VERSION 5.8 ;
BUSBITCHARS "[]" ;
DIVIDERCHAR "/" ;
UNITS
    DATABASE MICRONS 1000 ;
END UNITS

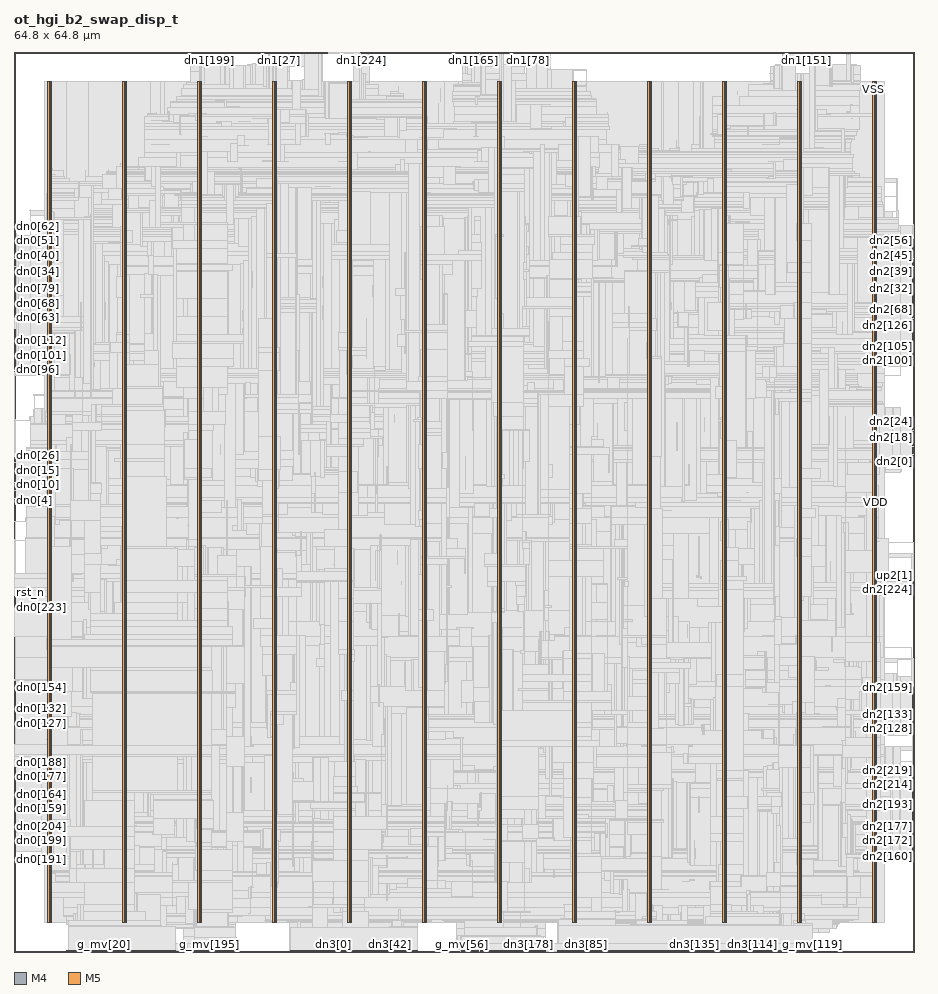
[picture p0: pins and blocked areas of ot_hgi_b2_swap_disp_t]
MACRO ot_hgi_b2_swap_disp_t
  FOREIGN ot_hgi_b2_swap_disp_t 0 0 ;
  CLASS BLOCK ;
  SIZE 64.8 BY 64.8 ;
  PIN clk
    DIRECTION INPUT ;
    USE SIGNAL ;
    PORT
      LAYER M4 ;
        RECT  0 32.592 0.084 32.616 ;
    END
  END clk
  PIN dn0[0]
    DIRECTION OUTPUT ;
    USE SIGNAL ;
    PORT
      LAYER M4 ;
        RECT  0 32.688 0.084 32.712 ;
    END
  END dn0[0]
  PIN dn0[100]
    DIRECTION OUTPUT ;
    USE SIGNAL ;
    PORT
      LAYER M4 ;
        RECT  0 42.288 0.084 42.312 ;
    END
  END dn0[100]
  PIN dn0[101]
    DIRECTION OUTPUT ;
    USE SIGNAL ;
    PORT
      LAYER M4 ;
        RECT  0 42.384 0.084 42.408 ;
    END
  END dn0[101]
  PIN dn0[102]
    DIRECTION OUTPUT ;
    USE SIGNAL ;
    PORT
      LAYER M4 ;
        RECT  0 42.48 0.084 42.504 ;
    END
  END dn0[102]
  PIN dn0[103]
    DIRECTION OUTPUT ;
    USE SIGNAL ;
    PORT
      LAYER M4 ;
        RECT  0 42.576 0.084 42.6 ;
    END
  END dn0[103]
  PIN dn0[104]
    DIRECTION OUTPUT ;
    USE SIGNAL ;
    PORT
      LAYER M4 ;
        RECT  0 42.672 0.084 42.696 ;
    END
  END dn0[104]
  PIN dn0[105]
    DIRECTION OUTPUT ;
    USE SIGNAL ;
    PORT
      LAYER M4 ;
        RECT  0 42.768 0.084 42.792 ;
    END
  END dn0[105]
  PIN dn0[106]
    DIRECTION OUTPUT ;
    USE SIGNAL ;
    PORT
      LAYER M4 ;
        RECT  0 42.864 0.084 42.888 ;
    END
  END dn0[106]
  PIN dn0[107]
    DIRECTION OUTPUT ;
    USE SIGNAL ;
    PORT
      LAYER M4 ;
        RECT  0 42.96 0.084 42.984 ;
    END
  END dn0[107]
  PIN dn0[108]
    DIRECTION OUTPUT ;
    USE SIGNAL ;
    PORT
      LAYER M4 ;
        RECT  0 43.056 0.084 43.08 ;
    END
  END dn0[108]
  PIN dn0[109]
    DIRECTION OUTPUT ;
    USE SIGNAL ;
    PORT
      LAYER M4 ;
        RECT  0 43.152 0.084 43.176 ;
    END
  END dn0[109]
  PIN dn0[10]
    DIRECTION OUTPUT ;
    USE SIGNAL ;
    PORT
      LAYER M4 ;
        RECT  0 33.648 0.084 33.672 ;
    END
  END dn0[10]
  PIN dn0[110]
    DIRECTION OUTPUT ;
    USE SIGNAL ;
    PORT
      LAYER M4 ;
        RECT  0 43.248 0.084 43.272 ;
    END
  END dn0[110]
  PIN dn0[111]
    DIRECTION OUTPUT ;
    USE SIGNAL ;
    PORT
      LAYER M4 ;
        RECT  0 43.344 0.084 43.368 ;
    END
  END dn0[111]
  PIN dn0[112]
    DIRECTION OUTPUT ;
    USE SIGNAL ;
    PORT
      LAYER M4 ;
        RECT  0 43.44 0.084 43.464 ;
    END
  END dn0[112]
  PIN dn0[113]
    DIRECTION OUTPUT ;
    USE SIGNAL ;
    PORT
      LAYER M4 ;
        RECT  0 43.536 0.084 43.56 ;
    END
  END dn0[113]
  PIN dn0[114]
    DIRECTION OUTPUT ;
    USE SIGNAL ;
    PORT
      LAYER M4 ;
        RECT  0 43.632 0.084 43.656 ;
    END
  END dn0[114]
  PIN dn0[115]
    DIRECTION OUTPUT ;
    USE SIGNAL ;
    PORT
      LAYER M4 ;
        RECT  0 43.728 0.084 43.752 ;
    END
  END dn0[115]
  PIN dn0[116]
    DIRECTION OUTPUT ;
    USE SIGNAL ;
    PORT
      LAYER M4 ;
        RECT  0 43.824 0.084 43.848 ;
    END
  END dn0[116]
  PIN dn0[117]
    DIRECTION OUTPUT ;
    USE SIGNAL ;
    PORT
      LAYER M4 ;
        RECT  0 43.92 0.084 43.944 ;
    END
  END dn0[117]
  PIN dn0[118]
    DIRECTION OUTPUT ;
    USE SIGNAL ;
    PORT
      LAYER M4 ;
        RECT  0 44.016 0.084 44.04 ;
    END
  END dn0[118]
  PIN dn0[119]
    DIRECTION OUTPUT ;
    USE SIGNAL ;
    PORT
      LAYER M4 ;
        RECT  0 44.112 0.084 44.136 ;
    END
  END dn0[119]
  PIN dn0[11]
    DIRECTION OUTPUT ;
    USE SIGNAL ;
    PORT
      LAYER M4 ;
        RECT  0 33.744 0.084 33.768 ;
    END
  END dn0[11]
  PIN dn0[120]
    DIRECTION OUTPUT ;
    USE SIGNAL ;
    PORT
      LAYER M4 ;
        RECT  0 44.208 0.084 44.232 ;
    END
  END dn0[120]
  PIN dn0[121]
    DIRECTION OUTPUT ;
    USE SIGNAL ;
    PORT
      LAYER M4 ;
        RECT  0 44.304 0.084 44.328 ;
    END
  END dn0[121]
  PIN dn0[122]
    DIRECTION OUTPUT ;
    USE SIGNAL ;
    PORT
      LAYER M4 ;
        RECT  0 44.4 0.084 44.424 ;
    END
  END dn0[122]
  PIN dn0[123]
    DIRECTION OUTPUT ;
    USE SIGNAL ;
    PORT
      LAYER M4 ;
        RECT  0 44.496 0.084 44.52 ;
    END
  END dn0[123]
  PIN dn0[124]
    DIRECTION OUTPUT ;
    USE SIGNAL ;
    PORT
      LAYER M4 ;
        RECT  0 44.592 0.084 44.616 ;
    END
  END dn0[124]
  PIN dn0[125]
    DIRECTION OUTPUT ;
    USE SIGNAL ;
    PORT
      LAYER M4 ;
        RECT  0 44.688 0.084 44.712 ;
    END
  END dn0[125]
  PIN dn0[126]
    DIRECTION OUTPUT ;
    USE SIGNAL ;
    PORT
      LAYER M4 ;
        RECT  0 44.784 0.084 44.808 ;
    END
  END dn0[126]
  PIN dn0[127]
    DIRECTION OUTPUT ;
    USE SIGNAL ;
    PORT
      LAYER M4 ;
        RECT  0 16.464 0.084 16.488 ;
    END
  END dn0[127]
  PIN dn0[128]
    DIRECTION OUTPUT ;
    USE SIGNAL ;
    PORT
      LAYER M4 ;
        RECT  0 16.56 0.084 16.584 ;
    END
  END dn0[128]
  PIN dn0[129]
    DIRECTION OUTPUT ;
    USE SIGNAL ;
    PORT
      LAYER M4 ;
        RECT  0 16.656 0.084 16.68 ;
    END
  END dn0[129]
  PIN dn0[12]
    DIRECTION OUTPUT ;
    USE SIGNAL ;
    PORT
      LAYER M4 ;
        RECT  0 33.84 0.084 33.864 ;
    END
  END dn0[12]
  PIN dn0[130]
    DIRECTION OUTPUT ;
    USE SIGNAL ;
    PORT
      LAYER M4 ;
        RECT  0 16.752 0.084 16.776 ;
    END
  END dn0[130]
  PIN dn0[131]
    DIRECTION OUTPUT ;
    USE SIGNAL ;
    PORT
      LAYER M4 ;
        RECT  0 16.848 0.084 16.872 ;
    END
  END dn0[131]
  PIN dn0[132]
    DIRECTION OUTPUT ;
    USE SIGNAL ;
    PORT
      LAYER M4 ;
        RECT  0 16.944 0.084 16.968 ;
    END
  END dn0[132]
  PIN dn0[133]
    DIRECTION OUTPUT ;
    USE SIGNAL ;
    PORT
      LAYER M4 ;
        RECT  0 17.04 0.084 17.064 ;
    END
  END dn0[133]
  PIN dn0[134]
    DIRECTION OUTPUT ;
    USE SIGNAL ;
    PORT
      LAYER M4 ;
        RECT  0 17.136 0.084 17.16 ;
    END
  END dn0[134]
  PIN dn0[135]
    DIRECTION OUTPUT ;
    USE SIGNAL ;
    PORT
      LAYER M4 ;
        RECT  0 17.232 0.084 17.256 ;
    END
  END dn0[135]
  PIN dn0[136]
    DIRECTION OUTPUT ;
    USE SIGNAL ;
    PORT
      LAYER M4 ;
        RECT  0 17.328 0.084 17.352 ;
    END
  END dn0[136]
  PIN dn0[137]
    DIRECTION OUTPUT ;
    USE SIGNAL ;
    PORT
      LAYER M4 ;
        RECT  0 17.424 0.084 17.448 ;
    END
  END dn0[137]
  PIN dn0[138]
    DIRECTION OUTPUT ;
    USE SIGNAL ;
    PORT
      LAYER M4 ;
        RECT  0 17.52 0.084 17.544 ;
    END
  END dn0[138]
  PIN dn0[139]
    DIRECTION OUTPUT ;
    USE SIGNAL ;
    PORT
      LAYER M4 ;
        RECT  0 17.616 0.084 17.64 ;
    END
  END dn0[139]
  PIN dn0[13]
    DIRECTION OUTPUT ;
    USE SIGNAL ;
    PORT
      LAYER M4 ;
        RECT  0 33.936 0.084 33.96 ;
    END
  END dn0[13]
  PIN dn0[140]
    DIRECTION OUTPUT ;
    USE SIGNAL ;
    PORT
      LAYER M4 ;
        RECT  0 17.712 0.084 17.736 ;
    END
  END dn0[140]
  PIN dn0[141]
    DIRECTION OUTPUT ;
    USE SIGNAL ;
    PORT
      LAYER M4 ;
        RECT  0 17.808 0.084 17.832 ;
    END
  END dn0[141]
  PIN dn0[142]
    DIRECTION OUTPUT ;
    USE SIGNAL ;
    PORT
      LAYER M4 ;
        RECT  0 17.904 0.084 17.928 ;
    END
  END dn0[142]
  PIN dn0[143]
    DIRECTION OUTPUT ;
    USE SIGNAL ;
    PORT
      LAYER M4 ;
        RECT  0 18 0.084 18.024 ;
    END
  END dn0[143]
  PIN dn0[144]
    DIRECTION OUTPUT ;
    USE SIGNAL ;
    PORT
      LAYER M4 ;
        RECT  0 18.096 0.084 18.12 ;
    END
  END dn0[144]
  PIN dn0[145]
    DIRECTION OUTPUT ;
    USE SIGNAL ;
    PORT
      LAYER M4 ;
        RECT  0 18.192 0.084 18.216 ;
    END
  END dn0[145]
  PIN dn0[146]
    DIRECTION OUTPUT ;
    USE SIGNAL ;
    PORT
      LAYER M4 ;
        RECT  0 18.288 0.084 18.312 ;
    END
  END dn0[146]
  PIN dn0[147]
    DIRECTION OUTPUT ;
    USE SIGNAL ;
    PORT
      LAYER M4 ;
        RECT  0 18.384 0.084 18.408 ;
    END
  END dn0[147]
  PIN dn0[148]
    DIRECTION OUTPUT ;
    USE SIGNAL ;
    PORT
      LAYER M4 ;
        RECT  0 18.48 0.084 18.504 ;
    END
  END dn0[148]
  PIN dn0[149]
    DIRECTION OUTPUT ;
    USE SIGNAL ;
    PORT
      LAYER M4 ;
        RECT  0 18.576 0.084 18.6 ;
    END
  END dn0[149]
  PIN dn0[14]
    DIRECTION OUTPUT ;
    USE SIGNAL ;
    PORT
      LAYER M4 ;
        RECT  0 34.032 0.084 34.056 ;
    END
  END dn0[14]
  PIN dn0[150]
    DIRECTION OUTPUT ;
    USE SIGNAL ;
    PORT
      LAYER M4 ;
        RECT  0 18.672 0.084 18.696 ;
    END
  END dn0[150]
  PIN dn0[151]
    DIRECTION OUTPUT ;
    USE SIGNAL ;
    PORT
      LAYER M4 ;
        RECT  0 18.768 0.084 18.792 ;
    END
  END dn0[151]
  PIN dn0[152]
    DIRECTION OUTPUT ;
    USE SIGNAL ;
    PORT
      LAYER M4 ;
        RECT  0 18.864 0.084 18.888 ;
    END
  END dn0[152]
  PIN dn0[153]
    DIRECTION OUTPUT ;
    USE SIGNAL ;
    PORT
      LAYER M4 ;
        RECT  0 18.96 0.084 18.984 ;
    END
  END dn0[153]
  PIN dn0[154]
    DIRECTION OUTPUT ;
    USE SIGNAL ;
    PORT
      LAYER M4 ;
        RECT  0 19.056 0.084 19.08 ;
    END
  END dn0[154]
  PIN dn0[155]
    DIRECTION OUTPUT ;
    USE SIGNAL ;
    PORT
      LAYER M4 ;
        RECT  0 19.152 0.084 19.176 ;
    END
  END dn0[155]
  PIN dn0[156]
    DIRECTION OUTPUT ;
    USE SIGNAL ;
    PORT
      LAYER M4 ;
        RECT  0 19.248 0.084 19.272 ;
    END
  END dn0[156]
  PIN dn0[157]
    DIRECTION OUTPUT ;
    USE SIGNAL ;
    PORT
      LAYER M4 ;
        RECT  0 19.344 0.084 19.368 ;
    END
  END dn0[157]
  PIN dn0[158]
    DIRECTION OUTPUT ;
    USE SIGNAL ;
    PORT
      LAYER M4 ;
        RECT  0 19.44 0.084 19.464 ;
    END
  END dn0[158]
  PIN dn0[159]
    DIRECTION OUTPUT ;
    USE SIGNAL ;
    PORT
      LAYER M4 ;
        RECT  0 10.32 0.084 10.344 ;
    END
  END dn0[159]
  PIN dn0[15]
    DIRECTION OUTPUT ;
    USE SIGNAL ;
    PORT
      LAYER M4 ;
        RECT  0 34.128 0.084 34.152 ;
    END
  END dn0[15]
  PIN dn0[160]
    DIRECTION OUTPUT ;
    USE SIGNAL ;
    PORT
      LAYER M4 ;
        RECT  0 10.416 0.084 10.44 ;
    END
  END dn0[160]
  PIN dn0[161]
    DIRECTION OUTPUT ;
    USE SIGNAL ;
    PORT
      LAYER M4 ;
        RECT  0 10.512 0.084 10.536 ;
    END
  END dn0[161]
  PIN dn0[162]
    DIRECTION OUTPUT ;
    USE SIGNAL ;
    PORT
      LAYER M4 ;
        RECT  0 10.608 0.084 10.632 ;
    END
  END dn0[162]
  PIN dn0[163]
    DIRECTION OUTPUT ;
    USE SIGNAL ;
    PORT
      LAYER M4 ;
        RECT  0 10.704 0.084 10.728 ;
    END
  END dn0[163]
  PIN dn0[164]
    DIRECTION OUTPUT ;
    USE SIGNAL ;
    PORT
      LAYER M4 ;
        RECT  0 10.8 0.084 10.824 ;
    END
  END dn0[164]
  PIN dn0[165]
    DIRECTION OUTPUT ;
    USE SIGNAL ;
    PORT
      LAYER M4 ;
        RECT  0 10.896 0.084 10.92 ;
    END
  END dn0[165]
  PIN dn0[166]
    DIRECTION OUTPUT ;
    USE SIGNAL ;
    PORT
      LAYER M4 ;
        RECT  0 10.992 0.084 11.016 ;
    END
  END dn0[166]
  PIN dn0[167]
    DIRECTION OUTPUT ;
    USE SIGNAL ;
    PORT
      LAYER M4 ;
        RECT  0 11.088 0.084 11.112 ;
    END
  END dn0[167]
  PIN dn0[168]
    DIRECTION OUTPUT ;
    USE SIGNAL ;
    PORT
      LAYER M4 ;
        RECT  0 11.184 0.084 11.208 ;
    END
  END dn0[168]
  PIN dn0[169]
    DIRECTION OUTPUT ;
    USE SIGNAL ;
    PORT
      LAYER M4 ;
        RECT  0 11.28 0.084 11.304 ;
    END
  END dn0[169]
  PIN dn0[16]
    DIRECTION OUTPUT ;
    USE SIGNAL ;
    PORT
      LAYER M4 ;
        RECT  0 34.224 0.084 34.248 ;
    END
  END dn0[16]
  PIN dn0[170]
    DIRECTION OUTPUT ;
    USE SIGNAL ;
    PORT
      LAYER M4 ;
        RECT  0 11.376 0.084 11.4 ;
    END
  END dn0[170]
  PIN dn0[171]
    DIRECTION OUTPUT ;
    USE SIGNAL ;
    PORT
      LAYER M4 ;
        RECT  0 11.472 0.084 11.496 ;
    END
  END dn0[171]
  PIN dn0[172]
    DIRECTION OUTPUT ;
    USE SIGNAL ;
    PORT
      LAYER M4 ;
        RECT  0 11.568 0.084 11.592 ;
    END
  END dn0[172]
  PIN dn0[173]
    DIRECTION OUTPUT ;
    USE SIGNAL ;
    PORT
      LAYER M4 ;
        RECT  0 11.664 0.084 11.688 ;
    END
  END dn0[173]
  PIN dn0[174]
    DIRECTION OUTPUT ;
    USE SIGNAL ;
    PORT
      LAYER M4 ;
        RECT  0 11.76 0.084 11.784 ;
    END
  END dn0[174]
  PIN dn0[175]
    DIRECTION OUTPUT ;
    USE SIGNAL ;
    PORT
      LAYER M4 ;
        RECT  0 11.856 0.084 11.88 ;
    END
  END dn0[175]
  PIN dn0[176]
    DIRECTION OUTPUT ;
    USE SIGNAL ;
    PORT
      LAYER M4 ;
        RECT  0 11.952 0.084 11.976 ;
    END
  END dn0[176]
  PIN dn0[177]
    DIRECTION OUTPUT ;
    USE SIGNAL ;
    PORT
      LAYER M4 ;
        RECT  0 12.048 0.084 12.072 ;
    END
  END dn0[177]
  PIN dn0[178]
    DIRECTION OUTPUT ;
    USE SIGNAL ;
    PORT
      LAYER M4 ;
        RECT  0 12.144 0.084 12.168 ;
    END
  END dn0[178]
  PIN dn0[179]
    DIRECTION OUTPUT ;
    USE SIGNAL ;
    PORT
      LAYER M4 ;
        RECT  0 12.24 0.084 12.264 ;
    END
  END dn0[179]
  PIN dn0[17]
    DIRECTION OUTPUT ;
    USE SIGNAL ;
    PORT
      LAYER M4 ;
        RECT  0 34.32 0.084 34.344 ;
    END
  END dn0[17]
  PIN dn0[180]
    DIRECTION OUTPUT ;
    USE SIGNAL ;
    PORT
      LAYER M4 ;
        RECT  0 12.336 0.084 12.36 ;
    END
  END dn0[180]
  PIN dn0[181]
    DIRECTION OUTPUT ;
    USE SIGNAL ;
    PORT
      LAYER M4 ;
        RECT  0 12.432 0.084 12.456 ;
    END
  END dn0[181]
  PIN dn0[182]
    DIRECTION OUTPUT ;
    USE SIGNAL ;
    PORT
      LAYER M4 ;
        RECT  0 12.528 0.084 12.552 ;
    END
  END dn0[182]
  PIN dn0[183]
    DIRECTION OUTPUT ;
    USE SIGNAL ;
    PORT
      LAYER M4 ;
        RECT  0 12.624 0.084 12.648 ;
    END
  END dn0[183]
  PIN dn0[184]
    DIRECTION OUTPUT ;
    USE SIGNAL ;
    PORT
      LAYER M4 ;
        RECT  0 12.72 0.084 12.744 ;
    END
  END dn0[184]
  PIN dn0[185]
    DIRECTION OUTPUT ;
    USE SIGNAL ;
    PORT
      LAYER M4 ;
        RECT  0 12.816 0.084 12.84 ;
    END
  END dn0[185]
  PIN dn0[186]
    DIRECTION OUTPUT ;
    USE SIGNAL ;
    PORT
      LAYER M4 ;
        RECT  0 12.912 0.084 12.936 ;
    END
  END dn0[186]
  PIN dn0[187]
    DIRECTION OUTPUT ;
    USE SIGNAL ;
    PORT
      LAYER M4 ;
        RECT  0 13.008 0.084 13.032 ;
    END
  END dn0[187]
  PIN dn0[188]
    DIRECTION OUTPUT ;
    USE SIGNAL ;
    PORT
      LAYER M4 ;
        RECT  0 13.104 0.084 13.128 ;
    END
  END dn0[188]
  PIN dn0[189]
    DIRECTION OUTPUT ;
    USE SIGNAL ;
    PORT
      LAYER M4 ;
        RECT  0 13.2 0.084 13.224 ;
    END
  END dn0[189]
  PIN dn0[18]
    DIRECTION OUTPUT ;
    USE SIGNAL ;
    PORT
      LAYER M4 ;
        RECT  0 34.416 0.084 34.44 ;
    END
  END dn0[18]
  PIN dn0[190]
    DIRECTION OUTPUT ;
    USE SIGNAL ;
    PORT
      LAYER M4 ;
        RECT  0 13.296 0.084 13.32 ;
    END
  END dn0[190]
  PIN dn0[191]
    DIRECTION OUTPUT ;
    USE SIGNAL ;
    PORT
      LAYER M4 ;
        RECT  0 7.248 0.084 7.272 ;
    END
  END dn0[191]
  PIN dn0[192]
    DIRECTION OUTPUT ;
    USE SIGNAL ;
    PORT
      LAYER M4 ;
        RECT  0 7.344 0.084 7.368 ;
    END
  END dn0[192]
  PIN dn0[193]
    DIRECTION OUTPUT ;
    USE SIGNAL ;
    PORT
      LAYER M4 ;
        RECT  0 7.44 0.084 7.464 ;
    END
  END dn0[193]
  PIN dn0[194]
    DIRECTION OUTPUT ;
    USE SIGNAL ;
    PORT
      LAYER M4 ;
        RECT  0 7.536 0.084 7.56 ;
    END
  END dn0[194]
  PIN dn0[195]
    DIRECTION OUTPUT ;
    USE SIGNAL ;
    PORT
      LAYER M4 ;
        RECT  0 7.632 0.084 7.656 ;
    END
  END dn0[195]
  PIN dn0[196]
    DIRECTION OUTPUT ;
    USE SIGNAL ;
    PORT
      LAYER M4 ;
        RECT  0 7.728 0.084 7.752 ;
    END
  END dn0[196]
  PIN dn0[197]
    DIRECTION OUTPUT ;
    USE SIGNAL ;
    PORT
      LAYER M4 ;
        RECT  0 7.824 0.084 7.848 ;
    END
  END dn0[197]
  PIN dn0[198]
    DIRECTION OUTPUT ;
    USE SIGNAL ;
    PORT
      LAYER M4 ;
        RECT  0 7.92 0.084 7.944 ;
    END
  END dn0[198]
  PIN dn0[199]
    DIRECTION OUTPUT ;
    USE SIGNAL ;
    PORT
      LAYER M4 ;
        RECT  0 8.016 0.084 8.04 ;
    END
  END dn0[199]
  PIN dn0[19]
    DIRECTION OUTPUT ;
    USE SIGNAL ;
    PORT
      LAYER M4 ;
        RECT  0 34.512 0.084 34.536 ;
    END
  END dn0[19]
  PIN dn0[1]
    DIRECTION OUTPUT ;
    USE SIGNAL ;
    PORT
      LAYER M4 ;
        RECT  0 32.784 0.084 32.808 ;
    END
  END dn0[1]
  PIN dn0[200]
    DIRECTION OUTPUT ;
    USE SIGNAL ;
    PORT
      LAYER M4 ;
        RECT  0 8.112 0.084 8.136 ;
    END
  END dn0[200]
  PIN dn0[201]
    DIRECTION OUTPUT ;
    USE SIGNAL ;
    PORT
      LAYER M4 ;
        RECT  0 8.208 0.084 8.232 ;
    END
  END dn0[201]
  PIN dn0[202]
    DIRECTION OUTPUT ;
    USE SIGNAL ;
    PORT
      LAYER M4 ;
        RECT  0 8.304 0.084 8.328 ;
    END
  END dn0[202]
  PIN dn0[203]
    DIRECTION OUTPUT ;
    USE SIGNAL ;
    PORT
      LAYER M4 ;
        RECT  0 8.4 0.084 8.424 ;
    END
  END dn0[203]
  PIN dn0[204]
    DIRECTION OUTPUT ;
    USE SIGNAL ;
    PORT
      LAYER M4 ;
        RECT  0 8.496 0.084 8.52 ;
    END
  END dn0[204]
  PIN dn0[205]
    DIRECTION OUTPUT ;
    USE SIGNAL ;
    PORT
      LAYER M4 ;
        RECT  0 8.592 0.084 8.616 ;
    END
  END dn0[205]
  PIN dn0[206]
    DIRECTION OUTPUT ;
    USE SIGNAL ;
    PORT
      LAYER M4 ;
        RECT  0 8.688 0.084 8.712 ;
    END
  END dn0[206]
  PIN dn0[207]
    DIRECTION OUTPUT ;
    USE SIGNAL ;
    PORT
      LAYER M4 ;
        RECT  0 8.784 0.084 8.808 ;
    END
  END dn0[207]
  PIN dn0[208]
    DIRECTION OUTPUT ;
    USE SIGNAL ;
    PORT
      LAYER M4 ;
        RECT  0 8.88 0.084 8.904 ;
    END
  END dn0[208]
  PIN dn0[209]
    DIRECTION OUTPUT ;
    USE SIGNAL ;
    PORT
      LAYER M4 ;
        RECT  0 8.976 0.084 9 ;
    END
  END dn0[209]
  PIN dn0[20]
    DIRECTION OUTPUT ;
    USE SIGNAL ;
    PORT
      LAYER M4 ;
        RECT  0 34.608 0.084 34.632 ;
    END
  END dn0[20]
  PIN dn0[210]
    DIRECTION OUTPUT ;
    USE SIGNAL ;
    PORT
      LAYER M4 ;
        RECT  0 9.072 0.084 9.096 ;
    END
  END dn0[210]
  PIN dn0[211]
    DIRECTION OUTPUT ;
    USE SIGNAL ;
    PORT
      LAYER M4 ;
        RECT  0 9.168 0.084 9.192 ;
    END
  END dn0[211]
  PIN dn0[212]
    DIRECTION OUTPUT ;
    USE SIGNAL ;
    PORT
      LAYER M4 ;
        RECT  0 9.264 0.084 9.288 ;
    END
  END dn0[212]
  PIN dn0[213]
    DIRECTION OUTPUT ;
    USE SIGNAL ;
    PORT
      LAYER M4 ;
        RECT  0 9.36 0.084 9.384 ;
    END
  END dn0[213]
  PIN dn0[214]
    DIRECTION OUTPUT ;
    USE SIGNAL ;
    PORT
      LAYER M4 ;
        RECT  0 9.456 0.084 9.48 ;
    END
  END dn0[214]
  PIN dn0[215]
    DIRECTION OUTPUT ;
    USE SIGNAL ;
    PORT
      LAYER M4 ;
        RECT  0 9.552 0.084 9.576 ;
    END
  END dn0[215]
  PIN dn0[216]
    DIRECTION OUTPUT ;
    USE SIGNAL ;
    PORT
      LAYER M4 ;
        RECT  0 9.648 0.084 9.672 ;
    END
  END dn0[216]
  PIN dn0[217]
    DIRECTION OUTPUT ;
    USE SIGNAL ;
    PORT
      LAYER M4 ;
        RECT  0 9.744 0.084 9.768 ;
    END
  END dn0[217]
  PIN dn0[218]
    DIRECTION OUTPUT ;
    USE SIGNAL ;
    PORT
      LAYER M4 ;
        RECT  0 9.84 0.084 9.864 ;
    END
  END dn0[218]
  PIN dn0[219]
    DIRECTION OUTPUT ;
    USE SIGNAL ;
    PORT
      LAYER M4 ;
        RECT  0 9.936 0.084 9.96 ;
    END
  END dn0[219]
  PIN dn0[21]
    DIRECTION OUTPUT ;
    USE SIGNAL ;
    PORT
      LAYER M4 ;
        RECT  0 34.704 0.084 34.728 ;
    END
  END dn0[21]
  PIN dn0[220]
    DIRECTION OUTPUT ;
    USE SIGNAL ;
    PORT
      LAYER M4 ;
        RECT  0 10.032 0.084 10.056 ;
    END
  END dn0[220]
  PIN dn0[221]
    DIRECTION OUTPUT ;
    USE SIGNAL ;
    PORT
      LAYER M4 ;
        RECT  0 10.128 0.084 10.152 ;
    END
  END dn0[221]
  PIN dn0[222]
    DIRECTION OUTPUT ;
    USE SIGNAL ;
    PORT
      LAYER M4 ;
        RECT  0 10.224 0.084 10.248 ;
    END
  END dn0[222]
  PIN dn0[223]
    DIRECTION OUTPUT ;
    USE SIGNAL ;
    PORT
      LAYER M4 ;
        RECT  0 24.816 0.084 24.84 ;
    END
  END dn0[223]
  PIN dn0[224]
    DIRECTION OUTPUT ;
    USE SIGNAL ;
    PORT
      LAYER M4 ;
        RECT  0 24.912 0.084 24.936 ;
    END
  END dn0[224]
  PIN dn0[225]
    DIRECTION OUTPUT ;
    USE SIGNAL ;
    PORT
      LAYER M4 ;
        RECT  0 25.008 0.084 25.032 ;
    END
  END dn0[225]
  PIN dn0[226]
    DIRECTION OUTPUT ;
    USE SIGNAL ;
    PORT
      LAYER M4 ;
        RECT  0 25.104 0.084 25.128 ;
    END
  END dn0[226]
  PIN dn0[227]
    DIRECTION OUTPUT ;
    USE SIGNAL ;
    PORT
      LAYER M4 ;
        RECT  0 25.2 0.084 25.224 ;
    END
  END dn0[227]
  PIN dn0[22]
    DIRECTION OUTPUT ;
    USE SIGNAL ;
    PORT
      LAYER M4 ;
        RECT  0 34.8 0.084 34.824 ;
    END
  END dn0[22]
  PIN dn0[23]
    DIRECTION OUTPUT ;
    USE SIGNAL ;
    PORT
      LAYER M4 ;
        RECT  0 34.896 0.084 34.92 ;
    END
  END dn0[23]
  PIN dn0[24]
    DIRECTION OUTPUT ;
    USE SIGNAL ;
    PORT
      LAYER M4 ;
        RECT  0 34.992 0.084 35.016 ;
    END
  END dn0[24]
  PIN dn0[25]
    DIRECTION OUTPUT ;
    USE SIGNAL ;
    PORT
      LAYER M4 ;
        RECT  0 35.088 0.084 35.112 ;
    END
  END dn0[25]
  PIN dn0[26]
    DIRECTION OUTPUT ;
    USE SIGNAL ;
    PORT
      LAYER M4 ;
        RECT  0 35.184 0.084 35.208 ;
    END
  END dn0[26]
  PIN dn0[27]
    DIRECTION OUTPUT ;
    USE SIGNAL ;
    PORT
      LAYER M4 ;
        RECT  0 35.28 0.084 35.304 ;
    END
  END dn0[27]
  PIN dn0[28]
    DIRECTION OUTPUT ;
    USE SIGNAL ;
    PORT
      LAYER M4 ;
        RECT  0 35.376 0.084 35.4 ;
    END
  END dn0[28]
  PIN dn0[29]
    DIRECTION OUTPUT ;
    USE SIGNAL ;
    PORT
      LAYER M4 ;
        RECT  0 35.472 0.084 35.496 ;
    END
  END dn0[29]
  PIN dn0[2]
    DIRECTION OUTPUT ;
    USE SIGNAL ;
    PORT
      LAYER M4 ;
        RECT  0 32.88 0.084 32.904 ;
    END
  END dn0[2]
  PIN dn0[30]
    DIRECTION OUTPUT ;
    USE SIGNAL ;
    PORT
      LAYER M4 ;
        RECT  0 35.568 0.084 35.592 ;
    END
  END dn0[30]
  PIN dn0[31]
    DIRECTION OUTPUT ;
    USE SIGNAL ;
    PORT
      LAYER M4 ;
        RECT  0 48.72 0.084 48.744 ;
    END
  END dn0[31]
  PIN dn0[32]
    DIRECTION OUTPUT ;
    USE SIGNAL ;
    PORT
      LAYER M4 ;
        RECT  0 48.816 0.084 48.84 ;
    END
  END dn0[32]
  PIN dn0[33]
    DIRECTION OUTPUT ;
    USE SIGNAL ;
    PORT
      LAYER M4 ;
        RECT  0 48.912 0.084 48.936 ;
    END
  END dn0[33]
  PIN dn0[34]
    DIRECTION OUTPUT ;
    USE SIGNAL ;
    PORT
      LAYER M4 ;
        RECT  0 49.008 0.084 49.032 ;
    END
  END dn0[34]
  PIN dn0[35]
    DIRECTION OUTPUT ;
    USE SIGNAL ;
    PORT
      LAYER M4 ;
        RECT  0 49.104 0.084 49.128 ;
    END
  END dn0[35]
  PIN dn0[36]
    DIRECTION OUTPUT ;
    USE SIGNAL ;
    PORT
      LAYER M4 ;
        RECT  0 49.2 0.084 49.224 ;
    END
  END dn0[36]
  PIN dn0[37]
    DIRECTION OUTPUT ;
    USE SIGNAL ;
    PORT
      LAYER M4 ;
        RECT  0 49.296 0.084 49.32 ;
    END
  END dn0[37]
  PIN dn0[38]
    DIRECTION OUTPUT ;
    USE SIGNAL ;
    PORT
      LAYER M4 ;
        RECT  0 49.392 0.084 49.416 ;
    END
  END dn0[38]
  PIN dn0[39]
    DIRECTION OUTPUT ;
    USE SIGNAL ;
    PORT
      LAYER M4 ;
        RECT  0 49.488 0.084 49.512 ;
    END
  END dn0[39]
  PIN dn0[3]
    DIRECTION OUTPUT ;
    USE SIGNAL ;
    PORT
      LAYER M4 ;
        RECT  0 32.976 0.084 33 ;
    END
  END dn0[3]
  PIN dn0[40]
    DIRECTION OUTPUT ;
    USE SIGNAL ;
    PORT
      LAYER M4 ;
        RECT  0 49.584 0.084 49.608 ;
    END
  END dn0[40]
  PIN dn0[41]
    DIRECTION OUTPUT ;
    USE SIGNAL ;
    PORT
      LAYER M4 ;
        RECT  0 49.68 0.084 49.704 ;
    END
  END dn0[41]
  PIN dn0[42]
    DIRECTION OUTPUT ;
    USE SIGNAL ;
    PORT
      LAYER M4 ;
        RECT  0 49.776 0.084 49.8 ;
    END
  END dn0[42]
  PIN dn0[43]
    DIRECTION OUTPUT ;
    USE SIGNAL ;
    PORT
      LAYER M4 ;
        RECT  0 49.872 0.084 49.896 ;
    END
  END dn0[43]
  PIN dn0[44]
    DIRECTION OUTPUT ;
    USE SIGNAL ;
    PORT
      LAYER M4 ;
        RECT  0 49.968 0.084 49.992 ;
    END
  END dn0[44]
  PIN dn0[45]
    DIRECTION OUTPUT ;
    USE SIGNAL ;
    PORT
      LAYER M4 ;
        RECT  0 50.064 0.084 50.088 ;
    END
  END dn0[45]
  PIN dn0[46]
    DIRECTION OUTPUT ;
    USE SIGNAL ;
    PORT
      LAYER M4 ;
        RECT  0 50.16 0.084 50.184 ;
    END
  END dn0[46]
  PIN dn0[47]
    DIRECTION OUTPUT ;
    USE SIGNAL ;
    PORT
      LAYER M4 ;
        RECT  0 50.256 0.084 50.28 ;
    END
  END dn0[47]
  PIN dn0[48]
    DIRECTION OUTPUT ;
    USE SIGNAL ;
    PORT
      LAYER M4 ;
        RECT  0 50.352 0.084 50.376 ;
    END
  END dn0[48]
  PIN dn0[49]
    DIRECTION OUTPUT ;
    USE SIGNAL ;
    PORT
      LAYER M4 ;
        RECT  0 50.448 0.084 50.472 ;
    END
  END dn0[49]
  PIN dn0[4]
    DIRECTION OUTPUT ;
    USE SIGNAL ;
    PORT
      LAYER M4 ;
        RECT  0 33.072 0.084 33.096 ;
    END
  END dn0[4]
  PIN dn0[50]
    DIRECTION OUTPUT ;
    USE SIGNAL ;
    PORT
      LAYER M4 ;
        RECT  0 50.544 0.084 50.568 ;
    END
  END dn0[50]
  PIN dn0[51]
    DIRECTION OUTPUT ;
    USE SIGNAL ;
    PORT
      LAYER M4 ;
        RECT  0 50.64 0.084 50.664 ;
    END
  END dn0[51]
  PIN dn0[52]
    DIRECTION OUTPUT ;
    USE SIGNAL ;
    PORT
      LAYER M4 ;
        RECT  0 50.736 0.084 50.76 ;
    END
  END dn0[52]
  PIN dn0[53]
    DIRECTION OUTPUT ;
    USE SIGNAL ;
    PORT
      LAYER M4 ;
        RECT  0 50.832 0.084 50.856 ;
    END
  END dn0[53]
  PIN dn0[54]
    DIRECTION OUTPUT ;
    USE SIGNAL ;
    PORT
      LAYER M4 ;
        RECT  0 50.928 0.084 50.952 ;
    END
  END dn0[54]
  PIN dn0[55]
    DIRECTION OUTPUT ;
    USE SIGNAL ;
    PORT
      LAYER M4 ;
        RECT  0 51.024 0.084 51.048 ;
    END
  END dn0[55]
  PIN dn0[56]
    DIRECTION OUTPUT ;
    USE SIGNAL ;
    PORT
      LAYER M4 ;
        RECT  0 51.12 0.084 51.144 ;
    END
  END dn0[56]
  PIN dn0[57]
    DIRECTION OUTPUT ;
    USE SIGNAL ;
    PORT
      LAYER M4 ;
        RECT  0 51.216 0.084 51.24 ;
    END
  END dn0[57]
  PIN dn0[58]
    DIRECTION OUTPUT ;
    USE SIGNAL ;
    PORT
      LAYER M4 ;
        RECT  0 51.312 0.084 51.336 ;
    END
  END dn0[58]
  PIN dn0[59]
    DIRECTION OUTPUT ;
    USE SIGNAL ;
    PORT
      LAYER M4 ;
        RECT  0 51.408 0.084 51.432 ;
    END
  END dn0[59]
  PIN dn0[5]
    DIRECTION OUTPUT ;
    USE SIGNAL ;
    PORT
      LAYER M4 ;
        RECT  0 33.168 0.084 33.192 ;
    END
  END dn0[5]
  PIN dn0[60]
    DIRECTION OUTPUT ;
    USE SIGNAL ;
    PORT
      LAYER M4 ;
        RECT  0 51.504 0.084 51.528 ;
    END
  END dn0[60]
  PIN dn0[61]
    DIRECTION OUTPUT ;
    USE SIGNAL ;
    PORT
      LAYER M4 ;
        RECT  0 51.6 0.084 51.624 ;
    END
  END dn0[61]
  PIN dn0[62]
    DIRECTION OUTPUT ;
    USE SIGNAL ;
    PORT
      LAYER M4 ;
        RECT  0 51.696 0.084 51.72 ;
    END
  END dn0[62]
  PIN dn0[63]
    DIRECTION OUTPUT ;
    USE SIGNAL ;
    PORT
      LAYER M4 ;
        RECT  0 45.648 0.084 45.672 ;
    END
  END dn0[63]
  PIN dn0[64]
    DIRECTION OUTPUT ;
    USE SIGNAL ;
    PORT
      LAYER M4 ;
        RECT  0 45.744 0.084 45.768 ;
    END
  END dn0[64]
  PIN dn0[65]
    DIRECTION OUTPUT ;
    USE SIGNAL ;
    PORT
      LAYER M4 ;
        RECT  0 45.84 0.084 45.864 ;
    END
  END dn0[65]
  PIN dn0[66]
    DIRECTION OUTPUT ;
    USE SIGNAL ;
    PORT
      LAYER M4 ;
        RECT  0 45.936 0.084 45.96 ;
    END
  END dn0[66]
  PIN dn0[67]
    DIRECTION OUTPUT ;
    USE SIGNAL ;
    PORT
      LAYER M4 ;
        RECT  0 46.032 0.084 46.056 ;
    END
  END dn0[67]
  PIN dn0[68]
    DIRECTION OUTPUT ;
    USE SIGNAL ;
    PORT
      LAYER M4 ;
        RECT  0 46.128 0.084 46.152 ;
    END
  END dn0[68]
  PIN dn0[69]
    DIRECTION OUTPUT ;
    USE SIGNAL ;
    PORT
      LAYER M4 ;
        RECT  0 46.224 0.084 46.248 ;
    END
  END dn0[69]
  PIN dn0[6]
    DIRECTION OUTPUT ;
    USE SIGNAL ;
    PORT
      LAYER M4 ;
        RECT  0 33.264 0.084 33.288 ;
    END
  END dn0[6]
  PIN dn0[70]
    DIRECTION OUTPUT ;
    USE SIGNAL ;
    PORT
      LAYER M4 ;
        RECT  0 46.32 0.084 46.344 ;
    END
  END dn0[70]
  PIN dn0[71]
    DIRECTION OUTPUT ;
    USE SIGNAL ;
    PORT
      LAYER M4 ;
        RECT  0 46.416 0.084 46.44 ;
    END
  END dn0[71]
  PIN dn0[72]
    DIRECTION OUTPUT ;
    USE SIGNAL ;
    PORT
      LAYER M4 ;
        RECT  0 46.512 0.084 46.536 ;
    END
  END dn0[72]
  PIN dn0[73]
    DIRECTION OUTPUT ;
    USE SIGNAL ;
    PORT
      LAYER M4 ;
        RECT  0 46.608 0.084 46.632 ;
    END
  END dn0[73]
  PIN dn0[74]
    DIRECTION OUTPUT ;
    USE SIGNAL ;
    PORT
      LAYER M4 ;
        RECT  0 46.704 0.084 46.728 ;
    END
  END dn0[74]
  PIN dn0[75]
    DIRECTION OUTPUT ;
    USE SIGNAL ;
    PORT
      LAYER M4 ;
        RECT  0 46.8 0.084 46.824 ;
    END
  END dn0[75]
  PIN dn0[76]
    DIRECTION OUTPUT ;
    USE SIGNAL ;
    PORT
      LAYER M4 ;
        RECT  0 46.896 0.084 46.92 ;
    END
  END dn0[76]
  PIN dn0[77]
    DIRECTION OUTPUT ;
    USE SIGNAL ;
    PORT
      LAYER M4 ;
        RECT  0 46.992 0.084 47.016 ;
    END
  END dn0[77]
  PIN dn0[78]
    DIRECTION OUTPUT ;
    USE SIGNAL ;
    PORT
      LAYER M4 ;
        RECT  0 47.088 0.084 47.112 ;
    END
  END dn0[78]
  PIN dn0[79]
    DIRECTION OUTPUT ;
    USE SIGNAL ;
    PORT
      LAYER M4 ;
        RECT  0 47.184 0.084 47.208 ;
    END
  END dn0[79]
  PIN dn0[7]
    DIRECTION OUTPUT ;
    USE SIGNAL ;
    PORT
      LAYER M4 ;
        RECT  0 33.36 0.084 33.384 ;
    END
  END dn0[7]
  PIN dn0[80]
    DIRECTION OUTPUT ;
    USE SIGNAL ;
    PORT
      LAYER M4 ;
        RECT  0 47.28 0.084 47.304 ;
    END
  END dn0[80]
  PIN dn0[81]
    DIRECTION OUTPUT ;
    USE SIGNAL ;
    PORT
      LAYER M4 ;
        RECT  0 47.376 0.084 47.4 ;
    END
  END dn0[81]
  PIN dn0[82]
    DIRECTION OUTPUT ;
    USE SIGNAL ;
    PORT
      LAYER M4 ;
        RECT  0 47.472 0.084 47.496 ;
    END
  END dn0[82]
  PIN dn0[83]
    DIRECTION OUTPUT ;
    USE SIGNAL ;
    PORT
      LAYER M4 ;
        RECT  0 47.568 0.084 47.592 ;
    END
  END dn0[83]
  PIN dn0[84]
    DIRECTION OUTPUT ;
    USE SIGNAL ;
    PORT
      LAYER M4 ;
        RECT  0 47.664 0.084 47.688 ;
    END
  END dn0[84]
  PIN dn0[85]
    DIRECTION OUTPUT ;
    USE SIGNAL ;
    PORT
      LAYER M4 ;
        RECT  0 47.76 0.084 47.784 ;
    END
  END dn0[85]
  PIN dn0[86]
    DIRECTION OUTPUT ;
    USE SIGNAL ;
    PORT
      LAYER M4 ;
        RECT  0 47.856 0.084 47.88 ;
    END
  END dn0[86]
  PIN dn0[87]
    DIRECTION OUTPUT ;
    USE SIGNAL ;
    PORT
      LAYER M4 ;
        RECT  0 47.952 0.084 47.976 ;
    END
  END dn0[87]
  PIN dn0[88]
    DIRECTION OUTPUT ;
    USE SIGNAL ;
    PORT
      LAYER M4 ;
        RECT  0 48.048 0.084 48.072 ;
    END
  END dn0[88]
  PIN dn0[89]
    DIRECTION OUTPUT ;
    USE SIGNAL ;
    PORT
      LAYER M4 ;
        RECT  0 48.144 0.084 48.168 ;
    END
  END dn0[89]
  PIN dn0[8]
    DIRECTION OUTPUT ;
    USE SIGNAL ;
    PORT
      LAYER M4 ;
        RECT  0 33.456 0.084 33.48 ;
    END
  END dn0[8]
  PIN dn0[90]
    DIRECTION OUTPUT ;
    USE SIGNAL ;
    PORT
      LAYER M4 ;
        RECT  0 48.24 0.084 48.264 ;
    END
  END dn0[90]
  PIN dn0[91]
    DIRECTION OUTPUT ;
    USE SIGNAL ;
    PORT
      LAYER M4 ;
        RECT  0 48.336 0.084 48.36 ;
    END
  END dn0[91]
  PIN dn0[92]
    DIRECTION OUTPUT ;
    USE SIGNAL ;
    PORT
      LAYER M4 ;
        RECT  0 48.432 0.084 48.456 ;
    END
  END dn0[92]
  PIN dn0[93]
    DIRECTION OUTPUT ;
    USE SIGNAL ;
    PORT
      LAYER M4 ;
        RECT  0 48.528 0.084 48.552 ;
    END
  END dn0[93]
  PIN dn0[94]
    DIRECTION OUTPUT ;
    USE SIGNAL ;
    PORT
      LAYER M4 ;
        RECT  0 48.624 0.084 48.648 ;
    END
  END dn0[94]
  PIN dn0[95]
    DIRECTION OUTPUT ;
    USE SIGNAL ;
    PORT
      LAYER M4 ;
        RECT  0 41.808 0.084 41.832 ;
    END
  END dn0[95]
  PIN dn0[96]
    DIRECTION OUTPUT ;
    USE SIGNAL ;
    PORT
      LAYER M4 ;
        RECT  0 41.904 0.084 41.928 ;
    END
  END dn0[96]
  PIN dn0[97]
    DIRECTION OUTPUT ;
    USE SIGNAL ;
    PORT
      LAYER M4 ;
        RECT  0 42 0.084 42.024 ;
    END
  END dn0[97]
  PIN dn0[98]
    DIRECTION OUTPUT ;
    USE SIGNAL ;
    PORT
      LAYER M4 ;
        RECT  0 42.096 0.084 42.12 ;
    END
  END dn0[98]
  PIN dn0[99]
    DIRECTION OUTPUT ;
    USE SIGNAL ;
    PORT
      LAYER M4 ;
        RECT  0 42.192 0.084 42.216 ;
    END
  END dn0[99]
  PIN dn0[9]
    DIRECTION OUTPUT ;
    USE SIGNAL ;
    PORT
      LAYER M4 ;
        RECT  0 33.552 0.084 33.576 ;
    END
  END dn0[9]
  PIN dn1[0]
    DIRECTION OUTPUT ;
    USE SIGNAL ;
    PORT
      LAYER M5 ;
        RECT  16.464 64.716 16.488 64.8 ;
    END
  END dn1[0]
  PIN dn1[100]
    DIRECTION OUTPUT ;
    USE SIGNAL ;
    PORT
      LAYER M5 ;
        RECT  58.32 64.716 58.344 64.8 ;
    END
  END dn1[100]
  PIN dn1[101]
    DIRECTION OUTPUT ;
    USE SIGNAL ;
    PORT
      LAYER M5 ;
        RECT  58.416 64.716 58.44 64.8 ;
    END
  END dn1[101]
  PIN dn1[102]
    DIRECTION OUTPUT ;
    USE SIGNAL ;
    PORT
      LAYER M5 ;
        RECT  58.512 64.716 58.536 64.8 ;
    END
  END dn1[102]
  PIN dn1[103]
    DIRECTION OUTPUT ;
    USE SIGNAL ;
    PORT
      LAYER M5 ;
        RECT  58.608 64.716 58.632 64.8 ;
    END
  END dn1[103]
  PIN dn1[104]
    DIRECTION OUTPUT ;
    USE SIGNAL ;
    PORT
      LAYER M5 ;
        RECT  58.704 64.716 58.728 64.8 ;
    END
  END dn1[104]
  PIN dn1[105]
    DIRECTION OUTPUT ;
    USE SIGNAL ;
    PORT
      LAYER M5 ;
        RECT  58.8 64.716 58.824 64.8 ;
    END
  END dn1[105]
  PIN dn1[106]
    DIRECTION OUTPUT ;
    USE SIGNAL ;
    PORT
      LAYER M5 ;
        RECT  58.896 64.716 58.92 64.8 ;
    END
  END dn1[106]
  PIN dn1[107]
    DIRECTION OUTPUT ;
    USE SIGNAL ;
    PORT
      LAYER M5 ;
        RECT  58.992 64.716 59.016 64.8 ;
    END
  END dn1[107]
  PIN dn1[108]
    DIRECTION OUTPUT ;
    USE SIGNAL ;
    PORT
      LAYER M5 ;
        RECT  59.088 64.716 59.112 64.8 ;
    END
  END dn1[108]
  PIN dn1[109]
    DIRECTION OUTPUT ;
    USE SIGNAL ;
    PORT
      LAYER M5 ;
        RECT  59.184 64.716 59.208 64.8 ;
    END
  END dn1[109]
  PIN dn1[10]
    DIRECTION OUTPUT ;
    USE SIGNAL ;
    PORT
      LAYER M5 ;
        RECT  17.424 64.716 17.448 64.8 ;
    END
  END dn1[10]
  PIN dn1[110]
    DIRECTION OUTPUT ;
    USE SIGNAL ;
    PORT
      LAYER M5 ;
        RECT  59.28 64.716 59.304 64.8 ;
    END
  END dn1[110]
  PIN dn1[111]
    DIRECTION OUTPUT ;
    USE SIGNAL ;
    PORT
      LAYER M5 ;
        RECT  59.376 64.716 59.4 64.8 ;
    END
  END dn1[111]
  PIN dn1[112]
    DIRECTION OUTPUT ;
    USE SIGNAL ;
    PORT
      LAYER M5 ;
        RECT  59.472 64.716 59.496 64.8 ;
    END
  END dn1[112]
  PIN dn1[113]
    DIRECTION OUTPUT ;
    USE SIGNAL ;
    PORT
      LAYER M5 ;
        RECT  59.568 64.716 59.592 64.8 ;
    END
  END dn1[113]
  PIN dn1[114]
    DIRECTION OUTPUT ;
    USE SIGNAL ;
    PORT
      LAYER M5 ;
        RECT  59.664 64.716 59.688 64.8 ;
    END
  END dn1[114]
  PIN dn1[115]
    DIRECTION OUTPUT ;
    USE SIGNAL ;
    PORT
      LAYER M5 ;
        RECT  59.76 64.716 59.784 64.8 ;
    END
  END dn1[115]
  PIN dn1[116]
    DIRECTION OUTPUT ;
    USE SIGNAL ;
    PORT
      LAYER M5 ;
        RECT  59.856 64.716 59.88 64.8 ;
    END
  END dn1[116]
  PIN dn1[117]
    DIRECTION OUTPUT ;
    USE SIGNAL ;
    PORT
      LAYER M5 ;
        RECT  59.952 64.716 59.976 64.8 ;
    END
  END dn1[117]
  PIN dn1[118]
    DIRECTION OUTPUT ;
    USE SIGNAL ;
    PORT
      LAYER M5 ;
        RECT  60.048 64.716 60.072 64.8 ;
    END
  END dn1[118]
  PIN dn1[119]
    DIRECTION OUTPUT ;
    USE SIGNAL ;
    PORT
      LAYER M5 ;
        RECT  60.144 64.716 60.168 64.8 ;
    END
  END dn1[119]
  PIN dn1[11]
    DIRECTION OUTPUT ;
    USE SIGNAL ;
    PORT
      LAYER M5 ;
        RECT  17.52 64.716 17.544 64.8 ;
    END
  END dn1[11]
  PIN dn1[120]
    DIRECTION OUTPUT ;
    USE SIGNAL ;
    PORT
      LAYER M5 ;
        RECT  60.24 64.716 60.264 64.8 ;
    END
  END dn1[120]
  PIN dn1[121]
    DIRECTION OUTPUT ;
    USE SIGNAL ;
    PORT
      LAYER M5 ;
        RECT  60.336 64.716 60.36 64.8 ;
    END
  END dn1[121]
  PIN dn1[122]
    DIRECTION OUTPUT ;
    USE SIGNAL ;
    PORT
      LAYER M5 ;
        RECT  60.432 64.716 60.456 64.8 ;
    END
  END dn1[122]
  PIN dn1[123]
    DIRECTION OUTPUT ;
    USE SIGNAL ;
    PORT
      LAYER M5 ;
        RECT  60.528 64.716 60.552 64.8 ;
    END
  END dn1[123]
  PIN dn1[124]
    DIRECTION OUTPUT ;
    USE SIGNAL ;
    PORT
      LAYER M5 ;
        RECT  60.624 64.716 60.648 64.8 ;
    END
  END dn1[124]
  PIN dn1[125]
    DIRECTION OUTPUT ;
    USE SIGNAL ;
    PORT
      LAYER M5 ;
        RECT  60.72 64.716 60.744 64.8 ;
    END
  END dn1[125]
  PIN dn1[126]
    DIRECTION OUTPUT ;
    USE SIGNAL ;
    PORT
      LAYER M5 ;
        RECT  60.816 64.716 60.84 64.8 ;
    END
  END dn1[126]
  PIN dn1[127]
    DIRECTION OUTPUT ;
    USE SIGNAL ;
    PORT
      LAYER M5 ;
        RECT  60.912 64.716 60.936 64.8 ;
    END
  END dn1[127]
  PIN dn1[128]
    DIRECTION OUTPUT ;
    USE SIGNAL ;
    PORT
      LAYER M5 ;
        RECT  54.864 64.716 54.888 64.8 ;
    END
  END dn1[128]
  PIN dn1[129]
    DIRECTION OUTPUT ;
    USE SIGNAL ;
    PORT
      LAYER M5 ;
        RECT  54.96 64.716 54.984 64.8 ;
    END
  END dn1[129]
  PIN dn1[12]
    DIRECTION OUTPUT ;
    USE SIGNAL ;
    PORT
      LAYER M5 ;
        RECT  17.616 64.716 17.64 64.8 ;
    END
  END dn1[12]
  PIN dn1[130]
    DIRECTION OUTPUT ;
    USE SIGNAL ;
    PORT
      LAYER M5 ;
        RECT  55.056 64.716 55.08 64.8 ;
    END
  END dn1[130]
  PIN dn1[131]
    DIRECTION OUTPUT ;
    USE SIGNAL ;
    PORT
      LAYER M5 ;
        RECT  55.152 64.716 55.176 64.8 ;
    END
  END dn1[131]
  PIN dn1[132]
    DIRECTION OUTPUT ;
    USE SIGNAL ;
    PORT
      LAYER M5 ;
        RECT  55.248 64.716 55.272 64.8 ;
    END
  END dn1[132]
  PIN dn1[133]
    DIRECTION OUTPUT ;
    USE SIGNAL ;
    PORT
      LAYER M5 ;
        RECT  55.344 64.716 55.368 64.8 ;
    END
  END dn1[133]
  PIN dn1[134]
    DIRECTION OUTPUT ;
    USE SIGNAL ;
    PORT
      LAYER M5 ;
        RECT  55.44 64.716 55.464 64.8 ;
    END
  END dn1[134]
  PIN dn1[135]
    DIRECTION OUTPUT ;
    USE SIGNAL ;
    PORT
      LAYER M5 ;
        RECT  55.536 64.716 55.56 64.8 ;
    END
  END dn1[135]
  PIN dn1[136]
    DIRECTION OUTPUT ;
    USE SIGNAL ;
    PORT
      LAYER M5 ;
        RECT  55.632 64.716 55.656 64.8 ;
    END
  END dn1[136]
  PIN dn1[137]
    DIRECTION OUTPUT ;
    USE SIGNAL ;
    PORT
      LAYER M5 ;
        RECT  55.728 64.716 55.752 64.8 ;
    END
  END dn1[137]
  PIN dn1[138]
    DIRECTION OUTPUT ;
    USE SIGNAL ;
    PORT
      LAYER M5 ;
        RECT  55.824 64.716 55.848 64.8 ;
    END
  END dn1[138]
  PIN dn1[139]
    DIRECTION OUTPUT ;
    USE SIGNAL ;
    PORT
      LAYER M5 ;
        RECT  55.92 64.716 55.944 64.8 ;
    END
  END dn1[139]
  PIN dn1[13]
    DIRECTION OUTPUT ;
    USE SIGNAL ;
    PORT
      LAYER M5 ;
        RECT  17.712 64.716 17.736 64.8 ;
    END
  END dn1[13]
  PIN dn1[140]
    DIRECTION OUTPUT ;
    USE SIGNAL ;
    PORT
      LAYER M5 ;
        RECT  56.016 64.716 56.04 64.8 ;
    END
  END dn1[140]
  PIN dn1[141]
    DIRECTION OUTPUT ;
    USE SIGNAL ;
    PORT
      LAYER M5 ;
        RECT  56.112 64.716 56.136 64.8 ;
    END
  END dn1[141]
  PIN dn1[142]
    DIRECTION OUTPUT ;
    USE SIGNAL ;
    PORT
      LAYER M5 ;
        RECT  56.208 64.716 56.232 64.8 ;
    END
  END dn1[142]
  PIN dn1[143]
    DIRECTION OUTPUT ;
    USE SIGNAL ;
    PORT
      LAYER M5 ;
        RECT  56.304 64.716 56.328 64.8 ;
    END
  END dn1[143]
  PIN dn1[144]
    DIRECTION OUTPUT ;
    USE SIGNAL ;
    PORT
      LAYER M5 ;
        RECT  56.4 64.716 56.424 64.8 ;
    END
  END dn1[144]
  PIN dn1[145]
    DIRECTION OUTPUT ;
    USE SIGNAL ;
    PORT
      LAYER M5 ;
        RECT  56.496 64.716 56.52 64.8 ;
    END
  END dn1[145]
  PIN dn1[146]
    DIRECTION OUTPUT ;
    USE SIGNAL ;
    PORT
      LAYER M5 ;
        RECT  56.592 64.716 56.616 64.8 ;
    END
  END dn1[146]
  PIN dn1[147]
    DIRECTION OUTPUT ;
    USE SIGNAL ;
    PORT
      LAYER M5 ;
        RECT  56.688 64.716 56.712 64.8 ;
    END
  END dn1[147]
  PIN dn1[148]
    DIRECTION OUTPUT ;
    USE SIGNAL ;
    PORT
      LAYER M5 ;
        RECT  56.784 64.716 56.808 64.8 ;
    END
  END dn1[148]
  PIN dn1[149]
    DIRECTION OUTPUT ;
    USE SIGNAL ;
    PORT
      LAYER M5 ;
        RECT  56.88 64.716 56.904 64.8 ;
    END
  END dn1[149]
  PIN dn1[14]
    DIRECTION OUTPUT ;
    USE SIGNAL ;
    PORT
      LAYER M5 ;
        RECT  17.808 64.716 17.832 64.8 ;
    END
  END dn1[14]
  PIN dn1[150]
    DIRECTION OUTPUT ;
    USE SIGNAL ;
    PORT
      LAYER M5 ;
        RECT  56.976 64.716 57 64.8 ;
    END
  END dn1[150]
  PIN dn1[151]
    DIRECTION OUTPUT ;
    USE SIGNAL ;
    PORT
      LAYER M5 ;
        RECT  57.072 64.716 57.096 64.8 ;
    END
  END dn1[151]
  PIN dn1[152]
    DIRECTION OUTPUT ;
    USE SIGNAL ;
    PORT
      LAYER M5 ;
        RECT  57.168 64.716 57.192 64.8 ;
    END
  END dn1[152]
  PIN dn1[153]
    DIRECTION OUTPUT ;
    USE SIGNAL ;
    PORT
      LAYER M5 ;
        RECT  57.264 64.716 57.288 64.8 ;
    END
  END dn1[153]
  PIN dn1[154]
    DIRECTION OUTPUT ;
    USE SIGNAL ;
    PORT
      LAYER M5 ;
        RECT  57.36 64.716 57.384 64.8 ;
    END
  END dn1[154]
  PIN dn1[155]
    DIRECTION OUTPUT ;
    USE SIGNAL ;
    PORT
      LAYER M5 ;
        RECT  57.456 64.716 57.48 64.8 ;
    END
  END dn1[155]
  PIN dn1[156]
    DIRECTION OUTPUT ;
    USE SIGNAL ;
    PORT
      LAYER M5 ;
        RECT  57.552 64.716 57.576 64.8 ;
    END
  END dn1[156]
  PIN dn1[157]
    DIRECTION OUTPUT ;
    USE SIGNAL ;
    PORT
      LAYER M5 ;
        RECT  57.648 64.716 57.672 64.8 ;
    END
  END dn1[157]
  PIN dn1[158]
    DIRECTION OUTPUT ;
    USE SIGNAL ;
    PORT
      LAYER M5 ;
        RECT  57.744 64.716 57.768 64.8 ;
    END
  END dn1[158]
  PIN dn1[159]
    DIRECTION OUTPUT ;
    USE SIGNAL ;
    PORT
      LAYER M5 ;
        RECT  57.84 64.716 57.864 64.8 ;
    END
  END dn1[159]
  PIN dn1[15]
    DIRECTION OUTPUT ;
    USE SIGNAL ;
    PORT
      LAYER M5 ;
        RECT  17.904 64.716 17.928 64.8 ;
    END
  END dn1[15]
  PIN dn1[160]
    DIRECTION OUTPUT ;
    USE SIGNAL ;
    PORT
      LAYER M5 ;
        RECT  32.592 64.716 32.616 64.8 ;
    END
  END dn1[160]
  PIN dn1[161]
    DIRECTION OUTPUT ;
    USE SIGNAL ;
    PORT
      LAYER M5 ;
        RECT  32.688 64.716 32.712 64.8 ;
    END
  END dn1[161]
  PIN dn1[162]
    DIRECTION OUTPUT ;
    USE SIGNAL ;
    PORT
      LAYER M5 ;
        RECT  32.784 64.716 32.808 64.8 ;
    END
  END dn1[162]
  PIN dn1[163]
    DIRECTION OUTPUT ;
    USE SIGNAL ;
    PORT
      LAYER M5 ;
        RECT  32.88 64.716 32.904 64.8 ;
    END
  END dn1[163]
  PIN dn1[164]
    DIRECTION OUTPUT ;
    USE SIGNAL ;
    PORT
      LAYER M5 ;
        RECT  32.976 64.716 33 64.8 ;
    END
  END dn1[164]
  PIN dn1[165]
    DIRECTION OUTPUT ;
    USE SIGNAL ;
    PORT
      LAYER M5 ;
        RECT  33.072 64.716 33.096 64.8 ;
    END
  END dn1[165]
  PIN dn1[166]
    DIRECTION OUTPUT ;
    USE SIGNAL ;
    PORT
      LAYER M5 ;
        RECT  33.168 64.716 33.192 64.8 ;
    END
  END dn1[166]
  PIN dn1[167]
    DIRECTION OUTPUT ;
    USE SIGNAL ;
    PORT
      LAYER M5 ;
        RECT  33.264 64.716 33.288 64.8 ;
    END
  END dn1[167]
  PIN dn1[168]
    DIRECTION OUTPUT ;
    USE SIGNAL ;
    PORT
      LAYER M5 ;
        RECT  33.36 64.716 33.384 64.8 ;
    END
  END dn1[168]
  PIN dn1[169]
    DIRECTION OUTPUT ;
    USE SIGNAL ;
    PORT
      LAYER M5 ;
        RECT  33.456 64.716 33.48 64.8 ;
    END
  END dn1[169]
  PIN dn1[16]
    DIRECTION OUTPUT ;
    USE SIGNAL ;
    PORT
      LAYER M5 ;
        RECT  18 64.716 18.024 64.8 ;
    END
  END dn1[16]
  PIN dn1[170]
    DIRECTION OUTPUT ;
    USE SIGNAL ;
    PORT
      LAYER M5 ;
        RECT  33.552 64.716 33.576 64.8 ;
    END
  END dn1[170]
  PIN dn1[171]
    DIRECTION OUTPUT ;
    USE SIGNAL ;
    PORT
      LAYER M5 ;
        RECT  33.648 64.716 33.672 64.8 ;
    END
  END dn1[171]
  PIN dn1[172]
    DIRECTION OUTPUT ;
    USE SIGNAL ;
    PORT
      LAYER M5 ;
        RECT  33.744 64.716 33.768 64.8 ;
    END
  END dn1[172]
  PIN dn1[173]
    DIRECTION OUTPUT ;
    USE SIGNAL ;
    PORT
      LAYER M5 ;
        RECT  33.84 64.716 33.864 64.8 ;
    END
  END dn1[173]
  PIN dn1[174]
    DIRECTION OUTPUT ;
    USE SIGNAL ;
    PORT
      LAYER M5 ;
        RECT  33.936 64.716 33.96 64.8 ;
    END
  END dn1[174]
  PIN dn1[175]
    DIRECTION OUTPUT ;
    USE SIGNAL ;
    PORT
      LAYER M5 ;
        RECT  34.032 64.716 34.056 64.8 ;
    END
  END dn1[175]
  PIN dn1[176]
    DIRECTION OUTPUT ;
    USE SIGNAL ;
    PORT
      LAYER M5 ;
        RECT  34.128 64.716 34.152 64.8 ;
    END
  END dn1[176]
  PIN dn1[177]
    DIRECTION OUTPUT ;
    USE SIGNAL ;
    PORT
      LAYER M5 ;
        RECT  34.224 64.716 34.248 64.8 ;
    END
  END dn1[177]
  PIN dn1[178]
    DIRECTION OUTPUT ;
    USE SIGNAL ;
    PORT
      LAYER M5 ;
        RECT  34.32 64.716 34.344 64.8 ;
    END
  END dn1[178]
  PIN dn1[179]
    DIRECTION OUTPUT ;
    USE SIGNAL ;
    PORT
      LAYER M5 ;
        RECT  34.416 64.716 34.44 64.8 ;
    END
  END dn1[179]
  PIN dn1[17]
    DIRECTION OUTPUT ;
    USE SIGNAL ;
    PORT
      LAYER M5 ;
        RECT  18.096 64.716 18.12 64.8 ;
    END
  END dn1[17]
  PIN dn1[180]
    DIRECTION OUTPUT ;
    USE SIGNAL ;
    PORT
      LAYER M5 ;
        RECT  34.512 64.716 34.536 64.8 ;
    END
  END dn1[180]
  PIN dn1[181]
    DIRECTION OUTPUT ;
    USE SIGNAL ;
    PORT
      LAYER M5 ;
        RECT  34.608 64.716 34.632 64.8 ;
    END
  END dn1[181]
  PIN dn1[182]
    DIRECTION OUTPUT ;
    USE SIGNAL ;
    PORT
      LAYER M5 ;
        RECT  34.704 64.716 34.728 64.8 ;
    END
  END dn1[182]
  PIN dn1[183]
    DIRECTION OUTPUT ;
    USE SIGNAL ;
    PORT
      LAYER M5 ;
        RECT  34.8 64.716 34.824 64.8 ;
    END
  END dn1[183]
  PIN dn1[184]
    DIRECTION OUTPUT ;
    USE SIGNAL ;
    PORT
      LAYER M5 ;
        RECT  34.896 64.716 34.92 64.8 ;
    END
  END dn1[184]
  PIN dn1[185]
    DIRECTION OUTPUT ;
    USE SIGNAL ;
    PORT
      LAYER M5 ;
        RECT  34.992 64.716 35.016 64.8 ;
    END
  END dn1[185]
  PIN dn1[186]
    DIRECTION OUTPUT ;
    USE SIGNAL ;
    PORT
      LAYER M5 ;
        RECT  35.088 64.716 35.112 64.8 ;
    END
  END dn1[186]
  PIN dn1[187]
    DIRECTION OUTPUT ;
    USE SIGNAL ;
    PORT
      LAYER M5 ;
        RECT  35.184 64.716 35.208 64.8 ;
    END
  END dn1[187]
  PIN dn1[188]
    DIRECTION OUTPUT ;
    USE SIGNAL ;
    PORT
      LAYER M5 ;
        RECT  35.28 64.716 35.304 64.8 ;
    END
  END dn1[188]
  PIN dn1[189]
    DIRECTION OUTPUT ;
    USE SIGNAL ;
    PORT
      LAYER M5 ;
        RECT  35.376 64.716 35.4 64.8 ;
    END
  END dn1[189]
  PIN dn1[18]
    DIRECTION OUTPUT ;
    USE SIGNAL ;
    PORT
      LAYER M5 ;
        RECT  18.192 64.716 18.216 64.8 ;
    END
  END dn1[18]
  PIN dn1[190]
    DIRECTION OUTPUT ;
    USE SIGNAL ;
    PORT
      LAYER M5 ;
        RECT  35.472 64.716 35.496 64.8 ;
    END
  END dn1[190]
  PIN dn1[191]
    DIRECTION OUTPUT ;
    USE SIGNAL ;
    PORT
      LAYER M5 ;
        RECT  35.568 64.716 35.592 64.8 ;
    END
  END dn1[191]
  PIN dn1[192]
    DIRECTION OUTPUT ;
    USE SIGNAL ;
    PORT
      LAYER M5 ;
        RECT  13.392 64.716 13.416 64.8 ;
    END
  END dn1[192]
  PIN dn1[193]
    DIRECTION OUTPUT ;
    USE SIGNAL ;
    PORT
      LAYER M5 ;
        RECT  13.488 64.716 13.512 64.8 ;
    END
  END dn1[193]
  PIN dn1[194]
    DIRECTION OUTPUT ;
    USE SIGNAL ;
    PORT
      LAYER M5 ;
        RECT  13.584 64.716 13.608 64.8 ;
    END
  END dn1[194]
  PIN dn1[195]
    DIRECTION OUTPUT ;
    USE SIGNAL ;
    PORT
      LAYER M5 ;
        RECT  13.68 64.716 13.704 64.8 ;
    END
  END dn1[195]
  PIN dn1[196]
    DIRECTION OUTPUT ;
    USE SIGNAL ;
    PORT
      LAYER M5 ;
        RECT  13.776 64.716 13.8 64.8 ;
    END
  END dn1[196]
  PIN dn1[197]
    DIRECTION OUTPUT ;
    USE SIGNAL ;
    PORT
      LAYER M5 ;
        RECT  13.872 64.716 13.896 64.8 ;
    END
  END dn1[197]
  PIN dn1[198]
    DIRECTION OUTPUT ;
    USE SIGNAL ;
    PORT
      LAYER M5 ;
        RECT  13.968 64.716 13.992 64.8 ;
    END
  END dn1[198]
  PIN dn1[199]
    DIRECTION OUTPUT ;
    USE SIGNAL ;
    PORT
      LAYER M5 ;
        RECT  14.064 64.716 14.088 64.8 ;
    END
  END dn1[199]
  PIN dn1[19]
    DIRECTION OUTPUT ;
    USE SIGNAL ;
    PORT
      LAYER M5 ;
        RECT  18.288 64.716 18.312 64.8 ;
    END
  END dn1[19]
  PIN dn1[1]
    DIRECTION OUTPUT ;
    USE SIGNAL ;
    PORT
      LAYER M5 ;
        RECT  16.56 64.716 16.584 64.8 ;
    END
  END dn1[1]
  PIN dn1[200]
    DIRECTION OUTPUT ;
    USE SIGNAL ;
    PORT
      LAYER M5 ;
        RECT  14.16 64.716 14.184 64.8 ;
    END
  END dn1[200]
  PIN dn1[201]
    DIRECTION OUTPUT ;
    USE SIGNAL ;
    PORT
      LAYER M5 ;
        RECT  14.256 64.716 14.28 64.8 ;
    END
  END dn1[201]
  PIN dn1[202]
    DIRECTION OUTPUT ;
    USE SIGNAL ;
    PORT
      LAYER M5 ;
        RECT  14.352 64.716 14.376 64.8 ;
    END
  END dn1[202]
  PIN dn1[203]
    DIRECTION OUTPUT ;
    USE SIGNAL ;
    PORT
      LAYER M5 ;
        RECT  14.448 64.716 14.472 64.8 ;
    END
  END dn1[203]
  PIN dn1[204]
    DIRECTION OUTPUT ;
    USE SIGNAL ;
    PORT
      LAYER M5 ;
        RECT  14.544 64.716 14.568 64.8 ;
    END
  END dn1[204]
  PIN dn1[205]
    DIRECTION OUTPUT ;
    USE SIGNAL ;
    PORT
      LAYER M5 ;
        RECT  14.64 64.716 14.664 64.8 ;
    END
  END dn1[205]
  PIN dn1[206]
    DIRECTION OUTPUT ;
    USE SIGNAL ;
    PORT
      LAYER M5 ;
        RECT  14.736 64.716 14.76 64.8 ;
    END
  END dn1[206]
  PIN dn1[207]
    DIRECTION OUTPUT ;
    USE SIGNAL ;
    PORT
      LAYER M5 ;
        RECT  14.832 64.716 14.856 64.8 ;
    END
  END dn1[207]
  PIN dn1[208]
    DIRECTION OUTPUT ;
    USE SIGNAL ;
    PORT
      LAYER M5 ;
        RECT  14.928 64.716 14.952 64.8 ;
    END
  END dn1[208]
  PIN dn1[209]
    DIRECTION OUTPUT ;
    USE SIGNAL ;
    PORT
      LAYER M5 ;
        RECT  15.024 64.716 15.048 64.8 ;
    END
  END dn1[209]
  PIN dn1[20]
    DIRECTION OUTPUT ;
    USE SIGNAL ;
    PORT
      LAYER M5 ;
        RECT  18.384 64.716 18.408 64.8 ;
    END
  END dn1[20]
  PIN dn1[210]
    DIRECTION OUTPUT ;
    USE SIGNAL ;
    PORT
      LAYER M5 ;
        RECT  15.12 64.716 15.144 64.8 ;
    END
  END dn1[210]
  PIN dn1[211]
    DIRECTION OUTPUT ;
    USE SIGNAL ;
    PORT
      LAYER M5 ;
        RECT  15.216 64.716 15.24 64.8 ;
    END
  END dn1[211]
  PIN dn1[212]
    DIRECTION OUTPUT ;
    USE SIGNAL ;
    PORT
      LAYER M5 ;
        RECT  15.312 64.716 15.336 64.8 ;
    END
  END dn1[212]
  PIN dn1[213]
    DIRECTION OUTPUT ;
    USE SIGNAL ;
    PORT
      LAYER M5 ;
        RECT  15.408 64.716 15.432 64.8 ;
    END
  END dn1[213]
  PIN dn1[214]
    DIRECTION OUTPUT ;
    USE SIGNAL ;
    PORT
      LAYER M5 ;
        RECT  15.504 64.716 15.528 64.8 ;
    END
  END dn1[214]
  PIN dn1[215]
    DIRECTION OUTPUT ;
    USE SIGNAL ;
    PORT
      LAYER M5 ;
        RECT  15.6 64.716 15.624 64.8 ;
    END
  END dn1[215]
  PIN dn1[216]
    DIRECTION OUTPUT ;
    USE SIGNAL ;
    PORT
      LAYER M5 ;
        RECT  15.696 64.716 15.72 64.8 ;
    END
  END dn1[216]
  PIN dn1[217]
    DIRECTION OUTPUT ;
    USE SIGNAL ;
    PORT
      LAYER M5 ;
        RECT  15.792 64.716 15.816 64.8 ;
    END
  END dn1[217]
  PIN dn1[218]
    DIRECTION OUTPUT ;
    USE SIGNAL ;
    PORT
      LAYER M5 ;
        RECT  15.888 64.716 15.912 64.8 ;
    END
  END dn1[218]
  PIN dn1[219]
    DIRECTION OUTPUT ;
    USE SIGNAL ;
    PORT
      LAYER M5 ;
        RECT  15.984 64.716 16.008 64.8 ;
    END
  END dn1[219]
  PIN dn1[21]
    DIRECTION OUTPUT ;
    USE SIGNAL ;
    PORT
      LAYER M5 ;
        RECT  18.48 64.716 18.504 64.8 ;
    END
  END dn1[21]
  PIN dn1[220]
    DIRECTION OUTPUT ;
    USE SIGNAL ;
    PORT
      LAYER M5 ;
        RECT  16.08 64.716 16.104 64.8 ;
    END
  END dn1[220]
  PIN dn1[221]
    DIRECTION OUTPUT ;
    USE SIGNAL ;
    PORT
      LAYER M5 ;
        RECT  16.176 64.716 16.2 64.8 ;
    END
  END dn1[221]
  PIN dn1[222]
    DIRECTION OUTPUT ;
    USE SIGNAL ;
    PORT
      LAYER M5 ;
        RECT  16.272 64.716 16.296 64.8 ;
    END
  END dn1[222]
  PIN dn1[223]
    DIRECTION OUTPUT ;
    USE SIGNAL ;
    PORT
      LAYER M5 ;
        RECT  16.368 64.716 16.392 64.8 ;
    END
  END dn1[223]
  PIN dn1[224]
    DIRECTION OUTPUT ;
    USE SIGNAL ;
    PORT
      LAYER M5 ;
        RECT  25.008 64.716 25.032 64.8 ;
    END
  END dn1[224]
  PIN dn1[225]
    DIRECTION OUTPUT ;
    USE SIGNAL ;
    PORT
      LAYER M5 ;
        RECT  25.104 64.716 25.128 64.8 ;
    END
  END dn1[225]
  PIN dn1[226]
    DIRECTION OUTPUT ;
    USE SIGNAL ;
    PORT
      LAYER M5 ;
        RECT  25.2 64.716 25.224 64.8 ;
    END
  END dn1[226]
  PIN dn1[227]
    DIRECTION OUTPUT ;
    USE SIGNAL ;
    PORT
      LAYER M5 ;
        RECT  25.296 64.716 25.32 64.8 ;
    END
  END dn1[227]
  PIN dn1[22]
    DIRECTION OUTPUT ;
    USE SIGNAL ;
    PORT
      LAYER M5 ;
        RECT  18.576 64.716 18.6 64.8 ;
    END
  END dn1[22]
  PIN dn1[23]
    DIRECTION OUTPUT ;
    USE SIGNAL ;
    PORT
      LAYER M5 ;
        RECT  18.672 64.716 18.696 64.8 ;
    END
  END dn1[23]
  PIN dn1[24]
    DIRECTION OUTPUT ;
    USE SIGNAL ;
    PORT
      LAYER M5 ;
        RECT  18.768 64.716 18.792 64.8 ;
    END
  END dn1[24]
  PIN dn1[25]
    DIRECTION OUTPUT ;
    USE SIGNAL ;
    PORT
      LAYER M5 ;
        RECT  18.864 64.716 18.888 64.8 ;
    END
  END dn1[25]
  PIN dn1[26]
    DIRECTION OUTPUT ;
    USE SIGNAL ;
    PORT
      LAYER M5 ;
        RECT  18.96 64.716 18.984 64.8 ;
    END
  END dn1[26]
  PIN dn1[27]
    DIRECTION OUTPUT ;
    USE SIGNAL ;
    PORT
      LAYER M5 ;
        RECT  19.056 64.716 19.08 64.8 ;
    END
  END dn1[27]
  PIN dn1[28]
    DIRECTION OUTPUT ;
    USE SIGNAL ;
    PORT
      LAYER M5 ;
        RECT  19.152 64.716 19.176 64.8 ;
    END
  END dn1[28]
  PIN dn1[29]
    DIRECTION OUTPUT ;
    USE SIGNAL ;
    PORT
      LAYER M5 ;
        RECT  19.248 64.716 19.272 64.8 ;
    END
  END dn1[29]
  PIN dn1[2]
    DIRECTION OUTPUT ;
    USE SIGNAL ;
    PORT
      LAYER M5 ;
        RECT  16.656 64.716 16.68 64.8 ;
    END
  END dn1[2]
  PIN dn1[30]
    DIRECTION OUTPUT ;
    USE SIGNAL ;
    PORT
      LAYER M5 ;
        RECT  19.344 64.716 19.368 64.8 ;
    END
  END dn1[30]
  PIN dn1[31]
    DIRECTION OUTPUT ;
    USE SIGNAL ;
    PORT
      LAYER M5 ;
        RECT  19.44 64.716 19.464 64.8 ;
    END
  END dn1[31]
  PIN dn1[32]
    DIRECTION OUTPUT ;
    USE SIGNAL ;
    PORT
      LAYER M5 ;
        RECT  19.536 64.716 19.56 64.8 ;
    END
  END dn1[32]
  PIN dn1[33]
    DIRECTION OUTPUT ;
    USE SIGNAL ;
    PORT
      LAYER M5 ;
        RECT  19.632 64.716 19.656 64.8 ;
    END
  END dn1[33]
  PIN dn1[34]
    DIRECTION OUTPUT ;
    USE SIGNAL ;
    PORT
      LAYER M5 ;
        RECT  19.728 64.716 19.752 64.8 ;
    END
  END dn1[34]
  PIN dn1[35]
    DIRECTION OUTPUT ;
    USE SIGNAL ;
    PORT
      LAYER M5 ;
        RECT  19.824 64.716 19.848 64.8 ;
    END
  END dn1[35]
  PIN dn1[36]
    DIRECTION OUTPUT ;
    USE SIGNAL ;
    PORT
      LAYER M5 ;
        RECT  19.92 64.716 19.944 64.8 ;
    END
  END dn1[36]
  PIN dn1[37]
    DIRECTION OUTPUT ;
    USE SIGNAL ;
    PORT
      LAYER M5 ;
        RECT  20.016 64.716 20.04 64.8 ;
    END
  END dn1[37]
  PIN dn1[38]
    DIRECTION OUTPUT ;
    USE SIGNAL ;
    PORT
      LAYER M5 ;
        RECT  20.112 64.716 20.136 64.8 ;
    END
  END dn1[38]
  PIN dn1[39]
    DIRECTION OUTPUT ;
    USE SIGNAL ;
    PORT
      LAYER M5 ;
        RECT  20.208 64.716 20.232 64.8 ;
    END
  END dn1[39]
  PIN dn1[3]
    DIRECTION OUTPUT ;
    USE SIGNAL ;
    PORT
      LAYER M5 ;
        RECT  16.752 64.716 16.776 64.8 ;
    END
  END dn1[3]
  PIN dn1[40]
    DIRECTION OUTPUT ;
    USE SIGNAL ;
    PORT
      LAYER M5 ;
        RECT  20.304 64.716 20.328 64.8 ;
    END
  END dn1[40]
  PIN dn1[41]
    DIRECTION OUTPUT ;
    USE SIGNAL ;
    PORT
      LAYER M5 ;
        RECT  20.4 64.716 20.424 64.8 ;
    END
  END dn1[41]
  PIN dn1[42]
    DIRECTION OUTPUT ;
    USE SIGNAL ;
    PORT
      LAYER M5 ;
        RECT  20.496 64.716 20.52 64.8 ;
    END
  END dn1[42]
  PIN dn1[43]
    DIRECTION OUTPUT ;
    USE SIGNAL ;
    PORT
      LAYER M5 ;
        RECT  20.592 64.716 20.616 64.8 ;
    END
  END dn1[43]
  PIN dn1[44]
    DIRECTION OUTPUT ;
    USE SIGNAL ;
    PORT
      LAYER M5 ;
        RECT  20.688 64.716 20.712 64.8 ;
    END
  END dn1[44]
  PIN dn1[45]
    DIRECTION OUTPUT ;
    USE SIGNAL ;
    PORT
      LAYER M5 ;
        RECT  20.784 64.716 20.808 64.8 ;
    END
  END dn1[45]
  PIN dn1[46]
    DIRECTION OUTPUT ;
    USE SIGNAL ;
    PORT
      LAYER M5 ;
        RECT  20.88 64.716 20.904 64.8 ;
    END
  END dn1[46]
  PIN dn1[47]
    DIRECTION OUTPUT ;
    USE SIGNAL ;
    PORT
      LAYER M5 ;
        RECT  20.976 64.716 21 64.8 ;
    END
  END dn1[47]
  PIN dn1[48]
    DIRECTION OUTPUT ;
    USE SIGNAL ;
    PORT
      LAYER M5 ;
        RECT  21.072 64.716 21.096 64.8 ;
    END
  END dn1[48]
  PIN dn1[49]
    DIRECTION OUTPUT ;
    USE SIGNAL ;
    PORT
      LAYER M5 ;
        RECT  21.168 64.716 21.192 64.8 ;
    END
  END dn1[49]
  PIN dn1[4]
    DIRECTION OUTPUT ;
    USE SIGNAL ;
    PORT
      LAYER M5 ;
        RECT  16.848 64.716 16.872 64.8 ;
    END
  END dn1[4]
  PIN dn1[50]
    DIRECTION OUTPUT ;
    USE SIGNAL ;
    PORT
      LAYER M5 ;
        RECT  21.264 64.716 21.288 64.8 ;
    END
  END dn1[50]
  PIN dn1[51]
    DIRECTION OUTPUT ;
    USE SIGNAL ;
    PORT
      LAYER M5 ;
        RECT  21.36 64.716 21.384 64.8 ;
    END
  END dn1[51]
  PIN dn1[52]
    DIRECTION OUTPUT ;
    USE SIGNAL ;
    PORT
      LAYER M5 ;
        RECT  21.456 64.716 21.48 64.8 ;
    END
  END dn1[52]
  PIN dn1[53]
    DIRECTION OUTPUT ;
    USE SIGNAL ;
    PORT
      LAYER M5 ;
        RECT  21.552 64.716 21.576 64.8 ;
    END
  END dn1[53]
  PIN dn1[54]
    DIRECTION OUTPUT ;
    USE SIGNAL ;
    PORT
      LAYER M5 ;
        RECT  21.648 64.716 21.672 64.8 ;
    END
  END dn1[54]
  PIN dn1[55]
    DIRECTION OUTPUT ;
    USE SIGNAL ;
    PORT
      LAYER M5 ;
        RECT  21.744 64.716 21.768 64.8 ;
    END
  END dn1[55]
  PIN dn1[56]
    DIRECTION OUTPUT ;
    USE SIGNAL ;
    PORT
      LAYER M5 ;
        RECT  21.84 64.716 21.864 64.8 ;
    END
  END dn1[56]
  PIN dn1[57]
    DIRECTION OUTPUT ;
    USE SIGNAL ;
    PORT
      LAYER M5 ;
        RECT  21.936 64.716 21.96 64.8 ;
    END
  END dn1[57]
  PIN dn1[58]
    DIRECTION OUTPUT ;
    USE SIGNAL ;
    PORT
      LAYER M5 ;
        RECT  22.032 64.716 22.056 64.8 ;
    END
  END dn1[58]
  PIN dn1[59]
    DIRECTION OUTPUT ;
    USE SIGNAL ;
    PORT
      LAYER M5 ;
        RECT  22.128 64.716 22.152 64.8 ;
    END
  END dn1[59]
  PIN dn1[5]
    DIRECTION OUTPUT ;
    USE SIGNAL ;
    PORT
      LAYER M5 ;
        RECT  16.944 64.716 16.968 64.8 ;
    END
  END dn1[5]
  PIN dn1[60]
    DIRECTION OUTPUT ;
    USE SIGNAL ;
    PORT
      LAYER M5 ;
        RECT  22.224 64.716 22.248 64.8 ;
    END
  END dn1[60]
  PIN dn1[61]
    DIRECTION OUTPUT ;
    USE SIGNAL ;
    PORT
      LAYER M5 ;
        RECT  22.32 64.716 22.344 64.8 ;
    END
  END dn1[61]
  PIN dn1[62]
    DIRECTION OUTPUT ;
    USE SIGNAL ;
    PORT
      LAYER M5 ;
        RECT  22.416 64.716 22.44 64.8 ;
    END
  END dn1[62]
  PIN dn1[63]
    DIRECTION OUTPUT ;
    USE SIGNAL ;
    PORT
      LAYER M5 ;
        RECT  22.512 64.716 22.536 64.8 ;
    END
  END dn1[63]
  PIN dn1[64]
    DIRECTION OUTPUT ;
    USE SIGNAL ;
    PORT
      LAYER M5 ;
        RECT  35.664 64.716 35.688 64.8 ;
    END
  END dn1[64]
  PIN dn1[65]
    DIRECTION OUTPUT ;
    USE SIGNAL ;
    PORT
      LAYER M5 ;
        RECT  35.76 64.716 35.784 64.8 ;
    END
  END dn1[65]
  PIN dn1[66]
    DIRECTION OUTPUT ;
    USE SIGNAL ;
    PORT
      LAYER M5 ;
        RECT  35.856 64.716 35.88 64.8 ;
    END
  END dn1[66]
  PIN dn1[67]
    DIRECTION OUTPUT ;
    USE SIGNAL ;
    PORT
      LAYER M5 ;
        RECT  35.952 64.716 35.976 64.8 ;
    END
  END dn1[67]
  PIN dn1[68]
    DIRECTION OUTPUT ;
    USE SIGNAL ;
    PORT
      LAYER M5 ;
        RECT  36.048 64.716 36.072 64.8 ;
    END
  END dn1[68]
  PIN dn1[69]
    DIRECTION OUTPUT ;
    USE SIGNAL ;
    PORT
      LAYER M5 ;
        RECT  36.144 64.716 36.168 64.8 ;
    END
  END dn1[69]
  PIN dn1[6]
    DIRECTION OUTPUT ;
    USE SIGNAL ;
    PORT
      LAYER M5 ;
        RECT  17.04 64.716 17.064 64.8 ;
    END
  END dn1[6]
  PIN dn1[70]
    DIRECTION OUTPUT ;
    USE SIGNAL ;
    PORT
      LAYER M5 ;
        RECT  36.24 64.716 36.264 64.8 ;
    END
  END dn1[70]
  PIN dn1[71]
    DIRECTION OUTPUT ;
    USE SIGNAL ;
    PORT
      LAYER M5 ;
        RECT  36.336 64.716 36.36 64.8 ;
    END
  END dn1[71]
  PIN dn1[72]
    DIRECTION OUTPUT ;
    USE SIGNAL ;
    PORT
      LAYER M5 ;
        RECT  36.432 64.716 36.456 64.8 ;
    END
  END dn1[72]
  PIN dn1[73]
    DIRECTION OUTPUT ;
    USE SIGNAL ;
    PORT
      LAYER M5 ;
        RECT  36.528 64.716 36.552 64.8 ;
    END
  END dn1[73]
  PIN dn1[74]
    DIRECTION OUTPUT ;
    USE SIGNAL ;
    PORT
      LAYER M5 ;
        RECT  36.624 64.716 36.648 64.8 ;
    END
  END dn1[74]
  PIN dn1[75]
    DIRECTION OUTPUT ;
    USE SIGNAL ;
    PORT
      LAYER M5 ;
        RECT  36.72 64.716 36.744 64.8 ;
    END
  END dn1[75]
  PIN dn1[76]
    DIRECTION OUTPUT ;
    USE SIGNAL ;
    PORT
      LAYER M5 ;
        RECT  36.816 64.716 36.84 64.8 ;
    END
  END dn1[76]
  PIN dn1[77]
    DIRECTION OUTPUT ;
    USE SIGNAL ;
    PORT
      LAYER M5 ;
        RECT  36.912 64.716 36.936 64.8 ;
    END
  END dn1[77]
  PIN dn1[78]
    DIRECTION OUTPUT ;
    USE SIGNAL ;
    PORT
      LAYER M5 ;
        RECT  37.008 64.716 37.032 64.8 ;
    END
  END dn1[78]
  PIN dn1[79]
    DIRECTION OUTPUT ;
    USE SIGNAL ;
    PORT
      LAYER M5 ;
        RECT  37.104 64.716 37.128 64.8 ;
    END
  END dn1[79]
  PIN dn1[7]
    DIRECTION OUTPUT ;
    USE SIGNAL ;
    PORT
      LAYER M5 ;
        RECT  17.136 64.716 17.16 64.8 ;
    END
  END dn1[7]
  PIN dn1[80]
    DIRECTION OUTPUT ;
    USE SIGNAL ;
    PORT
      LAYER M5 ;
        RECT  37.2 64.716 37.224 64.8 ;
    END
  END dn1[80]
  PIN dn1[81]
    DIRECTION OUTPUT ;
    USE SIGNAL ;
    PORT
      LAYER M5 ;
        RECT  37.296 64.716 37.32 64.8 ;
    END
  END dn1[81]
  PIN dn1[82]
    DIRECTION OUTPUT ;
    USE SIGNAL ;
    PORT
      LAYER M5 ;
        RECT  37.392 64.716 37.416 64.8 ;
    END
  END dn1[82]
  PIN dn1[83]
    DIRECTION OUTPUT ;
    USE SIGNAL ;
    PORT
      LAYER M5 ;
        RECT  37.488 64.716 37.512 64.8 ;
    END
  END dn1[83]
  PIN dn1[84]
    DIRECTION OUTPUT ;
    USE SIGNAL ;
    PORT
      LAYER M5 ;
        RECT  37.584 64.716 37.608 64.8 ;
    END
  END dn1[84]
  PIN dn1[85]
    DIRECTION OUTPUT ;
    USE SIGNAL ;
    PORT
      LAYER M5 ;
        RECT  37.68 64.716 37.704 64.8 ;
    END
  END dn1[85]
  PIN dn1[86]
    DIRECTION OUTPUT ;
    USE SIGNAL ;
    PORT
      LAYER M5 ;
        RECT  37.776 64.716 37.8 64.8 ;
    END
  END dn1[86]
  PIN dn1[87]
    DIRECTION OUTPUT ;
    USE SIGNAL ;
    PORT
      LAYER M5 ;
        RECT  37.872 64.716 37.896 64.8 ;
    END
  END dn1[87]
  PIN dn1[88]
    DIRECTION OUTPUT ;
    USE SIGNAL ;
    PORT
      LAYER M5 ;
        RECT  37.968 64.716 37.992 64.8 ;
    END
  END dn1[88]
  PIN dn1[89]
    DIRECTION OUTPUT ;
    USE SIGNAL ;
    PORT
      LAYER M5 ;
        RECT  38.064 64.716 38.088 64.8 ;
    END
  END dn1[89]
  PIN dn1[8]
    DIRECTION OUTPUT ;
    USE SIGNAL ;
    PORT
      LAYER M5 ;
        RECT  17.232 64.716 17.256 64.8 ;
    END
  END dn1[8]
  PIN dn1[90]
    DIRECTION OUTPUT ;
    USE SIGNAL ;
    PORT
      LAYER M5 ;
        RECT  38.16 64.716 38.184 64.8 ;
    END
  END dn1[90]
  PIN dn1[91]
    DIRECTION OUTPUT ;
    USE SIGNAL ;
    PORT
      LAYER M5 ;
        RECT  38.256 64.716 38.28 64.8 ;
    END
  END dn1[91]
  PIN dn1[92]
    DIRECTION OUTPUT ;
    USE SIGNAL ;
    PORT
      LAYER M5 ;
        RECT  38.352 64.716 38.376 64.8 ;
    END
  END dn1[92]
  PIN dn1[93]
    DIRECTION OUTPUT ;
    USE SIGNAL ;
    PORT
      LAYER M5 ;
        RECT  38.448 64.716 38.472 64.8 ;
    END
  END dn1[93]
  PIN dn1[94]
    DIRECTION OUTPUT ;
    USE SIGNAL ;
    PORT
      LAYER M5 ;
        RECT  38.544 64.716 38.568 64.8 ;
    END
  END dn1[94]
  PIN dn1[95]
    DIRECTION OUTPUT ;
    USE SIGNAL ;
    PORT
      LAYER M5 ;
        RECT  38.64 64.716 38.664 64.8 ;
    END
  END dn1[95]
  PIN dn1[96]
    DIRECTION OUTPUT ;
    USE SIGNAL ;
    PORT
      LAYER M5 ;
        RECT  57.936 64.716 57.96 64.8 ;
    END
  END dn1[96]
  PIN dn1[97]
    DIRECTION OUTPUT ;
    USE SIGNAL ;
    PORT
      LAYER M5 ;
        RECT  58.032 64.716 58.056 64.8 ;
    END
  END dn1[97]
  PIN dn1[98]
    DIRECTION OUTPUT ;
    USE SIGNAL ;
    PORT
      LAYER M5 ;
        RECT  58.128 64.716 58.152 64.8 ;
    END
  END dn1[98]
  PIN dn1[99]
    DIRECTION OUTPUT ;
    USE SIGNAL ;
    PORT
      LAYER M5 ;
        RECT  58.224 64.716 58.248 64.8 ;
    END
  END dn1[99]
  PIN dn1[9]
    DIRECTION OUTPUT ;
    USE SIGNAL ;
    PORT
      LAYER M5 ;
        RECT  17.328 64.716 17.352 64.8 ;
    END
  END dn1[9]
  PIN dn2[0]
    DIRECTION OUTPUT ;
    USE SIGNAL ;
    PORT
      LAYER M4 ;
        RECT  64.716 35.28 64.8 35.304 ;
    END
  END dn2[0]
  PIN dn2[100]
    DIRECTION OUTPUT ;
    USE SIGNAL ;
    PORT
      LAYER M4 ;
        RECT  64.716 42.576 64.8 42.6 ;
    END
  END dn2[100]
  PIN dn2[101]
    DIRECTION OUTPUT ;
    USE SIGNAL ;
    PORT
      LAYER M4 ;
        RECT  64.716 42.672 64.8 42.696 ;
    END
  END dn2[101]
  PIN dn2[102]
    DIRECTION OUTPUT ;
    USE SIGNAL ;
    PORT
      LAYER M4 ;
        RECT  64.716 42.768 64.8 42.792 ;
    END
  END dn2[102]
  PIN dn2[103]
    DIRECTION OUTPUT ;
    USE SIGNAL ;
    PORT
      LAYER M4 ;
        RECT  64.716 42.864 64.8 42.888 ;
    END
  END dn2[103]
  PIN dn2[104]
    DIRECTION OUTPUT ;
    USE SIGNAL ;
    PORT
      LAYER M4 ;
        RECT  64.716 42.96 64.8 42.984 ;
    END
  END dn2[104]
  PIN dn2[105]
    DIRECTION OUTPUT ;
    USE SIGNAL ;
    PORT
      LAYER M4 ;
        RECT  64.716 43.056 64.8 43.08 ;
    END
  END dn2[105]
  PIN dn2[106]
    DIRECTION OUTPUT ;
    USE SIGNAL ;
    PORT
      LAYER M4 ;
        RECT  64.716 43.152 64.8 43.176 ;
    END
  END dn2[106]
  PIN dn2[107]
    DIRECTION OUTPUT ;
    USE SIGNAL ;
    PORT
      LAYER M4 ;
        RECT  64.716 43.248 64.8 43.272 ;
    END
  END dn2[107]
  PIN dn2[108]
    DIRECTION OUTPUT ;
    USE SIGNAL ;
    PORT
      LAYER M4 ;
        RECT  64.716 43.344 64.8 43.368 ;
    END
  END dn2[108]
  PIN dn2[109]
    DIRECTION OUTPUT ;
    USE SIGNAL ;
    PORT
      LAYER M4 ;
        RECT  64.716 43.44 64.8 43.464 ;
    END
  END dn2[109]
  PIN dn2[10]
    DIRECTION OUTPUT ;
    USE SIGNAL ;
    PORT
      LAYER M4 ;
        RECT  64.716 36.24 64.8 36.264 ;
    END
  END dn2[10]
  PIN dn2[110]
    DIRECTION OUTPUT ;
    USE SIGNAL ;
    PORT
      LAYER M4 ;
        RECT  64.716 43.536 64.8 43.56 ;
    END
  END dn2[110]
  PIN dn2[111]
    DIRECTION OUTPUT ;
    USE SIGNAL ;
    PORT
      LAYER M4 ;
        RECT  64.716 43.632 64.8 43.656 ;
    END
  END dn2[111]
  PIN dn2[112]
    DIRECTION OUTPUT ;
    USE SIGNAL ;
    PORT
      LAYER M4 ;
        RECT  64.716 43.728 64.8 43.752 ;
    END
  END dn2[112]
  PIN dn2[113]
    DIRECTION OUTPUT ;
    USE SIGNAL ;
    PORT
      LAYER M4 ;
        RECT  64.716 43.824 64.8 43.848 ;
    END
  END dn2[113]
  PIN dn2[114]
    DIRECTION OUTPUT ;
    USE SIGNAL ;
    PORT
      LAYER M4 ;
        RECT  64.716 43.92 64.8 43.944 ;
    END
  END dn2[114]
  PIN dn2[115]
    DIRECTION OUTPUT ;
    USE SIGNAL ;
    PORT
      LAYER M4 ;
        RECT  64.716 44.016 64.8 44.04 ;
    END
  END dn2[115]
  PIN dn2[116]
    DIRECTION OUTPUT ;
    USE SIGNAL ;
    PORT
      LAYER M4 ;
        RECT  64.716 44.112 64.8 44.136 ;
    END
  END dn2[116]
  PIN dn2[117]
    DIRECTION OUTPUT ;
    USE SIGNAL ;
    PORT
      LAYER M4 ;
        RECT  64.716 44.208 64.8 44.232 ;
    END
  END dn2[117]
  PIN dn2[118]
    DIRECTION OUTPUT ;
    USE SIGNAL ;
    PORT
      LAYER M4 ;
        RECT  64.716 44.304 64.8 44.328 ;
    END
  END dn2[118]
  PIN dn2[119]
    DIRECTION OUTPUT ;
    USE SIGNAL ;
    PORT
      LAYER M4 ;
        RECT  64.716 44.4 64.8 44.424 ;
    END
  END dn2[119]
  PIN dn2[11]
    DIRECTION OUTPUT ;
    USE SIGNAL ;
    PORT
      LAYER M4 ;
        RECT  64.716 36.336 64.8 36.36 ;
    END
  END dn2[11]
  PIN dn2[120]
    DIRECTION OUTPUT ;
    USE SIGNAL ;
    PORT
      LAYER M4 ;
        RECT  64.716 44.496 64.8 44.52 ;
    END
  END dn2[120]
  PIN dn2[121]
    DIRECTION OUTPUT ;
    USE SIGNAL ;
    PORT
      LAYER M4 ;
        RECT  64.716 44.592 64.8 44.616 ;
    END
  END dn2[121]
  PIN dn2[122]
    DIRECTION OUTPUT ;
    USE SIGNAL ;
    PORT
      LAYER M4 ;
        RECT  64.716 44.688 64.8 44.712 ;
    END
  END dn2[122]
  PIN dn2[123]
    DIRECTION OUTPUT ;
    USE SIGNAL ;
    PORT
      LAYER M4 ;
        RECT  64.716 44.784 64.8 44.808 ;
    END
  END dn2[123]
  PIN dn2[124]
    DIRECTION OUTPUT ;
    USE SIGNAL ;
    PORT
      LAYER M4 ;
        RECT  64.716 44.88 64.8 44.904 ;
    END
  END dn2[124]
  PIN dn2[125]
    DIRECTION OUTPUT ;
    USE SIGNAL ;
    PORT
      LAYER M4 ;
        RECT  64.716 44.976 64.8 45 ;
    END
  END dn2[125]
  PIN dn2[126]
    DIRECTION OUTPUT ;
    USE SIGNAL ;
    PORT
      LAYER M4 ;
        RECT  64.716 45.072 64.8 45.096 ;
    END
  END dn2[126]
  PIN dn2[127]
    DIRECTION OUTPUT ;
    USE SIGNAL ;
    PORT
      LAYER M4 ;
        RECT  64.716 45.168 64.8 45.192 ;
    END
  END dn2[127]
  PIN dn2[128]
    DIRECTION OUTPUT ;
    USE SIGNAL ;
    PORT
      LAYER M4 ;
        RECT  64.716 16.08 64.8 16.104 ;
    END
  END dn2[128]
  PIN dn2[129]
    DIRECTION OUTPUT ;
    USE SIGNAL ;
    PORT
      LAYER M4 ;
        RECT  64.716 16.176 64.8 16.2 ;
    END
  END dn2[129]
  PIN dn2[12]
    DIRECTION OUTPUT ;
    USE SIGNAL ;
    PORT
      LAYER M4 ;
        RECT  64.716 36.432 64.8 36.456 ;
    END
  END dn2[12]
  PIN dn2[130]
    DIRECTION OUTPUT ;
    USE SIGNAL ;
    PORT
      LAYER M4 ;
        RECT  64.716 16.272 64.8 16.296 ;
    END
  END dn2[130]
  PIN dn2[131]
    DIRECTION OUTPUT ;
    USE SIGNAL ;
    PORT
      LAYER M4 ;
        RECT  64.716 16.368 64.8 16.392 ;
    END
  END dn2[131]
  PIN dn2[132]
    DIRECTION OUTPUT ;
    USE SIGNAL ;
    PORT
      LAYER M4 ;
        RECT  64.716 16.464 64.8 16.488 ;
    END
  END dn2[132]
  PIN dn2[133]
    DIRECTION OUTPUT ;
    USE SIGNAL ;
    PORT
      LAYER M4 ;
        RECT  64.716 16.56 64.8 16.584 ;
    END
  END dn2[133]
  PIN dn2[134]
    DIRECTION OUTPUT ;
    USE SIGNAL ;
    PORT
      LAYER M4 ;
        RECT  64.716 16.656 64.8 16.68 ;
    END
  END dn2[134]
  PIN dn2[135]
    DIRECTION OUTPUT ;
    USE SIGNAL ;
    PORT
      LAYER M4 ;
        RECT  64.716 16.752 64.8 16.776 ;
    END
  END dn2[135]
  PIN dn2[136]
    DIRECTION OUTPUT ;
    USE SIGNAL ;
    PORT
      LAYER M4 ;
        RECT  64.716 16.848 64.8 16.872 ;
    END
  END dn2[136]
  PIN dn2[137]
    DIRECTION OUTPUT ;
    USE SIGNAL ;
    PORT
      LAYER M4 ;
        RECT  64.716 16.944 64.8 16.968 ;
    END
  END dn2[137]
  PIN dn2[138]
    DIRECTION OUTPUT ;
    USE SIGNAL ;
    PORT
      LAYER M4 ;
        RECT  64.716 17.04 64.8 17.064 ;
    END
  END dn2[138]
  PIN dn2[139]
    DIRECTION OUTPUT ;
    USE SIGNAL ;
    PORT
      LAYER M4 ;
        RECT  64.716 17.136 64.8 17.16 ;
    END
  END dn2[139]
  PIN dn2[13]
    DIRECTION OUTPUT ;
    USE SIGNAL ;
    PORT
      LAYER M4 ;
        RECT  64.716 36.528 64.8 36.552 ;
    END
  END dn2[13]
  PIN dn2[140]
    DIRECTION OUTPUT ;
    USE SIGNAL ;
    PORT
      LAYER M4 ;
        RECT  64.716 17.232 64.8 17.256 ;
    END
  END dn2[140]
  PIN dn2[141]
    DIRECTION OUTPUT ;
    USE SIGNAL ;
    PORT
      LAYER M4 ;
        RECT  64.716 17.328 64.8 17.352 ;
    END
  END dn2[141]
  PIN dn2[142]
    DIRECTION OUTPUT ;
    USE SIGNAL ;
    PORT
      LAYER M4 ;
        RECT  64.716 17.424 64.8 17.448 ;
    END
  END dn2[142]
  PIN dn2[143]
    DIRECTION OUTPUT ;
    USE SIGNAL ;
    PORT
      LAYER M4 ;
        RECT  64.716 17.52 64.8 17.544 ;
    END
  END dn2[143]
  PIN dn2[144]
    DIRECTION OUTPUT ;
    USE SIGNAL ;
    PORT
      LAYER M4 ;
        RECT  64.716 17.616 64.8 17.64 ;
    END
  END dn2[144]
  PIN dn2[145]
    DIRECTION OUTPUT ;
    USE SIGNAL ;
    PORT
      LAYER M4 ;
        RECT  64.716 17.712 64.8 17.736 ;
    END
  END dn2[145]
  PIN dn2[146]
    DIRECTION OUTPUT ;
    USE SIGNAL ;
    PORT
      LAYER M4 ;
        RECT  64.716 17.808 64.8 17.832 ;
    END
  END dn2[146]
  PIN dn2[147]
    DIRECTION OUTPUT ;
    USE SIGNAL ;
    PORT
      LAYER M4 ;
        RECT  64.716 17.904 64.8 17.928 ;
    END
  END dn2[147]
  PIN dn2[148]
    DIRECTION OUTPUT ;
    USE SIGNAL ;
    PORT
      LAYER M4 ;
        RECT  64.716 18 64.8 18.024 ;
    END
  END dn2[148]
  PIN dn2[149]
    DIRECTION OUTPUT ;
    USE SIGNAL ;
    PORT
      LAYER M4 ;
        RECT  64.716 18.096 64.8 18.12 ;
    END
  END dn2[149]
  PIN dn2[14]
    DIRECTION OUTPUT ;
    USE SIGNAL ;
    PORT
      LAYER M4 ;
        RECT  64.716 36.624 64.8 36.648 ;
    END
  END dn2[14]
  PIN dn2[150]
    DIRECTION OUTPUT ;
    USE SIGNAL ;
    PORT
      LAYER M4 ;
        RECT  64.716 18.192 64.8 18.216 ;
    END
  END dn2[150]
  PIN dn2[151]
    DIRECTION OUTPUT ;
    USE SIGNAL ;
    PORT
      LAYER M4 ;
        RECT  64.716 18.288 64.8 18.312 ;
    END
  END dn2[151]
  PIN dn2[152]
    DIRECTION OUTPUT ;
    USE SIGNAL ;
    PORT
      LAYER M4 ;
        RECT  64.716 18.384 64.8 18.408 ;
    END
  END dn2[152]
  PIN dn2[153]
    DIRECTION OUTPUT ;
    USE SIGNAL ;
    PORT
      LAYER M4 ;
        RECT  64.716 18.48 64.8 18.504 ;
    END
  END dn2[153]
  PIN dn2[154]
    DIRECTION OUTPUT ;
    USE SIGNAL ;
    PORT
      LAYER M4 ;
        RECT  64.716 18.576 64.8 18.6 ;
    END
  END dn2[154]
  PIN dn2[155]
    DIRECTION OUTPUT ;
    USE SIGNAL ;
    PORT
      LAYER M4 ;
        RECT  64.716 18.672 64.8 18.696 ;
    END
  END dn2[155]
  PIN dn2[156]
    DIRECTION OUTPUT ;
    USE SIGNAL ;
    PORT
      LAYER M4 ;
        RECT  64.716 18.768 64.8 18.792 ;
    END
  END dn2[156]
  PIN dn2[157]
    DIRECTION OUTPUT ;
    USE SIGNAL ;
    PORT
      LAYER M4 ;
        RECT  64.716 18.864 64.8 18.888 ;
    END
  END dn2[157]
  PIN dn2[158]
    DIRECTION OUTPUT ;
    USE SIGNAL ;
    PORT
      LAYER M4 ;
        RECT  64.716 18.96 64.8 18.984 ;
    END
  END dn2[158]
  PIN dn2[159]
    DIRECTION OUTPUT ;
    USE SIGNAL ;
    PORT
      LAYER M4 ;
        RECT  64.716 19.056 64.8 19.08 ;
    END
  END dn2[159]
  PIN dn2[15]
    DIRECTION OUTPUT ;
    USE SIGNAL ;
    PORT
      LAYER M4 ;
        RECT  64.716 36.72 64.8 36.744 ;
    END
  END dn2[15]
  PIN dn2[160]
    DIRECTION OUTPUT ;
    USE SIGNAL ;
    PORT
      LAYER M4 ;
        RECT  64.716 6.864 64.8 6.888 ;
    END
  END dn2[160]
  PIN dn2[161]
    DIRECTION OUTPUT ;
    USE SIGNAL ;
    PORT
      LAYER M4 ;
        RECT  64.716 6.96 64.8 6.984 ;
    END
  END dn2[161]
  PIN dn2[162]
    DIRECTION OUTPUT ;
    USE SIGNAL ;
    PORT
      LAYER M4 ;
        RECT  64.716 7.056 64.8 7.08 ;
    END
  END dn2[162]
  PIN dn2[163]
    DIRECTION OUTPUT ;
    USE SIGNAL ;
    PORT
      LAYER M4 ;
        RECT  64.716 7.152 64.8 7.176 ;
    END
  END dn2[163]
  PIN dn2[164]
    DIRECTION OUTPUT ;
    USE SIGNAL ;
    PORT
      LAYER M4 ;
        RECT  64.716 7.248 64.8 7.272 ;
    END
  END dn2[164]
  PIN dn2[165]
    DIRECTION OUTPUT ;
    USE SIGNAL ;
    PORT
      LAYER M4 ;
        RECT  64.716 7.344 64.8 7.368 ;
    END
  END dn2[165]
  PIN dn2[166]
    DIRECTION OUTPUT ;
    USE SIGNAL ;
    PORT
      LAYER M4 ;
        RECT  64.716 7.44 64.8 7.464 ;
    END
  END dn2[166]
  PIN dn2[167]
    DIRECTION OUTPUT ;
    USE SIGNAL ;
    PORT
      LAYER M4 ;
        RECT  64.716 7.536 64.8 7.56 ;
    END
  END dn2[167]
  PIN dn2[168]
    DIRECTION OUTPUT ;
    USE SIGNAL ;
    PORT
      LAYER M4 ;
        RECT  64.716 7.632 64.8 7.656 ;
    END
  END dn2[168]
  PIN dn2[169]
    DIRECTION OUTPUT ;
    USE SIGNAL ;
    PORT
      LAYER M4 ;
        RECT  64.716 7.728 64.8 7.752 ;
    END
  END dn2[169]
  PIN dn2[16]
    DIRECTION OUTPUT ;
    USE SIGNAL ;
    PORT
      LAYER M4 ;
        RECT  64.716 36.816 64.8 36.84 ;
    END
  END dn2[16]
  PIN dn2[170]
    DIRECTION OUTPUT ;
    USE SIGNAL ;
    PORT
      LAYER M4 ;
        RECT  64.716 7.824 64.8 7.848 ;
    END
  END dn2[170]
  PIN dn2[171]
    DIRECTION OUTPUT ;
    USE SIGNAL ;
    PORT
      LAYER M4 ;
        RECT  64.716 7.92 64.8 7.944 ;
    END
  END dn2[171]
  PIN dn2[172]
    DIRECTION OUTPUT ;
    USE SIGNAL ;
    PORT
      LAYER M4 ;
        RECT  64.716 8.016 64.8 8.04 ;
    END
  END dn2[172]
  PIN dn2[173]
    DIRECTION OUTPUT ;
    USE SIGNAL ;
    PORT
      LAYER M4 ;
        RECT  64.716 8.112 64.8 8.136 ;
    END
  END dn2[173]
  PIN dn2[174]
    DIRECTION OUTPUT ;
    USE SIGNAL ;
    PORT
      LAYER M4 ;
        RECT  64.716 8.208 64.8 8.232 ;
    END
  END dn2[174]
  PIN dn2[175]
    DIRECTION OUTPUT ;
    USE SIGNAL ;
    PORT
      LAYER M4 ;
        RECT  64.716 8.304 64.8 8.328 ;
    END
  END dn2[175]
  PIN dn2[176]
    DIRECTION OUTPUT ;
    USE SIGNAL ;
    PORT
      LAYER M4 ;
        RECT  64.716 8.4 64.8 8.424 ;
    END
  END dn2[176]
  PIN dn2[177]
    DIRECTION OUTPUT ;
    USE SIGNAL ;
    PORT
      LAYER M4 ;
        RECT  64.716 8.496 64.8 8.52 ;
    END
  END dn2[177]
  PIN dn2[178]
    DIRECTION OUTPUT ;
    USE SIGNAL ;
    PORT
      LAYER M4 ;
        RECT  64.716 8.592 64.8 8.616 ;
    END
  END dn2[178]
  PIN dn2[179]
    DIRECTION OUTPUT ;
    USE SIGNAL ;
    PORT
      LAYER M4 ;
        RECT  64.716 8.688 64.8 8.712 ;
    END
  END dn2[179]
  PIN dn2[17]
    DIRECTION OUTPUT ;
    USE SIGNAL ;
    PORT
      LAYER M4 ;
        RECT  64.716 36.912 64.8 36.936 ;
    END
  END dn2[17]
  PIN dn2[180]
    DIRECTION OUTPUT ;
    USE SIGNAL ;
    PORT
      LAYER M4 ;
        RECT  64.716 8.784 64.8 8.808 ;
    END
  END dn2[180]
  PIN dn2[181]
    DIRECTION OUTPUT ;
    USE SIGNAL ;
    PORT
      LAYER M4 ;
        RECT  64.716 8.88 64.8 8.904 ;
    END
  END dn2[181]
  PIN dn2[182]
    DIRECTION OUTPUT ;
    USE SIGNAL ;
    PORT
      LAYER M4 ;
        RECT  64.716 8.976 64.8 9 ;
    END
  END dn2[182]
  PIN dn2[183]
    DIRECTION OUTPUT ;
    USE SIGNAL ;
    PORT
      LAYER M4 ;
        RECT  64.716 9.072 64.8 9.096 ;
    END
  END dn2[183]
  PIN dn2[184]
    DIRECTION OUTPUT ;
    USE SIGNAL ;
    PORT
      LAYER M4 ;
        RECT  64.716 9.168 64.8 9.192 ;
    END
  END dn2[184]
  PIN dn2[185]
    DIRECTION OUTPUT ;
    USE SIGNAL ;
    PORT
      LAYER M4 ;
        RECT  64.716 9.264 64.8 9.288 ;
    END
  END dn2[185]
  PIN dn2[186]
    DIRECTION OUTPUT ;
    USE SIGNAL ;
    PORT
      LAYER M4 ;
        RECT  64.716 9.36 64.8 9.384 ;
    END
  END dn2[186]
  PIN dn2[187]
    DIRECTION OUTPUT ;
    USE SIGNAL ;
    PORT
      LAYER M4 ;
        RECT  64.716 9.456 64.8 9.48 ;
    END
  END dn2[187]
  PIN dn2[188]
    DIRECTION OUTPUT ;
    USE SIGNAL ;
    PORT
      LAYER M4 ;
        RECT  64.716 9.552 64.8 9.576 ;
    END
  END dn2[188]
  PIN dn2[189]
    DIRECTION OUTPUT ;
    USE SIGNAL ;
    PORT
      LAYER M4 ;
        RECT  64.716 9.648 64.8 9.672 ;
    END
  END dn2[189]
  PIN dn2[18]
    DIRECTION OUTPUT ;
    USE SIGNAL ;
    PORT
      LAYER M4 ;
        RECT  64.716 37.008 64.8 37.032 ;
    END
  END dn2[18]
  PIN dn2[190]
    DIRECTION OUTPUT ;
    USE SIGNAL ;
    PORT
      LAYER M4 ;
        RECT  64.716 9.744 64.8 9.768 ;
    END
  END dn2[190]
  PIN dn2[191]
    DIRECTION OUTPUT ;
    USE SIGNAL ;
    PORT
      LAYER M4 ;
        RECT  64.716 9.84 64.8 9.864 ;
    END
  END dn2[191]
  PIN dn2[192]
    DIRECTION OUTPUT ;
    USE SIGNAL ;
    PORT
      LAYER M4 ;
        RECT  64.716 9.936 64.8 9.96 ;
    END
  END dn2[192]
  PIN dn2[193]
    DIRECTION OUTPUT ;
    USE SIGNAL ;
    PORT
      LAYER M4 ;
        RECT  64.716 10.032 64.8 10.056 ;
    END
  END dn2[193]
  PIN dn2[194]
    DIRECTION OUTPUT ;
    USE SIGNAL ;
    PORT
      LAYER M4 ;
        RECT  64.716 10.128 64.8 10.152 ;
    END
  END dn2[194]
  PIN dn2[195]
    DIRECTION OUTPUT ;
    USE SIGNAL ;
    PORT
      LAYER M4 ;
        RECT  64.716 10.224 64.8 10.248 ;
    END
  END dn2[195]
  PIN dn2[196]
    DIRECTION OUTPUT ;
    USE SIGNAL ;
    PORT
      LAYER M4 ;
        RECT  64.716 10.32 64.8 10.344 ;
    END
  END dn2[196]
  PIN dn2[197]
    DIRECTION OUTPUT ;
    USE SIGNAL ;
    PORT
      LAYER M4 ;
        RECT  64.716 10.416 64.8 10.44 ;
    END
  END dn2[197]
  PIN dn2[198]
    DIRECTION OUTPUT ;
    USE SIGNAL ;
    PORT
      LAYER M4 ;
        RECT  64.716 10.512 64.8 10.536 ;
    END
  END dn2[198]
  PIN dn2[199]
    DIRECTION OUTPUT ;
    USE SIGNAL ;
    PORT
      LAYER M4 ;
        RECT  64.716 10.608 64.8 10.632 ;
    END
  END dn2[199]
  PIN dn2[19]
    DIRECTION OUTPUT ;
    USE SIGNAL ;
    PORT
      LAYER M4 ;
        RECT  64.716 37.104 64.8 37.128 ;
    END
  END dn2[19]
  PIN dn2[1]
    DIRECTION OUTPUT ;
    USE SIGNAL ;
    PORT
      LAYER M4 ;
        RECT  64.716 35.376 64.8 35.4 ;
    END
  END dn2[1]
  PIN dn2[200]
    DIRECTION OUTPUT ;
    USE SIGNAL ;
    PORT
      LAYER M4 ;
        RECT  64.716 10.704 64.8 10.728 ;
    END
  END dn2[200]
  PIN dn2[201]
    DIRECTION OUTPUT ;
    USE SIGNAL ;
    PORT
      LAYER M4 ;
        RECT  64.716 10.8 64.8 10.824 ;
    END
  END dn2[201]
  PIN dn2[202]
    DIRECTION OUTPUT ;
    USE SIGNAL ;
    PORT
      LAYER M4 ;
        RECT  64.716 10.896 64.8 10.92 ;
    END
  END dn2[202]
  PIN dn2[203]
    DIRECTION OUTPUT ;
    USE SIGNAL ;
    PORT
      LAYER M4 ;
        RECT  64.716 10.992 64.8 11.016 ;
    END
  END dn2[203]
  PIN dn2[204]
    DIRECTION OUTPUT ;
    USE SIGNAL ;
    PORT
      LAYER M4 ;
        RECT  64.716 11.088 64.8 11.112 ;
    END
  END dn2[204]
  PIN dn2[205]
    DIRECTION OUTPUT ;
    USE SIGNAL ;
    PORT
      LAYER M4 ;
        RECT  64.716 11.184 64.8 11.208 ;
    END
  END dn2[205]
  PIN dn2[206]
    DIRECTION OUTPUT ;
    USE SIGNAL ;
    PORT
      LAYER M4 ;
        RECT  64.716 11.28 64.8 11.304 ;
    END
  END dn2[206]
  PIN dn2[207]
    DIRECTION OUTPUT ;
    USE SIGNAL ;
    PORT
      LAYER M4 ;
        RECT  64.716 11.376 64.8 11.4 ;
    END
  END dn2[207]
  PIN dn2[208]
    DIRECTION OUTPUT ;
    USE SIGNAL ;
    PORT
      LAYER M4 ;
        RECT  64.716 11.472 64.8 11.496 ;
    END
  END dn2[208]
  PIN dn2[209]
    DIRECTION OUTPUT ;
    USE SIGNAL ;
    PORT
      LAYER M4 ;
        RECT  64.716 11.568 64.8 11.592 ;
    END
  END dn2[209]
  PIN dn2[20]
    DIRECTION OUTPUT ;
    USE SIGNAL ;
    PORT
      LAYER M4 ;
        RECT  64.716 37.2 64.8 37.224 ;
    END
  END dn2[20]
  PIN dn2[210]
    DIRECTION OUTPUT ;
    USE SIGNAL ;
    PORT
      LAYER M4 ;
        RECT  64.716 11.664 64.8 11.688 ;
    END
  END dn2[210]
  PIN dn2[211]
    DIRECTION OUTPUT ;
    USE SIGNAL ;
    PORT
      LAYER M4 ;
        RECT  64.716 11.76 64.8 11.784 ;
    END
  END dn2[211]
  PIN dn2[212]
    DIRECTION OUTPUT ;
    USE SIGNAL ;
    PORT
      LAYER M4 ;
        RECT  64.716 11.856 64.8 11.88 ;
    END
  END dn2[212]
  PIN dn2[213]
    DIRECTION OUTPUT ;
    USE SIGNAL ;
    PORT
      LAYER M4 ;
        RECT  64.716 11.952 64.8 11.976 ;
    END
  END dn2[213]
  PIN dn2[214]
    DIRECTION OUTPUT ;
    USE SIGNAL ;
    PORT
      LAYER M4 ;
        RECT  64.716 12.048 64.8 12.072 ;
    END
  END dn2[214]
  PIN dn2[215]
    DIRECTION OUTPUT ;
    USE SIGNAL ;
    PORT
      LAYER M4 ;
        RECT  64.716 12.144 64.8 12.168 ;
    END
  END dn2[215]
  PIN dn2[216]
    DIRECTION OUTPUT ;
    USE SIGNAL ;
    PORT
      LAYER M4 ;
        RECT  64.716 12.24 64.8 12.264 ;
    END
  END dn2[216]
  PIN dn2[217]
    DIRECTION OUTPUT ;
    USE SIGNAL ;
    PORT
      LAYER M4 ;
        RECT  64.716 12.336 64.8 12.36 ;
    END
  END dn2[217]
  PIN dn2[218]
    DIRECTION OUTPUT ;
    USE SIGNAL ;
    PORT
      LAYER M4 ;
        RECT  64.716 12.432 64.8 12.456 ;
    END
  END dn2[218]
  PIN dn2[219]
    DIRECTION OUTPUT ;
    USE SIGNAL ;
    PORT
      LAYER M4 ;
        RECT  64.716 12.528 64.8 12.552 ;
    END
  END dn2[219]
  PIN dn2[21]
    DIRECTION OUTPUT ;
    USE SIGNAL ;
    PORT
      LAYER M4 ;
        RECT  64.716 37.296 64.8 37.32 ;
    END
  END dn2[21]
  PIN dn2[220]
    DIRECTION OUTPUT ;
    USE SIGNAL ;
    PORT
      LAYER M4 ;
        RECT  64.716 12.624 64.8 12.648 ;
    END
  END dn2[220]
  PIN dn2[221]
    DIRECTION OUTPUT ;
    USE SIGNAL ;
    PORT
      LAYER M4 ;
        RECT  64.716 12.72 64.8 12.744 ;
    END
  END dn2[221]
  PIN dn2[222]
    DIRECTION OUTPUT ;
    USE SIGNAL ;
    PORT
      LAYER M4 ;
        RECT  64.716 12.816 64.8 12.84 ;
    END
  END dn2[222]
  PIN dn2[223]
    DIRECTION OUTPUT ;
    USE SIGNAL ;
    PORT
      LAYER M4 ;
        RECT  64.716 12.912 64.8 12.936 ;
    END
  END dn2[223]
  PIN dn2[224]
    DIRECTION OUTPUT ;
    USE SIGNAL ;
    PORT
      LAYER M4 ;
        RECT  64.716 26.064 64.8 26.088 ;
    END
  END dn2[224]
  PIN dn2[225]
    DIRECTION OUTPUT ;
    USE SIGNAL ;
    PORT
      LAYER M4 ;
        RECT  64.716 26.16 64.8 26.184 ;
    END
  END dn2[225]
  PIN dn2[226]
    DIRECTION OUTPUT ;
    USE SIGNAL ;
    PORT
      LAYER M4 ;
        RECT  64.716 26.256 64.8 26.28 ;
    END
  END dn2[226]
  PIN dn2[227]
    DIRECTION OUTPUT ;
    USE SIGNAL ;
    PORT
      LAYER M4 ;
        RECT  64.716 26.352 64.8 26.376 ;
    END
  END dn2[227]
  PIN dn2[22]
    DIRECTION OUTPUT ;
    USE SIGNAL ;
    PORT
      LAYER M4 ;
        RECT  64.716 37.392 64.8 37.416 ;
    END
  END dn2[22]
  PIN dn2[23]
    DIRECTION OUTPUT ;
    USE SIGNAL ;
    PORT
      LAYER M4 ;
        RECT  64.716 37.488 64.8 37.512 ;
    END
  END dn2[23]
  PIN dn2[24]
    DIRECTION OUTPUT ;
    USE SIGNAL ;
    PORT
      LAYER M4 ;
        RECT  64.716 37.584 64.8 37.608 ;
    END
  END dn2[24]
  PIN dn2[25]
    DIRECTION OUTPUT ;
    USE SIGNAL ;
    PORT
      LAYER M4 ;
        RECT  64.716 37.68 64.8 37.704 ;
    END
  END dn2[25]
  PIN dn2[26]
    DIRECTION OUTPUT ;
    USE SIGNAL ;
    PORT
      LAYER M4 ;
        RECT  64.716 37.776 64.8 37.8 ;
    END
  END dn2[26]
  PIN dn2[27]
    DIRECTION OUTPUT ;
    USE SIGNAL ;
    PORT
      LAYER M4 ;
        RECT  64.716 37.872 64.8 37.896 ;
    END
  END dn2[27]
  PIN dn2[28]
    DIRECTION OUTPUT ;
    USE SIGNAL ;
    PORT
      LAYER M4 ;
        RECT  64.716 37.968 64.8 37.992 ;
    END
  END dn2[28]
  PIN dn2[29]
    DIRECTION OUTPUT ;
    USE SIGNAL ;
    PORT
      LAYER M4 ;
        RECT  64.716 38.064 64.8 38.088 ;
    END
  END dn2[29]
  PIN dn2[2]
    DIRECTION OUTPUT ;
    USE SIGNAL ;
    PORT
      LAYER M4 ;
        RECT  64.716 35.472 64.8 35.496 ;
    END
  END dn2[2]
  PIN dn2[30]
    DIRECTION OUTPUT ;
    USE SIGNAL ;
    PORT
      LAYER M4 ;
        RECT  64.716 38.16 64.8 38.184 ;
    END
  END dn2[30]
  PIN dn2[31]
    DIRECTION OUTPUT ;
    USE SIGNAL ;
    PORT
      LAYER M4 ;
        RECT  64.716 38.256 64.8 38.28 ;
    END
  END dn2[31]
  PIN dn2[32]
    DIRECTION OUTPUT ;
    USE SIGNAL ;
    PORT
      LAYER M4 ;
        RECT  64.716 48.336 64.8 48.36 ;
    END
  END dn2[32]
  PIN dn2[33]
    DIRECTION OUTPUT ;
    USE SIGNAL ;
    PORT
      LAYER M4 ;
        RECT  64.716 48.432 64.8 48.456 ;
    END
  END dn2[33]
  PIN dn2[34]
    DIRECTION OUTPUT ;
    USE SIGNAL ;
    PORT
      LAYER M4 ;
        RECT  64.716 48.528 64.8 48.552 ;
    END
  END dn2[34]
  PIN dn2[35]
    DIRECTION OUTPUT ;
    USE SIGNAL ;
    PORT
      LAYER M4 ;
        RECT  64.716 48.624 64.8 48.648 ;
    END
  END dn2[35]
  PIN dn2[36]
    DIRECTION OUTPUT ;
    USE SIGNAL ;
    PORT
      LAYER M4 ;
        RECT  64.716 48.72 64.8 48.744 ;
    END
  END dn2[36]
  PIN dn2[37]
    DIRECTION OUTPUT ;
    USE SIGNAL ;
    PORT
      LAYER M4 ;
        RECT  64.716 48.816 64.8 48.84 ;
    END
  END dn2[37]
  PIN dn2[38]
    DIRECTION OUTPUT ;
    USE SIGNAL ;
    PORT
      LAYER M4 ;
        RECT  64.716 48.912 64.8 48.936 ;
    END
  END dn2[38]
  PIN dn2[39]
    DIRECTION OUTPUT ;
    USE SIGNAL ;
    PORT
      LAYER M4 ;
        RECT  64.716 49.008 64.8 49.032 ;
    END
  END dn2[39]
  PIN dn2[3]
    DIRECTION OUTPUT ;
    USE SIGNAL ;
    PORT
      LAYER M4 ;
        RECT  64.716 35.568 64.8 35.592 ;
    END
  END dn2[3]
  PIN dn2[40]
    DIRECTION OUTPUT ;
    USE SIGNAL ;
    PORT
      LAYER M4 ;
        RECT  64.716 49.104 64.8 49.128 ;
    END
  END dn2[40]
  PIN dn2[41]
    DIRECTION OUTPUT ;
    USE SIGNAL ;
    PORT
      LAYER M4 ;
        RECT  64.716 49.2 64.8 49.224 ;
    END
  END dn2[41]
  PIN dn2[42]
    DIRECTION OUTPUT ;
    USE SIGNAL ;
    PORT
      LAYER M4 ;
        RECT  64.716 49.296 64.8 49.32 ;
    END
  END dn2[42]
  PIN dn2[43]
    DIRECTION OUTPUT ;
    USE SIGNAL ;
    PORT
      LAYER M4 ;
        RECT  64.716 49.392 64.8 49.416 ;
    END
  END dn2[43]
  PIN dn2[44]
    DIRECTION OUTPUT ;
    USE SIGNAL ;
    PORT
      LAYER M4 ;
        RECT  64.716 49.488 64.8 49.512 ;
    END
  END dn2[44]
  PIN dn2[45]
    DIRECTION OUTPUT ;
    USE SIGNAL ;
    PORT
      LAYER M4 ;
        RECT  64.716 49.584 64.8 49.608 ;
    END
  END dn2[45]
  PIN dn2[46]
    DIRECTION OUTPUT ;
    USE SIGNAL ;
    PORT
      LAYER M4 ;
        RECT  64.716 49.68 64.8 49.704 ;
    END
  END dn2[46]
  PIN dn2[47]
    DIRECTION OUTPUT ;
    USE SIGNAL ;
    PORT
      LAYER M4 ;
        RECT  64.716 49.776 64.8 49.8 ;
    END
  END dn2[47]
  PIN dn2[48]
    DIRECTION OUTPUT ;
    USE SIGNAL ;
    PORT
      LAYER M4 ;
        RECT  64.716 49.872 64.8 49.896 ;
    END
  END dn2[48]
  PIN dn2[49]
    DIRECTION OUTPUT ;
    USE SIGNAL ;
    PORT
      LAYER M4 ;
        RECT  64.716 49.968 64.8 49.992 ;
    END
  END dn2[49]
  PIN dn2[4]
    DIRECTION OUTPUT ;
    USE SIGNAL ;
    PORT
      LAYER M4 ;
        RECT  64.716 35.664 64.8 35.688 ;
    END
  END dn2[4]
  PIN dn2[50]
    DIRECTION OUTPUT ;
    USE SIGNAL ;
    PORT
      LAYER M4 ;
        RECT  64.716 50.064 64.8 50.088 ;
    END
  END dn2[50]
  PIN dn2[51]
    DIRECTION OUTPUT ;
    USE SIGNAL ;
    PORT
      LAYER M4 ;
        RECT  64.716 50.16 64.8 50.184 ;
    END
  END dn2[51]
  PIN dn2[52]
    DIRECTION OUTPUT ;
    USE SIGNAL ;
    PORT
      LAYER M4 ;
        RECT  64.716 50.256 64.8 50.28 ;
    END
  END dn2[52]
  PIN dn2[53]
    DIRECTION OUTPUT ;
    USE SIGNAL ;
    PORT
      LAYER M4 ;
        RECT  64.716 50.352 64.8 50.376 ;
    END
  END dn2[53]
  PIN dn2[54]
    DIRECTION OUTPUT ;
    USE SIGNAL ;
    PORT
      LAYER M4 ;
        RECT  64.716 50.448 64.8 50.472 ;
    END
  END dn2[54]
  PIN dn2[55]
    DIRECTION OUTPUT ;
    USE SIGNAL ;
    PORT
      LAYER M4 ;
        RECT  64.716 50.544 64.8 50.568 ;
    END
  END dn2[55]
  PIN dn2[56]
    DIRECTION OUTPUT ;
    USE SIGNAL ;
    PORT
      LAYER M4 ;
        RECT  64.716 50.64 64.8 50.664 ;
    END
  END dn2[56]
  PIN dn2[57]
    DIRECTION OUTPUT ;
    USE SIGNAL ;
    PORT
      LAYER M4 ;
        RECT  64.716 50.736 64.8 50.76 ;
    END
  END dn2[57]
  PIN dn2[58]
    DIRECTION OUTPUT ;
    USE SIGNAL ;
    PORT
      LAYER M4 ;
        RECT  64.716 50.832 64.8 50.856 ;
    END
  END dn2[58]
  PIN dn2[59]
    DIRECTION OUTPUT ;
    USE SIGNAL ;
    PORT
      LAYER M4 ;
        RECT  64.716 50.928 64.8 50.952 ;
    END
  END dn2[59]
  PIN dn2[5]
    DIRECTION OUTPUT ;
    USE SIGNAL ;
    PORT
      LAYER M4 ;
        RECT  64.716 35.76 64.8 35.784 ;
    END
  END dn2[5]
  PIN dn2[60]
    DIRECTION OUTPUT ;
    USE SIGNAL ;
    PORT
      LAYER M4 ;
        RECT  64.716 51.024 64.8 51.048 ;
    END
  END dn2[60]
  PIN dn2[61]
    DIRECTION OUTPUT ;
    USE SIGNAL ;
    PORT
      LAYER M4 ;
        RECT  64.716 51.12 64.8 51.144 ;
    END
  END dn2[61]
  PIN dn2[62]
    DIRECTION OUTPUT ;
    USE SIGNAL ;
    PORT
      LAYER M4 ;
        RECT  64.716 51.216 64.8 51.24 ;
    END
  END dn2[62]
  PIN dn2[63]
    DIRECTION OUTPUT ;
    USE SIGNAL ;
    PORT
      LAYER M4 ;
        RECT  64.716 51.312 64.8 51.336 ;
    END
  END dn2[63]
  PIN dn2[64]
    DIRECTION OUTPUT ;
    USE SIGNAL ;
    PORT
      LAYER M4 ;
        RECT  64.716 45.264 64.8 45.288 ;
    END
  END dn2[64]
  PIN dn2[65]
    DIRECTION OUTPUT ;
    USE SIGNAL ;
    PORT
      LAYER M4 ;
        RECT  64.716 45.36 64.8 45.384 ;
    END
  END dn2[65]
  PIN dn2[66]
    DIRECTION OUTPUT ;
    USE SIGNAL ;
    PORT
      LAYER M4 ;
        RECT  64.716 45.456 64.8 45.48 ;
    END
  END dn2[66]
  PIN dn2[67]
    DIRECTION OUTPUT ;
    USE SIGNAL ;
    PORT
      LAYER M4 ;
        RECT  64.716 45.552 64.8 45.576 ;
    END
  END dn2[67]
  PIN dn2[68]
    DIRECTION OUTPUT ;
    USE SIGNAL ;
    PORT
      LAYER M4 ;
        RECT  64.716 45.648 64.8 45.672 ;
    END
  END dn2[68]
  PIN dn2[69]
    DIRECTION OUTPUT ;
    USE SIGNAL ;
    PORT
      LAYER M4 ;
        RECT  64.716 45.744 64.8 45.768 ;
    END
  END dn2[69]
  PIN dn2[6]
    DIRECTION OUTPUT ;
    USE SIGNAL ;
    PORT
      LAYER M4 ;
        RECT  64.716 35.856 64.8 35.88 ;
    END
  END dn2[6]
  PIN dn2[70]
    DIRECTION OUTPUT ;
    USE SIGNAL ;
    PORT
      LAYER M4 ;
        RECT  64.716 45.84 64.8 45.864 ;
    END
  END dn2[70]
  PIN dn2[71]
    DIRECTION OUTPUT ;
    USE SIGNAL ;
    PORT
      LAYER M4 ;
        RECT  64.716 45.936 64.8 45.96 ;
    END
  END dn2[71]
  PIN dn2[72]
    DIRECTION OUTPUT ;
    USE SIGNAL ;
    PORT
      LAYER M4 ;
        RECT  64.716 46.032 64.8 46.056 ;
    END
  END dn2[72]
  PIN dn2[73]
    DIRECTION OUTPUT ;
    USE SIGNAL ;
    PORT
      LAYER M4 ;
        RECT  64.716 46.128 64.8 46.152 ;
    END
  END dn2[73]
  PIN dn2[74]
    DIRECTION OUTPUT ;
    USE SIGNAL ;
    PORT
      LAYER M4 ;
        RECT  64.716 46.224 64.8 46.248 ;
    END
  END dn2[74]
  PIN dn2[75]
    DIRECTION OUTPUT ;
    USE SIGNAL ;
    PORT
      LAYER M4 ;
        RECT  64.716 46.32 64.8 46.344 ;
    END
  END dn2[75]
  PIN dn2[76]
    DIRECTION OUTPUT ;
    USE SIGNAL ;
    PORT
      LAYER M4 ;
        RECT  64.716 46.416 64.8 46.44 ;
    END
  END dn2[76]
  PIN dn2[77]
    DIRECTION OUTPUT ;
    USE SIGNAL ;
    PORT
      LAYER M4 ;
        RECT  64.716 46.512 64.8 46.536 ;
    END
  END dn2[77]
  PIN dn2[78]
    DIRECTION OUTPUT ;
    USE SIGNAL ;
    PORT
      LAYER M4 ;
        RECT  64.716 46.608 64.8 46.632 ;
    END
  END dn2[78]
  PIN dn2[79]
    DIRECTION OUTPUT ;
    USE SIGNAL ;
    PORT
      LAYER M4 ;
        RECT  64.716 46.704 64.8 46.728 ;
    END
  END dn2[79]
  PIN dn2[7]
    DIRECTION OUTPUT ;
    USE SIGNAL ;
    PORT
      LAYER M4 ;
        RECT  64.716 35.952 64.8 35.976 ;
    END
  END dn2[7]
  PIN dn2[80]
    DIRECTION OUTPUT ;
    USE SIGNAL ;
    PORT
      LAYER M4 ;
        RECT  64.716 46.8 64.8 46.824 ;
    END
  END dn2[80]
  PIN dn2[81]
    DIRECTION OUTPUT ;
    USE SIGNAL ;
    PORT
      LAYER M4 ;
        RECT  64.716 46.896 64.8 46.92 ;
    END
  END dn2[81]
  PIN dn2[82]
    DIRECTION OUTPUT ;
    USE SIGNAL ;
    PORT
      LAYER M4 ;
        RECT  64.716 46.992 64.8 47.016 ;
    END
  END dn2[82]
  PIN dn2[83]
    DIRECTION OUTPUT ;
    USE SIGNAL ;
    PORT
      LAYER M4 ;
        RECT  64.716 47.088 64.8 47.112 ;
    END
  END dn2[83]
  PIN dn2[84]
    DIRECTION OUTPUT ;
    USE SIGNAL ;
    PORT
      LAYER M4 ;
        RECT  64.716 47.184 64.8 47.208 ;
    END
  END dn2[84]
  PIN dn2[85]
    DIRECTION OUTPUT ;
    USE SIGNAL ;
    PORT
      LAYER M4 ;
        RECT  64.716 47.28 64.8 47.304 ;
    END
  END dn2[85]
  PIN dn2[86]
    DIRECTION OUTPUT ;
    USE SIGNAL ;
    PORT
      LAYER M4 ;
        RECT  64.716 47.376 64.8 47.4 ;
    END
  END dn2[86]
  PIN dn2[87]
    DIRECTION OUTPUT ;
    USE SIGNAL ;
    PORT
      LAYER M4 ;
        RECT  64.716 47.472 64.8 47.496 ;
    END
  END dn2[87]
  PIN dn2[88]
    DIRECTION OUTPUT ;
    USE SIGNAL ;
    PORT
      LAYER M4 ;
        RECT  64.716 47.568 64.8 47.592 ;
    END
  END dn2[88]
  PIN dn2[89]
    DIRECTION OUTPUT ;
    USE SIGNAL ;
    PORT
      LAYER M4 ;
        RECT  64.716 47.664 64.8 47.688 ;
    END
  END dn2[89]
  PIN dn2[8]
    DIRECTION OUTPUT ;
    USE SIGNAL ;
    PORT
      LAYER M4 ;
        RECT  64.716 36.048 64.8 36.072 ;
    END
  END dn2[8]
  PIN dn2[90]
    DIRECTION OUTPUT ;
    USE SIGNAL ;
    PORT
      LAYER M4 ;
        RECT  64.716 47.76 64.8 47.784 ;
    END
  END dn2[90]
  PIN dn2[91]
    DIRECTION OUTPUT ;
    USE SIGNAL ;
    PORT
      LAYER M4 ;
        RECT  64.716 47.856 64.8 47.88 ;
    END
  END dn2[91]
  PIN dn2[92]
    DIRECTION OUTPUT ;
    USE SIGNAL ;
    PORT
      LAYER M4 ;
        RECT  64.716 47.952 64.8 47.976 ;
    END
  END dn2[92]
  PIN dn2[93]
    DIRECTION OUTPUT ;
    USE SIGNAL ;
    PORT
      LAYER M4 ;
        RECT  64.716 48.048 64.8 48.072 ;
    END
  END dn2[93]
  PIN dn2[94]
    DIRECTION OUTPUT ;
    USE SIGNAL ;
    PORT
      LAYER M4 ;
        RECT  64.716 48.144 64.8 48.168 ;
    END
  END dn2[94]
  PIN dn2[95]
    DIRECTION OUTPUT ;
    USE SIGNAL ;
    PORT
      LAYER M4 ;
        RECT  64.716 48.24 64.8 48.264 ;
    END
  END dn2[95]
  PIN dn2[96]
    DIRECTION OUTPUT ;
    USE SIGNAL ;
    PORT
      LAYER M4 ;
        RECT  64.716 42.192 64.8 42.216 ;
    END
  END dn2[96]
  PIN dn2[97]
    DIRECTION OUTPUT ;
    USE SIGNAL ;
    PORT
      LAYER M4 ;
        RECT  64.716 42.288 64.8 42.312 ;
    END
  END dn2[97]
  PIN dn2[98]
    DIRECTION OUTPUT ;
    USE SIGNAL ;
    PORT
      LAYER M4 ;
        RECT  64.716 42.384 64.8 42.408 ;
    END
  END dn2[98]
  PIN dn2[99]
    DIRECTION OUTPUT ;
    USE SIGNAL ;
    PORT
      LAYER M4 ;
        RECT  64.716 42.48 64.8 42.504 ;
    END
  END dn2[99]
  PIN dn2[9]
    DIRECTION OUTPUT ;
    USE SIGNAL ;
    PORT
      LAYER M4 ;
        RECT  64.716 36.144 64.8 36.168 ;
    END
  END dn2[9]
  PIN dn3[0]
    DIRECTION OUTPUT ;
    USE SIGNAL ;
    PORT
      LAYER M5 ;
        RECT  22.992 0 23.016 0.084 ;
    END
  END dn3[0]
  PIN dn3[100]
    DIRECTION OUTPUT ;
    USE SIGNAL ;
    PORT
      LAYER M5 ;
        RECT  51.792 0 51.816 0.084 ;
    END
  END dn3[100]
  PIN dn3[101]
    DIRECTION OUTPUT ;
    USE SIGNAL ;
    PORT
      LAYER M5 ;
        RECT  51.888 0 51.912 0.084 ;
    END
  END dn3[101]
  PIN dn3[102]
    DIRECTION OUTPUT ;
    USE SIGNAL ;
    PORT
      LAYER M5 ;
        RECT  51.984 0 52.008 0.084 ;
    END
  END dn3[102]
  PIN dn3[103]
    DIRECTION OUTPUT ;
    USE SIGNAL ;
    PORT
      LAYER M5 ;
        RECT  52.08 0 52.104 0.084 ;
    END
  END dn3[103]
  PIN dn3[104]
    DIRECTION OUTPUT ;
    USE SIGNAL ;
    PORT
      LAYER M5 ;
        RECT  52.176 0 52.2 0.084 ;
    END
  END dn3[104]
  PIN dn3[105]
    DIRECTION OUTPUT ;
    USE SIGNAL ;
    PORT
      LAYER M5 ;
        RECT  52.272 0 52.296 0.084 ;
    END
  END dn3[105]
  PIN dn3[106]
    DIRECTION OUTPUT ;
    USE SIGNAL ;
    PORT
      LAYER M5 ;
        RECT  52.368 0 52.392 0.084 ;
    END
  END dn3[106]
  PIN dn3[107]
    DIRECTION OUTPUT ;
    USE SIGNAL ;
    PORT
      LAYER M5 ;
        RECT  52.464 0 52.488 0.084 ;
    END
  END dn3[107]
  PIN dn3[108]
    DIRECTION OUTPUT ;
    USE SIGNAL ;
    PORT
      LAYER M5 ;
        RECT  52.56 0 52.584 0.084 ;
    END
  END dn3[108]
  PIN dn3[109]
    DIRECTION OUTPUT ;
    USE SIGNAL ;
    PORT
      LAYER M5 ;
        RECT  52.656 0 52.68 0.084 ;
    END
  END dn3[109]
  PIN dn3[10]
    DIRECTION OUTPUT ;
    USE SIGNAL ;
    PORT
      LAYER M5 ;
        RECT  23.952 0 23.976 0.084 ;
    END
  END dn3[10]
  PIN dn3[110]
    DIRECTION OUTPUT ;
    USE SIGNAL ;
    PORT
      LAYER M5 ;
        RECT  52.752 0 52.776 0.084 ;
    END
  END dn3[110]
  PIN dn3[111]
    DIRECTION OUTPUT ;
    USE SIGNAL ;
    PORT
      LAYER M5 ;
        RECT  52.848 0 52.872 0.084 ;
    END
  END dn3[111]
  PIN dn3[112]
    DIRECTION OUTPUT ;
    USE SIGNAL ;
    PORT
      LAYER M5 ;
        RECT  52.944 0 52.968 0.084 ;
    END
  END dn3[112]
  PIN dn3[113]
    DIRECTION OUTPUT ;
    USE SIGNAL ;
    PORT
      LAYER M5 ;
        RECT  53.04 0 53.064 0.084 ;
    END
  END dn3[113]
  PIN dn3[114]
    DIRECTION OUTPUT ;
    USE SIGNAL ;
    PORT
      LAYER M5 ;
        RECT  53.136 0 53.16 0.084 ;
    END
  END dn3[114]
  PIN dn3[115]
    DIRECTION OUTPUT ;
    USE SIGNAL ;
    PORT
      LAYER M5 ;
        RECT  53.232 0 53.256 0.084 ;
    END
  END dn3[115]
  PIN dn3[116]
    DIRECTION OUTPUT ;
    USE SIGNAL ;
    PORT
      LAYER M5 ;
        RECT  53.328 0 53.352 0.084 ;
    END
  END dn3[116]
  PIN dn3[117]
    DIRECTION OUTPUT ;
    USE SIGNAL ;
    PORT
      LAYER M5 ;
        RECT  53.424 0 53.448 0.084 ;
    END
  END dn3[117]
  PIN dn3[118]
    DIRECTION OUTPUT ;
    USE SIGNAL ;
    PORT
      LAYER M5 ;
        RECT  53.52 0 53.544 0.084 ;
    END
  END dn3[118]
  PIN dn3[119]
    DIRECTION OUTPUT ;
    USE SIGNAL ;
    PORT
      LAYER M5 ;
        RECT  53.616 0 53.64 0.084 ;
    END
  END dn3[119]
  PIN dn3[11]
    DIRECTION OUTPUT ;
    USE SIGNAL ;
    PORT
      LAYER M5 ;
        RECT  24.048 0 24.072 0.084 ;
    END
  END dn3[11]
  PIN dn3[120]
    DIRECTION OUTPUT ;
    USE SIGNAL ;
    PORT
      LAYER M5 ;
        RECT  53.712 0 53.736 0.084 ;
    END
  END dn3[120]
  PIN dn3[121]
    DIRECTION OUTPUT ;
    USE SIGNAL ;
    PORT
      LAYER M5 ;
        RECT  53.808 0 53.832 0.084 ;
    END
  END dn3[121]
  PIN dn3[122]
    DIRECTION OUTPUT ;
    USE SIGNAL ;
    PORT
      LAYER M5 ;
        RECT  53.904 0 53.928 0.084 ;
    END
  END dn3[122]
  PIN dn3[123]
    DIRECTION OUTPUT ;
    USE SIGNAL ;
    PORT
      LAYER M5 ;
        RECT  54 0 54.024 0.084 ;
    END
  END dn3[123]
  PIN dn3[124]
    DIRECTION OUTPUT ;
    USE SIGNAL ;
    PORT
      LAYER M5 ;
        RECT  54.096 0 54.12 0.084 ;
    END
  END dn3[124]
  PIN dn3[125]
    DIRECTION OUTPUT ;
    USE SIGNAL ;
    PORT
      LAYER M5 ;
        RECT  54.192 0 54.216 0.084 ;
    END
  END dn3[125]
  PIN dn3[126]
    DIRECTION OUTPUT ;
    USE SIGNAL ;
    PORT
      LAYER M5 ;
        RECT  54.288 0 54.312 0.084 ;
    END
  END dn3[126]
  PIN dn3[127]
    DIRECTION OUTPUT ;
    USE SIGNAL ;
    PORT
      LAYER M5 ;
        RECT  54.384 0 54.408 0.084 ;
    END
  END dn3[127]
  PIN dn3[128]
    DIRECTION OUTPUT ;
    USE SIGNAL ;
    PORT
      LAYER M5 ;
        RECT  48.336 0 48.36 0.084 ;
    END
  END dn3[128]
  PIN dn3[129]
    DIRECTION OUTPUT ;
    USE SIGNAL ;
    PORT
      LAYER M5 ;
        RECT  48.432 0 48.456 0.084 ;
    END
  END dn3[129]
  PIN dn3[12]
    DIRECTION OUTPUT ;
    USE SIGNAL ;
    PORT
      LAYER M5 ;
        RECT  24.144 0 24.168 0.084 ;
    END
  END dn3[12]
  PIN dn3[130]
    DIRECTION OUTPUT ;
    USE SIGNAL ;
    PORT
      LAYER M5 ;
        RECT  48.528 0 48.552 0.084 ;
    END
  END dn3[130]
  PIN dn3[131]
    DIRECTION OUTPUT ;
    USE SIGNAL ;
    PORT
      LAYER M5 ;
        RECT  48.624 0 48.648 0.084 ;
    END
  END dn3[131]
  PIN dn3[132]
    DIRECTION OUTPUT ;
    USE SIGNAL ;
    PORT
      LAYER M5 ;
        RECT  48.72 0 48.744 0.084 ;
    END
  END dn3[132]
  PIN dn3[133]
    DIRECTION OUTPUT ;
    USE SIGNAL ;
    PORT
      LAYER M5 ;
        RECT  48.816 0 48.84 0.084 ;
    END
  END dn3[133]
  PIN dn3[134]
    DIRECTION OUTPUT ;
    USE SIGNAL ;
    PORT
      LAYER M5 ;
        RECT  48.912 0 48.936 0.084 ;
    END
  END dn3[134]
  PIN dn3[135]
    DIRECTION OUTPUT ;
    USE SIGNAL ;
    PORT
      LAYER M5 ;
        RECT  49.008 0 49.032 0.084 ;
    END
  END dn3[135]
  PIN dn3[136]
    DIRECTION OUTPUT ;
    USE SIGNAL ;
    PORT
      LAYER M5 ;
        RECT  49.104 0 49.128 0.084 ;
    END
  END dn3[136]
  PIN dn3[137]
    DIRECTION OUTPUT ;
    USE SIGNAL ;
    PORT
      LAYER M5 ;
        RECT  49.2 0 49.224 0.084 ;
    END
  END dn3[137]
  PIN dn3[138]
    DIRECTION OUTPUT ;
    USE SIGNAL ;
    PORT
      LAYER M5 ;
        RECT  49.296 0 49.32 0.084 ;
    END
  END dn3[138]
  PIN dn3[139]
    DIRECTION OUTPUT ;
    USE SIGNAL ;
    PORT
      LAYER M5 ;
        RECT  49.392 0 49.416 0.084 ;
    END
  END dn3[139]
  PIN dn3[13]
    DIRECTION OUTPUT ;
    USE SIGNAL ;
    PORT
      LAYER M5 ;
        RECT  24.24 0 24.264 0.084 ;
    END
  END dn3[13]
  PIN dn3[140]
    DIRECTION OUTPUT ;
    USE SIGNAL ;
    PORT
      LAYER M5 ;
        RECT  49.488 0 49.512 0.084 ;
    END
  END dn3[140]
  PIN dn3[141]
    DIRECTION OUTPUT ;
    USE SIGNAL ;
    PORT
      LAYER M5 ;
        RECT  49.584 0 49.608 0.084 ;
    END
  END dn3[141]
  PIN dn3[142]
    DIRECTION OUTPUT ;
    USE SIGNAL ;
    PORT
      LAYER M5 ;
        RECT  49.68 0 49.704 0.084 ;
    END
  END dn3[142]
  PIN dn3[143]
    DIRECTION OUTPUT ;
    USE SIGNAL ;
    PORT
      LAYER M5 ;
        RECT  49.776 0 49.8 0.084 ;
    END
  END dn3[143]
  PIN dn3[144]
    DIRECTION OUTPUT ;
    USE SIGNAL ;
    PORT
      LAYER M5 ;
        RECT  49.872 0 49.896 0.084 ;
    END
  END dn3[144]
  PIN dn3[145]
    DIRECTION OUTPUT ;
    USE SIGNAL ;
    PORT
      LAYER M5 ;
        RECT  49.968 0 49.992 0.084 ;
    END
  END dn3[145]
  PIN dn3[146]
    DIRECTION OUTPUT ;
    USE SIGNAL ;
    PORT
      LAYER M5 ;
        RECT  50.064 0 50.088 0.084 ;
    END
  END dn3[146]
  PIN dn3[147]
    DIRECTION OUTPUT ;
    USE SIGNAL ;
    PORT
      LAYER M5 ;
        RECT  50.16 0 50.184 0.084 ;
    END
  END dn3[147]
  PIN dn3[148]
    DIRECTION OUTPUT ;
    USE SIGNAL ;
    PORT
      LAYER M5 ;
        RECT  50.256 0 50.28 0.084 ;
    END
  END dn3[148]
  PIN dn3[149]
    DIRECTION OUTPUT ;
    USE SIGNAL ;
    PORT
      LAYER M5 ;
        RECT  50.352 0 50.376 0.084 ;
    END
  END dn3[149]
  PIN dn3[14]
    DIRECTION OUTPUT ;
    USE SIGNAL ;
    PORT
      LAYER M5 ;
        RECT  24.336 0 24.36 0.084 ;
    END
  END dn3[14]
  PIN dn3[150]
    DIRECTION OUTPUT ;
    USE SIGNAL ;
    PORT
      LAYER M5 ;
        RECT  50.448 0 50.472 0.084 ;
    END
  END dn3[150]
  PIN dn3[151]
    DIRECTION OUTPUT ;
    USE SIGNAL ;
    PORT
      LAYER M5 ;
        RECT  50.544 0 50.568 0.084 ;
    END
  END dn3[151]
  PIN dn3[152]
    DIRECTION OUTPUT ;
    USE SIGNAL ;
    PORT
      LAYER M5 ;
        RECT  50.64 0 50.664 0.084 ;
    END
  END dn3[152]
  PIN dn3[153]
    DIRECTION OUTPUT ;
    USE SIGNAL ;
    PORT
      LAYER M5 ;
        RECT  50.736 0 50.76 0.084 ;
    END
  END dn3[153]
  PIN dn3[154]
    DIRECTION OUTPUT ;
    USE SIGNAL ;
    PORT
      LAYER M5 ;
        RECT  50.832 0 50.856 0.084 ;
    END
  END dn3[154]
  PIN dn3[155]
    DIRECTION OUTPUT ;
    USE SIGNAL ;
    PORT
      LAYER M5 ;
        RECT  50.928 0 50.952 0.084 ;
    END
  END dn3[155]
  PIN dn3[156]
    DIRECTION OUTPUT ;
    USE SIGNAL ;
    PORT
      LAYER M5 ;
        RECT  51.024 0 51.048 0.084 ;
    END
  END dn3[156]
  PIN dn3[157]
    DIRECTION OUTPUT ;
    USE SIGNAL ;
    PORT
      LAYER M5 ;
        RECT  51.12 0 51.144 0.084 ;
    END
  END dn3[157]
  PIN dn3[158]
    DIRECTION OUTPUT ;
    USE SIGNAL ;
    PORT
      LAYER M5 ;
        RECT  51.216 0 51.24 0.084 ;
    END
  END dn3[158]
  PIN dn3[159]
    DIRECTION OUTPUT ;
    USE SIGNAL ;
    PORT
      LAYER M5 ;
        RECT  51.312 0 51.336 0.084 ;
    END
  END dn3[159]
  PIN dn3[15]
    DIRECTION OUTPUT ;
    USE SIGNAL ;
    PORT
      LAYER M5 ;
        RECT  24.432 0 24.456 0.084 ;
    END
  END dn3[15]
  PIN dn3[160]
    DIRECTION OUTPUT ;
    USE SIGNAL ;
    PORT
      LAYER M5 ;
        RECT  35.28 0 35.304 0.084 ;
    END
  END dn3[160]
  PIN dn3[161]
    DIRECTION OUTPUT ;
    USE SIGNAL ;
    PORT
      LAYER M5 ;
        RECT  35.376 0 35.4 0.084 ;
    END
  END dn3[161]
  PIN dn3[162]
    DIRECTION OUTPUT ;
    USE SIGNAL ;
    PORT
      LAYER M5 ;
        RECT  35.472 0 35.496 0.084 ;
    END
  END dn3[162]
  PIN dn3[163]
    DIRECTION OUTPUT ;
    USE SIGNAL ;
    PORT
      LAYER M5 ;
        RECT  35.568 0 35.592 0.084 ;
    END
  END dn3[163]
  PIN dn3[164]
    DIRECTION OUTPUT ;
    USE SIGNAL ;
    PORT
      LAYER M5 ;
        RECT  35.664 0 35.688 0.084 ;
    END
  END dn3[164]
  PIN dn3[165]
    DIRECTION OUTPUT ;
    USE SIGNAL ;
    PORT
      LAYER M5 ;
        RECT  35.76 0 35.784 0.084 ;
    END
  END dn3[165]
  PIN dn3[166]
    DIRECTION OUTPUT ;
    USE SIGNAL ;
    PORT
      LAYER M5 ;
        RECT  35.856 0 35.88 0.084 ;
    END
  END dn3[166]
  PIN dn3[167]
    DIRECTION OUTPUT ;
    USE SIGNAL ;
    PORT
      LAYER M5 ;
        RECT  35.952 0 35.976 0.084 ;
    END
  END dn3[167]
  PIN dn3[168]
    DIRECTION OUTPUT ;
    USE SIGNAL ;
    PORT
      LAYER M5 ;
        RECT  36.048 0 36.072 0.084 ;
    END
  END dn3[168]
  PIN dn3[169]
    DIRECTION OUTPUT ;
    USE SIGNAL ;
    PORT
      LAYER M5 ;
        RECT  36.144 0 36.168 0.084 ;
    END
  END dn3[169]
  PIN dn3[16]
    DIRECTION OUTPUT ;
    USE SIGNAL ;
    PORT
      LAYER M5 ;
        RECT  24.528 0 24.552 0.084 ;
    END
  END dn3[16]
  PIN dn3[170]
    DIRECTION OUTPUT ;
    USE SIGNAL ;
    PORT
      LAYER M5 ;
        RECT  36.24 0 36.264 0.084 ;
    END
  END dn3[170]
  PIN dn3[171]
    DIRECTION OUTPUT ;
    USE SIGNAL ;
    PORT
      LAYER M5 ;
        RECT  36.336 0 36.36 0.084 ;
    END
  END dn3[171]
  PIN dn3[172]
    DIRECTION OUTPUT ;
    USE SIGNAL ;
    PORT
      LAYER M5 ;
        RECT  36.432 0 36.456 0.084 ;
    END
  END dn3[172]
  PIN dn3[173]
    DIRECTION OUTPUT ;
    USE SIGNAL ;
    PORT
      LAYER M5 ;
        RECT  36.528 0 36.552 0.084 ;
    END
  END dn3[173]
  PIN dn3[174]
    DIRECTION OUTPUT ;
    USE SIGNAL ;
    PORT
      LAYER M5 ;
        RECT  36.624 0 36.648 0.084 ;
    END
  END dn3[174]
  PIN dn3[175]
    DIRECTION OUTPUT ;
    USE SIGNAL ;
    PORT
      LAYER M5 ;
        RECT  36.72 0 36.744 0.084 ;
    END
  END dn3[175]
  PIN dn3[176]
    DIRECTION OUTPUT ;
    USE SIGNAL ;
    PORT
      LAYER M5 ;
        RECT  36.816 0 36.84 0.084 ;
    END
  END dn3[176]
  PIN dn3[177]
    DIRECTION OUTPUT ;
    USE SIGNAL ;
    PORT
      LAYER M5 ;
        RECT  36.912 0 36.936 0.084 ;
    END
  END dn3[177]
  PIN dn3[178]
    DIRECTION OUTPUT ;
    USE SIGNAL ;
    PORT
      LAYER M5 ;
        RECT  37.008 0 37.032 0.084 ;
    END
  END dn3[178]
  PIN dn3[179]
    DIRECTION OUTPUT ;
    USE SIGNAL ;
    PORT
      LAYER M5 ;
        RECT  37.104 0 37.128 0.084 ;
    END
  END dn3[179]
  PIN dn3[17]
    DIRECTION OUTPUT ;
    USE SIGNAL ;
    PORT
      LAYER M5 ;
        RECT  24.624 0 24.648 0.084 ;
    END
  END dn3[17]
  PIN dn3[180]
    DIRECTION OUTPUT ;
    USE SIGNAL ;
    PORT
      LAYER M5 ;
        RECT  37.2 0 37.224 0.084 ;
    END
  END dn3[180]
  PIN dn3[181]
    DIRECTION OUTPUT ;
    USE SIGNAL ;
    PORT
      LAYER M5 ;
        RECT  37.296 0 37.32 0.084 ;
    END
  END dn3[181]
  PIN dn3[182]
    DIRECTION OUTPUT ;
    USE SIGNAL ;
    PORT
      LAYER M5 ;
        RECT  37.392 0 37.416 0.084 ;
    END
  END dn3[182]
  PIN dn3[183]
    DIRECTION OUTPUT ;
    USE SIGNAL ;
    PORT
      LAYER M5 ;
        RECT  37.488 0 37.512 0.084 ;
    END
  END dn3[183]
  PIN dn3[184]
    DIRECTION OUTPUT ;
    USE SIGNAL ;
    PORT
      LAYER M5 ;
        RECT  37.584 0 37.608 0.084 ;
    END
  END dn3[184]
  PIN dn3[185]
    DIRECTION OUTPUT ;
    USE SIGNAL ;
    PORT
      LAYER M5 ;
        RECT  37.68 0 37.704 0.084 ;
    END
  END dn3[185]
  PIN dn3[186]
    DIRECTION OUTPUT ;
    USE SIGNAL ;
    PORT
      LAYER M5 ;
        RECT  37.776 0 37.8 0.084 ;
    END
  END dn3[186]
  PIN dn3[187]
    DIRECTION OUTPUT ;
    USE SIGNAL ;
    PORT
      LAYER M5 ;
        RECT  37.872 0 37.896 0.084 ;
    END
  END dn3[187]
  PIN dn3[188]
    DIRECTION OUTPUT ;
    USE SIGNAL ;
    PORT
      LAYER M5 ;
        RECT  37.968 0 37.992 0.084 ;
    END
  END dn3[188]
  PIN dn3[189]
    DIRECTION OUTPUT ;
    USE SIGNAL ;
    PORT
      LAYER M5 ;
        RECT  38.064 0 38.088 0.084 ;
    END
  END dn3[189]
  PIN dn3[18]
    DIRECTION OUTPUT ;
    USE SIGNAL ;
    PORT
      LAYER M5 ;
        RECT  24.72 0 24.744 0.084 ;
    END
  END dn3[18]
  PIN dn3[190]
    DIRECTION OUTPUT ;
    USE SIGNAL ;
    PORT
      LAYER M5 ;
        RECT  38.16 0 38.184 0.084 ;
    END
  END dn3[190]
  PIN dn3[191]
    DIRECTION OUTPUT ;
    USE SIGNAL ;
    PORT
      LAYER M5 ;
        RECT  38.256 0 38.28 0.084 ;
    END
  END dn3[191]
  PIN dn3[192]
    DIRECTION OUTPUT ;
    USE SIGNAL ;
    PORT
      LAYER M5 ;
        RECT  19.92 0 19.944 0.084 ;
    END
  END dn3[192]
  PIN dn3[193]
    DIRECTION OUTPUT ;
    USE SIGNAL ;
    PORT
      LAYER M5 ;
        RECT  20.016 0 20.04 0.084 ;
    END
  END dn3[193]
  PIN dn3[194]
    DIRECTION OUTPUT ;
    USE SIGNAL ;
    PORT
      LAYER M5 ;
        RECT  20.112 0 20.136 0.084 ;
    END
  END dn3[194]
  PIN dn3[195]
    DIRECTION OUTPUT ;
    USE SIGNAL ;
    PORT
      LAYER M5 ;
        RECT  20.208 0 20.232 0.084 ;
    END
  END dn3[195]
  PIN dn3[196]
    DIRECTION OUTPUT ;
    USE SIGNAL ;
    PORT
      LAYER M5 ;
        RECT  20.304 0 20.328 0.084 ;
    END
  END dn3[196]
  PIN dn3[197]
    DIRECTION OUTPUT ;
    USE SIGNAL ;
    PORT
      LAYER M5 ;
        RECT  20.4 0 20.424 0.084 ;
    END
  END dn3[197]
  PIN dn3[198]
    DIRECTION OUTPUT ;
    USE SIGNAL ;
    PORT
      LAYER M5 ;
        RECT  20.496 0 20.52 0.084 ;
    END
  END dn3[198]
  PIN dn3[199]
    DIRECTION OUTPUT ;
    USE SIGNAL ;
    PORT
      LAYER M5 ;
        RECT  20.592 0 20.616 0.084 ;
    END
  END dn3[199]
  PIN dn3[19]
    DIRECTION OUTPUT ;
    USE SIGNAL ;
    PORT
      LAYER M5 ;
        RECT  24.816 0 24.84 0.084 ;
    END
  END dn3[19]
  PIN dn3[1]
    DIRECTION OUTPUT ;
    USE SIGNAL ;
    PORT
      LAYER M5 ;
        RECT  23.088 0 23.112 0.084 ;
    END
  END dn3[1]
  PIN dn3[200]
    DIRECTION OUTPUT ;
    USE SIGNAL ;
    PORT
      LAYER M5 ;
        RECT  20.688 0 20.712 0.084 ;
    END
  END dn3[200]
  PIN dn3[201]
    DIRECTION OUTPUT ;
    USE SIGNAL ;
    PORT
      LAYER M5 ;
        RECT  20.784 0 20.808 0.084 ;
    END
  END dn3[201]
  PIN dn3[202]
    DIRECTION OUTPUT ;
    USE SIGNAL ;
    PORT
      LAYER M5 ;
        RECT  20.88 0 20.904 0.084 ;
    END
  END dn3[202]
  PIN dn3[203]
    DIRECTION OUTPUT ;
    USE SIGNAL ;
    PORT
      LAYER M5 ;
        RECT  20.976 0 21 0.084 ;
    END
  END dn3[203]
  PIN dn3[204]
    DIRECTION OUTPUT ;
    USE SIGNAL ;
    PORT
      LAYER M5 ;
        RECT  21.072 0 21.096 0.084 ;
    END
  END dn3[204]
  PIN dn3[205]
    DIRECTION OUTPUT ;
    USE SIGNAL ;
    PORT
      LAYER M5 ;
        RECT  21.168 0 21.192 0.084 ;
    END
  END dn3[205]
  PIN dn3[206]
    DIRECTION OUTPUT ;
    USE SIGNAL ;
    PORT
      LAYER M5 ;
        RECT  21.264 0 21.288 0.084 ;
    END
  END dn3[206]
  PIN dn3[207]
    DIRECTION OUTPUT ;
    USE SIGNAL ;
    PORT
      LAYER M5 ;
        RECT  21.36 0 21.384 0.084 ;
    END
  END dn3[207]
  PIN dn3[208]
    DIRECTION OUTPUT ;
    USE SIGNAL ;
    PORT
      LAYER M5 ;
        RECT  21.456 0 21.48 0.084 ;
    END
  END dn3[208]
  PIN dn3[209]
    DIRECTION OUTPUT ;
    USE SIGNAL ;
    PORT
      LAYER M5 ;
        RECT  21.552 0 21.576 0.084 ;
    END
  END dn3[209]
  PIN dn3[20]
    DIRECTION OUTPUT ;
    USE SIGNAL ;
    PORT
      LAYER M5 ;
        RECT  24.912 0 24.936 0.084 ;
    END
  END dn3[20]
  PIN dn3[210]
    DIRECTION OUTPUT ;
    USE SIGNAL ;
    PORT
      LAYER M5 ;
        RECT  21.648 0 21.672 0.084 ;
    END
  END dn3[210]
  PIN dn3[211]
    DIRECTION OUTPUT ;
    USE SIGNAL ;
    PORT
      LAYER M5 ;
        RECT  21.744 0 21.768 0.084 ;
    END
  END dn3[211]
  PIN dn3[212]
    DIRECTION OUTPUT ;
    USE SIGNAL ;
    PORT
      LAYER M5 ;
        RECT  21.84 0 21.864 0.084 ;
    END
  END dn3[212]
  PIN dn3[213]
    DIRECTION OUTPUT ;
    USE SIGNAL ;
    PORT
      LAYER M5 ;
        RECT  21.936 0 21.96 0.084 ;
    END
  END dn3[213]
  PIN dn3[214]
    DIRECTION OUTPUT ;
    USE SIGNAL ;
    PORT
      LAYER M5 ;
        RECT  22.032 0 22.056 0.084 ;
    END
  END dn3[214]
  PIN dn3[215]
    DIRECTION OUTPUT ;
    USE SIGNAL ;
    PORT
      LAYER M5 ;
        RECT  22.128 0 22.152 0.084 ;
    END
  END dn3[215]
  PIN dn3[216]
    DIRECTION OUTPUT ;
    USE SIGNAL ;
    PORT
      LAYER M5 ;
        RECT  22.224 0 22.248 0.084 ;
    END
  END dn3[216]
  PIN dn3[217]
    DIRECTION OUTPUT ;
    USE SIGNAL ;
    PORT
      LAYER M5 ;
        RECT  22.32 0 22.344 0.084 ;
    END
  END dn3[217]
  PIN dn3[218]
    DIRECTION OUTPUT ;
    USE SIGNAL ;
    PORT
      LAYER M5 ;
        RECT  22.416 0 22.44 0.084 ;
    END
  END dn3[218]
  PIN dn3[219]
    DIRECTION OUTPUT ;
    USE SIGNAL ;
    PORT
      LAYER M5 ;
        RECT  22.512 0 22.536 0.084 ;
    END
  END dn3[219]
  PIN dn3[21]
    DIRECTION OUTPUT ;
    USE SIGNAL ;
    PORT
      LAYER M5 ;
        RECT  25.008 0 25.032 0.084 ;
    END
  END dn3[21]
  PIN dn3[220]
    DIRECTION OUTPUT ;
    USE SIGNAL ;
    PORT
      LAYER M5 ;
        RECT  22.608 0 22.632 0.084 ;
    END
  END dn3[220]
  PIN dn3[221]
    DIRECTION OUTPUT ;
    USE SIGNAL ;
    PORT
      LAYER M5 ;
        RECT  22.704 0 22.728 0.084 ;
    END
  END dn3[221]
  PIN dn3[222]
    DIRECTION OUTPUT ;
    USE SIGNAL ;
    PORT
      LAYER M5 ;
        RECT  22.8 0 22.824 0.084 ;
    END
  END dn3[222]
  PIN dn3[223]
    DIRECTION OUTPUT ;
    USE SIGNAL ;
    PORT
      LAYER M5 ;
        RECT  22.896 0 22.92 0.084 ;
    END
  END dn3[223]
  PIN dn3[224]
    DIRECTION OUTPUT ;
    USE SIGNAL ;
    PORT
      LAYER M5 ;
        RECT  3.792 0 3.816 0.084 ;
    END
  END dn3[224]
  PIN dn3[225]
    DIRECTION OUTPUT ;
    USE SIGNAL ;
    PORT
      LAYER M5 ;
        RECT  3.888 0 3.912 0.084 ;
    END
  END dn3[225]
  PIN dn3[226]
    DIRECTION OUTPUT ;
    USE SIGNAL ;
    PORT
      LAYER M5 ;
        RECT  3.984 0 4.008 0.084 ;
    END
  END dn3[226]
  PIN dn3[227]
    DIRECTION OUTPUT ;
    USE SIGNAL ;
    PORT
      LAYER M5 ;
        RECT  4.08 0 4.104 0.084 ;
    END
  END dn3[227]
  PIN dn3[22]
    DIRECTION OUTPUT ;
    USE SIGNAL ;
    PORT
      LAYER M5 ;
        RECT  25.104 0 25.128 0.084 ;
    END
  END dn3[22]
  PIN dn3[23]
    DIRECTION OUTPUT ;
    USE SIGNAL ;
    PORT
      LAYER M5 ;
        RECT  25.2 0 25.224 0.084 ;
    END
  END dn3[23]
  PIN dn3[24]
    DIRECTION OUTPUT ;
    USE SIGNAL ;
    PORT
      LAYER M5 ;
        RECT  25.296 0 25.32 0.084 ;
    END
  END dn3[24]
  PIN dn3[25]
    DIRECTION OUTPUT ;
    USE SIGNAL ;
    PORT
      LAYER M5 ;
        RECT  25.392 0 25.416 0.084 ;
    END
  END dn3[25]
  PIN dn3[26]
    DIRECTION OUTPUT ;
    USE SIGNAL ;
    PORT
      LAYER M5 ;
        RECT  25.488 0 25.512 0.084 ;
    END
  END dn3[26]
  PIN dn3[27]
    DIRECTION OUTPUT ;
    USE SIGNAL ;
    PORT
      LAYER M5 ;
        RECT  25.584 0 25.608 0.084 ;
    END
  END dn3[27]
  PIN dn3[28]
    DIRECTION OUTPUT ;
    USE SIGNAL ;
    PORT
      LAYER M5 ;
        RECT  25.68 0 25.704 0.084 ;
    END
  END dn3[28]
  PIN dn3[29]
    DIRECTION OUTPUT ;
    USE SIGNAL ;
    PORT
      LAYER M5 ;
        RECT  25.776 0 25.8 0.084 ;
    END
  END dn3[29]
  PIN dn3[2]
    DIRECTION OUTPUT ;
    USE SIGNAL ;
    PORT
      LAYER M5 ;
        RECT  23.184 0 23.208 0.084 ;
    END
  END dn3[2]
  PIN dn3[30]
    DIRECTION OUTPUT ;
    USE SIGNAL ;
    PORT
      LAYER M5 ;
        RECT  25.872 0 25.896 0.084 ;
    END
  END dn3[30]
  PIN dn3[31]
    DIRECTION OUTPUT ;
    USE SIGNAL ;
    PORT
      LAYER M5 ;
        RECT  25.968 0 25.992 0.084 ;
    END
  END dn3[31]
  PIN dn3[32]
    DIRECTION OUTPUT ;
    USE SIGNAL ;
    PORT
      LAYER M5 ;
        RECT  26.064 0 26.088 0.084 ;
    END
  END dn3[32]
  PIN dn3[33]
    DIRECTION OUTPUT ;
    USE SIGNAL ;
    PORT
      LAYER M5 ;
        RECT  26.16 0 26.184 0.084 ;
    END
  END dn3[33]
  PIN dn3[34]
    DIRECTION OUTPUT ;
    USE SIGNAL ;
    PORT
      LAYER M5 ;
        RECT  26.256 0 26.28 0.084 ;
    END
  END dn3[34]
  PIN dn3[35]
    DIRECTION OUTPUT ;
    USE SIGNAL ;
    PORT
      LAYER M5 ;
        RECT  26.352 0 26.376 0.084 ;
    END
  END dn3[35]
  PIN dn3[36]
    DIRECTION OUTPUT ;
    USE SIGNAL ;
    PORT
      LAYER M5 ;
        RECT  26.448 0 26.472 0.084 ;
    END
  END dn3[36]
  PIN dn3[37]
    DIRECTION OUTPUT ;
    USE SIGNAL ;
    PORT
      LAYER M5 ;
        RECT  26.544 0 26.568 0.084 ;
    END
  END dn3[37]
  PIN dn3[38]
    DIRECTION OUTPUT ;
    USE SIGNAL ;
    PORT
      LAYER M5 ;
        RECT  26.64 0 26.664 0.084 ;
    END
  END dn3[38]
  PIN dn3[39]
    DIRECTION OUTPUT ;
    USE SIGNAL ;
    PORT
      LAYER M5 ;
        RECT  26.736 0 26.76 0.084 ;
    END
  END dn3[39]
  PIN dn3[3]
    DIRECTION OUTPUT ;
    USE SIGNAL ;
    PORT
      LAYER M5 ;
        RECT  23.28 0 23.304 0.084 ;
    END
  END dn3[3]
  PIN dn3[40]
    DIRECTION OUTPUT ;
    USE SIGNAL ;
    PORT
      LAYER M5 ;
        RECT  26.832 0 26.856 0.084 ;
    END
  END dn3[40]
  PIN dn3[41]
    DIRECTION OUTPUT ;
    USE SIGNAL ;
    PORT
      LAYER M5 ;
        RECT  26.928 0 26.952 0.084 ;
    END
  END dn3[41]
  PIN dn3[42]
    DIRECTION OUTPUT ;
    USE SIGNAL ;
    PORT
      LAYER M5 ;
        RECT  27.024 0 27.048 0.084 ;
    END
  END dn3[42]
  PIN dn3[43]
    DIRECTION OUTPUT ;
    USE SIGNAL ;
    PORT
      LAYER M5 ;
        RECT  27.12 0 27.144 0.084 ;
    END
  END dn3[43]
  PIN dn3[44]
    DIRECTION OUTPUT ;
    USE SIGNAL ;
    PORT
      LAYER M5 ;
        RECT  27.216 0 27.24 0.084 ;
    END
  END dn3[44]
  PIN dn3[45]
    DIRECTION OUTPUT ;
    USE SIGNAL ;
    PORT
      LAYER M5 ;
        RECT  27.312 0 27.336 0.084 ;
    END
  END dn3[45]
  PIN dn3[46]
    DIRECTION OUTPUT ;
    USE SIGNAL ;
    PORT
      LAYER M5 ;
        RECT  27.408 0 27.432 0.084 ;
    END
  END dn3[46]
  PIN dn3[47]
    DIRECTION OUTPUT ;
    USE SIGNAL ;
    PORT
      LAYER M5 ;
        RECT  27.504 0 27.528 0.084 ;
    END
  END dn3[47]
  PIN dn3[48]
    DIRECTION OUTPUT ;
    USE SIGNAL ;
    PORT
      LAYER M5 ;
        RECT  27.6 0 27.624 0.084 ;
    END
  END dn3[48]
  PIN dn3[49]
    DIRECTION OUTPUT ;
    USE SIGNAL ;
    PORT
      LAYER M5 ;
        RECT  27.696 0 27.72 0.084 ;
    END
  END dn3[49]
  PIN dn3[4]
    DIRECTION OUTPUT ;
    USE SIGNAL ;
    PORT
      LAYER M5 ;
        RECT  23.376 0 23.4 0.084 ;
    END
  END dn3[4]
  PIN dn3[50]
    DIRECTION OUTPUT ;
    USE SIGNAL ;
    PORT
      LAYER M5 ;
        RECT  27.792 0 27.816 0.084 ;
    END
  END dn3[50]
  PIN dn3[51]
    DIRECTION OUTPUT ;
    USE SIGNAL ;
    PORT
      LAYER M5 ;
        RECT  27.888 0 27.912 0.084 ;
    END
  END dn3[51]
  PIN dn3[52]
    DIRECTION OUTPUT ;
    USE SIGNAL ;
    PORT
      LAYER M5 ;
        RECT  27.984 0 28.008 0.084 ;
    END
  END dn3[52]
  PIN dn3[53]
    DIRECTION OUTPUT ;
    USE SIGNAL ;
    PORT
      LAYER M5 ;
        RECT  28.08 0 28.104 0.084 ;
    END
  END dn3[53]
  PIN dn3[54]
    DIRECTION OUTPUT ;
    USE SIGNAL ;
    PORT
      LAYER M5 ;
        RECT  28.176 0 28.2 0.084 ;
    END
  END dn3[54]
  PIN dn3[55]
    DIRECTION OUTPUT ;
    USE SIGNAL ;
    PORT
      LAYER M5 ;
        RECT  28.272 0 28.296 0.084 ;
    END
  END dn3[55]
  PIN dn3[56]
    DIRECTION OUTPUT ;
    USE SIGNAL ;
    PORT
      LAYER M5 ;
        RECT  28.368 0 28.392 0.084 ;
    END
  END dn3[56]
  PIN dn3[57]
    DIRECTION OUTPUT ;
    USE SIGNAL ;
    PORT
      LAYER M5 ;
        RECT  28.464 0 28.488 0.084 ;
    END
  END dn3[57]
  PIN dn3[58]
    DIRECTION OUTPUT ;
    USE SIGNAL ;
    PORT
      LAYER M5 ;
        RECT  28.56 0 28.584 0.084 ;
    END
  END dn3[58]
  PIN dn3[59]
    DIRECTION OUTPUT ;
    USE SIGNAL ;
    PORT
      LAYER M5 ;
        RECT  28.656 0 28.68 0.084 ;
    END
  END dn3[59]
  PIN dn3[5]
    DIRECTION OUTPUT ;
    USE SIGNAL ;
    PORT
      LAYER M5 ;
        RECT  23.472 0 23.496 0.084 ;
    END
  END dn3[5]
  PIN dn3[60]
    DIRECTION OUTPUT ;
    USE SIGNAL ;
    PORT
      LAYER M5 ;
        RECT  28.752 0 28.776 0.084 ;
    END
  END dn3[60]
  PIN dn3[61]
    DIRECTION OUTPUT ;
    USE SIGNAL ;
    PORT
      LAYER M5 ;
        RECT  28.848 0 28.872 0.084 ;
    END
  END dn3[61]
  PIN dn3[62]
    DIRECTION OUTPUT ;
    USE SIGNAL ;
    PORT
      LAYER M5 ;
        RECT  28.944 0 28.968 0.084 ;
    END
  END dn3[62]
  PIN dn3[63]
    DIRECTION OUTPUT ;
    USE SIGNAL ;
    PORT
      LAYER M5 ;
        RECT  29.04 0 29.064 0.084 ;
    END
  END dn3[63]
  PIN dn3[64]
    DIRECTION OUTPUT ;
    USE SIGNAL ;
    PORT
      LAYER M5 ;
        RECT  39.12 0 39.144 0.084 ;
    END
  END dn3[64]
  PIN dn3[65]
    DIRECTION OUTPUT ;
    USE SIGNAL ;
    PORT
      LAYER M5 ;
        RECT  39.216 0 39.24 0.084 ;
    END
  END dn3[65]
  PIN dn3[66]
    DIRECTION OUTPUT ;
    USE SIGNAL ;
    PORT
      LAYER M5 ;
        RECT  39.312 0 39.336 0.084 ;
    END
  END dn3[66]
  PIN dn3[67]
    DIRECTION OUTPUT ;
    USE SIGNAL ;
    PORT
      LAYER M5 ;
        RECT  39.408 0 39.432 0.084 ;
    END
  END dn3[67]
  PIN dn3[68]
    DIRECTION OUTPUT ;
    USE SIGNAL ;
    PORT
      LAYER M5 ;
        RECT  39.504 0 39.528 0.084 ;
    END
  END dn3[68]
  PIN dn3[69]
    DIRECTION OUTPUT ;
    USE SIGNAL ;
    PORT
      LAYER M5 ;
        RECT  39.6 0 39.624 0.084 ;
    END
  END dn3[69]
  PIN dn3[6]
    DIRECTION OUTPUT ;
    USE SIGNAL ;
    PORT
      LAYER M5 ;
        RECT  23.568 0 23.592 0.084 ;
    END
  END dn3[6]
  PIN dn3[70]
    DIRECTION OUTPUT ;
    USE SIGNAL ;
    PORT
      LAYER M5 ;
        RECT  39.696 0 39.72 0.084 ;
    END
  END dn3[70]
  PIN dn3[71]
    DIRECTION OUTPUT ;
    USE SIGNAL ;
    PORT
      LAYER M5 ;
        RECT  39.792 0 39.816 0.084 ;
    END
  END dn3[71]
  PIN dn3[72]
    DIRECTION OUTPUT ;
    USE SIGNAL ;
    PORT
      LAYER M5 ;
        RECT  39.888 0 39.912 0.084 ;
    END
  END dn3[72]
  PIN dn3[73]
    DIRECTION OUTPUT ;
    USE SIGNAL ;
    PORT
      LAYER M5 ;
        RECT  39.984 0 40.008 0.084 ;
    END
  END dn3[73]
  PIN dn3[74]
    DIRECTION OUTPUT ;
    USE SIGNAL ;
    PORT
      LAYER M5 ;
        RECT  40.08 0 40.104 0.084 ;
    END
  END dn3[74]
  PIN dn3[75]
    DIRECTION OUTPUT ;
    USE SIGNAL ;
    PORT
      LAYER M5 ;
        RECT  40.176 0 40.2 0.084 ;
    END
  END dn3[75]
  PIN dn3[76]
    DIRECTION OUTPUT ;
    USE SIGNAL ;
    PORT
      LAYER M5 ;
        RECT  40.272 0 40.296 0.084 ;
    END
  END dn3[76]
  PIN dn3[77]
    DIRECTION OUTPUT ;
    USE SIGNAL ;
    PORT
      LAYER M5 ;
        RECT  40.368 0 40.392 0.084 ;
    END
  END dn3[77]
  PIN dn3[78]
    DIRECTION OUTPUT ;
    USE SIGNAL ;
    PORT
      LAYER M5 ;
        RECT  40.464 0 40.488 0.084 ;
    END
  END dn3[78]
  PIN dn3[79]
    DIRECTION OUTPUT ;
    USE SIGNAL ;
    PORT
      LAYER M5 ;
        RECT  40.56 0 40.584 0.084 ;
    END
  END dn3[79]
  PIN dn3[7]
    DIRECTION OUTPUT ;
    USE SIGNAL ;
    PORT
      LAYER M5 ;
        RECT  23.664 0 23.688 0.084 ;
    END
  END dn3[7]
  PIN dn3[80]
    DIRECTION OUTPUT ;
    USE SIGNAL ;
    PORT
      LAYER M5 ;
        RECT  40.656 0 40.68 0.084 ;
    END
  END dn3[80]
  PIN dn3[81]
    DIRECTION OUTPUT ;
    USE SIGNAL ;
    PORT
      LAYER M5 ;
        RECT  40.752 0 40.776 0.084 ;
    END
  END dn3[81]
  PIN dn3[82]
    DIRECTION OUTPUT ;
    USE SIGNAL ;
    PORT
      LAYER M5 ;
        RECT  40.848 0 40.872 0.084 ;
    END
  END dn3[82]
  PIN dn3[83]
    DIRECTION OUTPUT ;
    USE SIGNAL ;
    PORT
      LAYER M5 ;
        RECT  40.944 0 40.968 0.084 ;
    END
  END dn3[83]
  PIN dn3[84]
    DIRECTION OUTPUT ;
    USE SIGNAL ;
    PORT
      LAYER M5 ;
        RECT  41.04 0 41.064 0.084 ;
    END
  END dn3[84]
  PIN dn3[85]
    DIRECTION OUTPUT ;
    USE SIGNAL ;
    PORT
      LAYER M5 ;
        RECT  41.136 0 41.16 0.084 ;
    END
  END dn3[85]
  PIN dn3[86]
    DIRECTION OUTPUT ;
    USE SIGNAL ;
    PORT
      LAYER M5 ;
        RECT  41.232 0 41.256 0.084 ;
    END
  END dn3[86]
  PIN dn3[87]
    DIRECTION OUTPUT ;
    USE SIGNAL ;
    PORT
      LAYER M5 ;
        RECT  41.328 0 41.352 0.084 ;
    END
  END dn3[87]
  PIN dn3[88]
    DIRECTION OUTPUT ;
    USE SIGNAL ;
    PORT
      LAYER M5 ;
        RECT  41.424 0 41.448 0.084 ;
    END
  END dn3[88]
  PIN dn3[89]
    DIRECTION OUTPUT ;
    USE SIGNAL ;
    PORT
      LAYER M5 ;
        RECT  41.52 0 41.544 0.084 ;
    END
  END dn3[89]
  PIN dn3[8]
    DIRECTION OUTPUT ;
    USE SIGNAL ;
    PORT
      LAYER M5 ;
        RECT  23.76 0 23.784 0.084 ;
    END
  END dn3[8]
  PIN dn3[90]
    DIRECTION OUTPUT ;
    USE SIGNAL ;
    PORT
      LAYER M5 ;
        RECT  41.616 0 41.64 0.084 ;
    END
  END dn3[90]
  PIN dn3[91]
    DIRECTION OUTPUT ;
    USE SIGNAL ;
    PORT
      LAYER M5 ;
        RECT  41.712 0 41.736 0.084 ;
    END
  END dn3[91]
  PIN dn3[92]
    DIRECTION OUTPUT ;
    USE SIGNAL ;
    PORT
      LAYER M5 ;
        RECT  41.808 0 41.832 0.084 ;
    END
  END dn3[92]
  PIN dn3[93]
    DIRECTION OUTPUT ;
    USE SIGNAL ;
    PORT
      LAYER M5 ;
        RECT  41.904 0 41.928 0.084 ;
    END
  END dn3[93]
  PIN dn3[94]
    DIRECTION OUTPUT ;
    USE SIGNAL ;
    PORT
      LAYER M5 ;
        RECT  42 0 42.024 0.084 ;
    END
  END dn3[94]
  PIN dn3[95]
    DIRECTION OUTPUT ;
    USE SIGNAL ;
    PORT
      LAYER M5 ;
        RECT  42.096 0 42.12 0.084 ;
    END
  END dn3[95]
  PIN dn3[96]
    DIRECTION OUTPUT ;
    USE SIGNAL ;
    PORT
      LAYER M5 ;
        RECT  51.408 0 51.432 0.084 ;
    END
  END dn3[96]
  PIN dn3[97]
    DIRECTION OUTPUT ;
    USE SIGNAL ;
    PORT
      LAYER M5 ;
        RECT  51.504 0 51.528 0.084 ;
    END
  END dn3[97]
  PIN dn3[98]
    DIRECTION OUTPUT ;
    USE SIGNAL ;
    PORT
      LAYER M5 ;
        RECT  51.6 0 51.624 0.084 ;
    END
  END dn3[98]
  PIN dn3[99]
    DIRECTION OUTPUT ;
    USE SIGNAL ;
    PORT
      LAYER M5 ;
        RECT  51.696 0 51.72 0.084 ;
    END
  END dn3[99]
  PIN dn3[9]
    DIRECTION OUTPUT ;
    USE SIGNAL ;
    PORT
      LAYER M5 ;
        RECT  23.856 0 23.88 0.084 ;
    END
  END dn3[9]
  PIN done
    DIRECTION OUTPUT ;
    USE SIGNAL ;
    PORT
      LAYER M5 ;
        RECT  4.176 0 4.2 0.084 ;
    END
  END done
  PIN fault
    DIRECTION OUTPUT ;
    USE SIGNAL ;
    PORT
      LAYER M5 ;
        RECT  4.272 0 4.296 0.084 ;
    END
  END fault
  PIN fence_quiet
    DIRECTION OUTPUT ;
    USE SIGNAL ;
    PORT
      LAYER M5 ;
        RECT  4.368 0 4.392 0.084 ;
    END
  END fence_quiet
  PIN g_last
    DIRECTION INPUT ;
    USE SIGNAL ;
    PORT
      LAYER M5 ;
        RECT  4.464 0 4.488 0.084 ;
    END
  END g_last
  PIN g_mv[0]
    DIRECTION INPUT ;
    USE SIGNAL ;
    PORT
      LAYER M5 ;
        RECT  4.56 0 4.584 0.084 ;
    END
  END g_mv[0]
  PIN g_mv[100]
    DIRECTION INPUT ;
    USE SIGNAL ;
    PORT
      LAYER M5 ;
        RECT  55.632 0 55.656 0.084 ;
    END
  END g_mv[100]
  PIN g_mv[101]
    DIRECTION INPUT ;
    USE SIGNAL ;
    PORT
      LAYER M5 ;
        RECT  55.728 0 55.752 0.084 ;
    END
  END g_mv[101]
  PIN g_mv[102]
    DIRECTION INPUT ;
    USE SIGNAL ;
    PORT
      LAYER M5 ;
        RECT  55.824 0 55.848 0.084 ;
    END
  END g_mv[102]
  PIN g_mv[103]
    DIRECTION INPUT ;
    USE SIGNAL ;
    PORT
      LAYER M5 ;
        RECT  55.92 0 55.944 0.084 ;
    END
  END g_mv[103]
  PIN g_mv[104]
    DIRECTION INPUT ;
    USE SIGNAL ;
    PORT
      LAYER M5 ;
        RECT  56.016 0 56.04 0.084 ;
    END
  END g_mv[104]
  PIN g_mv[105]
    DIRECTION INPUT ;
    USE SIGNAL ;
    PORT
      LAYER M5 ;
        RECT  56.112 0 56.136 0.084 ;
    END
  END g_mv[105]
  PIN g_mv[106]
    DIRECTION INPUT ;
    USE SIGNAL ;
    PORT
      LAYER M5 ;
        RECT  56.208 0 56.232 0.084 ;
    END
  END g_mv[106]
  PIN g_mv[107]
    DIRECTION INPUT ;
    USE SIGNAL ;
    PORT
      LAYER M5 ;
        RECT  56.304 0 56.328 0.084 ;
    END
  END g_mv[107]
  PIN g_mv[108]
    DIRECTION INPUT ;
    USE SIGNAL ;
    PORT
      LAYER M5 ;
        RECT  56.4 0 56.424 0.084 ;
    END
  END g_mv[108]
  PIN g_mv[109]
    DIRECTION INPUT ;
    USE SIGNAL ;
    PORT
      LAYER M5 ;
        RECT  56.496 0 56.52 0.084 ;
    END
  END g_mv[109]
  PIN g_mv[10]
    DIRECTION INPUT ;
    USE SIGNAL ;
    PORT
      LAYER M5 ;
        RECT  5.52 0 5.544 0.084 ;
    END
  END g_mv[10]
  PIN g_mv[110]
    DIRECTION INPUT ;
    USE SIGNAL ;
    PORT
      LAYER M5 ;
        RECT  56.592 0 56.616 0.084 ;
    END
  END g_mv[110]
  PIN g_mv[111]
    DIRECTION INPUT ;
    USE SIGNAL ;
    PORT
      LAYER M5 ;
        RECT  56.688 0 56.712 0.084 ;
    END
  END g_mv[111]
  PIN g_mv[112]
    DIRECTION INPUT ;
    USE SIGNAL ;
    PORT
      LAYER M5 ;
        RECT  56.784 0 56.808 0.084 ;
    END
  END g_mv[112]
  PIN g_mv[113]
    DIRECTION INPUT ;
    USE SIGNAL ;
    PORT
      LAYER M5 ;
        RECT  56.88 0 56.904 0.084 ;
    END
  END g_mv[113]
  PIN g_mv[114]
    DIRECTION INPUT ;
    USE SIGNAL ;
    PORT
      LAYER M5 ;
        RECT  56.976 0 57 0.084 ;
    END
  END g_mv[114]
  PIN g_mv[115]
    DIRECTION INPUT ;
    USE SIGNAL ;
    PORT
      LAYER M5 ;
        RECT  57.072 0 57.096 0.084 ;
    END
  END g_mv[115]
  PIN g_mv[116]
    DIRECTION INPUT ;
    USE SIGNAL ;
    PORT
      LAYER M5 ;
        RECT  57.168 0 57.192 0.084 ;
    END
  END g_mv[116]
  PIN g_mv[117]
    DIRECTION INPUT ;
    USE SIGNAL ;
    PORT
      LAYER M5 ;
        RECT  57.264 0 57.288 0.084 ;
    END
  END g_mv[117]
  PIN g_mv[118]
    DIRECTION INPUT ;
    USE SIGNAL ;
    PORT
      LAYER M5 ;
        RECT  57.36 0 57.384 0.084 ;
    END
  END g_mv[118]
  PIN g_mv[119]
    DIRECTION INPUT ;
    USE SIGNAL ;
    PORT
      LAYER M5 ;
        RECT  57.456 0 57.48 0.084 ;
    END
  END g_mv[119]
  PIN g_mv[11]
    DIRECTION INPUT ;
    USE SIGNAL ;
    PORT
      LAYER M5 ;
        RECT  5.616 0 5.64 0.084 ;
    END
  END g_mv[11]
  PIN g_mv[120]
    DIRECTION INPUT ;
    USE SIGNAL ;
    PORT
      LAYER M5 ;
        RECT  42.192 0 42.216 0.084 ;
    END
  END g_mv[120]
  PIN g_mv[121]
    DIRECTION INPUT ;
    USE SIGNAL ;
    PORT
      LAYER M5 ;
        RECT  42.288 0 42.312 0.084 ;
    END
  END g_mv[121]
  PIN g_mv[122]
    DIRECTION INPUT ;
    USE SIGNAL ;
    PORT
      LAYER M5 ;
        RECT  42.384 0 42.408 0.084 ;
    END
  END g_mv[122]
  PIN g_mv[123]
    DIRECTION INPUT ;
    USE SIGNAL ;
    PORT
      LAYER M5 ;
        RECT  42.48 0 42.504 0.084 ;
    END
  END g_mv[123]
  PIN g_mv[124]
    DIRECTION INPUT ;
    USE SIGNAL ;
    PORT
      LAYER M5 ;
        RECT  42.576 0 42.6 0.084 ;
    END
  END g_mv[124]
  PIN g_mv[125]
    DIRECTION INPUT ;
    USE SIGNAL ;
    PORT
      LAYER M5 ;
        RECT  42.672 0 42.696 0.084 ;
    END
  END g_mv[125]
  PIN g_mv[126]
    DIRECTION INPUT ;
    USE SIGNAL ;
    PORT
      LAYER M5 ;
        RECT  42.768 0 42.792 0.084 ;
    END
  END g_mv[126]
  PIN g_mv[127]
    DIRECTION INPUT ;
    USE SIGNAL ;
    PORT
      LAYER M5 ;
        RECT  42.864 0 42.888 0.084 ;
    END
  END g_mv[127]
  PIN g_mv[128]
    DIRECTION INPUT ;
    USE SIGNAL ;
    PORT
      LAYER M5 ;
        RECT  42.96 0 42.984 0.084 ;
    END
  END g_mv[128]
  PIN g_mv[129]
    DIRECTION INPUT ;
    USE SIGNAL ;
    PORT
      LAYER M5 ;
        RECT  43.056 0 43.08 0.084 ;
    END
  END g_mv[129]
  PIN g_mv[12]
    DIRECTION INPUT ;
    USE SIGNAL ;
    PORT
      LAYER M5 ;
        RECT  5.712 0 5.736 0.084 ;
    END
  END g_mv[12]
  PIN g_mv[130]
    DIRECTION INPUT ;
    USE SIGNAL ;
    PORT
      LAYER M5 ;
        RECT  43.152 0 43.176 0.084 ;
    END
  END g_mv[130]
  PIN g_mv[131]
    DIRECTION INPUT ;
    USE SIGNAL ;
    PORT
      LAYER M5 ;
        RECT  43.248 0 43.272 0.084 ;
    END
  END g_mv[131]
  PIN g_mv[132]
    DIRECTION INPUT ;
    USE SIGNAL ;
    PORT
      LAYER M5 ;
        RECT  43.344 0 43.368 0.084 ;
    END
  END g_mv[132]
  PIN g_mv[133]
    DIRECTION INPUT ;
    USE SIGNAL ;
    PORT
      LAYER M5 ;
        RECT  43.44 0 43.464 0.084 ;
    END
  END g_mv[133]
  PIN g_mv[134]
    DIRECTION INPUT ;
    USE SIGNAL ;
    PORT
      LAYER M5 ;
        RECT  43.536 0 43.56 0.084 ;
    END
  END g_mv[134]
  PIN g_mv[135]
    DIRECTION INPUT ;
    USE SIGNAL ;
    PORT
      LAYER M5 ;
        RECT  43.632 0 43.656 0.084 ;
    END
  END g_mv[135]
  PIN g_mv[136]
    DIRECTION INPUT ;
    USE SIGNAL ;
    PORT
      LAYER M5 ;
        RECT  43.728 0 43.752 0.084 ;
    END
  END g_mv[136]
  PIN g_mv[137]
    DIRECTION INPUT ;
    USE SIGNAL ;
    PORT
      LAYER M5 ;
        RECT  43.824 0 43.848 0.084 ;
    END
  END g_mv[137]
  PIN g_mv[138]
    DIRECTION INPUT ;
    USE SIGNAL ;
    PORT
      LAYER M5 ;
        RECT  43.92 0 43.944 0.084 ;
    END
  END g_mv[138]
  PIN g_mv[139]
    DIRECTION INPUT ;
    USE SIGNAL ;
    PORT
      LAYER M5 ;
        RECT  44.016 0 44.04 0.084 ;
    END
  END g_mv[139]
  PIN g_mv[13]
    DIRECTION INPUT ;
    USE SIGNAL ;
    PORT
      LAYER M5 ;
        RECT  5.808 0 5.832 0.084 ;
    END
  END g_mv[13]
  PIN g_mv[140]
    DIRECTION INPUT ;
    USE SIGNAL ;
    PORT
      LAYER M5 ;
        RECT  44.112 0 44.136 0.084 ;
    END
  END g_mv[140]
  PIN g_mv[141]
    DIRECTION INPUT ;
    USE SIGNAL ;
    PORT
      LAYER M5 ;
        RECT  44.208 0 44.232 0.084 ;
    END
  END g_mv[141]
  PIN g_mv[142]
    DIRECTION INPUT ;
    USE SIGNAL ;
    PORT
      LAYER M5 ;
        RECT  44.304 0 44.328 0.084 ;
    END
  END g_mv[142]
  PIN g_mv[143]
    DIRECTION INPUT ;
    USE SIGNAL ;
    PORT
      LAYER M5 ;
        RECT  44.4 0 44.424 0.084 ;
    END
  END g_mv[143]
  PIN g_mv[144]
    DIRECTION INPUT ;
    USE SIGNAL ;
    PORT
      LAYER M5 ;
        RECT  44.496 0 44.52 0.084 ;
    END
  END g_mv[144]
  PIN g_mv[145]
    DIRECTION INPUT ;
    USE SIGNAL ;
    PORT
      LAYER M5 ;
        RECT  44.592 0 44.616 0.084 ;
    END
  END g_mv[145]
  PIN g_mv[146]
    DIRECTION INPUT ;
    USE SIGNAL ;
    PORT
      LAYER M5 ;
        RECT  44.688 0 44.712 0.084 ;
    END
  END g_mv[146]
  PIN g_mv[147]
    DIRECTION INPUT ;
    USE SIGNAL ;
    PORT
      LAYER M5 ;
        RECT  44.784 0 44.808 0.084 ;
    END
  END g_mv[147]
  PIN g_mv[148]
    DIRECTION INPUT ;
    USE SIGNAL ;
    PORT
      LAYER M5 ;
        RECT  44.88 0 44.904 0.084 ;
    END
  END g_mv[148]
  PIN g_mv[149]
    DIRECTION INPUT ;
    USE SIGNAL ;
    PORT
      LAYER M5 ;
        RECT  44.976 0 45 0.084 ;
    END
  END g_mv[149]
  PIN g_mv[14]
    DIRECTION INPUT ;
    USE SIGNAL ;
    PORT
      LAYER M5 ;
        RECT  5.904 0 5.928 0.084 ;
    END
  END g_mv[14]
  PIN g_mv[150]
    DIRECTION INPUT ;
    USE SIGNAL ;
    PORT
      LAYER M5 ;
        RECT  45.072 0 45.096 0.084 ;
    END
  END g_mv[150]
  PIN g_mv[151]
    DIRECTION INPUT ;
    USE SIGNAL ;
    PORT
      LAYER M5 ;
        RECT  45.168 0 45.192 0.084 ;
    END
  END g_mv[151]
  PIN g_mv[152]
    DIRECTION INPUT ;
    USE SIGNAL ;
    PORT
      LAYER M5 ;
        RECT  45.264 0 45.288 0.084 ;
    END
  END g_mv[152]
  PIN g_mv[153]
    DIRECTION INPUT ;
    USE SIGNAL ;
    PORT
      LAYER M5 ;
        RECT  45.36 0 45.384 0.084 ;
    END
  END g_mv[153]
  PIN g_mv[154]
    DIRECTION INPUT ;
    USE SIGNAL ;
    PORT
      LAYER M5 ;
        RECT  45.456 0 45.48 0.084 ;
    END
  END g_mv[154]
  PIN g_mv[155]
    DIRECTION INPUT ;
    USE SIGNAL ;
    PORT
      LAYER M5 ;
        RECT  45.552 0 45.576 0.084 ;
    END
  END g_mv[155]
  PIN g_mv[156]
    DIRECTION INPUT ;
    USE SIGNAL ;
    PORT
      LAYER M5 ;
        RECT  45.648 0 45.672 0.084 ;
    END
  END g_mv[156]
  PIN g_mv[157]
    DIRECTION INPUT ;
    USE SIGNAL ;
    PORT
      LAYER M5 ;
        RECT  45.744 0 45.768 0.084 ;
    END
  END g_mv[157]
  PIN g_mv[158]
    DIRECTION INPUT ;
    USE SIGNAL ;
    PORT
      LAYER M5 ;
        RECT  45.84 0 45.864 0.084 ;
    END
  END g_mv[158]
  PIN g_mv[159]
    DIRECTION INPUT ;
    USE SIGNAL ;
    PORT
      LAYER M5 ;
        RECT  45.936 0 45.96 0.084 ;
    END
  END g_mv[159]
  PIN g_mv[15]
    DIRECTION INPUT ;
    USE SIGNAL ;
    PORT
      LAYER M5 ;
        RECT  6 0 6.024 0.084 ;
    END
  END g_mv[15]
  PIN g_mv[160]
    DIRECTION INPUT ;
    USE SIGNAL ;
    PORT
      LAYER M5 ;
        RECT  46.032 0 46.056 0.084 ;
    END
  END g_mv[160]
  PIN g_mv[161]
    DIRECTION INPUT ;
    USE SIGNAL ;
    PORT
      LAYER M5 ;
        RECT  46.128 0 46.152 0.084 ;
    END
  END g_mv[161]
  PIN g_mv[162]
    DIRECTION INPUT ;
    USE SIGNAL ;
    PORT
      LAYER M5 ;
        RECT  46.224 0 46.248 0.084 ;
    END
  END g_mv[162]
  PIN g_mv[163]
    DIRECTION INPUT ;
    USE SIGNAL ;
    PORT
      LAYER M5 ;
        RECT  46.32 0 46.344 0.084 ;
    END
  END g_mv[163]
  PIN g_mv[164]
    DIRECTION INPUT ;
    USE SIGNAL ;
    PORT
      LAYER M5 ;
        RECT  46.416 0 46.44 0.084 ;
    END
  END g_mv[164]
  PIN g_mv[165]
    DIRECTION INPUT ;
    USE SIGNAL ;
    PORT
      LAYER M5 ;
        RECT  46.512 0 46.536 0.084 ;
    END
  END g_mv[165]
  PIN g_mv[166]
    DIRECTION INPUT ;
    USE SIGNAL ;
    PORT
      LAYER M5 ;
        RECT  46.608 0 46.632 0.084 ;
    END
  END g_mv[166]
  PIN g_mv[167]
    DIRECTION INPUT ;
    USE SIGNAL ;
    PORT
      LAYER M5 ;
        RECT  46.704 0 46.728 0.084 ;
    END
  END g_mv[167]
  PIN g_mv[168]
    DIRECTION INPUT ;
    USE SIGNAL ;
    PORT
      LAYER M5 ;
        RECT  46.8 0 46.824 0.084 ;
    END
  END g_mv[168]
  PIN g_mv[169]
    DIRECTION INPUT ;
    USE SIGNAL ;
    PORT
      LAYER M5 ;
        RECT  46.896 0 46.92 0.084 ;
    END
  END g_mv[169]
  PIN g_mv[16]
    DIRECTION INPUT ;
    USE SIGNAL ;
    PORT
      LAYER M5 ;
        RECT  6.096 0 6.12 0.084 ;
    END
  END g_mv[16]
  PIN g_mv[170]
    DIRECTION INPUT ;
    USE SIGNAL ;
    PORT
      LAYER M5 ;
        RECT  46.992 0 47.016 0.084 ;
    END
  END g_mv[170]
  PIN g_mv[171]
    DIRECTION INPUT ;
    USE SIGNAL ;
    PORT
      LAYER M5 ;
        RECT  47.088 0 47.112 0.084 ;
    END
  END g_mv[171]
  PIN g_mv[172]
    DIRECTION INPUT ;
    USE SIGNAL ;
    PORT
      LAYER M5 ;
        RECT  47.184 0 47.208 0.084 ;
    END
  END g_mv[172]
  PIN g_mv[173]
    DIRECTION INPUT ;
    USE SIGNAL ;
    PORT
      LAYER M5 ;
        RECT  47.28 0 47.304 0.084 ;
    END
  END g_mv[173]
  PIN g_mv[174]
    DIRECTION INPUT ;
    USE SIGNAL ;
    PORT
      LAYER M5 ;
        RECT  47.376 0 47.4 0.084 ;
    END
  END g_mv[174]
  PIN g_mv[175]
    DIRECTION INPUT ;
    USE SIGNAL ;
    PORT
      LAYER M5 ;
        RECT  47.472 0 47.496 0.084 ;
    END
  END g_mv[175]
  PIN g_mv[176]
    DIRECTION INPUT ;
    USE SIGNAL ;
    PORT
      LAYER M5 ;
        RECT  47.568 0 47.592 0.084 ;
    END
  END g_mv[176]
  PIN g_mv[177]
    DIRECTION INPUT ;
    USE SIGNAL ;
    PORT
      LAYER M5 ;
        RECT  47.664 0 47.688 0.084 ;
    END
  END g_mv[177]
  PIN g_mv[178]
    DIRECTION INPUT ;
    USE SIGNAL ;
    PORT
      LAYER M5 ;
        RECT  47.76 0 47.784 0.084 ;
    END
  END g_mv[178]
  PIN g_mv[179]
    DIRECTION INPUT ;
    USE SIGNAL ;
    PORT
      LAYER M5 ;
        RECT  47.856 0 47.88 0.084 ;
    END
  END g_mv[179]
  PIN g_mv[17]
    DIRECTION INPUT ;
    USE SIGNAL ;
    PORT
      LAYER M5 ;
        RECT  6.192 0 6.216 0.084 ;
    END
  END g_mv[17]
  PIN g_mv[180]
    DIRECTION INPUT ;
    USE SIGNAL ;
    PORT
      LAYER M5 ;
        RECT  47.952 0 47.976 0.084 ;
    END
  END g_mv[180]
  PIN g_mv[181]
    DIRECTION INPUT ;
    USE SIGNAL ;
    PORT
      LAYER M5 ;
        RECT  48.048 0 48.072 0.084 ;
    END
  END g_mv[181]
  PIN g_mv[182]
    DIRECTION INPUT ;
    USE SIGNAL ;
    PORT
      LAYER M5 ;
        RECT  48.144 0 48.168 0.084 ;
    END
  END g_mv[182]
  PIN g_mv[183]
    DIRECTION INPUT ;
    USE SIGNAL ;
    PORT
      LAYER M5 ;
        RECT  48.24 0 48.264 0.084 ;
    END
  END g_mv[183]
  PIN g_mv[184]
    DIRECTION INPUT ;
    USE SIGNAL ;
    PORT
      LAYER M5 ;
        RECT  13.008 0 13.032 0.084 ;
    END
  END g_mv[184]
  PIN g_mv[185]
    DIRECTION INPUT ;
    USE SIGNAL ;
    PORT
      LAYER M5 ;
        RECT  13.104 0 13.128 0.084 ;
    END
  END g_mv[185]
  PIN g_mv[186]
    DIRECTION INPUT ;
    USE SIGNAL ;
    PORT
      LAYER M5 ;
        RECT  13.2 0 13.224 0.084 ;
    END
  END g_mv[186]
  PIN g_mv[187]
    DIRECTION INPUT ;
    USE SIGNAL ;
    PORT
      LAYER M5 ;
        RECT  13.296 0 13.32 0.084 ;
    END
  END g_mv[187]
  PIN g_mv[188]
    DIRECTION INPUT ;
    USE SIGNAL ;
    PORT
      LAYER M5 ;
        RECT  13.392 0 13.416 0.084 ;
    END
  END g_mv[188]
  PIN g_mv[189]
    DIRECTION INPUT ;
    USE SIGNAL ;
    PORT
      LAYER M5 ;
        RECT  13.488 0 13.512 0.084 ;
    END
  END g_mv[189]
  PIN g_mv[18]
    DIRECTION INPUT ;
    USE SIGNAL ;
    PORT
      LAYER M5 ;
        RECT  6.288 0 6.312 0.084 ;
    END
  END g_mv[18]
  PIN g_mv[190]
    DIRECTION INPUT ;
    USE SIGNAL ;
    PORT
      LAYER M5 ;
        RECT  13.584 0 13.608 0.084 ;
    END
  END g_mv[190]
  PIN g_mv[191]
    DIRECTION INPUT ;
    USE SIGNAL ;
    PORT
      LAYER M5 ;
        RECT  13.68 0 13.704 0.084 ;
    END
  END g_mv[191]
  PIN g_mv[192]
    DIRECTION INPUT ;
    USE SIGNAL ;
    PORT
      LAYER M5 ;
        RECT  13.776 0 13.8 0.084 ;
    END
  END g_mv[192]
  PIN g_mv[193]
    DIRECTION INPUT ;
    USE SIGNAL ;
    PORT
      LAYER M5 ;
        RECT  13.872 0 13.896 0.084 ;
    END
  END g_mv[193]
  PIN g_mv[194]
    DIRECTION INPUT ;
    USE SIGNAL ;
    PORT
      LAYER M5 ;
        RECT  13.968 0 13.992 0.084 ;
    END
  END g_mv[194]
  PIN g_mv[195]
    DIRECTION INPUT ;
    USE SIGNAL ;
    PORT
      LAYER M5 ;
        RECT  14.064 0 14.088 0.084 ;
    END
  END g_mv[195]
  PIN g_mv[196]
    DIRECTION INPUT ;
    USE SIGNAL ;
    PORT
      LAYER M5 ;
        RECT  14.16 0 14.184 0.084 ;
    END
  END g_mv[196]
  PIN g_mv[197]
    DIRECTION INPUT ;
    USE SIGNAL ;
    PORT
      LAYER M5 ;
        RECT  14.256 0 14.28 0.084 ;
    END
  END g_mv[197]
  PIN g_mv[198]
    DIRECTION INPUT ;
    USE SIGNAL ;
    PORT
      LAYER M5 ;
        RECT  14.352 0 14.376 0.084 ;
    END
  END g_mv[198]
  PIN g_mv[199]
    DIRECTION INPUT ;
    USE SIGNAL ;
    PORT
      LAYER M5 ;
        RECT  14.448 0 14.472 0.084 ;
    END
  END g_mv[199]
  PIN g_mv[19]
    DIRECTION INPUT ;
    USE SIGNAL ;
    PORT
      LAYER M5 ;
        RECT  6.384 0 6.408 0.084 ;
    END
  END g_mv[19]
  PIN g_mv[1]
    DIRECTION INPUT ;
    USE SIGNAL ;
    PORT
      LAYER M5 ;
        RECT  4.656 0 4.68 0.084 ;
    END
  END g_mv[1]
  PIN g_mv[200]
    DIRECTION INPUT ;
    USE SIGNAL ;
    PORT
      LAYER M5 ;
        RECT  14.544 0 14.568 0.084 ;
    END
  END g_mv[200]
  PIN g_mv[201]
    DIRECTION INPUT ;
    USE SIGNAL ;
    PORT
      LAYER M5 ;
        RECT  14.64 0 14.664 0.084 ;
    END
  END g_mv[201]
  PIN g_mv[202]
    DIRECTION INPUT ;
    USE SIGNAL ;
    PORT
      LAYER M5 ;
        RECT  14.736 0 14.76 0.084 ;
    END
  END g_mv[202]
  PIN g_mv[203]
    DIRECTION INPUT ;
    USE SIGNAL ;
    PORT
      LAYER M5 ;
        RECT  14.832 0 14.856 0.084 ;
    END
  END g_mv[203]
  PIN g_mv[204]
    DIRECTION INPUT ;
    USE SIGNAL ;
    PORT
      LAYER M5 ;
        RECT  14.928 0 14.952 0.084 ;
    END
  END g_mv[204]
  PIN g_mv[205]
    DIRECTION INPUT ;
    USE SIGNAL ;
    PORT
      LAYER M5 ;
        RECT  15.024 0 15.048 0.084 ;
    END
  END g_mv[205]
  PIN g_mv[206]
    DIRECTION INPUT ;
    USE SIGNAL ;
    PORT
      LAYER M5 ;
        RECT  15.12 0 15.144 0.084 ;
    END
  END g_mv[206]
  PIN g_mv[207]
    DIRECTION INPUT ;
    USE SIGNAL ;
    PORT
      LAYER M5 ;
        RECT  15.216 0 15.24 0.084 ;
    END
  END g_mv[207]
  PIN g_mv[208]
    DIRECTION INPUT ;
    USE SIGNAL ;
    PORT
      LAYER M5 ;
        RECT  15.312 0 15.336 0.084 ;
    END
  END g_mv[208]
  PIN g_mv[209]
    DIRECTION INPUT ;
    USE SIGNAL ;
    PORT
      LAYER M5 ;
        RECT  15.408 0 15.432 0.084 ;
    END
  END g_mv[209]
  PIN g_mv[20]
    DIRECTION INPUT ;
    USE SIGNAL ;
    PORT
      LAYER M5 ;
        RECT  6.48 0 6.504 0.084 ;
    END
  END g_mv[20]
  PIN g_mv[210]
    DIRECTION INPUT ;
    USE SIGNAL ;
    PORT
      LAYER M5 ;
        RECT  15.504 0 15.528 0.084 ;
    END
  END g_mv[210]
  PIN g_mv[211]
    DIRECTION INPUT ;
    USE SIGNAL ;
    PORT
      LAYER M5 ;
        RECT  15.6 0 15.624 0.084 ;
    END
  END g_mv[211]
  PIN g_mv[212]
    DIRECTION INPUT ;
    USE SIGNAL ;
    PORT
      LAYER M5 ;
        RECT  15.696 0 15.72 0.084 ;
    END
  END g_mv[212]
  PIN g_mv[213]
    DIRECTION INPUT ;
    USE SIGNAL ;
    PORT
      LAYER M5 ;
        RECT  15.792 0 15.816 0.084 ;
    END
  END g_mv[213]
  PIN g_mv[214]
    DIRECTION INPUT ;
    USE SIGNAL ;
    PORT
      LAYER M5 ;
        RECT  15.888 0 15.912 0.084 ;
    END
  END g_mv[214]
  PIN g_mv[215]
    DIRECTION INPUT ;
    USE SIGNAL ;
    PORT
      LAYER M5 ;
        RECT  15.984 0 16.008 0.084 ;
    END
  END g_mv[215]
  PIN g_mv[216]
    DIRECTION INPUT ;
    USE SIGNAL ;
    PORT
      LAYER M5 ;
        RECT  9.936 0 9.96 0.084 ;
    END
  END g_mv[216]
  PIN g_mv[217]
    DIRECTION INPUT ;
    USE SIGNAL ;
    PORT
      LAYER M5 ;
        RECT  10.032 0 10.056 0.084 ;
    END
  END g_mv[217]
  PIN g_mv[218]
    DIRECTION INPUT ;
    USE SIGNAL ;
    PORT
      LAYER M5 ;
        RECT  10.128 0 10.152 0.084 ;
    END
  END g_mv[218]
  PIN g_mv[219]
    DIRECTION INPUT ;
    USE SIGNAL ;
    PORT
      LAYER M5 ;
        RECT  10.224 0 10.248 0.084 ;
    END
  END g_mv[219]
  PIN g_mv[21]
    DIRECTION INPUT ;
    USE SIGNAL ;
    PORT
      LAYER M5 ;
        RECT  6.576 0 6.6 0.084 ;
    END
  END g_mv[21]
  PIN g_mv[220]
    DIRECTION INPUT ;
    USE SIGNAL ;
    PORT
      LAYER M5 ;
        RECT  10.32 0 10.344 0.084 ;
    END
  END g_mv[220]
  PIN g_mv[221]
    DIRECTION INPUT ;
    USE SIGNAL ;
    PORT
      LAYER M5 ;
        RECT  10.416 0 10.44 0.084 ;
    END
  END g_mv[221]
  PIN g_mv[222]
    DIRECTION INPUT ;
    USE SIGNAL ;
    PORT
      LAYER M5 ;
        RECT  10.512 0 10.536 0.084 ;
    END
  END g_mv[222]
  PIN g_mv[223]
    DIRECTION INPUT ;
    USE SIGNAL ;
    PORT
      LAYER M5 ;
        RECT  10.608 0 10.632 0.084 ;
    END
  END g_mv[223]
  PIN g_mv[224]
    DIRECTION INPUT ;
    USE SIGNAL ;
    PORT
      LAYER M5 ;
        RECT  10.704 0 10.728 0.084 ;
    END
  END g_mv[224]
  PIN g_mv[225]
    DIRECTION INPUT ;
    USE SIGNAL ;
    PORT
      LAYER M5 ;
        RECT  10.8 0 10.824 0.084 ;
    END
  END g_mv[225]
  PIN g_mv[226]
    DIRECTION INPUT ;
    USE SIGNAL ;
    PORT
      LAYER M5 ;
        RECT  10.896 0 10.92 0.084 ;
    END
  END g_mv[226]
  PIN g_mv[22]
    DIRECTION INPUT ;
    USE SIGNAL ;
    PORT
      LAYER M5 ;
        RECT  6.672 0 6.696 0.084 ;
    END
  END g_mv[22]
  PIN g_mv[23]
    DIRECTION INPUT ;
    USE SIGNAL ;
    PORT
      LAYER M5 ;
        RECT  6.768 0 6.792 0.084 ;
    END
  END g_mv[23]
  PIN g_mv[24]
    DIRECTION INPUT ;
    USE SIGNAL ;
    PORT
      LAYER M5 ;
        RECT  6.864 0 6.888 0.084 ;
    END
  END g_mv[24]
  PIN g_mv[25]
    DIRECTION INPUT ;
    USE SIGNAL ;
    PORT
      LAYER M5 ;
        RECT  6.96 0 6.984 0.084 ;
    END
  END g_mv[25]
  PIN g_mv[26]
    DIRECTION INPUT ;
    USE SIGNAL ;
    PORT
      LAYER M5 ;
        RECT  7.056 0 7.08 0.084 ;
    END
  END g_mv[26]
  PIN g_mv[27]
    DIRECTION INPUT ;
    USE SIGNAL ;
    PORT
      LAYER M5 ;
        RECT  7.152 0 7.176 0.084 ;
    END
  END g_mv[27]
  PIN g_mv[28]
    DIRECTION INPUT ;
    USE SIGNAL ;
    PORT
      LAYER M5 ;
        RECT  7.248 0 7.272 0.084 ;
    END
  END g_mv[28]
  PIN g_mv[29]
    DIRECTION INPUT ;
    USE SIGNAL ;
    PORT
      LAYER M5 ;
        RECT  7.344 0 7.368 0.084 ;
    END
  END g_mv[29]
  PIN g_mv[2]
    DIRECTION INPUT ;
    USE SIGNAL ;
    PORT
      LAYER M5 ;
        RECT  4.752 0 4.776 0.084 ;
    END
  END g_mv[2]
  PIN g_mv[30]
    DIRECTION INPUT ;
    USE SIGNAL ;
    PORT
      LAYER M5 ;
        RECT  7.44 0 7.464 0.084 ;
    END
  END g_mv[30]
  PIN g_mv[31]
    DIRECTION INPUT ;
    USE SIGNAL ;
    PORT
      LAYER M5 ;
        RECT  7.536 0 7.56 0.084 ;
    END
  END g_mv[31]
  PIN g_mv[32]
    DIRECTION INPUT ;
    USE SIGNAL ;
    PORT
      LAYER M5 ;
        RECT  7.632 0 7.656 0.084 ;
    END
  END g_mv[32]
  PIN g_mv[33]
    DIRECTION INPUT ;
    USE SIGNAL ;
    PORT
      LAYER M5 ;
        RECT  7.728 0 7.752 0.084 ;
    END
  END g_mv[33]
  PIN g_mv[34]
    DIRECTION INPUT ;
    USE SIGNAL ;
    PORT
      LAYER M5 ;
        RECT  7.824 0 7.848 0.084 ;
    END
  END g_mv[34]
  PIN g_mv[35]
    DIRECTION INPUT ;
    USE SIGNAL ;
    PORT
      LAYER M5 ;
        RECT  7.92 0 7.944 0.084 ;
    END
  END g_mv[35]
  PIN g_mv[36]
    DIRECTION INPUT ;
    USE SIGNAL ;
    PORT
      LAYER M5 ;
        RECT  8.016 0 8.04 0.084 ;
    END
  END g_mv[36]
  PIN g_mv[37]
    DIRECTION INPUT ;
    USE SIGNAL ;
    PORT
      LAYER M5 ;
        RECT  8.112 0 8.136 0.084 ;
    END
  END g_mv[37]
  PIN g_mv[38]
    DIRECTION INPUT ;
    USE SIGNAL ;
    PORT
      LAYER M5 ;
        RECT  8.208 0 8.232 0.084 ;
    END
  END g_mv[38]
  PIN g_mv[39]
    DIRECTION INPUT ;
    USE SIGNAL ;
    PORT
      LAYER M5 ;
        RECT  8.304 0 8.328 0.084 ;
    END
  END g_mv[39]
  PIN g_mv[3]
    DIRECTION INPUT ;
    USE SIGNAL ;
    PORT
      LAYER M5 ;
        RECT  4.848 0 4.872 0.084 ;
    END
  END g_mv[3]
  PIN g_mv[40]
    DIRECTION INPUT ;
    USE SIGNAL ;
    PORT
      LAYER M5 ;
        RECT  8.4 0 8.424 0.084 ;
    END
  END g_mv[40]
  PIN g_mv[41]
    DIRECTION INPUT ;
    USE SIGNAL ;
    PORT
      LAYER M5 ;
        RECT  8.496 0 8.52 0.084 ;
    END
  END g_mv[41]
  PIN g_mv[42]
    DIRECTION INPUT ;
    USE SIGNAL ;
    PORT
      LAYER M5 ;
        RECT  8.592 0 8.616 0.084 ;
    END
  END g_mv[42]
  PIN g_mv[43]
    DIRECTION INPUT ;
    USE SIGNAL ;
    PORT
      LAYER M5 ;
        RECT  8.688 0 8.712 0.084 ;
    END
  END g_mv[43]
  PIN g_mv[44]
    DIRECTION INPUT ;
    USE SIGNAL ;
    PORT
      LAYER M5 ;
        RECT  8.784 0 8.808 0.084 ;
    END
  END g_mv[44]
  PIN g_mv[45]
    DIRECTION INPUT ;
    USE SIGNAL ;
    PORT
      LAYER M5 ;
        RECT  8.88 0 8.904 0.084 ;
    END
  END g_mv[45]
  PIN g_mv[46]
    DIRECTION INPUT ;
    USE SIGNAL ;
    PORT
      LAYER M5 ;
        RECT  8.976 0 9 0.084 ;
    END
  END g_mv[46]
  PIN g_mv[47]
    DIRECTION INPUT ;
    USE SIGNAL ;
    PORT
      LAYER M5 ;
        RECT  9.072 0 9.096 0.084 ;
    END
  END g_mv[47]
  PIN g_mv[48]
    DIRECTION INPUT ;
    USE SIGNAL ;
    PORT
      LAYER M5 ;
        RECT  9.168 0 9.192 0.084 ;
    END
  END g_mv[48]
  PIN g_mv[49]
    DIRECTION INPUT ;
    USE SIGNAL ;
    PORT
      LAYER M5 ;
        RECT  9.264 0 9.288 0.084 ;
    END
  END g_mv[49]
  PIN g_mv[4]
    DIRECTION INPUT ;
    USE SIGNAL ;
    PORT
      LAYER M5 ;
        RECT  4.944 0 4.968 0.084 ;
    END
  END g_mv[4]
  PIN g_mv[50]
    DIRECTION INPUT ;
    USE SIGNAL ;
    PORT
      LAYER M5 ;
        RECT  9.36 0 9.384 0.084 ;
    END
  END g_mv[50]
  PIN g_mv[51]
    DIRECTION INPUT ;
    USE SIGNAL ;
    PORT
      LAYER M5 ;
        RECT  9.456 0 9.48 0.084 ;
    END
  END g_mv[51]
  PIN g_mv[52]
    DIRECTION INPUT ;
    USE SIGNAL ;
    PORT
      LAYER M5 ;
        RECT  9.552 0 9.576 0.084 ;
    END
  END g_mv[52]
  PIN g_mv[53]
    DIRECTION INPUT ;
    USE SIGNAL ;
    PORT
      LAYER M5 ;
        RECT  9.648 0 9.672 0.084 ;
    END
  END g_mv[53]
  PIN g_mv[54]
    DIRECTION INPUT ;
    USE SIGNAL ;
    PORT
      LAYER M5 ;
        RECT  9.744 0 9.768 0.084 ;
    END
  END g_mv[54]
  PIN g_mv[55]
    DIRECTION INPUT ;
    USE SIGNAL ;
    PORT
      LAYER M5 ;
        RECT  9.84 0 9.864 0.084 ;
    END
  END g_mv[55]
  PIN g_mv[56]
    DIRECTION INPUT ;
    USE SIGNAL ;
    PORT
      LAYER M5 ;
        RECT  32.208 0 32.232 0.084 ;
    END
  END g_mv[56]
  PIN g_mv[57]
    DIRECTION INPUT ;
    USE SIGNAL ;
    PORT
      LAYER M5 ;
        RECT  32.304 0 32.328 0.084 ;
    END
  END g_mv[57]
  PIN g_mv[58]
    DIRECTION INPUT ;
    USE SIGNAL ;
    PORT
      LAYER M5 ;
        RECT  32.4 0 32.424 0.084 ;
    END
  END g_mv[58]
  PIN g_mv[59]
    DIRECTION INPUT ;
    USE SIGNAL ;
    PORT
      LAYER M5 ;
        RECT  32.496 0 32.52 0.084 ;
    END
  END g_mv[59]
  PIN g_mv[5]
    DIRECTION INPUT ;
    USE SIGNAL ;
    PORT
      LAYER M5 ;
        RECT  5.04 0 5.064 0.084 ;
    END
  END g_mv[5]
  PIN g_mv[60]
    DIRECTION INPUT ;
    USE SIGNAL ;
    PORT
      LAYER M5 ;
        RECT  32.592 0 32.616 0.084 ;
    END
  END g_mv[60]
  PIN g_mv[61]
    DIRECTION INPUT ;
    USE SIGNAL ;
    PORT
      LAYER M5 ;
        RECT  32.688 0 32.712 0.084 ;
    END
  END g_mv[61]
  PIN g_mv[62]
    DIRECTION INPUT ;
    USE SIGNAL ;
    PORT
      LAYER M5 ;
        RECT  32.784 0 32.808 0.084 ;
    END
  END g_mv[62]
  PIN g_mv[63]
    DIRECTION INPUT ;
    USE SIGNAL ;
    PORT
      LAYER M5 ;
        RECT  32.88 0 32.904 0.084 ;
    END
  END g_mv[63]
  PIN g_mv[64]
    DIRECTION INPUT ;
    USE SIGNAL ;
    PORT
      LAYER M5 ;
        RECT  32.976 0 33 0.084 ;
    END
  END g_mv[64]
  PIN g_mv[65]
    DIRECTION INPUT ;
    USE SIGNAL ;
    PORT
      LAYER M5 ;
        RECT  33.072 0 33.096 0.084 ;
    END
  END g_mv[65]
  PIN g_mv[66]
    DIRECTION INPUT ;
    USE SIGNAL ;
    PORT
      LAYER M5 ;
        RECT  33.168 0 33.192 0.084 ;
    END
  END g_mv[66]
  PIN g_mv[67]
    DIRECTION INPUT ;
    USE SIGNAL ;
    PORT
      LAYER M5 ;
        RECT  33.264 0 33.288 0.084 ;
    END
  END g_mv[67]
  PIN g_mv[68]
    DIRECTION INPUT ;
    USE SIGNAL ;
    PORT
      LAYER M5 ;
        RECT  33.36 0 33.384 0.084 ;
    END
  END g_mv[68]
  PIN g_mv[69]
    DIRECTION INPUT ;
    USE SIGNAL ;
    PORT
      LAYER M5 ;
        RECT  33.456 0 33.48 0.084 ;
    END
  END g_mv[69]
  PIN g_mv[6]
    DIRECTION INPUT ;
    USE SIGNAL ;
    PORT
      LAYER M5 ;
        RECT  5.136 0 5.16 0.084 ;
    END
  END g_mv[6]
  PIN g_mv[70]
    DIRECTION INPUT ;
    USE SIGNAL ;
    PORT
      LAYER M5 ;
        RECT  33.552 0 33.576 0.084 ;
    END
  END g_mv[70]
  PIN g_mv[71]
    DIRECTION INPUT ;
    USE SIGNAL ;
    PORT
      LAYER M5 ;
        RECT  33.648 0 33.672 0.084 ;
    END
  END g_mv[71]
  PIN g_mv[72]
    DIRECTION INPUT ;
    USE SIGNAL ;
    PORT
      LAYER M5 ;
        RECT  33.744 0 33.768 0.084 ;
    END
  END g_mv[72]
  PIN g_mv[73]
    DIRECTION INPUT ;
    USE SIGNAL ;
    PORT
      LAYER M5 ;
        RECT  33.84 0 33.864 0.084 ;
    END
  END g_mv[73]
  PIN g_mv[74]
    DIRECTION INPUT ;
    USE SIGNAL ;
    PORT
      LAYER M5 ;
        RECT  33.936 0 33.96 0.084 ;
    END
  END g_mv[74]
  PIN g_mv[75]
    DIRECTION INPUT ;
    USE SIGNAL ;
    PORT
      LAYER M5 ;
        RECT  34.032 0 34.056 0.084 ;
    END
  END g_mv[75]
  PIN g_mv[76]
    DIRECTION INPUT ;
    USE SIGNAL ;
    PORT
      LAYER M5 ;
        RECT  34.128 0 34.152 0.084 ;
    END
  END g_mv[76]
  PIN g_mv[77]
    DIRECTION INPUT ;
    USE SIGNAL ;
    PORT
      LAYER M5 ;
        RECT  34.224 0 34.248 0.084 ;
    END
  END g_mv[77]
  PIN g_mv[78]
    DIRECTION INPUT ;
    USE SIGNAL ;
    PORT
      LAYER M5 ;
        RECT  34.32 0 34.344 0.084 ;
    END
  END g_mv[78]
  PIN g_mv[79]
    DIRECTION INPUT ;
    USE SIGNAL ;
    PORT
      LAYER M5 ;
        RECT  34.416 0 34.44 0.084 ;
    END
  END g_mv[79]
  PIN g_mv[7]
    DIRECTION INPUT ;
    USE SIGNAL ;
    PORT
      LAYER M5 ;
        RECT  5.232 0 5.256 0.084 ;
    END
  END g_mv[7]
  PIN g_mv[80]
    DIRECTION INPUT ;
    USE SIGNAL ;
    PORT
      LAYER M5 ;
        RECT  34.512 0 34.536 0.084 ;
    END
  END g_mv[80]
  PIN g_mv[81]
    DIRECTION INPUT ;
    USE SIGNAL ;
    PORT
      LAYER M5 ;
        RECT  34.608 0 34.632 0.084 ;
    END
  END g_mv[81]
  PIN g_mv[82]
    DIRECTION INPUT ;
    USE SIGNAL ;
    PORT
      LAYER M5 ;
        RECT  34.704 0 34.728 0.084 ;
    END
  END g_mv[82]
  PIN g_mv[83]
    DIRECTION INPUT ;
    USE SIGNAL ;
    PORT
      LAYER M5 ;
        RECT  34.8 0 34.824 0.084 ;
    END
  END g_mv[83]
  PIN g_mv[84]
    DIRECTION INPUT ;
    USE SIGNAL ;
    PORT
      LAYER M5 ;
        RECT  34.896 0 34.92 0.084 ;
    END
  END g_mv[84]
  PIN g_mv[85]
    DIRECTION INPUT ;
    USE SIGNAL ;
    PORT
      LAYER M5 ;
        RECT  34.992 0 35.016 0.084 ;
    END
  END g_mv[85]
  PIN g_mv[86]
    DIRECTION INPUT ;
    USE SIGNAL ;
    PORT
      LAYER M5 ;
        RECT  35.088 0 35.112 0.084 ;
    END
  END g_mv[86]
  PIN g_mv[87]
    DIRECTION INPUT ;
    USE SIGNAL ;
    PORT
      LAYER M5 ;
        RECT  35.184 0 35.208 0.084 ;
    END
  END g_mv[87]
  PIN g_mv[88]
    DIRECTION INPUT ;
    USE SIGNAL ;
    PORT
      LAYER M5 ;
        RECT  54.48 0 54.504 0.084 ;
    END
  END g_mv[88]
  PIN g_mv[89]
    DIRECTION INPUT ;
    USE SIGNAL ;
    PORT
      LAYER M5 ;
        RECT  54.576 0 54.6 0.084 ;
    END
  END g_mv[89]
  PIN g_mv[8]
    DIRECTION INPUT ;
    USE SIGNAL ;
    PORT
      LAYER M5 ;
        RECT  5.328 0 5.352 0.084 ;
    END
  END g_mv[8]
  PIN g_mv[90]
    DIRECTION INPUT ;
    USE SIGNAL ;
    PORT
      LAYER M5 ;
        RECT  54.672 0 54.696 0.084 ;
    END
  END g_mv[90]
  PIN g_mv[91]
    DIRECTION INPUT ;
    USE SIGNAL ;
    PORT
      LAYER M5 ;
        RECT  54.768 0 54.792 0.084 ;
    END
  END g_mv[91]
  PIN g_mv[92]
    DIRECTION INPUT ;
    USE SIGNAL ;
    PORT
      LAYER M5 ;
        RECT  54.864 0 54.888 0.084 ;
    END
  END g_mv[92]
  PIN g_mv[93]
    DIRECTION INPUT ;
    USE SIGNAL ;
    PORT
      LAYER M5 ;
        RECT  54.96 0 54.984 0.084 ;
    END
  END g_mv[93]
  PIN g_mv[94]
    DIRECTION INPUT ;
    USE SIGNAL ;
    PORT
      LAYER M5 ;
        RECT  55.056 0 55.08 0.084 ;
    END
  END g_mv[94]
  PIN g_mv[95]
    DIRECTION INPUT ;
    USE SIGNAL ;
    PORT
      LAYER M5 ;
        RECT  55.152 0 55.176 0.084 ;
    END
  END g_mv[95]
  PIN g_mv[96]
    DIRECTION INPUT ;
    USE SIGNAL ;
    PORT
      LAYER M5 ;
        RECT  55.248 0 55.272 0.084 ;
    END
  END g_mv[96]
  PIN g_mv[97]
    DIRECTION INPUT ;
    USE SIGNAL ;
    PORT
      LAYER M5 ;
        RECT  55.344 0 55.368 0.084 ;
    END
  END g_mv[97]
  PIN g_mv[98]
    DIRECTION INPUT ;
    USE SIGNAL ;
    PORT
      LAYER M5 ;
        RECT  55.44 0 55.464 0.084 ;
    END
  END g_mv[98]
  PIN g_mv[99]
    DIRECTION INPUT ;
    USE SIGNAL ;
    PORT
      LAYER M5 ;
        RECT  55.536 0 55.56 0.084 ;
    END
  END g_mv[99]
  PIN g_mv[9]
    DIRECTION INPUT ;
    USE SIGNAL ;
    PORT
      LAYER M5 ;
        RECT  5.424 0 5.448 0.084 ;
    END
  END g_mv[9]
  PIN g_q[0]
    DIRECTION INPUT ;
    USE SIGNAL ;
    PORT
      LAYER M5 ;
        RECT  10.992 0 11.016 0.084 ;
    END
  END g_q[0]
  PIN g_q[1]
    DIRECTION INPUT ;
    USE SIGNAL ;
    PORT
      LAYER M5 ;
        RECT  11.088 0 11.112 0.084 ;
    END
  END g_q[1]
  PIN g_rdy
    DIRECTION OUTPUT ;
    USE SIGNAL ;
    PORT
      LAYER M5 ;
        RECT  11.184 0 11.208 0.084 ;
    END
  END g_rdy
  PIN g_v
    DIRECTION INPUT ;
    USE SIGNAL ;
    PORT
      LAYER M5 ;
        RECT  11.28 0 11.304 0.084 ;
    END
  END g_v
  PIN rst_n
    DIRECTION INPUT ;
    USE SIGNAL ;
    PORT
      LAYER M4 ;
        RECT  0 25.296 0.084 25.32 ;
    END
  END rst_n
  PIN up0[0]
    DIRECTION INPUT ;
    USE SIGNAL ;
    PORT
      LAYER M4 ;
        RECT  0 25.392 0.084 25.416 ;
    END
  END up0[0]
  PIN up0[1]
    DIRECTION INPUT ;
    USE SIGNAL ;
    PORT
      LAYER M4 ;
        RECT  0 25.488 0.084 25.512 ;
    END
  END up0[1]
  PIN up0[2]
    DIRECTION INPUT ;
    USE SIGNAL ;
    PORT
      LAYER M4 ;
        RECT  0 25.584 0.084 25.608 ;
    END
  END up0[2]
  PIN up1[0]
    DIRECTION INPUT ;
    USE SIGNAL ;
    PORT
      LAYER M5 ;
        RECT  25.392 64.716 25.416 64.8 ;
    END
  END up1[0]
  PIN up1[1]
    DIRECTION INPUT ;
    USE SIGNAL ;
    PORT
      LAYER M5 ;
        RECT  25.488 64.716 25.512 64.8 ;
    END
  END up1[1]
  PIN up1[2]
    DIRECTION INPUT ;
    USE SIGNAL ;
    PORT
      LAYER M5 ;
        RECT  25.584 64.716 25.608 64.8 ;
    END
  END up1[2]
  PIN up2[0]
    DIRECTION INPUT ;
    USE SIGNAL ;
    PORT
      LAYER M4 ;
        RECT  64.716 26.448 64.8 26.472 ;
    END
  END up2[0]
  PIN up2[1]
    DIRECTION INPUT ;
    USE SIGNAL ;
    PORT
      LAYER M4 ;
        RECT  64.716 26.544 64.8 26.568 ;
    END
  END up2[1]
  PIN up2[2]
    DIRECTION INPUT ;
    USE SIGNAL ;
    PORT
      LAYER M4 ;
        RECT  64.716 26.64 64.8 26.664 ;
    END
  END up2[2]
  PIN up3[0]
    DIRECTION INPUT ;
    USE SIGNAL ;
    PORT
      LAYER M5 ;
        RECT  11.376 0 11.4 0.084 ;
    END
  END up3[0]
  PIN up3[1]
    DIRECTION INPUT ;
    USE SIGNAL ;
    PORT
      LAYER M5 ;
        RECT  11.472 0 11.496 0.084 ;
    END
  END up3[1]
  PIN up3[2]
    DIRECTION INPUT ;
    USE SIGNAL ;
    PORT
      LAYER M5 ;
        RECT  11.568 0 11.592 0.084 ;
    END
  END up3[2]
  PIN VDD
    DIRECTION INOUT ;
    USE POWER ;
    PORT
      LAYER M5 ;
        RECT  61.992 2.151 62.112 62.649 ;
        RECT  56.592 2.151 56.712 62.649 ;
        RECT  51.192 2.151 51.312 62.649 ;
        RECT  45.792 2.151 45.912 62.649 ;
        RECT  40.392 2.151 40.512 62.649 ;
        RECT  34.992 2.151 35.112 62.649 ;
        RECT  29.592 2.151 29.712 62.649 ;
        RECT  24.192 2.151 24.312 62.649 ;
        RECT  18.792 2.151 18.912 62.649 ;
        RECT  13.392 2.151 13.512 62.649 ;
        RECT  7.992 2.151 8.112 62.649 ;
        RECT  2.592 2.151 2.712 62.649 ;
    END
  END VDD
  PIN VSS
    DIRECTION INOUT ;
    USE GROUND ;
    PORT
      LAYER M5 ;
        RECT  61.8 2.137 61.92 62.663 ;
        RECT  56.4 2.137 56.52 62.663 ;
        RECT  51 2.137 51.12 62.663 ;
        RECT  45.6 2.137 45.72 62.663 ;
        RECT  40.2 2.137 40.32 62.663 ;
        RECT  34.8 2.137 34.92 62.663 ;
        RECT  29.4 2.137 29.52 62.663 ;
        RECT  24 2.137 24.12 62.663 ;
        RECT  18.6 2.137 18.72 62.663 ;
        RECT  13.2 2.137 13.32 62.663 ;
        RECT  7.8 2.137 7.92 62.663 ;
        RECT  2.4 2.137 2.52 62.663 ;
    END
  END VSS
  OBS
    LAYER RVTN ;
     RECT  2.16 2.16 62.64 2.295 ;
     RECT  2.16 2.565 62.64 2.835 ;
     RECT  2.16 3.105 62.64 3.375 ;
     RECT  2.16 3.645 62.64 3.915 ;
     RECT  2.16 4.185 62.64 4.455 ;
     RECT  2.16 4.725 62.64 4.995 ;
     RECT  2.16 5.265 62.64 5.535 ;
     RECT  2.16 5.805 62.64 6.075 ;
     RECT  2.16 6.345 62.64 6.615 ;
     RECT  2.16 6.885 62.64 7.155 ;
     RECT  2.16 7.425 62.64 7.695 ;
     RECT  2.16 7.965 62.64 8.235 ;
     RECT  2.16 8.505 62.64 8.775 ;
     RECT  2.16 9.045 62.64 9.315 ;
     RECT  2.16 9.585 62.64 9.855 ;
     RECT  2.16 10.125 62.64 10.395 ;
     RECT  2.16 10.665 62.64 10.935 ;
     RECT  2.16 11.205 62.64 11.475 ;
     RECT  2.16 11.745 62.64 12.015 ;
     RECT  2.16 12.285 62.64 12.555 ;
     RECT  2.16 12.825 62.64 13.095 ;
     RECT  2.16 13.365 62.64 13.635 ;
     RECT  2.16 13.905 62.64 14.175 ;
     RECT  2.16 14.445 62.64 14.715 ;
     RECT  2.16 14.985 62.64 15.255 ;
     RECT  2.16 15.525 62.64 15.795 ;
     RECT  2.16 16.065 62.64 16.335 ;
     RECT  2.16 16.605 62.64 16.875 ;
     RECT  2.16 17.145 62.64 17.415 ;
     RECT  2.16 17.685 62.64 17.955 ;
     RECT  2.16 18.225 62.64 18.495 ;
     RECT  2.16 18.765 62.64 19.035 ;
     RECT  2.16 19.305 62.64 19.575 ;
     RECT  2.16 19.845 62.64 20.115 ;
     RECT  2.16 20.385 62.64 20.655 ;
     RECT  2.16 20.925 62.64 21.195 ;
     RECT  2.16 21.465 62.64 21.735 ;
     RECT  2.16 22.005 62.64 22.275 ;
     RECT  2.16 22.545 62.64 22.815 ;
     RECT  2.16 23.085 62.64 23.355 ;
     RECT  2.16 23.625 62.64 23.895 ;
     RECT  2.16 24.165 62.64 24.435 ;
     RECT  2.16 24.705 62.64 24.975 ;
     RECT  2.16 25.245 62.64 25.515 ;
     RECT  2.16 25.785 62.64 26.055 ;
     RECT  2.16 26.325 62.64 26.595 ;
     RECT  2.16 26.865 62.64 27.135 ;
     RECT  2.16 27.405 62.64 27.675 ;
     RECT  2.16 27.945 62.64 28.215 ;
     RECT  2.16 28.485 62.64 28.755 ;
     RECT  2.16 29.025 62.64 29.295 ;
     RECT  2.16 29.565 62.64 29.835 ;
     RECT  2.16 30.105 62.64 30.375 ;
     RECT  2.16 30.645 62.64 30.915 ;
     RECT  2.16 31.185 62.64 31.455 ;
     RECT  2.16 31.725 62.64 31.995 ;
     RECT  2.16 32.265 62.64 32.535 ;
     RECT  2.16 32.805 62.64 33.075 ;
     RECT  2.16 33.345 62.64 33.615 ;
     RECT  2.16 33.885 62.64 34.155 ;
     RECT  2.16 34.425 62.64 34.695 ;
     RECT  2.16 34.965 62.64 35.235 ;
     RECT  2.16 35.505 62.64 35.775 ;
     RECT  2.16 36.045 62.64 36.315 ;
     RECT  2.16 36.585 62.64 36.855 ;
     RECT  2.16 37.125 62.64 37.395 ;
     RECT  2.16 37.665 62.64 37.935 ;
     RECT  2.16 38.205 62.64 38.475 ;
     RECT  2.16 38.745 62.64 39.015 ;
     RECT  2.16 39.285 62.64 39.555 ;
     RECT  2.16 39.825 62.64 40.095 ;
     RECT  2.16 40.365 62.64 40.635 ;
     RECT  2.16 40.905 62.64 41.175 ;
     RECT  2.16 41.445 62.64 41.715 ;
     RECT  2.16 41.985 62.64 42.255 ;
     RECT  2.16 42.525 62.64 42.795 ;
     RECT  2.16 43.065 62.64 43.335 ;
     RECT  2.16 43.605 62.64 43.875 ;
     RECT  2.16 44.145 62.64 44.415 ;
     RECT  2.16 44.685 62.64 44.955 ;
     RECT  2.16 45.225 62.64 45.495 ;
     RECT  2.16 45.765 62.64 46.035 ;
     RECT  2.16 46.305 62.64 46.575 ;
     RECT  2.16 46.845 62.64 47.115 ;
     RECT  2.16 47.385 62.64 47.655 ;
     RECT  2.16 47.925 62.64 48.195 ;
     RECT  2.16 48.465 62.64 48.735 ;
     RECT  2.16 49.005 62.64 49.275 ;
     RECT  2.16 49.545 62.64 49.815 ;
     RECT  2.16 50.085 62.64 50.355 ;
     RECT  2.16 50.625 62.64 50.895 ;
     RECT  2.16 51.165 62.64 51.435 ;
     RECT  2.16 51.705 62.64 51.975 ;
     RECT  2.16 52.245 62.64 52.515 ;
     RECT  2.16 52.785 62.64 53.055 ;
     RECT  2.16 53.325 62.64 53.595 ;
     RECT  2.16 53.865 62.64 54.135 ;
     RECT  2.16 54.405 62.64 54.675 ;
     RECT  2.16 54.945 62.64 55.215 ;
     RECT  2.16 55.485 62.64 55.755 ;
     RECT  2.16 56.025 62.64 56.295 ;
     RECT  2.16 56.565 62.64 56.835 ;
     RECT  2.16 57.105 62.64 57.375 ;
     RECT  2.16 57.645 62.64 57.915 ;
     RECT  2.16 58.185 62.64 58.455 ;
     RECT  2.16 58.725 62.64 58.995 ;
     RECT  2.16 59.265 62.64 59.535 ;
     RECT  2.16 59.805 62.64 60.075 ;
     RECT  2.16 60.345 62.64 60.615 ;
     RECT  2.16 60.885 62.64 61.155 ;
     RECT  2.16 61.425 62.64 61.695 ;
     RECT  2.16 61.965 62.64 62.235 ;
     RECT  2.16 62.505 62.64 62.64 ;
    LAYER RVTP ;
     RECT  2.16 2.295 62.64 2.565 ;
     RECT  2.16 2.835 62.64 3.105 ;
     RECT  2.16 3.375 62.64 3.645 ;
     RECT  2.16 3.915 62.64 4.185 ;
     RECT  2.16 4.455 62.64 4.725 ;
     RECT  2.16 4.995 62.64 5.265 ;
     RECT  2.16 5.535 62.64 5.805 ;
     RECT  2.16 6.075 62.64 6.345 ;
     RECT  2.16 6.615 62.64 6.885 ;
     RECT  2.16 7.155 62.64 7.425 ;
     RECT  2.16 7.695 62.64 7.965 ;
     RECT  2.16 8.235 62.64 8.505 ;
     RECT  2.16 8.775 62.64 9.045 ;
     RECT  2.16 9.315 62.64 9.585 ;
     RECT  2.16 9.855 62.64 10.125 ;
     RECT  2.16 10.395 62.64 10.665 ;
     RECT  2.16 10.935 62.64 11.205 ;
     RECT  2.16 11.475 62.64 11.745 ;
     RECT  2.16 12.015 62.64 12.285 ;
     RECT  2.16 12.555 62.64 12.825 ;
     RECT  2.16 13.095 62.64 13.365 ;
     RECT  2.16 13.635 62.64 13.905 ;
     RECT  2.16 14.175 62.64 14.445 ;
     RECT  2.16 14.715 62.64 14.985 ;
     RECT  2.16 15.255 62.64 15.525 ;
     RECT  2.16 15.795 62.64 16.065 ;
     RECT  2.16 16.335 62.64 16.605 ;
     RECT  2.16 16.875 62.64 17.145 ;
     RECT  2.16 17.415 62.64 17.685 ;
     RECT  2.16 17.955 62.64 18.225 ;
     RECT  2.16 18.495 62.64 18.765 ;
     RECT  2.16 19.035 62.64 19.305 ;
     RECT  2.16 19.575 62.64 19.845 ;
     RECT  2.16 20.115 62.64 20.385 ;
     RECT  2.16 20.655 62.64 20.925 ;
     RECT  2.16 21.195 62.64 21.465 ;
     RECT  2.16 21.735 62.64 22.005 ;
     RECT  2.16 22.275 62.64 22.545 ;
     RECT  2.16 22.815 62.64 23.085 ;
     RECT  2.16 23.355 62.64 23.625 ;
     RECT  2.16 23.895 62.64 24.165 ;
     RECT  2.16 24.435 62.64 24.705 ;
     RECT  2.16 24.975 62.64 25.245 ;
     RECT  2.16 25.515 62.64 25.785 ;
     RECT  2.16 26.055 62.64 26.325 ;
     RECT  2.16 26.595 62.64 26.865 ;
     RECT  2.16 27.135 62.64 27.405 ;
     RECT  2.16 27.675 62.64 27.945 ;
     RECT  2.16 28.215 62.64 28.485 ;
     RECT  2.16 28.755 62.64 29.025 ;
     RECT  2.16 29.295 62.64 29.565 ;
     RECT  2.16 29.835 62.64 30.105 ;
     RECT  2.16 30.375 62.64 30.645 ;
     RECT  2.16 30.915 62.64 31.185 ;
     RECT  2.16 31.455 62.64 31.725 ;
     RECT  2.16 31.995 62.64 32.265 ;
     RECT  2.16 32.535 62.64 32.805 ;
     RECT  2.16 33.075 62.64 33.345 ;
     RECT  2.16 33.615 62.64 33.885 ;
     RECT  2.16 34.155 62.64 34.425 ;
     RECT  2.16 34.695 62.64 34.965 ;
     RECT  2.16 35.235 62.64 35.505 ;
     RECT  2.16 35.775 62.64 36.045 ;
     RECT  2.16 36.315 62.64 36.585 ;
     RECT  2.16 36.855 62.64 37.125 ;
     RECT  2.16 37.395 62.64 37.665 ;
     RECT  2.16 37.935 62.64 38.205 ;
     RECT  2.16 38.475 62.64 38.745 ;
     RECT  2.16 39.015 62.64 39.285 ;
     RECT  2.16 39.555 62.64 39.825 ;
     RECT  2.16 40.095 62.64 40.365 ;
     RECT  2.16 40.635 62.64 40.905 ;
     RECT  2.16 41.175 62.64 41.445 ;
     RECT  2.16 41.715 62.64 41.985 ;
     RECT  2.16 42.255 62.64 42.525 ;
     RECT  2.16 42.795 62.64 43.065 ;
     RECT  2.16 43.335 62.64 43.605 ;
     RECT  2.16 43.875 62.64 44.145 ;
     RECT  2.16 44.415 62.64 44.685 ;
     RECT  2.16 44.955 62.64 45.225 ;
     RECT  2.16 45.495 62.64 45.765 ;
     RECT  2.16 46.035 62.64 46.305 ;
     RECT  2.16 46.575 62.64 46.845 ;
     RECT  2.16 47.115 62.64 47.385 ;
     RECT  2.16 47.655 62.64 47.925 ;
     RECT  2.16 48.195 62.64 48.465 ;
     RECT  2.16 48.735 62.64 49.005 ;
     RECT  2.16 49.275 62.64 49.545 ;
     RECT  2.16 49.815 62.64 50.085 ;
     RECT  2.16 50.355 62.64 50.625 ;
     RECT  2.16 50.895 62.64 51.165 ;
     RECT  2.16 51.435 62.64 51.705 ;
     RECT  2.16 51.975 62.64 52.245 ;
     RECT  2.16 52.515 62.64 52.785 ;
     RECT  2.16 53.055 62.64 53.325 ;
     RECT  2.16 53.595 62.64 53.865 ;
     RECT  2.16 54.135 62.64 54.405 ;
     RECT  2.16 54.675 62.64 54.945 ;
     RECT  2.16 55.215 62.64 55.485 ;
     RECT  2.16 55.755 62.64 56.025 ;
     RECT  2.16 56.295 62.64 56.565 ;
     RECT  2.16 56.835 62.64 57.105 ;
     RECT  2.16 57.375 62.64 57.645 ;
     RECT  2.16 57.915 62.64 58.185 ;
     RECT  2.16 58.455 62.64 58.725 ;
     RECT  2.16 58.995 62.64 59.265 ;
     RECT  2.16 59.535 62.64 59.805 ;
     RECT  2.16 60.075 62.64 60.345 ;
     RECT  2.16 60.615 62.64 60.885 ;
     RECT  2.16 61.155 62.64 61.425 ;
     RECT  2.16 61.695 62.64 61.965 ;
     RECT  2.16 62.235 62.64 62.505 ;
    LAYER M1 ;
     RECT  2.16 2.151 62.64 62.649 ;
    LAYER M2 ;
     RECT  0.031 10.296 0.067 11.502 ;
     RECT  0.031 22.752 0.067 22.77 ;
     RECT  0.031 14.724 0.103 14.904 ;
     RECT  0.031 16.776 0.103 16.794 ;
     RECT  0.031 41.796 0.103 41.814 ;
     RECT  0.103 16.776 0.131 16.902 ;
     RECT  0.031 19.62 0.131 19.638 ;
     RECT  0.031 35.091 0.131 35.109 ;
     RECT  0.067 10.296 0.139 11.889 ;
     RECT  0.103 46.116 0.139 47.304 ;
     RECT  0.103 48.168 0.139 48.924 ;
     RECT  0.103 50.634 0.139 50.652 ;
     RECT  0.139 9.756 0.167 11.889 ;
     RECT  0.067 24.948 0.167 24.966 ;
     RECT  0.103 14.49 0.175 14.904 ;
     RECT  0.131 16.884 0.203 16.902 ;
     RECT  0.103 18.036 0.211 18.054 ;
     RECT  0.139 13.176 0.239 13.284 ;
     RECT  0.167 10.836 0.247 11.889 ;
     RECT  0.247 10.836 0.275 12.348 ;
     RECT  0.275 12.33 0.347 12.348 ;
     RECT  0.175 14.184 0.347 14.904 ;
     RECT  0.067 22.752 0.347 22.842 ;
     RECT  0.275 10.908 0.383 11.43 ;
     RECT  0.347 14.184 0.383 14.814 ;
     RECT  0.139 46.116 0.391 48.924 ;
     RECT  0.355 45.234 0.427 45.252 ;
     RECT  0.391 46.008 0.427 48.924 ;
     RECT  0.427 45.234 0.463 48.924 ;
     RECT  0.103 41.526 0.499 41.814 ;
     RECT  0.211 17.226 0.535 17.244 ;
     RECT  0.211 18.036 0.535 18.144 ;
     RECT  0.499 41.526 0.535 42.012 ;
     RECT  0.499 43.614 0.535 43.632 ;
     RECT  0.463 44.496 0.535 48.924 ;
     RECT  0.031 29.646 0.823 29.664 ;
     RECT  0.067 30.996 0.859 31.014 ;
     RECT  0.823 29.646 0.931 29.862 ;
     RECT  0.859 30.996 0.931 31.284 ;
     RECT  0.175 20.511 1.039 20.529 ;
     RECT  0.967 21.546 1.039 21.564 ;
     RECT  0.383 14.184 1.147 14.508 ;
     RECT  0.103 38.286 1.147 38.304 ;
     RECT  0.535 43.614 1.147 48.924 ;
     RECT  1.147 38.286 1.183 38.574 ;
     RECT  1.147 53.406 1.183 53.424 ;
     RECT  1.147 43.614 1.247 49.068 ;
     RECT  1.183 37.944 1.399 38.574 ;
     RECT  1.399 28.764 1.471 28.782 ;
     RECT  1.399 37.944 1.471 39.042 ;
     RECT  1.039 20.511 1.579 21.564 ;
     RECT  0.895 36.324 1.651 36.342 ;
     RECT  1.651 36.324 1.687 36.954 ;
     RECT  1.579 20.511 1.759 22.068 ;
     RECT  1.687 36.126 1.759 36.954 ;
     RECT  0.139 50.634 1.939 51.264 ;
     RECT  1.543 33.966 1.975 33.984 ;
     RECT  1.759 35.856 1.975 36.954 ;
     RECT  1.471 37.944 1.975 39.114 ;
     RECT  1.471 28.296 2.011 28.782 ;
     RECT  0.931 29.646 2.047 31.284 ;
     RECT  1.795 35.046 2.083 35.064 ;
     RECT  1.975 35.856 2.083 39.114 ;
     RECT  0.535 17.226 2.155 18.144 ;
     RECT  1.687 19.656 2.155 19.674 ;
     RECT  1.759 20.466 2.155 22.068 ;
     RECT  0.535 7.398 2.16 7.416 ;
     RECT  0.167 9.756 2.16 9.774 ;
     RECT  0.383 11.412 2.16 11.43 ;
     RECT  0.239 13.176 2.16 13.194 ;
     RECT  1.147 14.184 2.16 14.544 ;
     RECT  2.155 17.118 2.16 18.144 ;
     RECT  2.155 19.656 2.16 22.068 ;
     RECT  0.347 22.824 2.16 22.842 ;
     RECT  2.155 26.334 2.16 26.352 ;
     RECT  0.103 27.216 2.16 27.234 ;
     RECT  2.011 28.296 2.16 28.854 ;
     RECT  2.047 29.646 2.16 31.788 ;
     RECT  1.975 33.624 2.16 33.984 ;
     RECT  2.083 35.046 2.16 39.114 ;
     RECT  1.435 40.104 2.16 40.122 ;
     RECT  0.535 41.526 2.16 42.084 ;
     RECT  1.247 43.614 2.16 48.996 ;
     RECT  1.939 50.634 2.16 52.002 ;
     RECT  1.183 53.064 2.16 53.424 ;
     RECT  2.16 2.151 3.775 62.649 ;
     RECT  3.775 1.962 5.351 62.649 ;
     RECT  5.351 2.034 8.059 62.649 ;
     RECT  8.059 1.962 9.815 62.649 ;
     RECT  9.815 2.106 10.543 62.649 ;
     RECT  10.543 2.07 10.831 62.649 ;
     RECT  10.831 1.881 12.695 62.649 ;
     RECT  12.695 1.926 14.323 62.649 ;
     RECT  14.323 1.8 14.575 62.649 ;
     RECT  14.575 1.8 14.819 62.694 ;
     RECT  14.819 1.926 15.143 62.694 ;
     RECT  15.143 2.106 15.899 62.694 ;
     RECT  15.899 2.106 16.115 62.649 ;
     RECT  16.115 2.151 19.615 62.649 ;
     RECT  19.615 2.106 21.047 62.649 ;
     RECT  21.047 2.151 21.991 62.649 ;
     RECT  21.991 2.151 25.619 62.694 ;
     RECT  25.619 2.151 31.027 62.649 ;
     RECT  31.027 2.106 32.035 62.649 ;
     RECT  32.035 1.962 33.215 62.649 ;
     RECT  33.215 2.034 33.647 62.649 ;
     RECT  33.647 2.106 33.863 62.649 ;
     RECT  33.863 2.151 36.355 62.649 ;
     RECT  36.355 2.106 36.571 62.649 ;
     RECT  36.571 2.034 38.255 62.649 ;
     RECT  38.255 2.106 39.595 62.649 ;
     RECT  39.595 1.962 46.643 62.649 ;
     RECT  46.643 2.034 46.751 62.649 ;
     RECT  46.751 2.106 47.831 62.649 ;
     RECT  47.831 2.151 48.919 62.649 ;
     RECT  48.919 2.106 49.423 62.649 ;
     RECT  49.423 2.034 49.603 62.649 ;
     RECT  49.603 1.422 49.675 62.649 ;
     RECT  44.995 0.036 49.883 0.054 ;
     RECT  49.675 0.846 54.751 62.649 ;
     RECT  51.151 0.036 55.211 0.054 ;
     RECT  54.751 0.846 57.155 62.694 ;
     RECT  57.155 1.422 57.947 62.694 ;
     RECT  57.947 1.422 58.703 62.649 ;
     RECT  58.703 1.962 59.351 62.649 ;
     RECT  59.351 2.034 59.459 62.649 ;
     RECT  59.459 2.151 62.64 62.649 ;
     RECT  62.64 20.826 62.663 21.924 ;
     RECT  62.64 34.506 62.699 39.474 ;
     RECT  62.64 40.986 62.699 41.544 ;
     RECT  62.64 6.696 62.735 14.814 ;
     RECT  62.699 34.506 62.735 39.204 ;
     RECT  62.64 29.466 62.987 29.754 ;
     RECT  62.64 26.226 63.203 26.856 ;
     RECT  62.64 42.426 63.239 53.352 ;
     RECT  62.735 6.822 63.275 14.814 ;
     RECT  63.203 26.226 63.275 26.244 ;
     RECT  62.735 36.216 63.275 39.204 ;
     RECT  63.239 42.426 63.275 46.944 ;
     RECT  63.239 47.934 63.275 53.352 ;
     RECT  63.275 7.776 63.311 14.814 ;
     RECT  62.64 15.606 63.311 20.034 ;
     RECT  63.275 36.594 63.311 39.204 ;
     RECT  63.311 16.38 63.563 20.034 ;
     RECT  62.64 55.386 63.563 55.674 ;
     RECT  62.663 20.826 63.599 21.114 ;
     RECT  62.64 54.414 63.599 54.432 ;
     RECT  63.563 55.656 63.635 55.674 ;
     RECT  63.275 53.334 63.671 53.352 ;
     RECT  63.275 42.426 63.779 46.494 ;
     RECT  63.311 7.866 63.815 14.814 ;
     RECT  63.563 16.38 63.815 19.872 ;
     RECT  62.735 34.506 63.815 34.758 ;
     RECT  63.311 36.63 63.815 39.204 ;
     RECT  63.779 42.426 63.815 44.064 ;
     RECT  63.275 47.934 63.815 52.344 ;
     RECT  63.275 6.822 63.851 6.84 ;
     RECT  63.815 7.866 63.851 13.734 ;
     RECT  63.815 16.416 63.851 19.872 ;
     RECT  63.815 34.506 63.851 34.65 ;
     RECT  63.815 36.63 63.851 38.304 ;
     RECT  63.815 39.186 63.851 39.204 ;
     RECT  62.699 41.526 63.851 41.544 ;
     RECT  63.815 42.606 63.851 44.064 ;
     RECT  63.779 44.856 63.851 45.522 ;
     RECT  63.779 46.314 63.851 46.494 ;
     RECT  63.815 47.934 63.851 48.384 ;
     RECT  63.815 49.356 63.851 52.344 ;
     RECT  63.851 7.938 63.887 9.378 ;
     RECT  63.851 16.956 63.887 17.604 ;
     RECT  63.851 34.632 63.887 34.65 ;
     RECT  63.851 42.606 63.887 42.624 ;
     RECT  63.851 43.776 63.887 43.794 ;
     RECT  63.851 46.314 63.887 46.332 ;
     RECT  63.851 47.934 63.887 47.988 ;
     RECT  63.887 17.082 63.923 17.604 ;
     RECT  62.663 21.906 64.607 21.924 ;
     RECT  62.64 28.422 64.607 28.674 ;
     RECT  63.851 49.356 64.615 49.644 ;
     RECT  63.851 10.476 64.679 11.538 ;
     RECT  63.815 14.526 64.679 14.814 ;
     RECT  63.851 19.476 64.679 19.872 ;
     RECT  63.851 37.746 64.679 38.304 ;
     RECT  63.851 45.306 64.679 45.522 ;
     RECT  63.851 51.066 64.679 52.344 ;
     RECT  64.615 26.568 64.687 26.586 ;
     RECT  63.887 47.97 64.687 47.988 ;
     RECT  63.887 8.784 64.715 9.378 ;
     RECT  64.679 10.476 64.715 10.494 ;
     RECT  64.679 11.52 64.715 11.538 ;
     RECT  63.851 13.716 64.715 13.734 ;
     RECT  63.311 15.606 64.715 15.624 ;
     RECT  63.923 17.586 64.715 17.604 ;
     RECT  64.679 19.476 64.715 19.494 ;
     RECT  64.687 26.181 64.715 26.586 ;
     RECT  63.851 36.63 64.715 36.648 ;
     RECT  64.679 37.746 64.715 38.124 ;
     RECT  64.679 45.504 64.715 45.522 ;
     RECT  64.687 47.592 64.715 47.988 ;
     RECT  64.615 49.356 64.715 50.004 ;
     RECT  64.679 51.786 64.715 52.344 ;
     RECT  62.987 29.466 64.751 29.484 ;
     RECT  64.579 18.702 64.787 18.72 ;
     RECT  63.599 21.096 64.787 21.114 ;
     RECT  64.715 26.181 64.787 26.199 ;
     RECT  64.607 28.656 64.787 28.674 ;
     RECT  64.715 47.592 64.787 47.61 ;
     RECT  64.715 52.326 64.787 52.344 ;
    LAYER M3 ;
     RECT  32.148 0.043 32.166 0.091 ;
     RECT  37.944 0.043 37.962 0.091 ;
     RECT  49.86 0.031 49.878 0.091 ;
     RECT  51.156 0.031 51.174 0.091 ;
     RECT  55.188 0.031 55.206 0.091 ;
     RECT  45 0.031 45.018 0.125 ;
     RECT  51.156 0.091 52.11 0.125 ;
     RECT  8.28 0.091 8.298 0.139 ;
     RECT  9.252 0.091 9.882 0.139 ;
     RECT  12.528 0.091 12.546 0.139 ;
     RECT  20.844 0.091 21.834 0.139 ;
     RECT  24.516 0.091 24.858 0.139 ;
     RECT  25.632 0.091 28.962 0.139 ;
     RECT  32.148 0.091 32.742 0.139 ;
     RECT  35.388 0.091 35.406 0.139 ;
     RECT  54.648 0.091 55.206 0.139 ;
     RECT  36.288 0.091 37.962 0.173 ;
     RECT  32.148 0.139 32.886 0.187 ;
     RECT  41.976 0.091 42.21 0.221 ;
     RECT  22.572 0.091 23.778 0.475 ;
     RECT  24.516 0.139 28.962 0.475 ;
     RECT  35.388 0.139 35.478 0.475 ;
     RECT  36.288 0.173 37.494 0.475 ;
     RECT  46.512 0.091 46.53 0.475 ;
     RECT  7.416 0.475 7.434 0.523 ;
     RECT  31.86 0.187 32.886 0.523 ;
     RECT  46.044 0.475 46.53 0.523 ;
     RECT  3.924 0.091 4.446 0.571 ;
     RECT  5.652 0.091 5.67 0.571 ;
     RECT  7.344 0.523 7.434 0.571 ;
     RECT  8.28 0.139 9.882 0.571 ;
     RECT  12.528 0.139 12.978 0.571 ;
     RECT  15.408 0.091 15.426 0.571 ;
     RECT  19.836 0.091 19.854 0.571 ;
     RECT  20.7 0.139 21.834 0.571 ;
     RECT  22.572 0.475 28.962 0.571 ;
     RECT  31.86 0.523 33.066 0.571 ;
     RECT  34.596 0.091 34.614 0.571 ;
     RECT  35.388 0.475 37.494 0.571 ;
     RECT  39.708 0.091 39.942 0.571 ;
     RECT  41.976 0.221 42.102 0.571 ;
     RECT  45.396 0.523 46.53 0.571 ;
     RECT  49.464 0.091 49.878 0.571 ;
     RECT  51.372 0.125 52.11 0.571 ;
     RECT  54.648 0.139 55.242 0.571 ;
     RECT  3.924 0.571 5.67 0.619 ;
     RECT  54.648 0.571 55.386 0.619 ;
     RECT  15.408 0.571 15.606 1.099 ;
     RECT  34.596 0.571 37.494 1.099 ;
     RECT  38.232 0.571 38.25 1.099 ;
     RECT  45.396 0.571 46.89 1.099 ;
     RECT  54.396 0.619 55.386 1.099 ;
     RECT  3.924 0.619 6.282 1.147 ;
     RECT  7.056 0.571 9.882 1.147 ;
     RECT  12.204 0.571 12.978 1.147 ;
     RECT  14.256 0.187 14.274 1.147 ;
     RECT  42.84 0.523 42.858 1.147 ;
     RECT  51.372 0.571 52.722 1.147 ;
     RECT  54.396 1.099 55.494 1.147 ;
     RECT  45.396 1.099 47.106 1.579 ;
     RECT  31.86 0.571 33.858 1.675 ;
     RECT  34.596 1.099 38.25 1.675 ;
     RECT  3.924 1.147 9.882 1.723 ;
     RECT  12.204 1.147 13.086 1.723 ;
     RECT  14.22 1.147 14.454 1.723 ;
     RECT  15.192 1.099 15.606 1.723 ;
     RECT  19.836 0.571 28.962 1.723 ;
     RECT  39.096 0.571 39.942 1.723 ;
     RECT  41.616 0.571 42.102 1.723 ;
     RECT  42.84 1.147 42.966 1.723 ;
     RECT  45.396 1.579 47.754 1.723 ;
     RECT  49.464 0.571 50.598 1.723 ;
     RECT  51.372 1.147 55.494 1.723 ;
     RECT  56.304 1.147 56.322 1.723 ;
     RECT  57.132 0.841 57.15 1.723 ;
     RECT  58.68 1.417 58.698 1.723 ;
     RECT  3.924 1.723 9.99 1.771 ;
     RECT  10.944 1.723 15.966 1.771 ;
     RECT  39.096 1.723 43.146 1.771 ;
     RECT  45.252 1.723 57.15 1.771 ;
     RECT  39.096 1.771 44.262 1.819 ;
     RECT  58.68 1.723 59.238 1.819 ;
     RECT  45.252 1.771 57.438 1.867 ;
     RECT  3.924 1.771 15.966 1.957 ;
     RECT  58.68 1.819 59.274 1.957 ;
     RECT  45.252 1.867 57.726 2.011 ;
     RECT  58.68 1.957 59.346 2.011 ;
     RECT  39.096 1.819 44.442 2.029 ;
     RECT  45.252 2.011 59.346 2.029 ;
     RECT  3.78 1.957 15.966 2.101 ;
     RECT  19.836 1.723 29.07 2.101 ;
     RECT  31.86 1.675 38.25 2.101 ;
     RECT  39.096 2.029 59.454 2.101 ;
     RECT  19.62 2.101 29.07 2.143 ;
     RECT  19.62 2.143 29.505 2.191 ;
     RECT  31.86 2.101 59.454 2.191 ;
     RECT  18.615 2.143 18.705 2.227 ;
     RECT  31.032 2.101 31.05 2.227 ;
     RECT  31.86 2.191 60.066 2.227 ;
     RECT  18.072 2.227 18.705 2.263 ;
     RECT  19.62 2.191 30.078 2.263 ;
     RECT  31.032 2.227 60.066 2.263 ;
     RECT  31.032 2.263 60.462 2.299 ;
     RECT  30.816 2.299 60.462 2.335 ;
     RECT  18.072 2.263 30.078 2.371 ;
     RECT  30.816 2.335 60.822 2.371 ;
     RECT  2.415 2.143 2.505 2.413 ;
     RECT  61.815 2.143 61.905 2.413 ;
     RECT  3.78 2.101 16.11 2.533 ;
     RECT  3.6 2.533 16.11 2.569 ;
     RECT  3.564 2.569 16.434 2.605 ;
     RECT  3.564 2.605 16.794 2.641 ;
     RECT  18.072 2.371 60.822 2.641 ;
     RECT  3.564 2.641 60.822 3.181 ;
     RECT  61.815 2.413 62.097 3.181 ;
     RECT  2.415 2.413 2.697 3.919 ;
     RECT  3.564 3.181 62.097 3.919 ;
     RECT  2.415 3.919 62.097 4.253 ;
     RECT  2.415 4.253 61.038 5.419 ;
     RECT  2.415 5.419 61.074 5.503 ;
     RECT  61.815 4.253 62.097 5.503 ;
     RECT  2.415 5.503 62.097 5.729 ;
     RECT  2.415 5.729 60.894 5.801 ;
     RECT  2.415 5.801 60.786 5.873 ;
     RECT  61.815 5.729 62.097 6.691 ;
     RECT  2.415 5.873 60.714 6.763 ;
     RECT  61.524 6.691 62.73 6.763 ;
     RECT  2.415 6.763 62.73 7.099 ;
     RECT  1.98 7.099 62.73 7.147 ;
     RECT  63.828 6.817 63.846 7.147 ;
     RECT  1.98 7.147 63.846 7.277 ;
     RECT  2.268 7.277 63.846 7.349 ;
     RECT  2.268 7.349 62.334 7.565 ;
     RECT  0.54 7.393 0.558 7.757 ;
     RECT  63.18 7.349 63.846 7.933 ;
     RECT  64.692 7.723 64.71 8.491 ;
     RECT  0.972 8.395 0.99 8.539 ;
     RECT  0.18 8.539 0.198 8.587 ;
     RECT  0.972 8.539 1.566 8.635 ;
     RECT  2.304 7.565 62.334 8.635 ;
     RECT  0.108 8.587 0.198 8.683 ;
     RECT  0.972 8.635 62.334 8.683 ;
     RECT  0.108 8.683 62.334 9.005 ;
     RECT  64.656 8.491 64.71 9.149 ;
     RECT  0.972 9.005 62.334 9.283 ;
     RECT  0.972 9.283 62.37 9.319 ;
     RECT  63.18 7.933 63.882 9.319 ;
     RECT  64.692 9.149 64.71 9.383 ;
     RECT  0.972 9.319 63.882 9.389 ;
     RECT  63.18 9.389 63.882 9.485 ;
     RECT  0.108 9.005 0.162 9.739 ;
     RECT  0.972 9.389 62.37 9.739 ;
     RECT  0.108 9.739 62.37 10.201 ;
     RECT  0.108 10.201 62.442 10.291 ;
     RECT  64.692 10.123 64.71 10.315 ;
     RECT  64.656 10.315 64.71 10.411 ;
     RECT  0.036 10.291 62.442 10.507 ;
     RECT  63.18 9.485 63.846 10.507 ;
     RECT  0.036 10.507 63.846 10.589 ;
     RECT  64.62 10.411 64.71 10.603 ;
     RECT  64.584 10.603 64.71 11.237 ;
     RECT  0.036 10.589 63.81 11.755 ;
     RECT  0.036 11.755 63.846 12.119 ;
     RECT  64.692 11.237 64.71 12.619 ;
     RECT  0.036 12.119 32.67 12.901 ;
     RECT  33.408 12.119 63.846 12.901 ;
     RECT  0.036 12.901 63.846 12.929 ;
     RECT  0.036 12.929 62.658 13.019 ;
     RECT  17.172 13.019 62.658 13.163 ;
     RECT  63.756 12.929 63.846 13.289 ;
     RECT  63.756 13.289 63.81 13.559 ;
     RECT  64.656 12.619 64.71 13.739 ;
     RECT  63.792 13.559 63.81 13.829 ;
     RECT  0.036 13.019 16.434 13.873 ;
     RECT  0.036 13.873 16.47 14.071 ;
     RECT  17.208 13.163 62.658 14.071 ;
     RECT  0.036 14.071 62.658 14.203 ;
     RECT  0.036 14.203 62.694 14.909 ;
     RECT  64.656 13.739 64.674 15.601 ;
     RECT  0.072 14.909 62.694 16.141 ;
     RECT  63.828 16.075 63.846 16.141 ;
     RECT  64.656 15.601 64.71 16.301 ;
     RECT  0.072 16.141 63.846 16.771 ;
     RECT  0.036 16.771 63.846 16.843 ;
     RECT  0.036 16.843 63.882 16.939 ;
     RECT  0.036 16.939 63.918 17.105 ;
     RECT  64.656 16.301 64.674 17.131 ;
     RECT  64.656 17.131 64.71 17.227 ;
     RECT  64.62 17.227 64.71 17.405 ;
     RECT  0.036 17.105 63.882 17.645 ;
     RECT  64.692 17.405 64.71 18.379 ;
     RECT  64.656 18.379 64.71 18.475 ;
     RECT  64.62 18.475 64.71 18.667 ;
     RECT  64.584 18.667 64.71 18.697 ;
     RECT  0.036 17.645 63.846 19.139 ;
     RECT  63.54 19.139 63.846 19.229 ;
     RECT  0.036 19.139 62.658 19.643 ;
     RECT  63.54 19.229 63.594 20.039 ;
     RECT  63.576 20.039 63.594 20.849 ;
     RECT  64.584 18.697 64.782 21.119 ;
     RECT  0.072 19.643 62.658 21.191 ;
     RECT  64.584 21.119 64.602 21.929 ;
     RECT  0.072 21.191 62.622 22.747 ;
     RECT  0.036 22.747 62.622 26.059 ;
     RECT  64.692 26.155 64.71 26.176 ;
     RECT  0.036 26.059 63.27 26.249 ;
     RECT  64.692 26.176 64.782 26.251 ;
     RECT  64.656 26.251 64.782 26.443 ;
     RECT  0.036 26.249 63.198 26.861 ;
     RECT  0.036 26.861 62.982 27.239 ;
     RECT  64.584 26.443 64.782 28.445 ;
     RECT  64.728 28.445 64.782 28.679 ;
     RECT  64.728 28.679 64.746 29.489 ;
     RECT  0.036 27.239 0.09 29.669 ;
     RECT  0.828 27.239 62.982 29.759 ;
     RECT  0.828 29.759 62.262 29.867 ;
     RECT  0.072 29.669 0.09 31.019 ;
     RECT  0.864 29.867 62.262 31.289 ;
     RECT  0.9 31.289 62.262 32.071 ;
     RECT  0.9 32.071 62.442 32.333 ;
     RECT  0.9 32.333 62.262 32.729 ;
     RECT  0.9 32.729 24.714 33.583 ;
     RECT  25.452 32.729 62.262 33.583 ;
     RECT  0.9 33.583 62.262 33.611 ;
     RECT  0.9 33.611 62.097 34.411 ;
     RECT  0.144 34.363 0.162 34.507 ;
     RECT  0.9 34.411 62.298 34.507 ;
     RECT  63.828 34.501 63.846 34.627 ;
     RECT  0.144 34.507 62.298 34.691 ;
     RECT  0.144 34.691 60.822 34.733 ;
     RECT  63.828 34.627 63.882 34.735 ;
     RECT  0.108 35.08 0.126 35.086 ;
     RECT  63.792 34.735 63.882 35.309 ;
     RECT  61.596 34.691 62.298 35.311 ;
     RECT  0.9 34.733 60.822 35.473 ;
     RECT  61.596 35.311 62.73 35.473 ;
     RECT  63.792 35.309 63.846 35.501 ;
     RECT  63.792 35.501 63.81 36.043 ;
     RECT  0.9 35.473 62.73 36.139 ;
     RECT  63.756 36.043 63.81 36.139 ;
     RECT  0.9 36.139 63.81 36.235 ;
     RECT  0.9 36.235 63.846 36.347 ;
     RECT  1.152 36.347 63.846 36.509 ;
     RECT  1.152 36.509 21.186 36.815 ;
     RECT  21.96 36.509 63.846 36.923 ;
     RECT  17.136 36.815 21.186 37.391 ;
     RECT  17.532 37.391 21.186 37.435 ;
     RECT  21.96 36.923 60.822 37.435 ;
     RECT  64.692 36.331 64.71 37.483 ;
     RECT  64.656 37.483 64.71 37.675 ;
     RECT  17.532 37.435 60.822 37.705 ;
     RECT  61.596 36.923 63.846 37.705 ;
     RECT  1.152 36.815 16.362 37.975 ;
     RECT  1.152 37.975 16.47 38.039 ;
     RECT  64.62 37.675 64.71 38.129 ;
     RECT  64.62 38.129 64.674 38.141 ;
     RECT  2.232 38.039 16.47 38.173 ;
     RECT  17.532 37.705 63.846 38.173 ;
     RECT  2.232 38.173 63.846 38.189 ;
     RECT  0.036 35.086 0.126 38.309 ;
     RECT  64.656 38.141 64.674 38.309 ;
     RECT  54.144 38.189 63.846 38.477 ;
     RECT  54.18 38.477 63.846 38.507 ;
     RECT  2.232 38.189 53.298 38.543 ;
     RECT  1.152 38.039 1.494 38.579 ;
     RECT  17.496 38.543 53.298 38.669 ;
     RECT  42.732 38.669 53.298 38.741 ;
     RECT  52.236 38.741 53.298 38.813 ;
     RECT  2.232 38.543 16.614 38.909 ;
     RECT  63.792 38.507 63.846 38.939 ;
     RECT  1.404 38.579 1.494 39.047 ;
     RECT  17.496 38.669 41.958 39.083 ;
     RECT  1.44 39.047 1.494 39.119 ;
     RECT  63.828 38.939 63.846 39.209 ;
     RECT  52.308 38.813 53.298 39.245 ;
     RECT  52.308 39.245 53.19 39.317 ;
     RECT  54.18 38.507 62.694 39.403 ;
     RECT  17.532 39.083 41.958 39.479 ;
     RECT  54.144 39.403 62.694 39.479 ;
     RECT  26.244 39.479 41.958 39.487 ;
     RECT  42.732 38.741 51.462 39.487 ;
     RECT  52.308 39.317 53.118 39.631 ;
     RECT  54.144 39.479 62.514 39.659 ;
     RECT  54.144 39.659 62.097 39.749 ;
     RECT  26.244 39.487 51.462 39.829 ;
     RECT  52.236 39.631 53.118 39.829 ;
     RECT  2.304 38.909 16.614 39.865 ;
     RECT  2.304 39.865 16.722 39.901 ;
     RECT  17.532 39.479 25.434 39.901 ;
     RECT  1.44 39.119 1.458 40.127 ;
     RECT  26.244 39.829 53.118 40.289 ;
     RECT  2.304 39.901 25.434 40.363 ;
     RECT  26.244 40.289 51.297 40.363 ;
     RECT  2.304 40.363 51.297 40.403 ;
     RECT  54.18 39.749 62.097 40.405 ;
     RECT  26.244 40.403 51.297 40.433 ;
     RECT  39.636 40.433 51.297 40.469 ;
     RECT  26.244 40.433 38.862 40.559 ;
     RECT  39.672 40.469 51.297 40.559 ;
     RECT  54.18 40.405 62.442 40.667 ;
     RECT  52.128 40.289 53.118 40.711 ;
     RECT  61.776 40.667 62.442 40.711 ;
     RECT  54.18 40.667 61.038 40.739 ;
     RECT  54.18 40.739 60.822 40.829 ;
     RECT  61.776 40.711 62.514 40.981 ;
     RECT  43.596 40.559 51.297 41.035 ;
     RECT  52.128 40.711 53.154 41.035 ;
     RECT  54.18 40.829 60.714 41.071 ;
     RECT  26.316 40.559 38.862 41.215 ;
     RECT  39.672 40.559 42.75 41.215 ;
     RECT  43.596 41.035 53.154 41.215 ;
     RECT  54.108 41.071 60.714 41.215 ;
     RECT  2.304 40.403 25.47 41.341 ;
     RECT  26.316 41.215 42.75 41.341 ;
     RECT  2.304 41.341 42.75 41.377 ;
     RECT  43.596 41.215 60.714 41.377 ;
     RECT  2.304 41.377 60.714 41.477 ;
     RECT  0.036 38.309 0.054 41.521 ;
     RECT  2.304 41.477 30.546 41.645 ;
     RECT  31.284 41.477 60.714 41.647 ;
     RECT  31.284 41.647 60.822 41.683 ;
     RECT  61.776 40.981 62.694 41.683 ;
     RECT  21.096 41.645 30.546 41.783 ;
     RECT  0.036 41.521 0.126 41.803 ;
     RECT  0.036 41.803 0.342 41.819 ;
     RECT  0.108 41.819 0.342 41.989 ;
     RECT  0.108 41.989 0.522 42.061 ;
     RECT  31.284 41.683 62.694 42.283 ;
     RECT  63.828 41.521 63.846 42.283 ;
     RECT  0.108 42.061 0.558 42.413 ;
     RECT  1.404 42.043 1.422 42.475 ;
     RECT  2.304 41.645 20.286 42.475 ;
     RECT  31.284 42.283 63.846 42.509 ;
     RECT  1.404 42.475 20.286 42.565 ;
     RECT  63.252 42.509 63.846 42.601 ;
     RECT  0.108 42.413 0.234 42.605 ;
     RECT  21.204 41.783 30.546 42.715 ;
     RECT  31.284 42.509 62.514 42.715 ;
     RECT  63.252 42.601 63.882 42.797 ;
     RECT  1.404 42.565 20.466 43.105 ;
     RECT  21.204 42.715 62.514 43.105 ;
     RECT  1.404 43.105 62.514 43.243 ;
     RECT  63.252 42.797 63.846 43.243 ;
     RECT  0.144 42.605 0.234 43.609 ;
     RECT  0.144 43.609 0.522 43.613 ;
     RECT  0.324 43.613 0.522 43.681 ;
     RECT  1.404 43.243 63.846 43.771 ;
     RECT  0.324 43.681 0.558 44.141 ;
     RECT  1.404 43.771 63.882 44.177 ;
     RECT  1.98 44.177 63.882 44.587 ;
     RECT  64.692 43.915 64.71 44.587 ;
     RECT  1.98 44.587 64.71 44.717 ;
     RECT  1.98 44.717 63.846 44.951 ;
     RECT  0.468 44.141 0.558 45.229 ;
     RECT  1.98 44.951 47.826 45.329 ;
     RECT  64.656 44.717 64.71 45.527 ;
     RECT  0.36 45.229 0.558 45.661 ;
     RECT  0.36 45.661 1.17 45.797 ;
     RECT  48.564 44.951 63.846 45.931 ;
     RECT  2.232 45.329 47.826 45.965 ;
     RECT  2.304 45.965 47.826 46.027 ;
     RECT  48.564 45.931 63.882 46.027 ;
     RECT  2.304 46.027 63.882 46.067 ;
     RECT  0.36 45.797 0.558 46.111 ;
     RECT  0.108 46.111 0.558 46.157 ;
     RECT  2.415 46.067 63.882 46.337 ;
     RECT  0.108 46.157 0.522 46.349 ;
     RECT  2.415 46.337 63.846 46.499 ;
     RECT  2.415 46.499 63.81 46.679 ;
     RECT  0.108 46.349 0.486 46.733 ;
     RECT  0.108 46.733 0.162 46.925 ;
     RECT  2.415 46.679 41.922 46.987 ;
     RECT  2.304 46.987 41.922 47.461 ;
     RECT  2.268 47.461 41.922 47.501 ;
     RECT  64.656 45.527 64.674 47.563 ;
     RECT  2.304 47.501 41.922 47.587 ;
     RECT  42.768 46.679 63.81 47.587 ;
     RECT  64.656 47.563 64.71 47.587 ;
     RECT  0.108 46.925 0.126 47.731 ;
     RECT  0.108 47.731 0.162 47.899 ;
     RECT  2.304 47.587 63.81 47.929 ;
     RECT  0.108 47.899 0.234 48.043 ;
     RECT  2.304 47.929 63.882 48.269 ;
     RECT  2.304 48.269 63.846 48.379 ;
     RECT  2.196 48.379 63.846 48.461 ;
     RECT  2.196 48.461 43.146 48.533 ;
     RECT  0.108 48.043 0.342 48.739 ;
     RECT  0.108 48.739 0.558 48.973 ;
     RECT  0.108 48.973 1.17 49.003 ;
     RECT  43.956 48.461 63.846 49.037 ;
     RECT  0.108 49.003 1.242 49.073 ;
     RECT  44.604 49.037 63.846 49.073 ;
     RECT  0.108 49.073 0.558 49.325 ;
     RECT  2.196 48.533 43.038 49.351 ;
     RECT  0.18 49.325 0.558 49.421 ;
     RECT  2.196 49.351 43.398 49.421 ;
     RECT  44.856 49.073 63.846 49.855 ;
     RECT  44.532 49.855 63.846 49.981 ;
     RECT  64.656 47.587 64.782 49.981 ;
     RECT  64.62 49.981 64.782 50.045 ;
     RECT  0.18 49.421 0.198 50.155 ;
     RECT  2.196 49.421 43.038 50.161 ;
     RECT  43.848 49.981 63.846 50.161 ;
     RECT  0.144 50.155 0.198 50.251 ;
     RECT  0.144 50.251 0.234 50.429 ;
     RECT  2.196 50.161 63.846 50.443 ;
     RECT  1.152 50.731 1.17 51.019 ;
     RECT  1.944 50.443 63.846 51.019 ;
     RECT  64.656 50.045 64.782 51.019 ;
     RECT  1.944 51.019 64.782 51.149 ;
     RECT  0.108 50.629 0.126 51.169 ;
     RECT  0.108 51.169 0.198 51.245 ;
     RECT  0.144 51.245 0.198 51.437 ;
     RECT  1.152 51.019 1.206 51.499 ;
     RECT  1.944 51.149 63.846 51.499 ;
     RECT  1.152 51.499 63.846 51.677 ;
     RECT  0.18 51.437 0.198 51.725 ;
     RECT  64.692 51.149 64.782 51.809 ;
     RECT  1.944 51.677 63.846 51.899 ;
     RECT  1.944 51.899 63.666 52.007 ;
     RECT  64.764 51.809 64.782 52.349 ;
     RECT  2.304 52.007 63.666 52.445 ;
     RECT  8.82 52.445 63.666 52.475 ;
     RECT  2.304 52.445 8.097 52.709 ;
     RECT  46.908 52.475 63.666 52.709 ;
     RECT  2.34 52.709 8.097 52.853 ;
     RECT  60.768 52.709 63.666 52.889 ;
     RECT  5.076 52.853 8.097 52.979 ;
     RECT  1.152 51.677 1.206 53.087 ;
     RECT  5.508 52.979 8.097 53.087 ;
     RECT  5.652 53.087 8.097 53.221 ;
     RECT  8.82 52.475 46.17 53.221 ;
     RECT  46.908 52.709 59.814 53.249 ;
     RECT  48.924 53.249 59.814 53.357 ;
     RECT  63.54 52.889 63.666 53.357 ;
     RECT  5.652 53.221 46.17 53.401 ;
     RECT  46.908 53.249 48.078 53.401 ;
     RECT  1.152 53.087 1.17 53.429 ;
     RECT  2.34 52.853 4.338 53.527 ;
     RECT  5.652 53.401 48.078 53.555 ;
     RECT  8.964 53.555 48.078 53.591 ;
     RECT  5.652 53.555 8.226 53.597 ;
     RECT  48.996 53.357 59.814 53.635 ;
     RECT  48.996 53.635 59.85 53.671 ;
     RECT  60.768 52.889 62.586 53.671 ;
     RECT  11.844 53.591 48.078 53.789 ;
     RECT  48.996 53.671 62.586 53.789 ;
     RECT  5.976 53.597 8.226 53.825 ;
     RECT  48.996 53.789 62.55 54.059 ;
     RECT  11.844 53.789 46.674 54.095 ;
     RECT  2.304 53.527 4.338 54.103 ;
     RECT  47.484 53.789 48.078 54.103 ;
     RECT  6.264 53.825 8.226 54.167 ;
     RECT  47.484 54.103 48.186 54.211 ;
     RECT  2.304 54.103 4.626 54.329 ;
     RECT  11.844 54.095 46.602 54.329 ;
     RECT  47.484 54.211 48.222 54.329 ;
     RECT  48.996 54.059 62.478 54.329 ;
     RECT  2.34 54.329 4.626 54.481 ;
     RECT  7.74 54.167 8.226 54.481 ;
     RECT  8.964 53.591 10.71 54.481 ;
     RECT  11.844 54.329 46.53 54.481 ;
     RECT  11.52 54.481 46.53 54.509 ;
     RECT  2.34 54.481 5.31 54.599 ;
     RECT  11.52 54.509 45.897 54.599 ;
     RECT  7.74 54.481 10.782 54.607 ;
     RECT  11.52 54.599 41.922 54.607 ;
     RECT  49.14 54.329 62.478 54.608 ;
     RECT  42.66 54.599 45.897 54.635 ;
     RECT  2.415 54.599 5.31 54.715 ;
     RECT  6.264 54.167 6.822 54.715 ;
     RECT  2.415 54.715 6.822 54.955 ;
     RECT  7.74 54.607 41.922 54.955 ;
     RECT  47.484 54.329 48.186 54.985 ;
     RECT  49.176 54.608 62.478 55.139 ;
     RECT  47.448 54.985 48.186 55.291 ;
     RECT  2.415 54.955 41.922 55.319 ;
     RECT  47.448 55.291 48.402 55.381 ;
     RECT  49.176 55.139 62.097 55.381 ;
     RECT  63.54 53.357 63.63 55.409 ;
     RECT  2.415 55.319 29.697 55.445 ;
     RECT  47.448 55.381 62.097 55.453 ;
     RECT  42.696 54.635 45.897 55.489 ;
     RECT  42.696 55.489 46.17 55.651 ;
     RECT  2.415 55.445 3.978 55.679 ;
     RECT  63.612 55.409 63.63 55.679 ;
     RECT  42.696 55.651 46.206 55.715 ;
     RECT  47.304 55.453 62.097 55.751 ;
     RECT  47.304 55.751 60.858 55.795 ;
     RECT  2.415 55.679 3.618 55.859 ;
     RECT  5.112 55.445 29.697 55.859 ;
     RECT  43.056 55.715 46.206 55.921 ;
     RECT  47.16 55.795 60.858 55.921 ;
     RECT  61.776 55.751 62.097 55.949 ;
     RECT  6.372 55.859 29.697 55.955 ;
     RECT  43.056 55.921 60.858 56.021 ;
     RECT  6.624 55.955 29.697 56.065 ;
     RECT  30.6 55.319 41.922 56.065 ;
     RECT  6.624 56.065 41.922 56.101 ;
     RECT  6.624 56.101 42.102 56.219 ;
     RECT  43.056 56.021 60.534 56.219 ;
     RECT  2.415 55.859 3.582 56.255 ;
     RECT  3.492 56.255 3.51 56.291 ;
     RECT  5.112 55.859 5.13 56.291 ;
     RECT  6.768 56.219 6.786 56.363 ;
     RECT  7.596 56.219 42.102 56.363 ;
     RECT  2.415 56.255 2.754 56.399 ;
     RECT  43.056 56.219 60.354 56.443 ;
     RECT  8.964 56.363 42.102 56.497 ;
     RECT  7.596 56.363 8.097 56.525 ;
     RECT  7.668 56.525 8.097 56.759 ;
     RECT  43.02 56.443 60.354 56.795 ;
     RECT  43.02 56.795 44.01 57.029 ;
     RECT  44.964 56.795 60.354 57.181 ;
     RECT  8.964 56.497 42.174 57.209 ;
     RECT  44.964 57.181 60.426 57.443 ;
     RECT  9.36 57.209 42.174 57.569 ;
     RECT  44.964 57.443 60.246 57.577 ;
     RECT  29.016 57.569 42.174 57.595 ;
     RECT  43.02 57.029 43.686 57.595 ;
     RECT  44.928 57.577 60.246 57.605 ;
     RECT  44.928 57.605 47.898 57.713 ;
     RECT  29.016 57.595 43.686 57.749 ;
     RECT  30.564 57.749 43.686 57.839 ;
     RECT  44.928 57.713 46.386 57.839 ;
     RECT  47.16 57.713 47.898 57.839 ;
     RECT  48.744 57.605 60.246 57.839 ;
     RECT  30.564 57.839 42.714 57.875 ;
     RECT  48.744 57.839 49.338 57.875 ;
     RECT  43.524 57.839 43.686 57.911 ;
     RECT  47.664 57.839 47.898 57.911 ;
     RECT  44.928 57.839 45.897 58.019 ;
     RECT  45 58.019 45.897 58.109 ;
     RECT  43.524 57.911 43.614 58.145 ;
     RECT  45.072 58.109 45.897 58.145 ;
     RECT  48.78 57.875 49.338 58.145 ;
     RECT  43.596 58.145 43.614 58.168 ;
     RECT  50.4 57.839 60.246 58.261 ;
     RECT  47.664 57.911 47.682 58.451 ;
     RECT  9.36 57.569 28.206 58.531 ;
     RECT  29.016 57.749 29.754 58.531 ;
     RECT  30.564 57.875 42.642 58.531 ;
     RECT  50.4 58.261 60.282 58.531 ;
     RECT  50.4 58.531 60.534 58.693 ;
     RECT  50.292 58.693 60.534 58.801 ;
     RECT  50.292 58.801 60.642 59.071 ;
     RECT  9.36 58.531 42.642 59.233 ;
     RECT  50.292 59.071 60.75 59.233 ;
     RECT  9.36 59.233 42.858 59.459 ;
     RECT  9.36 59.459 42.822 59.639 ;
     RECT  31.608 59.639 42.822 59.765 ;
     RECT  31.644 59.765 42.822 59.801 ;
     RECT  9.36 59.639 29.79 60.143 ;
     RECT  49.32 58.145 49.338 60.143 ;
     RECT  50.292 59.233 60.894 60.151 ;
     RECT  61.815 55.949 62.097 60.151 ;
     RECT  9.612 60.143 29.79 60.179 ;
     RECT  31.716 59.801 42.822 60.269 ;
     RECT  9.612 60.179 29.697 60.305 ;
     RECT  9.612 60.305 10.278 60.377 ;
     RECT  50.292 60.151 62.097 60.377 ;
     RECT  10.26 60.377 10.278 60.413 ;
     RECT  42.696 60.269 42.714 60.413 ;
     RECT  11.016 60.305 29.697 60.809 ;
     RECT  31.716 60.269 41.958 60.889 ;
     RECT  50.292 60.377 60.894 60.917 ;
     RECT  30.564 59.639 30.582 61.079 ;
     RECT  11.232 60.809 29.697 61.151 ;
     RECT  11.268 61.151 29.697 61.223 ;
     RECT  31.644 60.889 41.958 61.231 ;
     RECT  11.7 61.223 29.697 61.385 ;
     RECT  31.572 61.231 41.958 61.385 ;
     RECT  31.572 61.385 41.85 61.457 ;
     RECT  11.7 61.385 28.026 61.619 ;
     RECT  50.292 60.917 51.297 61.619 ;
     RECT  52.236 60.917 60.894 61.619 ;
     RECT  31.572 61.457 41.562 61.655 ;
     RECT  12.024 61.619 28.026 61.661 ;
     RECT  27.072 61.661 28.026 61.799 ;
     RECT  27.072 61.799 27.702 61.925 ;
     RECT  31.572 61.655 41.526 61.925 ;
     RECT  52.056 61.771 52.074 61.925 ;
     RECT  52.848 61.619 60.894 62.041 ;
     RECT  12.024 61.661 26.226 62.195 ;
     RECT  30.672 61.231 30.69 62.195 ;
     RECT  27.684 61.925 27.702 62.339 ;
     RECT  31.608 61.925 41.202 62.339 ;
     RECT  31.608 62.339 38.898 62.381 ;
     RECT  2.415 56.399 2.697 62.387 ;
     RECT  7.815 56.759 8.097 62.387 ;
     RECT  29.415 61.385 29.697 62.387 ;
     RECT  39.708 62.339 41.202 62.387 ;
     RECT  45.615 58.145 45.897 62.387 ;
     RECT  51.015 61.619 51.297 62.387 ;
     RECT  61.815 60.377 62.097 62.387 ;
     RECT  52.848 62.041 60.966 62.429 ;
     RECT  12.204 62.195 26.226 62.465 ;
     RECT  31.608 62.381 38.862 62.465 ;
     RECT  39.708 62.387 40.374 62.465 ;
     RECT  41.148 62.387 41.202 62.465 ;
     RECT  52.848 62.429 52.866 62.465 ;
     RECT  53.604 62.429 60.966 62.465 ;
     RECT  53.964 62.465 60.966 62.537 ;
     RECT  12.42 62.465 25.614 62.609 ;
     RECT  12.708 62.609 22.734 62.621 ;
     RECT  32.256 62.465 38.862 62.621 ;
     RECT  2.415 62.387 2.505 62.657 ;
     RECT  7.815 62.387 7.905 62.657 ;
     RECT  24.015 62.609 25.614 62.657 ;
     RECT  29.415 62.387 29.505 62.657 ;
     RECT  39.888 62.465 40.305 62.657 ;
     RECT  45.615 62.387 45.705 62.657 ;
     RECT  51.015 62.387 51.105 62.657 ;
     RECT  54.432 62.537 60.966 62.657 ;
     RECT  61.815 62.387 61.905 62.657 ;
     RECT  20.628 62.621 22.23 62.669 ;
     RECT  39.888 62.657 39.906 62.669 ;
     RECT  32.256 62.621 38.79 62.717 ;
     RECT  20.808 62.669 22.23 62.765 ;
     RECT  54.432 62.657 56.286 62.765 ;
     RECT  57.024 62.657 60.966 62.765 ;
     RECT  20.808 62.765 21.402 62.813 ;
     RECT  22.14 62.765 22.23 63.245 ;
     RECT  32.256 62.717 38.646 63.245 ;
     RECT  57.276 62.765 60.966 63.245 ;
     RECT  21.096 62.813 21.402 63.293 ;
     RECT  54.432 62.765 56.25 63.293 ;
     RECT  12.708 62.621 19.854 63.389 ;
     RECT  41.184 62.465 41.202 63.533 ;
     RECT  22.176 63.245 22.23 63.725 ;
     RECT  54.504 63.293 55.962 63.773 ;
     RECT  57.276 63.245 60.858 63.773 ;
     RECT  14.22 63.389 19.854 63.821 ;
     RECT  22.212 63.725 22.23 63.821 ;
     RECT  32.256 63.245 36.774 63.821 ;
     RECT  37.512 63.245 38.646 63.821 ;
     RECT  57.276 63.773 60.75 63.821 ;
     RECT  12.708 63.389 13.446 63.869 ;
     RECT  14.22 63.821 15.75 63.869 ;
     RECT  16.776 63.821 17.226 63.869 ;
     RECT  24.444 62.657 25.614 63.869 ;
     RECT  32.256 63.821 32.274 63.869 ;
     RECT  33.156 63.821 36.558 63.869 ;
     RECT  37.656 63.821 38.646 63.869 ;
     RECT  54.792 63.773 55.962 63.869 ;
     RECT  57.276 63.821 57.978 63.869 ;
     RECT  59.112 63.821 60.678 63.869 ;
     RECT  13.428 63.869 13.446 63.917 ;
     RECT  14.904 63.869 15.75 63.917 ;
     RECT  17.028 63.869 17.226 63.917 ;
     RECT  17.964 63.821 18.81 63.917 ;
     RECT  21.096 63.293 21.114 63.917 ;
     RECT  34.596 63.869 35.658 63.917 ;
     RECT  37.656 63.869 37.746 63.917 ;
     RECT  55.152 63.869 55.962 63.917 ;
     RECT  59.508 63.869 60.174 63.917 ;
     RECT  14.904 63.917 15.246 63.965 ;
     RECT  17.208 63.917 17.226 63.965 ;
     RECT  37.656 63.917 37.674 63.965 ;
     RECT  55.368 63.917 55.674 63.965 ;
     RECT  60.156 63.917 60.174 64.541 ;
     RECT  57.276 63.869 57.726 64.555 ;
     RECT  35.208 63.917 35.262 64.589 ;
     RECT  19.836 63.821 19.854 64.651 ;
     RECT  15.228 63.965 15.246 64.685 ;
     RECT  18.396 63.917 18.414 64.685 ;
     RECT  19.836 64.651 20.43 64.685 ;
     RECT  24.804 63.869 25.614 64.685 ;
     RECT  33.156 63.869 33.678 64.685 ;
     RECT  35.208 64.589 35.226 64.685 ;
     RECT  36.54 63.869 36.558 64.685 ;
     RECT  38.628 63.869 38.646 64.685 ;
     RECT  57.204 64.555 57.726 64.685 ;
     RECT  22.068 64.603 22.086 64.733 ;
     RECT  24.804 64.685 24.894 64.733 ;
     RECT  20.412 64.685 20.43 64.781 ;
     RECT  24.804 64.733 24.822 64.781 ;
     RECT  55.368 63.965 55.386 64.781 ;
     RECT  58.788 64.651 58.806 64.781 ;
    LAYER M4 ;
     RECT  0.06 16.464 0.097 19.464 ;
     RECT  0.06 32.592 0.133 35.592 ;
     RECT  0.06 41.808 0.209 51.72 ;
     RECT  0.209 41.808 0.353 51.624 ;
     RECT  0.353 41.904 1.213 51.624 ;
     RECT  0.06 7.248 1.969 13.32 ;
     RECT  2.329 22.56 2.365 22.584 ;
     RECT  0.097 16.464 2.401 19.56 ;
     RECT  1.969 7.104 2.408 13.32 ;
     RECT  2.365 15.312 2.408 15.336 ;
     RECT  2.401 16.464 2.408 20.136 ;
     RECT  2.365 21.792 2.408 22.584 ;
     RECT  0.06 24.816 2.408 25.608 ;
     RECT  0.133 32.256 2.408 35.592 ;
     RECT  2.221 38.88 2.408 38.904 ;
     RECT  1.213 41.904 2.408 51.672 ;
     RECT  2.408 2.148 2.512 62.652 ;
     RECT  2.512 2.418 2.704 62.382 ;
     RECT  2.704 7.104 2.837 20.52 ;
     RECT  2.704 45.744 2.867 53.352 ;
     RECT  2.867 45.744 2.909 53.256 ;
     RECT  2.704 40.416 2.945 44.568 ;
     RECT  2.704 30.768 2.953 36.552 ;
     RECT  2.704 55.968 2.981 55.992 ;
     RECT  2.953 32.256 3.011 36.552 ;
     RECT  2.704 5.04 3.017 5.688 ;
     RECT  3.011 35.904 3.053 36.552 ;
     RECT  2.953 30.768 3.305 31.128 ;
     RECT  2.704 21.696 3.341 23.832 ;
     RECT  2.909 45.744 3.593 52.728 ;
     RECT  2.837 16.224 3.672 20.52 ;
     RECT  3.341 21.696 3.672 22.632 ;
     RECT  2.704 38.016 3.701 38.712 ;
     RECT  2.704 25.104 3.733 26.664 ;
     RECT  3.672 16.224 3.737 22.632 ;
     RECT  2.837 7.104 3.769 14.856 ;
     RECT  3.733 25.104 3.773 26.808 ;
     RECT  2.704 29.04 3.805 29.064 ;
     RECT  3.053 36.048 3.805 36.552 ;
     RECT  3.773 25.2 3.809 26.808 ;
     RECT  3.737 16.224 3.917 17.448 ;
     RECT  3.836 2.256 3.973 2.28 ;
     RECT  3.973 1.728 3.985 2.28 ;
     RECT  3.805 29.04 3.985 29.16 ;
     RECT  2.945 40.416 3.985 40.44 ;
     RECT  2.945 41.616 3.985 44.568 ;
     RECT  3.017 5.04 4.021 5.064 ;
     RECT  3.769 6.864 4.021 14.856 ;
     RECT  3.985 28.656 4.021 29.16 ;
     RECT  3.781 0.096 4.069 0.12 ;
     RECT  3.985 1.152 4.069 2.28 ;
     RECT  3.805 36.048 4.213 37.032 ;
     RECT  3.809 26.688 4.237 26.808 ;
     RECT  4.069 0.096 4.273 2.28 ;
     RECT  4.237 26.688 4.277 27.24 ;
     RECT  3.011 32.256 4.277 34.776 ;
     RECT  2.704 54.96 4.345 54.984 ;
     RECT  3.985 40.416 4.381 44.568 ;
     RECT  4.381 39.936 4.421 44.712 ;
     RECT  4.273 0.096 4.457 2.808 ;
     RECT  4.021 5.04 4.499 14.856 ;
     RECT  3.917 16.224 4.529 17.256 ;
     RECT  3.701 38.64 4.529 38.712 ;
     RECT  4.457 0.144 4.561 2.808 ;
     RECT  4.345 54.336 4.652 54.984 ;
     RECT  3.593 45.744 4.669 51.672 ;
     RECT  3.593 52.704 4.669 52.728 ;
     RECT  4.652 54.336 4.739 55.416 ;
     RECT  4.529 16.224 4.745 17.208 ;
     RECT  4.499 6.288 4.777 14.856 ;
     RECT  4.561 0.144 4.787 3.432 ;
     RECT  4.421 40.944 4.789 44.712 ;
     RECT  4.745 17.184 4.817 17.208 ;
     RECT  4.213 36.048 4.849 37.608 ;
     RECT  4.529 38.64 4.849 38.664 ;
     RECT  4.277 27.216 4.853 27.24 ;
     RECT  3.737 18.768 4.921 22.632 ;
     RECT  3.341 23.808 4.921 23.832 ;
     RECT  4.777 6.288 4.925 16.008 ;
     RECT  4.921 18.288 4.993 23.832 ;
     RECT  4.789 40.944 5.029 44.76 ;
     RECT  4.669 45.744 5.029 52.728 ;
     RECT  4.925 6.288 5.033 13.656 ;
     RECT  4.021 28.656 5.057 29.688 ;
     RECT  3.305 31.104 5.057 31.128 ;
     RECT  3.809 25.2 5.077 25.608 ;
     RECT  5.033 8.688 5.213 13.656 ;
     RECT  4.993 18.288 5.213 23.976 ;
     RECT  5.057 28.656 5.249 31.128 ;
     RECT  4.787 0.144 5.267 0.6 ;
     RECT  5.077 25.2 5.353 25.896 ;
     RECT  4.277 32.256 5.389 34.728 ;
     RECT  4.849 36.048 5.389 38.664 ;
     RECT  4.421 39.936 5.533 39.96 ;
     RECT  5.029 40.944 5.533 52.728 ;
     RECT  5.249 28.656 5.569 30.792 ;
     RECT  5.533 39.936 5.573 52.728 ;
     RECT  5.389 32.256 5.605 38.664 ;
     RECT  4.499 5.04 5.609 5.112 ;
     RECT  5.573 40.512 5.615 52.728 ;
     RECT  4.739 54.336 5.615 55.224 ;
     RECT  4.787 1.68 5.653 3.432 ;
     RECT  5.609 5.088 5.653 5.112 ;
     RECT  5.033 6.288 5.653 7.416 ;
     RECT  5.615 40.512 5.699 55.224 ;
     RECT  5.653 5.088 5.74 7.416 ;
     RECT  5.641 0.096 5.747 0.12 ;
     RECT  5.569 28.512 5.747 30.792 ;
     RECT  5.699 40.512 5.753 51 ;
     RECT  5.353 24.672 5.785 25.896 ;
     RECT  5.213 8.784 5.789 13.656 ;
     RECT  5.213 18.288 5.789 23.4 ;
     RECT  5.653 1.68 5.857 3.912 ;
     RECT  4.925 15.216 5.893 16.008 ;
     RECT  5.605 32.256 5.897 39.432 ;
     RECT  5.753 43.824 5.897 51 ;
     RECT  5.747 28.512 5.933 30.648 ;
     RECT  5.897 37.584 5.933 39.432 ;
     RECT  5.789 10.08 6.001 13.656 ;
     RECT  5.785 24.672 6.217 26.808 ;
     RECT  5.753 40.512 6.221 42.6 ;
     RECT  5.857 1.104 6.253 3.912 ;
     RECT  5.933 28.512 6.277 29.304 ;
     RECT  6.277 27.888 6.323 29.304 ;
     RECT  5.933 38.736 6.323 39.432 ;
     RECT  5.699 54.96 6.361 55.224 ;
     RECT  5.789 8.784 6.397 8.808 ;
     RECT  5.897 43.872 6.401 51 ;
     RECT  5.74 6.336 6.469 7.416 ;
     RECT  6.397 8.448 6.469 8.808 ;
     RECT  5.74 5.088 6.473 5.112 ;
     RECT  6.253 0.624 6.497 3.912 ;
     RECT  5.789 18.864 6.517 23.4 ;
     RECT  6.217 24.528 6.517 26.808 ;
     RECT  6.401 43.872 6.545 50.136 ;
     RECT  6.497 0.624 6.581 3.96 ;
     RECT  6.517 18.864 6.653 26.808 ;
     RECT  5.897 32.256 6.689 36.408 ;
     RECT  6.323 29.088 6.725 29.304 ;
     RECT  6.323 27.888 6.793 27.912 ;
     RECT  6.689 32.256 6.797 36.072 ;
     RECT  6.469 6.336 6.829 8.808 ;
     RECT  6.545 43.872 6.833 49.752 ;
     RECT  6.221 40.56 6.86 42.6 ;
     RECT  6.833 43.872 6.86 49.512 ;
     RECT  5.893 15.216 6.865 16.392 ;
     RECT  6.829 6.288 6.901 8.808 ;
     RECT  6.001 10.08 6.901 14.232 ;
     RECT  6.901 6.288 6.973 14.232 ;
     RECT  6.865 15.216 6.973 16.536 ;
     RECT  6.973 6.288 7.004 16.536 ;
     RECT  6.581 0.624 7.045 3.432 ;
     RECT  6.653 18.864 7.081 26.664 ;
     RECT  5.699 52.176 7.081 52.248 ;
     RECT  5.699 53.568 7.081 53.832 ;
     RECT  7.081 18.192 7.153 26.664 ;
     RECT  7.004 6.096 7.196 16.536 ;
     RECT  7.153 17.904 7.196 26.664 ;
     RECT  7.045 0.576 7.292 3.432 ;
     RECT  7.292 0.528 7.378 3.432 ;
     RECT  6.361 54.96 7.381 55.944 ;
     RECT  6.793 27.84 7.405 27.912 ;
     RECT  6.86 40.56 7.441 49.512 ;
     RECT  7.045 4.512 7.657 4.536 ;
     RECT  7.196 6.096 7.657 26.664 ;
     RECT  7.405 27.84 7.657 28.296 ;
     RECT  6.797 34.128 7.669 36.072 ;
     RECT  7.657 6.096 7.693 28.296 ;
     RECT  6.725 29.28 7.693 29.304 ;
     RECT  7.693 6.096 7.765 29.304 ;
     RECT  5.933 30.288 7.765 30.648 ;
     RECT  7.378 0.48 7.808 3.432 ;
     RECT  7.657 4.464 7.808 4.584 ;
     RECT  7.765 6.096 7.808 30.648 ;
     RECT  6.797 32.256 7.808 33 ;
     RECT  7.669 34.128 7.808 36.552 ;
     RECT  5.933 37.584 7.808 37.608 ;
     RECT  6.323 38.736 7.808 39.336 ;
     RECT  7.441 40.416 7.808 49.512 ;
     RECT  6.793 51.12 7.808 51.144 ;
     RECT  7.081 52.176 7.808 53.832 ;
     RECT  7.381 54.96 7.808 56.568 ;
     RECT  7.808 0.48 7.912 62.652 ;
     RECT  7.912 0.48 8.104 62.382 ;
     RECT  8.104 10.08 8.165 29.352 ;
     RECT  8.165 15.84 8.245 29.352 ;
     RECT  8.104 0.48 8.269 7.992 ;
     RECT  8.104 38.736 8.309 48.792 ;
     RECT  8.269 0.096 8.453 7.992 ;
     RECT  8.245 25.824 8.453 29.352 ;
     RECT  8.453 6.288 8.525 7.992 ;
     RECT  8.309 38.736 8.597 42.6 ;
     RECT  8.453 0.096 8.705 4.536 ;
     RECT  8.104 9.072 8.813 9.096 ;
     RECT  8.705 0.096 8.819 4.248 ;
     RECT  8.245 15.84 8.819 24.744 ;
     RECT  8.819 16.368 8.867 24.744 ;
     RECT  8.104 30.432 8.915 36.696 ;
     RECT  8.819 1.728 8.921 4.248 ;
     RECT  8.453 25.824 8.957 29.208 ;
     RECT  8.957 25.824 9.059 26.472 ;
     RECT  8.525 6.288 9.065 7.656 ;
     RECT  8.104 50.928 9.097 53.256 ;
     RECT  8.867 16.56 9.277 24.744 ;
     RECT  9.059 25.824 9.277 26.328 ;
     RECT  9.097 50.832 9.281 53.256 ;
     RECT  8.165 10.08 9.313 14.856 ;
     RECT  8.309 43.824 9.385 48.792 ;
     RECT  9.277 16.56 9.389 26.328 ;
     RECT  8.104 56.496 9.397 56.568 ;
     RECT  8.597 40.032 9.404 42.6 ;
     RECT  9.385 43.824 9.404 48.84 ;
     RECT  8.915 30.48 9.443 36.696 ;
     RECT  9.397 55.536 9.443 56.568 ;
     RECT  9.443 32.16 9.457 36.696 ;
     RECT  8.597 38.736 9.589 39.048 ;
     RECT  9.313 10.08 9.601 15.288 ;
     RECT  9.281 50.832 9.637 51.192 ;
     RECT  9.601 9.792 9.677 15.288 ;
     RECT  9.389 16.56 9.677 26.088 ;
     RECT  9.281 52.176 9.781 53.256 ;
     RECT  9.457 32.16 9.821 37.032 ;
     RECT  9.677 9.792 9.857 15.048 ;
     RECT  8.819 0.096 9.875 0.168 ;
     RECT  9.404 40.032 9.889 48.84 ;
     RECT  9.637 50.112 9.893 51.192 ;
     RECT  9.443 55.536 9.925 56.52 ;
     RECT  9.821 33.408 9.929 37.032 ;
     RECT  9.589 38.112 9.961 39.048 ;
     RECT  9.889 40.032 9.961 49.032 ;
     RECT  9.677 16.896 9.965 26.088 ;
     RECT  9.961 38.112 10.001 49.032 ;
     RECT  9.965 16.896 10.037 25.8 ;
     RECT  9.961 8.496 10.067 8.52 ;
     RECT  9.065 6.288 10.141 7.512 ;
     RECT  10.141 5.712 10.145 7.512 ;
     RECT  9.781 52.176 10.213 54.12 ;
     RECT  9.925 55.104 10.213 56.52 ;
     RECT  9.929 33.888 10.217 37.032 ;
     RECT  10.217 34.032 10.325 37.032 ;
     RECT  10.001 38.112 10.325 48.792 ;
     RECT  10.325 38.112 10.541 48.744 ;
     RECT  10.213 52.176 10.547 56.52 ;
     RECT  8.921 1.728 10.577 4.152 ;
     RECT  10.547 54.864 10.577 56.52 ;
     RECT  9.925 59.856 10.681 59.88 ;
     RECT  10.145 5.712 10.684 7.416 ;
     RECT  9.857 10.176 10.685 15.048 ;
     RECT  8.957 27.6 10.693 29.208 ;
     RECT  9.443 30.48 10.693 30.552 ;
     RECT  9.875 0.096 10.739 0.12 ;
     RECT  10.693 27.6 10.739 30.984 ;
     RECT  9.821 32.16 10.739 32.376 ;
     RECT  10.037 16.896 10.757 25.56 ;
     RECT  10.577 54.864 10.757 55.128 ;
     RECT  10.739 30.96 10.78 30.984 ;
     RECT  10.541 38.112 10.787 41.064 ;
     RECT  10.787 38.112 10.789 39.048 ;
     RECT  10.739 27.6 10.793 29.64 ;
     RECT  10.793 27.6 10.825 29.208 ;
     RECT  10.739 32.256 10.835 32.376 ;
     RECT  9.893 50.112 10.861 51.144 ;
     RECT  10.685 10.176 10.885 13.656 ;
     RECT  10.789 37.824 10.937 39.048 ;
     RECT  10.684 5.712 10.979 7.224 ;
     RECT  10.577 1.728 11.009 3.336 ;
     RECT  10.757 16.896 11.075 25.224 ;
     RECT  10.885 10.128 11.123 13.656 ;
     RECT  10.681 59.808 11.132 59.88 ;
     RECT  11.132 59.808 11.219 60.552 ;
     RECT  9.925 58.128 11.225 58.152 ;
     RECT  10.465 8.544 11.257 8.568 ;
     RECT  10.325 34.032 11.257 36.408 ;
     RECT  11.257 8.544 11.365 8.712 ;
     RECT  10.685 15.024 11.365 15.048 ;
     RECT  11.075 16.896 11.365 25.176 ;
     RECT  10.861 50.112 11.365 51.192 ;
     RECT  10.547 52.176 11.365 53.016 ;
     RECT  10.541 42.048 11.473 48.744 ;
     RECT  11.365 50.112 11.473 53.016 ;
     RECT  11.219 59.808 11.473 60.264 ;
     RECT  11.365 8.544 11.509 8.76 ;
     RECT  10.825 26.832 11.617 29.208 ;
     RECT  11.617 26.64 11.657 29.208 ;
     RECT  10.577 56.496 11.701 56.52 ;
     RECT  11.009 2.784 11.725 3.336 ;
     RECT  11.509 8.256 11.725 9.096 ;
     RECT  11.123 10.128 11.725 13.56 ;
     RECT  10.979 5.712 11.756 6.84 ;
     RECT  11.365 15.024 11.761 25.176 ;
     RECT  11.009 1.728 11.765 1.8 ;
     RECT  11.657 28.896 11.795 29.208 ;
     RECT  11.689 31.248 11.837 31.272 ;
     RECT  11.756 5.04 11.843 6.84 ;
     RECT  11.473 42.048 11.869 53.016 ;
     RECT  11.869 42.048 11.909 53.064 ;
     RECT  11.473 59.712 11.941 60.264 ;
     RECT  11.909 50.688 11.945 53.064 ;
     RECT  11.701 56.496 11.987 57.576 ;
     RECT  11.941 58.848 11.987 60.264 ;
     RECT  10.757 54.864 11.989 54.888 ;
     RECT  11.987 58.848 12.028 58.872 ;
     RECT  11.945 51.12 12.049 53.064 ;
     RECT  11.989 54.096 12.049 54.888 ;
     RECT  12.049 51.12 12.076 54.888 ;
     RECT  11.657 26.64 12.121 27.768 ;
     RECT  11.761 14.784 12.161 25.176 ;
     RECT  10.937 38.544 12.181 39.048 ;
     RECT  10.787 40.032 12.181 41.064 ;
     RECT  11.725 8.256 12.229 13.56 ;
     RECT  12.161 14.784 12.229 22.584 ;
     RECT  11.257 33.648 12.229 36.408 ;
     RECT  11.725 2.784 12.373 4.008 ;
     RECT  12.229 8.256 12.409 22.584 ;
     RECT  11.795 28.992 12.445 29.208 ;
     RECT  10.835 32.256 12.445 32.28 ;
     RECT  12.445 32.064 12.481 32.28 ;
     RECT  12.229 33.648 12.481 37.416 ;
     RECT  11.173 0.144 12.517 0.6 ;
     RECT  12.181 38.544 12.517 41.064 ;
     RECT  11.909 42.048 12.517 49.56 ;
     RECT  12.161 23.808 12.524 25.176 ;
     RECT  12.121 26.304 12.524 27.768 ;
     RECT  12.445 28.992 12.565 29.688 ;
     RECT  12.524 30.72 12.565 30.744 ;
     RECT  11.987 60.24 12.589 60.264 ;
     RECT  12.076 54.72 12.733 54.888 ;
     RECT  12.481 32.064 12.764 37.416 ;
     RECT  12.733 54.72 12.841 55.272 ;
     RECT  12.841 54.72 12.877 55.32 ;
     RECT  11.843 5.136 12.908 6.84 ;
     RECT  12.373 2.064 12.913 4.008 ;
     RECT  12.913 1.728 13.021 4.008 ;
     RECT  12.908 5.04 13.021 6.84 ;
     RECT  12.409 7.968 13.021 22.584 ;
     RECT  12.076 51.12 13.021 53.592 ;
     RECT  12.517 0.096 13.057 0.6 ;
     RECT  13.021 1.728 13.057 6.84 ;
     RECT  13.057 0.096 13.093 6.84 ;
     RECT  13.021 7.92 13.093 22.584 ;
     RECT  12.589 60.24 13.093 60.408 ;
     RECT  13.093 0.096 13.208 22.584 ;
     RECT  12.524 23.808 13.208 27.768 ;
     RECT  12.565 28.992 13.208 30.744 ;
     RECT  12.764 32.064 13.208 37.464 ;
     RECT  12.517 38.544 13.208 49.56 ;
     RECT  13.021 50.832 13.208 53.592 ;
     RECT  12.877 54.72 13.208 55.464 ;
     RECT  11.987 56.496 13.208 57.336 ;
     RECT  13.093 59.856 13.208 60.408 ;
     RECT  13.208 0.096 13.345 62.652 ;
     RECT  12.697 63.84 13.345 63.864 ;
     RECT  13.345 0.096 13.417 63.864 ;
     RECT  13.417 0.096 13.504 63.912 ;
     RECT  13.504 53.52 13.529 53.544 ;
     RECT  13.504 0.096 13.673 29.256 ;
     RECT  13.504 62.496 13.715 63.912 ;
     RECT  13.673 5.088 13.781 29.256 ;
     RECT  13.504 60.384 13.889 60.408 ;
     RECT  13.504 58.704 13.907 58.728 ;
     RECT  13.504 54.576 13.925 57.624 ;
     RECT  13.781 5.088 13.955 29.16 ;
     RECT  13.955 15.984 13.997 29.16 ;
     RECT  13.673 0.096 14.041 4.056 ;
     RECT  14.041 0.096 14.099 3.048 ;
     RECT  13.504 50.832 14.177 52.44 ;
     RECT  13.955 5.088 14.213 14.904 ;
     RECT  14.213 8.64 14.243 14.904 ;
     RECT  14.099 0.192 14.285 3.048 ;
     RECT  13.504 33.936 14.285 49.608 ;
     RECT  14.177 50.832 14.285 51.432 ;
     RECT  14.285 50.832 14.465 51.048 ;
     RECT  13.925 54.576 14.465 56.184 ;
     RECT  14.041 4.032 14.677 4.056 ;
     RECT  14.213 5.088 14.677 7.512 ;
     RECT  14.285 1.104 14.771 3.048 ;
     RECT  14.243 8.736 14.789 14.904 ;
     RECT  13.715 62.496 14.893 63.864 ;
     RECT  14.605 59.76 14.924 59.784 ;
     RECT  13.504 31.68 14.933 32.472 ;
     RECT  13.997 16.032 14.969 29.16 ;
     RECT  14.465 54.576 15.037 55.272 ;
     RECT  14.677 4.032 15.109 7.512 ;
     RECT  14.969 16.032 15.113 29.112 ;
     RECT  15.037 54.384 15.145 55.272 ;
     RECT  14.285 33.936 15.149 48.984 ;
     RECT  14.893 62.496 15.173 63.96 ;
     RECT  14.933 32.016 15.181 32.472 ;
     RECT  15.149 33.936 15.181 40.92 ;
     RECT  14.533 61.344 15.189 61.368 ;
     RECT  15.149 42.048 15.253 48.984 ;
     RECT  15.173 62.496 15.257 64.68 ;
     RECT  15.253 42.048 15.289 49.272 ;
     RECT  15.189 60.816 15.293 61.368 ;
     RECT  15.289 42.048 15.308 49.368 ;
     RECT  14.177 52.416 15.325 52.44 ;
     RECT  15.145 54.096 15.325 55.272 ;
     RECT  15.113 16.032 15.329 29.016 ;
     RECT  15.109 3.84 15.356 7.512 ;
     RECT  13.925 57.216 15.397 57.624 ;
     RECT  15.308 42.048 15.433 49.464 ;
     RECT  14.771 1.104 15.437 2.856 ;
     RECT  15.329 16.032 15.437 25.224 ;
     RECT  15.356 3.84 15.443 7.656 ;
     RECT  14.789 8.736 15.443 13.608 ;
     RECT  15.397 0.096 15.481 0.12 ;
     RECT  15.257 62.496 15.493 63.912 ;
     RECT  15.437 1.104 15.505 1.8 ;
     RECT  15.443 9.984 15.545 13.608 ;
     RECT  14.789 14.688 15.613 14.904 ;
     RECT  15.397 56.88 15.613 57.624 ;
     RECT  15.505 0.576 15.661 1.8 ;
     RECT  14.924 59.424 15.689 59.784 ;
     RECT  15.437 2.832 15.731 2.856 ;
     RECT  15.721 30.384 15.757 30.408 ;
     RECT  15.443 5.712 15.761 7.656 ;
     RECT  15.545 10.032 15.793 13.608 ;
     RECT  15.613 14.688 15.793 15.48 ;
     RECT  15.493 62.16 15.827 63.912 ;
     RECT  15.661 1.008 15.833 1.8 ;
     RECT  15.325 52.416 15.833 55.272 ;
     RECT  14.465 51.024 15.901 51.048 ;
     RECT  15.833 52.416 15.901 52.824 ;
     RECT  15.181 32.016 15.941 40.92 ;
     RECT  15.941 32.016 15.971 34.776 ;
     RECT  15.833 1.008 15.977 1.752 ;
     RECT  15.833 54.144 15.977 55.272 ;
     RECT  15.977 1.008 16.019 1.032 ;
     RECT  15.329 26.256 16.019 29.016 ;
     RECT  15.761 5.808 16.081 7.656 ;
     RECT  15.443 8.736 16.081 8.76 ;
     RECT  15.613 56.88 16.081 58.248 ;
     RECT  16.081 56.88 16.085 58.824 ;
     RECT  15.757 30.384 16.117 30.744 ;
     RECT  15.971 32.016 16.117 32.616 ;
     RECT  15.977 54.384 16.157 55.272 ;
     RECT  15.901 51.024 16.189 52.824 ;
     RECT  15.293 60.816 16.229 60.84 ;
     RECT  15.433 42.048 16.297 49.512 ;
     RECT  16.157 54.672 16.309 55.272 ;
     RECT  16.189 56.448 16.309 56.472 ;
     RECT  16.309 54.672 16.355 56.472 ;
     RECT  15.793 10.032 16.405 15.48 ;
     RECT  16.117 30.384 16.409 32.616 ;
     RECT  16.355 54.672 16.445 56.088 ;
     RECT  16.405 10.032 16.477 15.528 ;
     RECT  15.437 16.512 16.477 24.696 ;
     RECT  16.081 5.808 16.501 8.76 ;
     RECT  16.297 42.048 16.513 49.608 ;
     RECT  16.409 30.384 16.517 32.28 ;
     RECT  15.941 35.808 16.517 40.92 ;
     RECT  15.827 62.16 16.54 63.864 ;
     RECT  16.501 5.808 16.547 9 ;
     RECT  16.477 10.032 16.547 24.696 ;
     RECT  16.517 36.048 16.589 40.92 ;
     RECT  16.085 58.08 16.589 58.824 ;
     RECT  16.547 10.176 16.595 24.696 ;
     RECT  16.595 14.832 16.597 24.696 ;
     RECT  16.019 26.256 16.597 27.768 ;
     RECT  16.589 40.128 16.657 40.92 ;
     RECT  16.54 62.208 16.661 63.864 ;
     RECT  16.517 30.384 16.765 30.888 ;
     RECT  16.445 54.672 16.769 55.032 ;
     RECT  16.547 8.736 16.841 9 ;
     RECT  15.443 3.84 16.909 4.44 ;
     RECT  16.513 42.048 16.909 49.8 ;
     RECT  16.189 50.832 16.909 52.824 ;
     RECT  16.589 58.08 16.913 58.104 ;
     RECT  15.971 34.224 17.017 34.776 ;
     RECT  16.661 62.448 17.017 63.864 ;
     RECT  16.189 59.808 17.021 59.832 ;
     RECT  16.873 2.784 17.027 2.808 ;
     RECT  16.597 14.832 17.057 27.768 ;
     RECT  16.657 40.128 17.057 41.016 ;
     RECT  16.909 3.84 17.068 4.68 ;
     RECT  16.909 42.048 17.089 52.824 ;
     RECT  17.057 14.832 17.129 15.528 ;
     RECT  17.057 16.512 17.129 27.768 ;
     RECT  16.547 5.808 17.165 7.512 ;
     RECT  17.017 62.448 17.17 63.912 ;
     RECT  17.068 4.656 17.237 4.68 ;
     RECT  17.129 14.832 17.237 14.856 ;
     RECT  17.165 7.44 17.245 7.512 ;
     RECT  17.17 62.448 17.363 63.96 ;
     RECT  16.445 56.064 17.381 56.088 ;
     RECT  17.017 34.176 17.413 34.776 ;
     RECT  17.165 5.808 17.449 6.36 ;
     RECT  17.089 42.048 17.449 52.968 ;
     RECT  16.769 55.008 17.485 55.032 ;
     RECT  17.057 40.128 17.525 40.92 ;
     RECT  17.413 33.84 17.557 34.776 ;
     RECT  16.019 28.992 17.66 29.016 ;
     RECT  16.765 30.048 17.66 30.888 ;
     RECT  17.245 7.488 17.737 7.512 ;
     RECT  16.841 8.736 17.737 8.76 ;
     RECT  17.737 7.488 17.881 8.76 ;
     RECT  16.517 32.256 17.893 32.28 ;
     RECT  17.881 7.488 17.989 8.808 ;
     RECT  17.363 62.448 17.989 63.912 ;
     RECT  16.595 10.176 18.025 13.656 ;
     RECT  17.449 42.048 18.061 53.544 ;
     RECT  17.66 28.992 18.097 30.888 ;
     RECT  17.893 32.016 18.097 32.28 ;
     RECT  17.129 16.512 18.133 26.856 ;
     RECT  17.449 5.568 18.169 6.36 ;
     RECT  18.133 16.512 18.169 27.624 ;
     RECT  18.061 41.904 18.169 53.544 ;
     RECT  18.169 41.664 18.181 53.544 ;
     RECT  17.989 62.352 18.181 63.912 ;
     RECT  17.557 33.552 18.205 34.776 ;
     RECT  18.169 16.08 18.277 27.624 ;
     RECT  17.161 60 18.277 60.024 ;
     RECT  18.181 62.16 18.341 63.912 ;
     RECT  18.277 58.128 18.349 58.152 ;
     RECT  18.277 59.76 18.349 60.024 ;
     RECT  18.341 62.16 18.425 64.68 ;
     RECT  18.169 5.568 18.469 6.456 ;
     RECT  18.469 3.696 18.529 6.456 ;
     RECT  17.989 7.488 18.529 8.904 ;
     RECT  18.061 2.256 18.608 2.28 ;
     RECT  18.529 3.696 18.608 8.904 ;
     RECT  18.025 10.176 18.608 14.184 ;
     RECT  18.277 15.456 18.608 27.624 ;
     RECT  18.097 28.992 18.608 32.28 ;
     RECT  18.205 33.552 18.608 34.968 ;
     RECT  16.589 36.048 18.608 38.952 ;
     RECT  17.525 40.128 18.608 40.68 ;
     RECT  18.181 41.664 18.608 53.928 ;
     RECT  17.485 55.008 18.608 55.704 ;
     RECT  17.917 56.88 18.608 57 ;
     RECT  18.349 58.128 18.608 60.024 ;
     RECT  18.425 62.16 18.608 64.536 ;
     RECT  18.608 2.148 18.712 64.536 ;
     RECT  18.712 2.418 18.803 64.536 ;
     RECT  18.803 2.418 18.904 63.912 ;
     RECT  18.904 9.888 18.965 27.624 ;
     RECT  18.904 4.656 19.001 6.84 ;
     RECT  18.904 28.8 19.001 29.016 ;
     RECT  18.904 40.128 19.001 55.704 ;
     RECT  19.001 4.944 19.037 6.84 ;
     RECT  18.904 33.36 19.037 35.016 ;
     RECT  19.037 5.088 19.043 6.84 ;
     RECT  19.043 5.088 19.045 6.696 ;
     RECT  18.904 30.192 19.073 32.376 ;
     RECT  19.037 33.552 19.145 35.016 ;
     RECT  18.904 56.88 19.181 60.696 ;
     RECT  18.904 7.968 19.217 8.856 ;
     RECT  19.001 40.128 19.217 55.32 ;
     RECT  18.965 22.56 19.361 27.624 ;
     RECT  19.181 56.88 19.505 58.152 ;
     RECT  19.073 31.488 19.685 32.28 ;
     RECT  18.904 62.16 19.721 63.912 ;
     RECT  19.217 47.136 19.757 55.32 ;
     RECT  19.721 63.792 19.781 63.912 ;
     RECT  19.361 22.56 19.793 26.808 ;
     RECT  19.505 56.88 19.793 56.904 ;
     RECT  19.181 59.76 19.829 60.696 ;
     RECT  19.861 1.632 19.897 1.656 ;
     RECT  19.825 0.096 20.005 0.12 ;
     RECT  19.721 62.16 20.005 62.76 ;
     RECT  18.904 36.144 20.045 38.808 ;
     RECT  19.073 30.192 20.077 30.216 ;
     RECT  19.829 60.672 20.077 60.696 ;
     RECT  20.005 62.112 20.077 62.76 ;
     RECT  18.965 9.888 20.081 21.528 ;
     RECT  19.145 33.936 20.081 34.968 ;
     RECT  20.081 34.464 20.113 34.968 ;
     RECT  20.045 36.144 20.113 38.76 ;
     RECT  20.081 14.64 20.149 21.528 ;
     RECT  19.793 22.56 20.149 22.776 ;
     RECT  19.217 8.832 20.153 8.856 ;
     RECT  19.045 5.808 20.185 6.696 ;
     RECT  20.149 14.64 20.189 22.776 ;
     RECT  19.217 40.128 20.252 46.056 ;
     RECT  19.757 47.136 20.252 55.032 ;
     RECT  20.081 9.888 20.257 13.656 ;
     RECT  20.077 30 20.257 30.216 ;
     RECT  19.505 58.128 20.257 58.152 ;
     RECT  19.001 28.8 20.293 28.92 ;
     RECT  20.252 40.128 20.339 55.032 ;
     RECT  20.293 28.512 20.365 28.92 ;
     RECT  19.897 1.632 20.389 1.752 ;
     RECT  20.005 0.096 20.401 0.6 ;
     RECT  20.389 1.632 20.401 2.184 ;
     RECT  19.781 63.792 20.401 64.68 ;
     RECT  20.339 47.136 20.441 55.032 ;
     RECT  20.257 9.312 20.513 13.656 ;
     RECT  20.185 5.808 20.581 6.792 ;
     RECT  20.189 14.736 20.585 22.776 ;
     RECT  20.257 29.904 20.617 30.216 ;
     RECT  20.113 34.464 20.621 38.76 ;
     RECT  20.257 58.128 20.621 59.64 ;
     RECT  20.077 60.672 20.621 62.76 ;
     RECT  20.401 0.096 20.657 2.184 ;
     RECT  20.621 34.464 20.693 36.84 ;
     RECT  20.617 29.904 20.701 30.264 ;
     RECT  20.621 62.112 20.797 62.76 ;
     RECT  20.581 5.712 20.833 6.792 ;
     RECT  20.797 62.112 20.917 62.808 ;
     RECT  20.401 63.792 20.917 64.776 ;
     RECT  20.621 58.704 21.013 59.64 ;
     RECT  20.621 60.672 21.013 60.696 ;
     RECT  20.585 15.504 21.017 22.776 ;
     RECT  20.365 27.888 21.085 28.92 ;
     RECT  20.701 29.904 21.085 30.216 ;
     RECT  21.013 58.704 21.089 60.696 ;
     RECT  21.089 58.704 21.197 60.408 ;
     RECT  21.197 58.704 21.233 58.728 ;
     RECT  20.339 40.128 21.263 46.056 ;
     RECT  20.621 37.968 21.337 38.76 ;
     RECT  20.693 34.464 21.365 36.792 ;
     RECT  19.793 23.808 21.373 26.808 ;
     RECT  21.085 27.888 21.373 30.216 ;
     RECT  20.441 47.136 21.373 48.888 ;
     RECT  19.685 32.016 21.397 32.28 ;
     RECT  21.337 37.968 21.397 38.808 ;
     RECT  21.263 39.888 21.397 46.056 ;
     RECT  20.833 5.712 21.404 6.84 ;
     RECT  20.441 49.872 21.413 55.032 ;
     RECT  21.404 5.712 21.445 7.416 ;
     RECT  20.513 10.224 21.481 13.656 ;
     RECT  21.373 47.088 21.481 48.888 ;
     RECT  21.413 49.872 21.481 54.072 ;
     RECT  21.397 37.968 21.485 46.056 ;
     RECT  20.657 0.096 21.491 1.8 ;
     RECT  21.445 5.712 21.491 7.992 ;
     RECT  21.373 23.808 21.521 30.216 ;
     RECT  21.481 10.224 21.589 13.992 ;
     RECT  21.397 31.632 21.637 32.28 ;
     RECT  21.491 5.712 21.665 6.792 ;
     RECT  21.637 31.632 21.724 33.048 ;
     RECT  21.485 39.312 21.805 46.056 ;
     RECT  21.481 47.088 21.805 54.072 ;
     RECT  21.521 23.808 21.809 29.208 ;
     RECT  21.491 7.968 21.881 7.992 ;
     RECT  20.917 62.112 21.925 64.776 ;
     RECT  21.491 1.728 21.971 1.8 ;
     RECT  21.017 15.504 21.98 22.056 ;
     RECT  21.229 3.264 21.989 3.288 ;
     RECT  21.809 23.808 22.021 27.576 ;
     RECT  21.589 9.648 22.057 13.992 ;
     RECT  21.365 34.224 22.057 36.792 ;
     RECT  21.805 39.312 22.097 54.072 ;
     RECT  21.925 61.632 22.169 64.776 ;
     RECT  21.665 5.712 22.201 6.696 ;
     RECT  21.724 31.632 22.201 32.28 ;
     RECT  22.169 63.696 22.205 64.776 ;
     RECT  22.205 63.792 22.241 64.776 ;
     RECT  22.097 39.312 22.277 52.488 ;
     RECT  22.201 5.088 22.285 6.696 ;
     RECT  22.169 61.632 22.309 62.664 ;
     RECT  21.197 60.096 22.345 60.408 ;
     RECT  22.309 61.392 22.345 62.664 ;
     RECT  21.521 30.192 22.349 30.216 ;
     RECT  22.021 23.52 22.355 27.576 ;
     RECT  21.98 15.504 22.385 22.2 ;
     RECT  22.057 34.176 22.385 36.792 ;
     RECT  22.345 60.096 22.405 62.664 ;
     RECT  22.345 58.896 22.412 58.92 ;
     RECT  22.357 30.384 22.444 30.408 ;
     RECT  22.385 34.896 22.489 36.792 ;
     RECT  21.485 37.968 22.489 38.184 ;
     RECT  22.057 9.552 22.637 13.992 ;
     RECT  22.405 60.048 22.643 62.664 ;
     RECT  22.097 53.952 22.705 54.072 ;
     RECT  22.643 60.048 22.745 62.616 ;
     RECT  22.385 15.552 22.777 22.2 ;
     RECT  22.412 58.128 22.781 58.92 ;
     RECT  22.489 34.896 22.789 38.184 ;
     RECT  22.277 39.312 22.789 40.872 ;
     RECT  22.777 15.552 22.813 22.248 ;
     RECT  22.355 23.52 22.813 26.808 ;
     RECT  21.697 55.104 22.817 55.128 ;
     RECT  22.789 34.896 22.835 40.872 ;
     RECT  21.491 0.096 22.849 0.6 ;
     RECT  21.971 1.728 22.849 1.752 ;
     RECT  22.277 42.048 22.853 52.488 ;
     RECT  22.213 3.408 22.94 3.432 ;
     RECT  22.94 3.408 23.029 3.912 ;
     RECT  22.988 27.888 23.065 27.912 ;
     RECT  21.809 28.992 23.065 29.208 ;
     RECT  22.853 50.928 23.101 52.488 ;
     RECT  22.285 5.712 23.137 6.696 ;
     RECT  22.781 58.896 23.353 58.92 ;
     RECT  23.101 50.928 23.365 52.728 ;
     RECT  22.705 53.952 23.365 54.12 ;
     RECT  22.835 38.592 23.425 40.872 ;
     RECT  22.853 42.048 23.425 49.896 ;
     RECT  22.813 15.552 23.461 26.808 ;
     RECT  23.029 2.88 23.497 3.912 ;
     RECT  23.137 5.712 23.569 6.84 ;
     RECT  22.849 0.096 23.603 1.752 ;
     RECT  22.201 31.536 23.713 32.28 ;
     RECT  22.637 9.552 23.821 13.704 ;
     RECT  23.461 14.928 23.821 26.808 ;
     RECT  22.835 34.896 23.821 37.608 ;
     RECT  23.821 9.552 23.929 26.808 ;
     RECT  23.353 58.896 23.929 59.016 ;
     RECT  23.603 1.728 24.008 1.752 ;
     RECT  23.497 2.88 24.008 4.008 ;
     RECT  23.569 5.568 24.008 6.84 ;
     RECT  23.929 8.736 24.008 26.808 ;
     RECT  23.065 27.888 24.008 29.208 ;
     RECT  23.713 31.536 24.008 32.52 ;
     RECT  23.821 34.416 24.008 37.608 ;
     RECT  23.425 38.592 24.008 49.896 ;
     RECT  23.365 50.928 24.008 54.12 ;
     RECT  23.353 56.88 24.008 56.904 ;
     RECT  23.929 58.704 24.008 59.016 ;
     RECT  22.745 60.048 24.008 62.568 ;
     RECT  23.603 0.096 24.179 0.552 ;
     RECT  24.008 1.728 24.304 62.652 ;
     RECT  24.304 40.656 24.329 40.68 ;
     RECT  24.179 0.096 24.371 0.504 ;
     RECT  24.304 42.048 24.401 49.896 ;
     RECT  22.241 64.704 24.433 64.776 ;
     RECT  24.304 58.656 24.437 58.776 ;
     RECT  24.304 23.04 24.467 23.064 ;
     RECT  24.304 24.528 24.467 29.064 ;
     RECT  24.304 9.552 24.545 14.136 ;
     RECT  24.467 26.256 24.545 29.064 ;
     RECT  24.304 2.832 24.611 4.104 ;
     RECT  24.304 60.048 24.689 60.12 ;
     RECT  24.304 56.352 24.707 57.576 ;
     RECT  24.304 31.44 24.789 36.984 ;
     RECT  24.433 63.84 24.833 64.776 ;
     RECT  24.304 61.392 24.901 62.652 ;
     RECT  24.833 63.84 24.901 64.728 ;
     RECT  24.901 61.392 24.905 64.728 ;
     RECT  24.905 61.392 25.043 64.68 ;
     RECT  24.304 5.808 25.085 6.888 ;
     RECT  24.707 57.552 25.121 57.576 ;
     RECT  25.043 61.392 25.139 63.288 ;
     RECT  24.611 2.88 25.235 4.104 ;
     RECT  25.139 61.392 25.283 63.24 ;
     RECT  24.545 9.552 25.292 13.896 ;
     RECT  25.283 63.168 25.301 63.24 ;
     RECT  25.235 3.936 25.333 4.104 ;
     RECT  25.085 5.808 25.333 6.792 ;
     RECT  25.292 9.216 25.337 13.896 ;
     RECT  24.304 15.312 25.369 22.056 ;
     RECT  24.467 24.528 25.369 25.128 ;
     RECT  25.337 9.216 25.379 13.8 ;
     RECT  24.304 1.728 25.381 1.752 ;
     RECT  25.301 63.168 25.409 63.192 ;
     RECT  24.789 31.44 25.445 32.28 ;
     RECT  24.437 58.656 25.445 58.728 ;
     RECT  25.235 2.88 25.481 2.952 ;
     RECT  25.481 2.88 25.523 2.904 ;
     RECT  25.379 9.696 25.523 13.8 ;
     RECT  25.043 64.56 25.523 64.68 ;
     RECT  24.304 38.496 25.58 39.336 ;
     RECT  25.369 23.712 25.621 25.128 ;
     RECT  25.381 1.728 25.625 1.8 ;
     RECT  25.523 64.656 25.625 64.68 ;
     RECT  25.549 57.6 25.633 57.624 ;
     RECT  25.625 1.728 25.657 1.752 ;
     RECT  25.333 3.936 25.661 6.792 ;
     RECT  25.58 38.064 25.667 39.336 ;
     RECT  24.304 50.928 25.667 54.744 ;
     RECT  24.371 0.096 25.693 0.168 ;
     RECT  25.657 1.152 25.693 1.752 ;
     RECT  24.545 26.256 25.693 29.016 ;
     RECT  25.369 15.216 25.697 22.056 ;
     RECT  25.621 23.328 25.729 25.128 ;
     RECT  25.697 15.216 25.801 17.976 ;
     RECT  25.661 4.176 25.805 6.792 ;
     RECT  25.667 38.688 25.841 39.336 ;
     RECT  24.789 33.648 25.909 36.984 ;
     RECT  24.401 42.048 25.909 48.744 ;
     RECT  24.401 49.776 25.909 49.896 ;
     RECT  25.549 40.368 25.955 40.392 ;
     RECT  25.445 31.68 26.053 32.28 ;
     RECT  25.909 33.648 26.053 37.608 ;
     RECT  25.405 56.112 26.093 56.136 ;
     RECT  24.689 60.048 26.101 60.072 ;
     RECT  26.053 31.68 26.14 37.608 ;
     RECT  25.697 19.104 26.161 22.056 ;
     RECT  25.729 23.232 26.161 25.128 ;
     RECT  25.693 26.256 26.161 29.304 ;
     RECT  25.805 4.176 26.273 6.264 ;
     RECT  26.161 26.208 26.348 29.304 ;
     RECT  26.348 26.208 26.435 30.024 ;
     RECT  25.477 7.92 26.437 7.944 ;
     RECT  26.161 19.104 26.453 25.128 ;
     RECT  26.453 24.24 26.485 25.128 ;
     RECT  26.435 26.208 26.485 29.304 ;
     RECT  26.437 7.392 26.561 8.472 ;
     RECT  25.801 14.832 26.597 17.976 ;
     RECT  26.14 33.648 26.629 37.608 ;
     RECT  25.841 38.688 26.629 39.24 ;
     RECT  26.561 7.92 26.633 8.472 ;
     RECT  26.14 31.68 26.665 32.28 ;
     RECT  25.445 58.704 26.701 58.728 ;
     RECT  26.101 59.952 26.701 60.072 ;
     RECT  26.453 19.104 26.705 22.68 ;
     RECT  25.909 42.048 26.725 49.896 ;
     RECT  26.633 8.304 26.773 8.472 ;
     RECT  25.523 10.176 26.773 13.8 ;
     RECT  26.597 14.832 26.773 17.688 ;
     RECT  26.273 6.096 26.801 6.264 ;
     RECT  26.273 4.176 26.809 4.968 ;
     RECT  26.705 19.104 26.813 21.432 ;
     RECT  25.283 61.392 26.849 61.656 ;
     RECT  26.773 8.304 26.857 17.688 ;
     RECT  26.801 6.096 26.885 6.936 ;
     RECT  26.809 3.696 26.893 4.968 ;
     RECT  26.885 6.096 26.921 6.84 ;
     RECT  26.705 22.656 26.921 22.68 ;
     RECT  26.629 33.648 26.957 39.24 ;
     RECT  25.693 0.096 27 1.752 ;
     RECT  26.725 41.904 27.061 49.896 ;
     RECT  25.667 50.928 27.061 54.648 ;
     RECT  26.893 4.176 27.065 4.968 ;
     RECT  26.813 19.104 27.101 21.288 ;
     RECT  27 0.096 27.164 1.8 ;
     RECT  26.857 10.56 27.209 17.688 ;
     RECT  26.593 56.208 27.457 56.232 ;
     RECT  27.065 4.512 27.569 4.968 ;
     RECT  26.701 58.704 27.637 60.072 ;
     RECT  27.164 0.096 27.673 2.28 ;
     RECT  27.637 58.656 27.731 60.072 ;
     RECT  27.457 56.208 27.853 56.712 ;
     RECT  27.673 0.096 27.857 3.096 ;
     RECT  27.857 0.096 27.923 2.28 ;
     RECT  27.061 41.904 27.925 54.648 ;
     RECT  27.209 10.56 27.929 17.16 ;
     RECT  26.849 61.392 28.001 61.416 ;
     RECT  27.923 0.096 28.037 2.232 ;
     RECT  27.853 56.208 28.145 57.048 ;
     RECT  28.037 0.096 28.211 1.8 ;
     RECT  27.101 19.104 28.213 21 ;
     RECT  26.485 24.24 28.213 29.304 ;
     RECT  27.313 40.416 28.241 40.44 ;
     RECT  27.925 41.664 28.241 54.648 ;
     RECT  26.921 6.72 28.249 6.84 ;
     RECT  27.731 59.184 28.253 60.072 ;
     RECT  27.929 10.656 28.285 17.16 ;
     RECT  26.957 33.792 28.285 39.24 ;
     RECT  27.569 4.656 28.321 4.968 ;
     RECT  28.249 6.72 28.361 6.888 ;
     RECT  26.857 8.304 28.393 8.856 ;
     RECT  28.241 40.416 28.412 54.648 ;
     RECT  28.145 56.208 28.412 56.76 ;
     RECT  27.673 22.8 28.429 23.112 ;
     RECT  28.213 24.192 28.429 29.304 ;
     RECT  28.285 33.792 28.429 39.336 ;
     RECT  28.429 22.8 28.537 29.304 ;
     RECT  26.665 30.768 28.537 32.28 ;
     RECT  28.429 33.36 28.537 39.336 ;
     RECT  28.213 18.864 28.609 21 ;
     RECT  28.609 18.864 28.753 21.096 ;
     RECT  28.211 0.096 28.865 0.6 ;
     RECT  28.537 30.768 28.897 39.336 ;
     RECT  28.865 0.096 28.973 0.168 ;
     RECT  28.973 0.144 28.979 0.168 ;
     RECT  28.211 1.728 29.081 1.8 ;
     RECT  28.537 22.8 29.125 29.688 ;
     RECT  28.897 30.672 29.185 39.336 ;
     RECT  28.412 40.416 29.185 56.76 ;
     RECT  28.321 4.656 29.408 5.304 ;
     RECT  28.361 6.72 29.408 6.744 ;
     RECT  28.393 7.776 29.408 8.856 ;
     RECT  28.285 10.656 29.408 17.64 ;
     RECT  28.753 18.816 29.408 21.096 ;
     RECT  29.125 22.56 29.408 29.688 ;
     RECT  29.185 30.672 29.408 56.76 ;
     RECT  29.185 58.656 29.408 58.68 ;
     RECT  28.253 60.048 29.408 60.072 ;
     RECT  29.408 2.148 29.512 62.652 ;
     RECT  29.512 2.418 29.704 62.382 ;
     RECT  29.704 30.672 29.729 32.28 ;
     RECT  29.704 18.816 29.765 29.592 ;
     RECT  29.704 15.312 29.843 17.64 ;
     RECT  29.704 54.624 29.981 54.648 ;
     RECT  29.704 9.792 29.987 13.896 ;
     RECT  29.704 4.56 30.467 8.328 ;
     RECT  30.467 6.192 30.557 8.328 ;
     RECT  29.765 22.704 30.629 29.592 ;
     RECT  29.704 38.208 30.665 53.064 ;
     RECT  29.704 33.36 30.769 37.224 ;
     RECT  30.665 38.208 30.769 40.008 ;
     RECT  30.629 24.336 30.805 29.592 ;
     RECT  29.729 30.864 30.805 32.28 ;
     RECT  30.629 22.704 30.809 23.256 ;
     RECT  30.665 41.184 30.845 53.064 ;
     RECT  29.704 55.776 30.908 56.52 ;
     RECT  29.704 58.656 30.947 59.304 ;
     RECT  30.845 41.184 30.953 52.872 ;
     RECT  30.557 6.576 31.021 8.328 ;
     RECT  29.987 9.792 31.021 10.68 ;
     RECT  29.843 17.136 31.021 17.64 ;
     RECT  29.765 18.816 31.021 21.672 ;
     RECT  31.021 6.576 31.061 10.68 ;
     RECT  29.843 15.312 31.061 15.864 ;
     RECT  30.467 4.56 31.097 5.16 ;
     RECT  31.061 6.576 31.097 7.464 ;
     RECT  31.061 8.832 31.129 10.68 ;
     RECT  30.769 33.36 31.169 40.008 ;
     RECT  31.021 17.136 31.273 21.672 ;
     RECT  31.273 17.136 31.277 22.104 ;
     RECT  30.805 24.336 31.285 32.28 ;
     RECT  31.169 33.36 31.285 39.816 ;
     RECT  31.285 24.336 31.331 39.816 ;
     RECT  31.097 4.56 31.525 5.064 ;
     RECT  31.129 8.832 31.529 10.824 ;
     RECT  31.097 7.104 31.565 7.464 ;
     RECT  31.529 10.224 31.601 10.824 ;
     RECT  29.987 11.808 31.637 13.896 ;
     RECT  31.061 15.408 31.637 15.864 ;
     RECT  30.908 55.248 31.817 56.52 ;
     RECT  30.809 23.232 31.885 23.256 ;
     RECT  30.947 59.28 31.889 59.304 ;
     RECT  31.849 0.192 31.921 0.216 ;
     RECT  31.637 11.808 31.957 11.976 ;
     RECT  31.529 8.832 32.029 8.856 ;
     RECT  31.331 32.016 32.069 39.816 ;
     RECT  31.277 21.984 32.101 22.104 ;
     RECT  31.885 23.232 32.101 23.352 ;
     RECT  31.921 0.192 32.137 1.176 ;
     RECT  31.637 13.104 32.137 13.896 ;
     RECT  31.637 15.408 32.137 15.432 ;
     RECT  31.817 56.496 32.141 56.52 ;
     RECT  31.957 11.76 32.177 11.976 ;
     RECT  32.029 8.64 32.285 8.856 ;
     RECT  32.137 13.104 32.285 15.432 ;
     RECT  32.285 15.408 32.357 15.432 ;
     RECT  30.953 41.184 32.425 52.824 ;
     RECT  32.137 0.048 32.485 1.176 ;
     RECT  32.245 2.256 32.485 2.28 ;
     RECT  31.565 7.104 32.485 7.128 ;
     RECT  32.285 8.64 32.531 8.664 ;
     RECT  32.425 41.184 32.533 52.872 ;
     RECT  32.245 63.84 32.54 63.864 ;
     RECT  32.485 7.008 32.605 7.128 ;
     RECT  31.277 17.136 32.605 20.904 ;
     RECT  32.177 11.76 32.645 11.784 ;
     RECT  31.331 24.336 32.645 30.888 ;
     RECT  32.533 41.136 32.645 52.872 ;
     RECT  31.601 10.224 32.677 10.68 ;
     RECT  32.645 41.376 32.677 52.872 ;
     RECT  32.54 63.264 32.677 63.864 ;
     RECT  32.645 24.48 32.713 30.888 ;
     RECT  32.069 32.016 32.713 32.04 ;
     RECT  32.677 41.376 32.749 53.064 ;
     RECT  32.605 6.24 32.821 7.128 ;
     RECT  32.677 63.216 32.957 63.864 ;
     RECT  32.749 41.376 32.963 53.592 ;
     RECT  32.101 21.984 32.969 23.352 ;
     RECT  32.605 17.136 33.001 20.952 ;
     RECT  32.969 21.984 33.001 22.008 ;
     RECT  31.525 3.984 33.011 5.064 ;
     RECT  31.817 55.248 33.037 55.272 ;
     RECT  32.713 24.48 33.041 32.04 ;
     RECT  32.969 23.328 33.077 23.352 ;
     RECT  32.069 33.024 33.077 39.816 ;
     RECT  33.001 17.136 33.107 22.008 ;
     RECT  33.037 55.248 33.109 55.512 ;
     RECT  33.011 3.984 33.113 4.008 ;
     RECT  33.041 31.392 33.145 32.04 ;
     RECT  32.957 62.64 33.145 63.864 ;
     RECT  32.285 13.104 33.149 13.416 ;
     RECT  33.109 54.912 33.164 55.512 ;
     RECT  33.164 54.912 33.173 55.656 ;
     RECT  33.107 17.136 33.181 18.024 ;
     RECT  33.109 58.704 33.212 58.728 ;
     RECT  32.965 59.76 33.212 59.784 ;
     RECT  33.253 61.008 33.26 61.032 ;
     RECT  33.212 58.704 33.299 59.784 ;
     RECT  32.677 9.648 33.349 10.68 ;
     RECT  33.145 56.88 33.361 56.904 ;
     RECT  33.26 61.008 33.365 61.608 ;
     RECT  33.149 13.104 33.433 13.128 ;
     RECT  33.173 54.816 33.433 55.656 ;
     RECT  33.349 9.072 33.436 10.68 ;
     RECT  33.299 58.704 33.437 58.728 ;
     RECT  33.365 61.584 33.491 61.608 ;
     RECT  33.436 9.648 33.505 10.68 ;
     RECT  33.433 13.056 33.545 13.128 ;
     RECT  33.145 62.64 33.613 64.68 ;
     RECT  32.485 0.048 33.683 2.28 ;
     RECT  33.361 56.88 33.685 57.72 ;
     RECT  33.613 61.728 33.689 64.68 ;
     RECT  33.683 1.68 33.779 2.28 ;
     RECT  33.689 61.728 33.971 63.912 ;
     RECT  32.963 41.376 33.973 42.504 ;
     RECT  32.963 43.632 33.973 53.592 ;
     RECT  33.077 33.696 34.045 39.816 ;
     RECT  33.433 54.672 34.153 55.656 ;
     RECT  33.685 56.88 34.153 57.912 ;
     RECT  33.107 19.056 34.189 22.008 ;
     RECT  33.145 31.392 34.213 32.28 ;
     RECT  33.181 16.512 34.225 18.024 ;
     RECT  34.189 19.056 34.225 22.776 ;
     RECT  34.225 16.512 34.357 22.776 ;
     RECT  33.041 24.48 34.357 30.12 ;
     RECT  34.045 33.552 34.364 39.816 ;
     RECT  33.973 41.376 34.364 53.592 ;
     RECT  34.357 16.512 34.477 30.12 ;
     RECT  34.213 31.296 34.477 32.28 ;
     RECT  33.545 13.104 34.513 13.128 ;
     RECT  34.477 16.512 34.513 32.28 ;
     RECT  34.364 33.552 34.585 53.592 ;
     RECT  34.153 54.672 34.585 57.912 ;
     RECT  33.011 5.04 34.621 5.064 ;
     RECT  32.821 6.192 34.621 7.128 ;
     RECT  34.621 5.04 34.652 7.128 ;
     RECT  33.793 8.112 34.652 8.136 ;
     RECT  33.505 9.648 34.657 11.448 ;
     RECT  33.683 0.048 34.693 0.6 ;
     RECT  33.779 1.68 34.693 2.232 ;
     RECT  33.299 59.76 34.693 59.784 ;
     RECT  34.657 9.168 34.765 11.448 ;
     RECT  34.513 13.104 34.765 13.368 ;
     RECT  33.971 63.792 34.789 63.912 ;
     RECT  34.513 16.368 34.801 32.28 ;
     RECT  34.693 0.048 34.808 2.232 ;
     RECT  34.801 3.936 34.808 3.96 ;
     RECT  34.652 5.04 34.808 8.136 ;
     RECT  34.765 9.168 34.808 13.368 ;
     RECT  34.801 15.456 34.808 32.28 ;
     RECT  34.585 33.552 34.808 57.912 ;
     RECT  34.693 59.76 34.808 59.832 ;
     RECT  33.971 61.728 34.808 62.808 ;
     RECT  34.808 0.048 34.835 62.808 ;
     RECT  34.835 1.728 34.94 62.808 ;
     RECT  34.789 63.792 34.94 64.68 ;
     RECT  34.835 0.048 35.075 0.6 ;
     RECT  34.94 1.728 35.104 64.68 ;
     RECT  35.104 1.728 35.123 1.848 ;
     RECT  35.104 14.64 35.201 23.4 ;
     RECT  35.104 33.552 35.201 42.744 ;
     RECT  35.104 59.808 35.237 64.68 ;
     RECT  35.237 59.808 35.273 64.584 ;
     RECT  35.104 57.888 35.309 58.728 ;
     RECT  35.104 24.48 35.315 32.28 ;
     RECT  35.104 2.832 35.345 3.96 ;
     RECT  35.309 57.888 35.345 57.912 ;
     RECT  35.315 24.576 35.489 32.28 ;
     RECT  35.104 5.04 35.555 13.368 ;
     RECT  35.201 33.6 35.705 42.744 ;
     RECT  35.273 59.808 35.795 63.912 ;
     RECT  35.489 31.056 35.813 32.28 ;
     RECT  35.201 14.64 35.891 21.816 ;
     RECT  35.705 33.6 35.939 41.064 ;
     RECT  35.891 17.376 35.993 21.816 ;
     RECT  35.075 0.048 36.061 0.552 ;
     RECT  35.123 1.728 36.061 1.752 ;
     RECT  35.555 9.216 36.065 13.368 ;
     RECT  35.795 59.808 36.083 62.76 ;
     RECT  35.891 14.64 36.137 16.392 ;
     RECT  36.083 59.808 36.169 61.032 ;
     RECT  36.065 12.24 36.173 13.368 ;
     RECT  35.813 31.392 36.173 32.28 ;
     RECT  35.705 42.288 36.277 42.744 ;
     RECT  35.104 43.872 36.277 54.792 ;
     RECT  35.489 24.576 36.284 29.64 ;
     RECT  35.939 33.6 36.353 40.824 ;
     RECT  36.284 24.528 36.371 29.64 ;
     RECT  36.277 42.288 36.389 54.792 ;
     RECT  35.345 2.832 36.421 2.856 ;
     RECT  35.795 63.792 36.485 63.912 ;
     RECT  36.065 9.216 36.529 11.256 ;
     RECT  35.201 23.376 36.569 23.4 ;
     RECT  36.485 63.792 36.569 64.68 ;
     RECT  35.555 5.04 36.613 7.992 ;
     RECT  36.529 9.12 36.613 11.256 ;
     RECT  36.353 33.6 36.641 39.384 ;
     RECT  36.173 12.528 36.673 13.368 ;
     RECT  36.137 14.64 36.673 16.296 ;
     RECT  36.389 42.288 36.677 42.744 ;
     RECT  36.389 43.92 36.745 54.792 ;
     RECT  35.104 55.968 36.745 56.424 ;
     RECT  36.421 2.832 36.755 2.904 ;
     RECT  36.673 12.528 36.757 16.296 ;
     RECT  36.371 24.576 36.781 29.64 ;
     RECT  36.173 31.536 36.853 32.28 ;
     RECT  36.641 33.6 36.853 39.288 ;
     RECT  36.781 24.576 36.865 30.264 ;
     RECT  36.083 62.16 36.881 62.76 ;
     RECT  36.569 63.792 36.881 63.816 ;
     RECT  36.709 57.6 36.925 57.624 ;
     RECT  36.353 40.416 36.997 40.824 ;
     RECT  36.677 42.288 37.033 42.312 ;
     RECT  36.757 12.528 37.037 12.792 ;
     RECT  36.865 24.576 37.073 29.64 ;
     RECT  36.925 57.6 37.105 57.672 ;
     RECT  36.745 43.92 37.109 56.424 ;
     RECT  36.169 59.664 37.169 61.032 ;
     RECT  36.755 2.88 37.217 2.904 ;
     RECT  37.105 57.504 37.285 57.672 ;
     RECT  36.613 5.04 37.289 11.256 ;
     RECT  37.073 24.624 37.289 29.64 ;
     RECT  37.109 49.824 37.393 56.424 ;
     RECT  37.285 57.456 37.393 57.672 ;
     RECT  37.109 43.92 37.429 48.456 ;
     RECT  35.345 3.936 37.433 3.96 ;
     RECT  36.061 0.048 37.457 1.752 ;
     RECT  36.997 40.416 37.469 40.968 ;
     RECT  37.457 0.048 37.54 1.848 ;
     RECT  35.993 17.376 37.583 21.672 ;
     RECT  37.289 5.712 37.619 11.256 ;
     RECT  36.881 62.16 37.645 63.816 ;
     RECT  37.54 0.048 37.657 1.896 ;
     RECT  37.619 8.208 37.66 8.472 ;
     RECT  36.853 31.536 37.717 39.288 ;
     RECT  37.469 40.416 37.717 40.44 ;
     RECT  37.717 31.536 37.757 40.44 ;
     RECT  37.583 17.328 37.789 21.672 ;
     RECT  37.789 17.328 37.825 22.488 ;
     RECT  36.757 14.64 37.897 16.296 ;
     RECT  37.825 17.328 37.897 23.064 ;
     RECT  37.393 49.824 37.897 57.672 ;
     RECT  37.657 0.048 37.907 1.176 ;
     RECT  37.757 31.536 37.937 40.152 ;
     RECT  37.169 59.28 37.955 61.032 ;
     RECT  37.907 0.048 37.973 1.128 ;
     RECT  37.897 14.64 38.009 23.064 ;
     RECT  37.973 0.144 38.017 1.128 ;
     RECT  38.017 0.528 38.099 1.128 ;
     RECT  37.619 5.712 38.117 7.08 ;
     RECT  38.009 14.64 38.149 21.048 ;
     RECT  38.009 22.464 38.149 23.064 ;
     RECT  37.289 24.624 38.149 29.592 ;
     RECT  38.117 7.056 38.153 7.08 ;
     RECT  38.099 0.528 38.195 0.6 ;
     RECT  37.033 42.048 38.221 42.312 ;
     RECT  37.429 43.632 38.221 48.456 ;
     RECT  38.117 5.712 38.225 6.024 ;
     RECT  37.897 49.824 38.225 58.152 ;
     RECT  38.149 22.464 38.233 29.592 ;
     RECT  37.037 12.768 38.257 12.792 ;
     RECT  38.149 14.352 38.257 21.048 ;
     RECT  37.619 9.6 38.297 11.256 ;
     RECT  38.221 42.048 38.329 48.456 ;
     RECT  37.645 62.16 38.387 63.96 ;
     RECT  38.329 42.048 38.437 48.696 ;
     RECT  38.225 49.824 38.579 57.576 ;
     RECT  38.297 11.184 38.581 11.256 ;
     RECT  38.257 12.48 38.581 21.048 ;
     RECT  38.437 41.664 38.581 48.696 ;
     RECT  38.233 22.464 38.585 23.064 ;
     RECT  37.937 31.536 38.617 32.28 ;
     RECT  37.955 61.008 38.621 61.032 ;
     RECT  38.533 64.656 38.657 64.68 ;
     RECT  38.581 11.184 38.693 21.048 ;
     RECT  37.955 59.28 38.693 59.448 ;
     RECT  38.693 12.48 38.701 21.048 ;
     RECT  38.579 49.872 38.729 57.576 ;
     RECT  38.387 62.16 38.729 63.528 ;
     RECT  37.66 8.208 38.761 8.232 ;
     RECT  38.297 9.6 38.761 9.624 ;
     RECT  38.701 15.504 38.765 21.048 ;
     RECT  38.701 12.48 38.771 14.376 ;
     RECT  38.617 30.768 38.771 32.28 ;
     RECT  38.225 5.712 38.828 5.928 ;
     RECT  38.761 8.208 38.869 9.624 ;
     RECT  38.729 49.872 38.909 54.12 ;
     RECT  38.828 5.376 38.915 5.928 ;
     RECT  38.585 22.464 38.945 22.872 ;
     RECT  38.771 30.96 38.945 32.28 ;
     RECT  38.729 55.296 39.089 57.576 ;
     RECT  38.195 0.576 39.169 0.6 ;
     RECT  39.089 56.976 39.229 57.576 ;
     RECT  39.193 2.304 39.276 2.328 ;
     RECT  39.276 2.304 39.373 2.376 ;
     RECT  38.693 11.184 39.373 11.256 ;
     RECT  38.765 18.96 39.509 21.048 ;
     RECT  38.693 59.424 39.553 59.448 ;
     RECT  38.945 22.8 39.661 22.872 ;
     RECT  39.089 55.296 39.697 55.992 ;
     RECT  39.553 59.424 39.733 59.736 ;
     RECT  39.373 11.136 39.805 11.256 ;
     RECT  38.771 12.48 39.805 12.792 ;
     RECT  38.771 14.352 39.877 14.376 ;
     RECT  38.765 15.504 39.877 17.64 ;
     RECT  38.909 49.872 39.877 51.816 ;
     RECT  38.909 53.04 39.877 54.12 ;
     RECT  39.877 14.352 39.913 17.64 ;
     RECT  39.509 18.96 39.913 21.672 ;
     RECT  39.653 0.096 39.953 0.12 ;
     RECT  39.373 1.728 40.021 2.376 ;
     RECT  39.589 3.408 40.021 3.432 ;
     RECT  39.877 49.872 40.049 54.12 ;
     RECT  38.581 41.616 40.057 48.696 ;
     RECT  38.915 5.712 40.069 5.928 ;
     RECT  40.057 41.424 40.069 48.696 ;
     RECT  40.049 49.728 40.069 54.12 ;
     RECT  40.021 1.728 40.208 3.432 ;
     RECT  40.069 5.712 40.208 6.12 ;
     RECT  38.869 8.016 40.208 9.624 ;
     RECT  39.805 11.136 40.208 12.792 ;
     RECT  39.913 14.352 40.208 21.672 ;
     RECT  39.661 22.8 40.208 23.352 ;
     RECT  38.233 24.624 40.208 29.592 ;
     RECT  38.945 31.152 40.208 32.28 ;
     RECT  37.937 33.264 40.208 40.152 ;
     RECT  40.069 41.424 40.208 54.12 ;
     RECT  39.697 55.152 40.208 55.992 ;
     RECT  39.229 56.976 40.208 58.152 ;
     RECT  39.733 59.424 40.208 60.12 ;
     RECT  38.729 62.208 40.208 63.528 ;
     RECT  40.208 1.728 40.312 63.528 ;
     RECT  40.312 1.728 40.504 62.382 ;
     RECT  40.453 0.144 40.643 0.168 ;
     RECT  40.504 11.136 40.643 12.648 ;
     RECT  40.504 48.192 40.643 58.728 ;
     RECT  40.504 36.336 40.78 40.248 ;
     RECT  40.643 48.192 40.889 53.304 ;
     RECT  40.504 3.936 40.924 6.168 ;
     RECT  40.504 22.8 40.924 35.304 ;
     RECT  40.924 32.16 40.979 35.304 ;
     RECT  40.504 41.376 40.997 47.208 ;
     RECT  40.924 5.136 41.105 6.168 ;
     RECT  40.924 22.8 41.177 31.176 ;
     RECT  40.979 32.16 41.177 32.28 ;
     RECT  40.889 48.192 41.213 52.392 ;
     RECT  40.312 63.504 41.213 63.528 ;
     RECT  40.979 33.696 41.321 35.304 ;
     RECT  40.504 9.6 41.357 9.912 ;
     RECT  41.105 5.136 41.393 6.12 ;
     RECT  41.213 49.536 41.465 52.392 ;
     RECT  41.465 49.536 41.507 52.056 ;
     RECT  40.643 54.384 41.537 58.728 ;
     RECT  40.504 14.064 41.605 15.528 ;
     RECT  40.504 16.56 41.605 21.528 ;
     RECT  40.997 41.424 41.605 47.208 ;
     RECT  41.213 48.192 41.605 48.552 ;
     RECT  41.537 54.384 41.605 56.52 ;
     RECT  41.177 22.8 41.609 22.824 ;
     RECT  41.605 14.064 41.645 21.528 ;
     RECT  41.605 54.096 41.651 56.52 ;
     RECT  40.643 11.232 41.653 12.648 ;
     RECT  41.645 14.064 41.653 16.008 ;
     RECT  41.653 11.232 41.677 16.008 ;
     RECT  41.651 54.096 41.692 54.888 ;
     RECT  41.677 10.848 41.699 16.008 ;
     RECT  41.699 10.848 41.717 12.264 ;
     RECT  41.605 41.424 41.717 48.552 ;
     RECT  41.605 0.576 41.749 0.6 ;
     RECT  40.504 1.728 41.749 2.952 ;
     RECT  41.321 33.888 41.749 35.304 ;
     RECT  40.78 36.336 41.749 39.864 ;
     RECT  41.749 0.576 41.753 2.952 ;
     RECT  41.749 33.888 41.753 39.864 ;
     RECT  40.504 7.344 41.785 8.28 ;
     RECT  41.753 0.576 41.843 1.848 ;
     RECT  41.651 55.872 41.897 56.52 ;
     RECT  41.843 1.68 41.939 1.848 ;
     RECT  41.753 2.88 41.969 2.952 ;
     RECT  41.699 13.296 41.969 16.008 ;
     RECT  41.177 23.808 41.969 31.176 ;
     RECT  41.507 49.824 42.005 52.056 ;
     RECT  41.717 41.424 42.073 48.216 ;
     RECT  41.537 57.6 42.113 58.728 ;
     RECT  41.393 5.328 42.181 6.12 ;
     RECT  41.785 7.344 42.181 8.52 ;
     RECT  40.924 3.936 42.185 3.96 ;
     RECT  42.073 41.04 42.185 48.216 ;
     RECT  42.005 49.872 42.185 52.056 ;
     RECT  42.181 5.328 42.227 8.52 ;
     RECT  41.965 0.096 42.265 0.216 ;
     RECT  42.265 0.192 42.275 0.216 ;
     RECT  42.227 5.328 42.505 5.832 ;
     RECT  41.645 17.088 42.509 21.528 ;
     RECT  41.177 32.16 42.541 32.184 ;
     RECT  42.227 6.864 42.565 8.52 ;
     RECT  41.357 9.6 42.565 9.624 ;
     RECT  42.185 41.424 42.617 48.216 ;
     RECT  41.929 22.704 42.653 22.776 ;
     RECT  41.717 10.848 42.721 11.688 ;
     RECT  40.504 60.096 42.725 60.12 ;
     RECT  42.565 6.864 42.869 9.624 ;
     RECT  42.812 0.528 42.899 0.552 ;
     RECT  41.939 1.728 42.937 1.848 ;
     RECT  42.505 5.184 42.937 5.832 ;
     RECT  41.969 23.808 42.973 30.264 ;
     RECT  42.541 31.344 42.973 32.184 ;
     RECT  42.937 1.152 43.004 1.848 ;
     RECT  41.969 2.88 43.004 2.904 ;
     RECT  41.897 55.872 43.009 56.088 ;
     RECT  42.113 57.6 43.009 58.152 ;
     RECT  42.973 23.808 43.013 32.184 ;
     RECT  43.004 1.152 43.021 2.904 ;
     RECT  41.753 33.888 43.081 39.528 ;
     RECT  42.617 41.616 43.085 48.216 ;
     RECT  43.021 1.728 43.091 2.904 ;
     RECT  42.721 10.848 43.153 12.024 ;
     RECT  43.081 33.648 43.157 39.528 ;
     RECT  42.937 4.224 43.193 5.832 ;
     RECT  42.185 49.872 43.225 51.72 ;
     RECT  43.091 2.88 43.237 2.904 ;
     RECT  43.153 10.8 43.261 12.024 ;
     RECT  41.969 13.296 43.261 13.32 ;
     RECT  41.969 14.832 43.261 16.008 ;
     RECT  42.509 17.088 43.261 20.808 ;
     RECT  43.261 10.8 43.265 13.32 ;
     RECT  42.653 22.752 43.333 22.776 ;
     RECT  43.013 23.808 43.333 30.792 ;
     RECT  43.225 49.872 43.34 51.864 ;
     RECT  43.261 14.832 43.373 20.808 ;
     RECT  43.34 49.392 43.379 51.864 ;
     RECT  43.333 53.232 43.381 53.256 ;
     RECT  41.692 54.432 43.381 54.888 ;
     RECT  43.013 32.16 43.405 32.184 ;
     RECT  43.157 33.648 43.405 35.256 ;
     RECT  43.379 49.392 43.427 51.768 ;
     RECT  43.157 36.48 43.477 39.528 ;
     RECT  43.009 55.872 43.517 58.152 ;
     RECT  43.193 4.224 43.621 5.208 ;
     RECT  43.333 22.752 43.621 30.792 ;
     RECT  43.237 2.88 43.625 2.952 ;
     RECT  43.517 57.984 43.625 58.152 ;
     RECT  43.373 14.832 43.693 15 ;
     RECT  43.621 4.176 43.729 5.208 ;
     RECT  43.373 16.272 43.765 20.808 ;
     RECT  43.621 22.128 43.765 30.792 ;
     RECT  43.381 53.232 43.765 54.888 ;
     RECT  43.517 55.872 43.765 56.472 ;
     RECT  43.625 2.928 43.801 2.952 ;
     RECT  43.729 4.128 43.801 5.208 ;
     RECT  43.765 53.232 43.805 56.472 ;
     RECT  43.765 16.272 43.811 30.792 ;
     RECT  42.869 6.864 43.873 7.512 ;
     RECT  43.693 14.784 43.877 15 ;
     RECT  43.811 22.32 43.877 30.792 ;
     RECT  43.427 50.304 43.877 51.768 ;
     RECT  43.265 10.848 43.913 13.32 ;
     RECT  43.877 23.808 43.913 30.792 ;
     RECT  43.085 45.984 43.945 48.216 ;
     RECT  43.873 6.816 43.957 7.512 ;
     RECT  42.869 8.496 43.957 9.624 ;
     RECT  43.811 16.272 43.985 21.288 ;
     RECT  43.957 6.816 44.003 9.624 ;
     RECT  43.405 32.16 44.129 35.256 ;
     RECT  43.801 2.928 44.165 5.208 ;
     RECT  43.877 14.88 44.188 15 ;
     RECT  44.188 14.976 44.201 15 ;
     RECT  43.085 41.616 44.291 45 ;
     RECT  44.165 2.928 44.345 4.488 ;
     RECT  43.985 16.512 44.345 21.288 ;
     RECT  43.091 1.728 44.377 1.896 ;
     RECT  44.003 6.864 44.417 9.624 ;
     RECT  43.805 53.568 44.483 56.472 ;
     RECT  44.417 7.056 44.489 9.624 ;
     RECT  44.129 33.648 44.521 35.256 ;
     RECT  43.477 36.48 44.521 39.864 ;
     RECT  44.483 55.536 44.525 56.472 ;
     RECT  44.345 16.512 44.561 20.424 ;
     RECT  43.913 23.808 44.561 23.928 ;
     RECT  44.129 32.16 44.737 32.376 ;
     RECT  44.377 1.728 44.773 1.944 ;
     RECT  44.345 2.928 44.773 4.248 ;
     RECT  43.877 22.32 44.845 22.776 ;
     RECT  43.913 11.472 44.989 13.32 ;
     RECT  43.877 50.688 45.025 51.768 ;
     RECT  44.483 53.568 45.025 54.312 ;
     RECT  44.945 0.096 45.029 0.12 ;
     RECT  45.025 50.592 45.205 51.768 ;
     RECT  45.025 52.8 45.205 54.312 ;
     RECT  45.205 50.592 45.241 54.312 ;
     RECT  43.913 24.96 45.421 30.792 ;
     RECT  44.525 55.536 45.493 55.56 ;
     RECT  45.385 0.528 45.529 0.552 ;
     RECT  44.773 1.728 45.529 4.248 ;
     RECT  45.529 0.528 45.608 4.248 ;
     RECT  44.489 7.2 45.608 9.624 ;
     RECT  44.989 10.704 45.608 13.32 ;
     RECT  45.169 14.832 45.608 14.856 ;
     RECT  44.561 16.512 45.608 19.32 ;
     RECT  44.561 20.304 45.608 20.424 ;
     RECT  44.845 22.032 45.608 22.776 ;
     RECT  45.421 24.192 45.608 30.792 ;
     RECT  44.737 32.016 45.608 32.376 ;
     RECT  44.521 33.648 45.608 39.864 ;
     RECT  44.291 41.616 45.608 44.76 ;
     RECT  43.945 45.984 45.608 49.032 ;
     RECT  45.241 50.4 45.608 54.312 ;
     RECT  45.493 55.536 45.608 56.04 ;
     RECT  43.625 57.984 45.608 58.008 ;
     RECT  45.608 0.528 45.712 62.652 ;
     RECT  45.712 0.528 45.904 62.382 ;
     RECT  45.904 0.528 46.001 3.432 ;
     RECT  45.904 24.192 46.001 25.56 ;
     RECT  45.904 14.208 46.019 14.856 ;
     RECT  46.001 0.528 46.033 3.384 ;
     RECT  46.019 14.4 46.045 14.856 ;
     RECT  46.033 0.48 46.067 3.384 ;
     RECT  45.904 26.544 46.163 48.936 ;
     RECT  45.904 55.68 46.217 56.04 ;
     RECT  46.163 26.544 46.325 30.168 ;
     RECT  46.163 31.728 46.325 48.936 ;
     RECT  45.904 16.08 46.397 23.16 ;
     RECT  45.904 50.352 46.403 54.504 ;
     RECT  46.067 0.48 46.501 0.6 ;
     RECT  46.325 31.776 46.547 48.936 ;
     RECT  46.547 33.072 46.577 48.936 ;
     RECT  46.501 0.096 46.585 0.6 ;
     RECT  45.904 4.512 46.595 13.08 ;
     RECT  45.904 57.6 46.613 57.624 ;
     RECT  46.585 0.48 46.643 0.6 ;
     RECT  46.067 1.632 46.685 3.384 ;
     RECT  46.547 31.776 46.691 31.944 ;
     RECT  46.397 16.08 46.757 16.104 ;
     RECT  46.397 17.088 46.829 23.16 ;
     RECT  46.577 33.552 46.829 48.936 ;
     RECT  46.403 50.352 46.865 53.544 ;
     RECT  46.829 33.552 46.937 41.448 ;
     RECT  46.643 0.576 46.945 0.6 ;
     RECT  46.685 1.632 47.036 2.712 ;
     RECT  46.865 50.352 47.077 53.064 ;
     RECT  46.829 22.32 47.113 23.16 ;
     RECT  46.001 24.192 47.113 25.464 ;
     RECT  47.036 1.104 47.123 2.712 ;
     RECT  46.595 6.816 47.149 13.08 ;
     RECT  46.595 4.512 47.153 4.536 ;
     RECT  46.937 40.896 47.153 41.448 ;
     RECT  46.829 42.528 47.183 48.936 ;
     RECT  47.077 50.256 47.183 53.064 ;
     RECT  47.183 42.528 47.189 53.064 ;
     RECT  47.189 44.16 47.267 53.064 ;
     RECT  46.045 14.4 47.317 14.76 ;
     RECT  47.153 40.944 47.333 41.448 ;
     RECT  46.217 55.872 47.333 56.04 ;
     RECT  47.149 6.816 47.363 13.272 ;
     RECT  47.317 14.352 47.365 14.76 ;
     RECT  46.691 31.776 47.369 31.8 ;
     RECT  47.333 55.872 47.369 55.896 ;
     RECT  47.363 6.816 47.405 12.504 ;
     RECT  47.113 22.32 47.437 25.464 ;
     RECT  46.325 26.544 47.437 28.248 ;
     RECT  47.333 41.424 47.441 41.448 ;
     RECT  47.267 49.536 47.441 53.064 ;
     RECT  47.437 22.32 47.473 28.248 ;
     RECT  46.325 29.28 47.473 30.168 ;
     RECT  47.473 22.32 47.477 30.168 ;
     RECT  47.267 44.16 47.477 48.264 ;
     RECT  47.405 7.44 47.513 12.504 ;
     RECT  47.365 14.352 47.513 14.808 ;
     RECT  47.513 14.352 47.585 14.424 ;
     RECT  46.829 17.088 47.653 21.096 ;
     RECT  47.513 7.44 47.693 12.312 ;
     RECT  47.441 50.16 47.801 53.064 ;
     RECT  47.477 22.32 47.837 24.168 ;
     RECT  47.123 1.584 47.869 2.712 ;
     RECT  47.653 16.416 47.869 21.096 ;
     RECT  47.437 55.296 48.013 55.848 ;
     RECT  47.869 1.584 48.083 3.336 ;
     RECT  48.049 32.448 48.157 32.568 ;
     RECT  46.937 33.552 48.157 39.864 ;
     RECT  48.013 54.432 48.161 55.848 ;
     RECT  47.869 16.32 48.229 21.096 ;
     RECT  47.477 46.032 48.269 48.264 ;
     RECT  48.229 16.32 48.275 21.144 ;
     RECT  48.157 32.448 48.277 39.864 ;
     RECT  47.189 42.528 48.301 43.032 ;
     RECT  47.477 44.16 48.301 45 ;
     RECT  47.693 7.44 48.445 12.216 ;
     RECT  48.301 42.528 48.469 45 ;
     RECT  48.445 7.344 48.481 12.216 ;
     RECT  48.083 1.728 48.493 3.336 ;
     RECT  48.229 13.584 48.553 14.28 ;
     RECT  48.553 13.584 48.557 14.856 ;
     RECT  47.477 25.44 48.557 30.168 ;
     RECT  48.469 42.144 48.563 45 ;
     RECT  48.275 16.416 48.593 21.144 ;
     RECT  47.837 22.32 48.629 23.832 ;
     RECT  48.563 42.144 48.629 43.32 ;
     RECT  48.157 5.088 48.661 5.112 ;
     RECT  48.481 6.432 48.661 12.216 ;
     RECT  48.661 5.088 48.665 5.208 ;
     RECT  48.661 6.336 48.697 12.216 ;
     RECT  48.697 6.24 48.737 12.216 ;
     RECT  48.593 16.416 48.796 18.264 ;
     RECT  47.801 50.16 48.805 52.728 ;
     RECT  48.557 14.832 48.845 14.856 ;
     RECT  48.161 55.824 48.881 55.848 ;
     RECT  48.796 16.416 48.953 18.216 ;
     RECT  48.805 50.16 48.985 52.968 ;
     RECT  48.737 12.192 49.021 12.216 ;
     RECT  48.665 5.184 49.025 5.208 ;
     RECT  48.953 17.616 49.025 18.216 ;
     RECT  48.493 3.216 49.057 3.336 ;
     RECT  49.021 12.192 49.057 12.312 ;
     RECT  48.557 13.584 49.057 13.608 ;
     RECT  49.057 12.192 49.061 13.608 ;
     RECT  48.269 46.224 49.061 48.264 ;
     RECT  49.093 41.232 49.129 41.256 ;
     RECT  48.161 54.432 49.129 54.456 ;
     RECT  48.277 32.544 49.133 39.864 ;
     RECT  49.129 54.432 49.165 54.6 ;
     RECT  48.593 19.248 49.169 21.144 ;
     RECT  49.093 0.096 49.189 0.12 ;
     RECT  49.165 54.432 49.205 54.696 ;
     RECT  48.557 25.44 49.237 25.464 ;
     RECT  49.061 46.224 49.237 47.16 ;
     RECT  48.563 44.448 49.273 45 ;
     RECT  49.237 46.032 49.273 47.16 ;
     RECT  49.205 54.576 49.273 54.696 ;
     RECT  48.985 50.16 49.345 53.4 ;
     RECT  49.189 0.096 49.381 0.168 ;
     RECT  48.629 22.32 49.381 23.352 ;
     RECT  49.061 48.192 49.381 48.264 ;
     RECT  49.133 33.024 49.421 39.864 ;
     RECT  49.381 0.096 49.493 0.216 ;
     RECT  49.489 15.984 49.573 16.392 ;
     RECT  49.381 48.192 49.597 48.6 ;
     RECT  48.493 1.728 49.669 1.944 ;
     RECT  49.057 3.216 49.669 3.384 ;
     RECT  49.345 50.16 49.669 53.496 ;
     RECT  49.273 54.576 49.673 55.464 ;
     RECT  49.669 49.872 49.705 53.496 ;
     RECT  49.573 15.648 49.709 16.392 ;
     RECT  48.629 42.528 49.709 43.32 ;
     RECT  49.273 44.448 49.741 47.16 ;
     RECT  49.421 33.024 49.889 35.352 ;
     RECT  49.673 54.672 49.957 55.464 ;
     RECT  49.381 22.272 50.029 23.352 ;
     RECT  48.557 26.544 50.065 30.168 ;
     RECT  49.165 31.296 50.065 31.32 ;
     RECT  50.06 4.512 50.101 4.536 ;
     RECT  49.129 40.896 50.137 41.256 ;
     RECT  48.737 6.24 50.173 11.16 ;
     RECT  49.061 12.24 50.173 13.608 ;
     RECT  49.709 15.984 50.173 16.392 ;
     RECT  49.025 17.616 50.173 18.168 ;
     RECT  49.421 36.336 50.173 39.864 ;
     RECT  50.137 40.896 50.173 41.4 ;
     RECT  49.705 49.776 50.204 53.496 ;
     RECT  49.169 19.488 50.245 21.144 ;
     RECT  50.029 22.272 50.245 23.736 ;
     RECT  49.493 0.144 50.341 0.216 ;
     RECT  50.173 15.984 50.353 18.168 ;
     RECT  49.957 54.672 50.353 55.704 ;
     RECT  50.353 15.984 50.533 18.36 ;
     RECT  50.245 19.488 50.533 23.736 ;
     RECT  50.101 4.512 50.569 5.064 ;
     RECT  50.173 6.24 50.569 13.608 ;
     RECT  50.341 0.144 50.609 0.6 ;
     RECT  49.889 33.024 50.677 33.048 ;
     RECT  50.149 58.896 50.677 58.92 ;
     RECT  50.636 60.24 50.677 60.264 ;
     RECT  49.597 48.192 50.684 48.792 ;
     RECT  50.204 49.776 50.684 53.544 ;
     RECT  49.889 34.416 50.713 35.352 ;
     RECT  50.173 36.336 50.713 41.4 ;
     RECT  49.709 42.528 50.713 43.128 ;
     RECT  49.237 24.912 50.749 25.464 ;
     RECT  50.065 26.544 50.749 31.32 ;
     RECT  49.741 44.4 50.749 47.16 ;
     RECT  50.684 48.192 50.749 53.544 ;
     RECT  50.713 34.416 50.785 41.4 ;
     RECT  50.713 42.48 50.785 43.128 ;
     RECT  49.669 1.728 51.008 3.384 ;
     RECT  50.569 4.512 51.008 13.608 ;
     RECT  50.533 15.984 51.008 23.736 ;
     RECT  50.749 24.912 51.008 31.32 ;
     RECT  50.677 32.832 51.008 33.048 ;
     RECT  50.785 34.416 51.008 43.128 ;
     RECT  50.749 44.4 51.008 53.544 ;
     RECT  50.353 54.672 51.008 55.752 ;
     RECT  47.725 57.552 51.008 57.576 ;
     RECT  50.677 58.896 51.008 60.264 ;
     RECT  50.609 0.144 51.101 0.168 ;
     RECT  51.008 1.728 51.112 62.652 ;
     RECT  51.112 1.728 51.304 62.382 ;
     RECT  51.304 15.984 51.329 16.104 ;
     RECT  51.304 26.544 51.437 31.128 ;
     RECT  51.304 44.4 51.443 53.016 ;
     RECT  51.443 44.4 51.509 48.408 ;
     RECT  51.443 49.44 51.509 53.016 ;
     RECT  51.509 47.328 51.545 48.408 ;
     RECT  51.509 50.592 51.587 53.016 ;
     RECT  51.304 59.28 51.587 59.496 ;
     RECT  51.304 1.728 51.635 3.384 ;
     RECT  51.304 56.208 51.689 56.376 ;
     RECT  51.304 17.136 51.725 21.528 ;
     RECT  51.725 17.136 51.805 21.384 ;
     RECT  51.509 44.4 51.869 46.296 ;
     RECT  51.689 56.208 51.869 56.232 ;
     RECT  51.805 17.136 51.923 18.024 ;
     RECT  51.304 14.784 51.941 14.808 ;
     RECT  51.437 26.544 51.941 30.456 ;
     RECT  51.587 50.592 51.941 52.584 ;
     RECT  51.805 19.008 52.049 21.384 ;
     RECT  51.101 0.096 52.121 0.168 ;
     RECT  51.304 25.008 52.297 25.464 ;
     RECT  51.304 32.496 52.301 32.52 ;
     RECT  51.304 23.328 52.333 23.832 ;
     RECT  52.297 24.912 52.333 25.464 ;
     RECT  51.304 4.704 52.345 13.8 ;
     RECT  51.329 16.08 52.369 16.104 ;
     RECT  52.345 5.52 52.373 13.8 ;
     RECT  52.121 0.144 52.405 0.168 ;
     RECT  51.635 1.728 52.405 3.336 ;
     RECT  52.333 23.328 52.412 25.464 ;
     RECT  51.941 26.544 52.412 27.912 ;
     RECT  52.412 23.328 52.441 27.912 ;
     RECT  52.369 15.984 52.477 16.104 ;
     RECT  51.923 17.136 52.477 17.16 ;
     RECT  52.441 23.088 52.499 27.912 ;
     RECT  51.304 54.336 52.501 54.696 ;
     RECT  51.869 45.552 52.553 46.296 ;
     RECT  51.545 47.328 52.553 48.216 ;
     RECT  52.499 23.088 52.625 25.464 ;
     RECT  52.553 45.6 52.657 46.296 ;
     RECT  52.049 19.008 52.661 20.328 ;
     RECT  51.304 36.336 52.693 43.272 ;
     RECT  51.869 44.4 52.693 44.424 ;
     RECT  52.693 36.336 52.739 44.424 ;
     RECT  52.405 0.144 52.741 3.336 ;
     RECT  52.657 45.6 52.769 46.632 ;
     RECT  52.739 36.336 52.787 41.64 ;
     RECT  51.587 59.472 52.801 59.496 ;
     RECT  52.625 23.328 52.805 25.464 ;
     RECT  52.787 36.336 52.805 40.152 ;
     RECT  51.941 29.088 52.837 30.456 ;
     RECT  51.509 49.44 52.837 49.464 ;
     RECT  51.941 50.592 52.837 51.288 ;
     RECT  52.739 43.008 52.841 44.424 ;
     RECT  52.729 33.072 52.877 33.096 ;
     RECT  52.373 5.52 52.913 13.08 ;
     RECT  52.477 15.984 52.913 17.16 ;
     RECT  52.801 58.704 52.913 59.496 ;
     RECT  52.913 17.136 52.949 17.16 ;
     RECT  51.941 52.56 52.949 52.584 ;
     RECT  52.501 53.568 52.949 54.696 ;
     RECT  52.369 57.552 52.981 57.576 ;
     RECT  52.741 0.144 52.993 4.44 ;
     RECT  52.993 0.144 53.021 4.392 ;
     RECT  52.837 29.088 53.029 30.984 ;
     RECT  52.949 53.568 53.053 54.36 ;
     RECT  52.805 23.808 53.057 25.464 ;
     RECT  52.769 45.6 53.093 46.296 ;
     RECT  53.093 45.744 53.129 46.296 ;
     RECT  51.304 34.128 53.173 35.256 ;
     RECT  52.981 57.552 53.201 57.624 ;
     RECT  53.021 0.144 53.267 3.336 ;
     RECT  52.553 47.616 53.269 48.216 ;
     RECT  52.499 26.544 53.341 27.912 ;
     RECT  53.029 29.088 53.341 31.944 ;
     RECT  52.841 43.008 53.411 43.56 ;
     RECT  53.269 47.616 53.521 48.456 ;
     RECT  52.837 49.44 53.521 51.288 ;
     RECT  52.913 5.52 53.525 12.552 ;
     RECT  53.411 43.296 53.555 43.56 ;
     RECT  52.049 21.36 53.557 21.384 ;
     RECT  53.521 47.616 53.603 51.288 ;
     RECT  53.603 50.496 53.629 51.288 ;
     RECT  53.525 5.52 53.669 10.152 ;
     RECT  53.341 26.544 53.701 31.944 ;
     RECT  52.913 15.984 53.852 16.008 ;
     RECT  52.787 41.376 53.881 41.64 ;
     RECT  52.661 19.008 53.917 19.032 ;
     RECT  53.701 26.544 53.917 32.52 ;
     RECT  53.173 33.792 53.917 35.256 ;
     RECT  52.913 59.472 53.948 59.496 ;
     RECT  53.267 1.152 53.957 3.336 ;
     RECT  53.525 11.232 53.989 12.552 ;
     RECT  53.948 59.232 53.989 59.496 ;
     RECT  53.989 59.232 54.035 60.408 ;
     RECT  52.661 20.304 54.061 20.328 ;
     RECT  53.557 21.36 54.061 21.672 ;
     RECT  53.917 26.544 54.061 35.256 ;
     RECT  52.805 36.336 54.061 39.912 ;
     RECT  53.629 50.496 54.061 52.008 ;
     RECT  53.053 53.04 54.061 54.36 ;
     RECT  53.917 18.72 54.133 19.032 ;
     RECT  54.061 20.304 54.133 21.672 ;
     RECT  53.603 47.616 54.133 49.512 ;
     RECT  54.133 18.72 54.173 21.672 ;
     RECT  54.173 18.72 54.179 21.24 ;
     RECT  53.989 11.232 54.241 13.368 ;
     RECT  53.021 4.368 54.277 4.392 ;
     RECT  53.669 5.52 54.277 10.104 ;
     RECT  54.179 19.392 54.281 21.24 ;
     RECT  54.169 55.68 54.349 55.704 ;
     RECT  53.881 41.376 54.373 42.168 ;
     RECT  53.267 0.144 54.385 0.168 ;
     RECT  53.957 1.152 54.385 2.952 ;
     RECT  53.129 45.744 54.421 46.104 ;
     RECT  54.373 40.992 54.46 42.168 ;
     RECT  54.421 63.264 54.493 63.288 ;
     RECT  54.061 26.544 54.529 39.912 ;
     RECT  54.385 0.144 54.62 2.952 ;
     RECT  54.241 11.232 54.637 13.464 ;
     RECT  54.62 0.096 54.707 2.952 ;
     RECT  54.277 4.368 54.709 10.104 ;
     RECT  54.637 11.232 54.709 13.656 ;
     RECT  53.852 15.36 54.709 16.008 ;
     RECT  53.057 23.808 54.709 23.832 ;
     RECT  53.057 25.056 54.709 25.464 ;
     RECT  54.529 26.544 54.709 40.392 ;
     RECT  53.555 43.344 54.709 43.56 ;
     RECT  54.349 55.68 54.709 55.848 ;
     RECT  54.349 56.88 54.709 56.904 ;
     RECT  54.035 59.52 54.709 60.408 ;
     RECT  54.493 63.264 54.709 63.768 ;
     RECT  54.709 4.368 54.713 13.656 ;
     RECT  54.709 23.808 54.745 23.928 ;
     RECT  54.709 25.056 54.745 40.392 ;
     RECT  54.133 47.376 54.745 49.512 ;
     RECT  54.061 50.496 54.745 54.36 ;
     RECT  54.745 23.808 54.755 40.392 ;
     RECT  54.46 41.376 54.781 42.168 ;
     RECT  54.709 43.344 54.781 43.608 ;
     RECT  54.421 45.648 54.781 46.104 ;
     RECT  54.709 62.16 54.781 63.768 ;
     RECT  54.709 14.928 54.785 16.008 ;
     RECT  54.709 55.68 54.821 56.904 ;
     RECT  54.755 23.904 54.851 40.392 ;
     RECT  54.709 59.52 54.851 60.456 ;
     RECT  54.745 47.376 54.857 54.36 ;
     RECT  54.785 14.928 54.893 15.48 ;
     RECT  54.851 59.52 54.893 60.408 ;
     RECT  54.781 41.376 54.899 43.608 ;
     RECT  54.281 20.304 54.929 21.24 ;
     RECT  54.893 59.52 54.929 59.544 ;
     RECT  54.929 20.304 55.037 21.096 ;
     RECT  53.917 58.128 55.105 58.152 ;
     RECT  54.781 45.216 55.109 46.104 ;
     RECT  54.781 62.16 55.141 63.864 ;
     RECT  54.713 4.368 55.145 4.776 ;
     RECT  55.105 58.128 55.145 58.632 ;
     RECT  54.707 0.144 55.187 2.952 ;
     RECT  55.109 45.6 55.213 46.104 ;
     RECT  53.917 22.8 55.237 22.824 ;
     RECT  55.187 0.144 55.253 2.808 ;
     RECT  55.237 22.176 55.283 22.824 ;
     RECT  54.851 30.576 55.283 40.392 ;
     RECT  55.141 62.16 55.285 63.912 ;
     RECT  54.313 17.808 55.357 17.832 ;
     RECT  55.285 62.016 55.357 63.912 ;
     RECT  54.713 5.76 55.361 13.656 ;
     RECT  54.899 42.144 55.388 43.608 ;
     RECT  55.253 0.576 55.397 2.808 ;
     RECT  54.821 56.304 55.429 56.904 ;
     RECT  55.357 17.232 55.501 17.832 ;
     RECT  54.857 48.192 55.609 54.36 ;
     RECT  55.037 20.304 55.753 20.616 ;
     RECT  55.361 8.208 55.765 13.656 ;
     RECT  55.283 33.408 55.861 40.392 ;
     RECT  55.397 1.104 55.955 2.808 ;
     RECT  55.501 17.136 56.077 17.832 ;
     RECT  55.765 8.208 56.149 14.856 ;
     RECT  55.213 45.6 56.156 46.536 ;
     RECT  54.851 24.096 56.221 29.592 ;
     RECT  55.283 30.576 56.221 32.184 ;
     RECT  55.357 62.016 56.243 64.776 ;
     RECT  56.149 8.208 56.293 15.672 ;
     RECT  55.283 22.176 56.293 22.2 ;
     RECT  55.955 1.152 56.408 2.808 ;
     RECT  55.145 4.752 56.408 4.776 ;
     RECT  55.361 5.76 56.408 7.176 ;
     RECT  56.293 8.208 56.408 16.104 ;
     RECT  56.077 17.136 56.408 18.024 ;
     RECT  55.753 19.776 56.408 20.616 ;
     RECT  56.293 22.176 56.408 22.776 ;
     RECT  56.221 24.096 56.408 32.184 ;
     RECT  55.861 33.408 56.408 40.488 ;
     RECT  55.388 42.144 56.408 44.568 ;
     RECT  56.156 45.6 56.408 46.776 ;
     RECT  55.609 48.192 56.408 55.272 ;
     RECT  55.429 56.304 56.408 57.048 ;
     RECT  55.145 58.608 56.408 58.632 ;
     RECT  56.365 60.672 56.408 60.696 ;
     RECT  56.243 62.016 56.408 63.288 ;
     RECT  56.408 1.152 56.627 63.288 ;
     RECT  56.627 1.728 56.704 63.288 ;
     RECT  56.704 47.472 56.819 56.472 ;
     RECT  56.704 57.6 56.819 63.288 ;
     RECT  56.704 41.664 56.909 43.608 ;
     RECT  56.704 1.728 56.945 2.808 ;
     RECT  56.704 33.648 57.089 35.352 ;
     RECT  56.704 23.904 57.197 32.184 ;
     RECT  56.909 43.296 57.197 43.608 ;
     RECT  56.819 47.472 57.233 53.496 ;
     RECT  56.243 64.56 57.253 64.776 ;
     RECT  56.819 57.888 57.265 63.288 ;
     RECT  57.253 64.512 57.265 64.776 ;
     RECT  57.197 23.904 57.377 27.768 ;
     RECT  56.704 45.408 57.413 46.248 ;
     RECT  56.819 54.48 57.484 56.472 ;
     RECT  56.704 5.52 57.557 6.648 ;
     RECT  56.704 7.68 57.557 14.904 ;
     RECT  57.377 25.008 57.557 27.768 ;
     RECT  57.265 57.888 57.629 64.776 ;
     RECT  56.704 17.088 57.635 18.792 ;
     RECT  56.704 19.776 57.635 21.24 ;
     RECT  57.635 20.304 57.673 21.24 ;
     RECT  57.629 59.184 57.683 64.776 ;
     RECT  57.673 20.304 57.809 21 ;
     RECT  57.557 6.624 57.841 6.648 ;
     RECT  57.557 7.68 57.841 14.136 ;
     RECT  57.683 59.184 57.845 60.696 ;
     RECT  57.841 6.624 57.953 14.136 ;
     RECT  57.197 29.28 57.953 32.184 ;
     RECT  57.635 17.088 57.989 17.208 ;
     RECT  56.704 36.528 58.021 40.104 ;
     RECT  56.909 41.664 58.021 41.928 ;
     RECT  57.197 43.296 58.093 43.56 ;
     RECT  56.704 4.08 58.117 4.104 ;
     RECT  58.117 3.408 58.163 4.104 ;
     RECT  57.953 6.624 58.205 11.784 ;
     RECT  57.629 57.888 58.277 57.912 ;
     RECT  57.557 26.592 58.453 27.768 ;
     RECT  57.953 29.28 58.453 31.464 ;
     RECT  57.557 5.52 58.493 5.544 ;
     RECT  58.453 26.592 58.529 31.464 ;
     RECT  57.413 45.984 58.529 46.248 ;
     RECT  57.845 60.336 58.529 60.696 ;
     RECT  57.377 23.904 58.597 23.928 ;
     RECT  57.557 25.008 58.597 25.464 ;
     RECT  57.089 33.888 58.633 35.352 ;
     RECT  58.021 36.528 58.633 41.928 ;
     RECT  58.093 43.104 58.633 43.56 ;
     RECT  57.809 20.304 58.637 20.52 ;
     RECT  58.633 33.888 58.643 43.56 ;
     RECT  57.233 47.472 58.652 53.448 ;
     RECT  57.484 55.008 58.652 56.472 ;
     RECT  58.652 47.472 58.669 56.472 ;
     RECT  57.683 62.4 58.705 64.776 ;
     RECT  58.669 47.328 58.739 56.472 ;
     RECT  58.417 19.2 58.781 19.224 ;
     RECT  58.205 11.76 58.817 11.784 ;
     RECT  58.529 60.336 58.817 60.36 ;
     RECT  58.705 62.352 58.817 64.776 ;
     RECT  58.837 21.648 58.849 21.672 ;
     RECT  56.704 22.704 58.849 22.728 ;
     RECT  58.817 62.352 58.861 64.68 ;
     RECT  57.877 44.976 58.921 45 ;
     RECT  58.529 45.984 58.921 46.104 ;
     RECT  58.861 62.352 58.931 63.912 ;
     RECT  56.945 1.728 58.961 2.328 ;
     RECT  58.849 21.648 58.961 22.728 ;
     RECT  57.953 13.296 58.993 14.136 ;
     RECT  58.643 33.888 58.993 39.288 ;
     RECT  58.643 40.608 59.069 43.56 ;
     RECT  58.961 22.704 59.173 22.728 ;
     RECT  58.597 23.904 59.173 25.464 ;
     RECT  59.173 17.616 59.209 17.64 ;
     RECT  59.173 22.704 59.209 25.464 ;
     RECT  58.529 26.592 59.209 31.416 ;
     RECT  58.921 44.976 59.209 46.104 ;
     RECT  58.961 1.728 59.213 1.992 ;
     RECT  59.209 22.704 59.213 31.416 ;
     RECT  59.213 1.728 59.249 1.848 ;
     RECT  59.209 17.424 59.269 17.64 ;
     RECT  58.201 16.224 59.281 16.248 ;
     RECT  59.269 17.424 59.281 18.216 ;
     RECT  59.249 1.824 59.285 1.848 ;
     RECT  58.993 33.552 59.285 39.288 ;
     RECT  59.069 40.608 59.321 43.128 ;
     RECT  59.321 40.608 59.356 42.12 ;
     RECT  58.205 6.624 59.389 10.536 ;
     RECT  59.321 43.104 59.429 43.128 ;
     RECT  58.739 47.328 59.465 55.896 ;
     RECT  59.389 6.144 59.497 10.536 ;
     RECT  59.213 23.376 59.573 31.416 ;
     RECT  59.497 6.144 59.603 10.824 ;
     RECT  58.993 11.904 59.603 14.136 ;
     RECT  57.845 59.184 59.605 59.304 ;
     RECT  59.603 12.24 59.653 14.136 ;
     RECT  59.605 15.216 59.653 15.24 ;
     RECT  58.163 3.408 59.713 3.432 ;
     RECT  59.465 50.688 59.753 55.896 ;
     RECT  59.029 20.88 59.785 21.096 ;
     RECT  59.573 23.376 59.825 30.936 ;
     RECT  59.753 53.376 59.825 55.896 ;
     RECT  59.605 57.6 59.825 59.304 ;
     RECT  59.356 40.608 59.857 41.928 ;
     RECT  59.825 53.664 59.861 55.896 ;
     RECT  59.825 23.376 59.897 27.816 ;
     RECT  59.857 40.464 59.897 41.928 ;
     RECT  59.861 53.808 59.897 55.896 ;
     RECT  59.825 57.6 59.897 58.584 ;
     RECT  59.852 32.448 59.939 32.472 ;
     RECT  58.931 62.736 59.941 63.912 ;
     RECT  59.713 3.312 59.987 3.432 ;
     RECT  59.285 33.552 60.001 35.256 ;
     RECT  59.653 12.24 60.005 15.24 ;
     RECT  59.897 53.808 60.005 53.832 ;
     RECT  59.897 55.008 60.005 55.896 ;
     RECT  59.209 44.448 60.037 46.104 ;
     RECT  59.465 47.328 60.037 49.608 ;
     RECT  59.603 6.144 60.041 10.2 ;
     RECT  59.785 20.592 60.073 21.096 ;
     RECT  59.825 28.896 60.077 30.936 ;
     RECT  59.929 60.48 60.173 60.504 ;
     RECT  60.073 20.592 60.181 21.192 ;
     RECT  59.897 40.464 60.185 40.824 ;
     RECT  60.041 6.144 60.221 9.912 ;
     RECT  60.005 13.104 60.221 15.24 ;
     RECT  59.897 24.336 60.221 27.816 ;
     RECT  59.941 62.736 60.227 64.632 ;
     RECT  60.221 13.296 60.253 15.24 ;
     RECT  59.281 16.224 60.253 18.216 ;
     RECT  60.173 60.384 60.253 60.504 ;
     RECT  60.253 60.384 60.257 61.032 ;
     RECT  60.221 6.144 60.293 9.624 ;
     RECT  60.221 24.336 60.293 25.128 ;
     RECT  60.227 62.736 60.325 63.864 ;
     RECT  60.253 13.296 60.329 18.216 ;
     RECT  60.293 6.144 60.365 9.576 ;
     RECT  60.005 55.872 60.365 55.896 ;
     RECT  59.897 58.56 60.371 58.584 ;
     RECT  60.284 60 60.371 60.024 ;
     RECT  60.257 61.008 60.371 61.032 ;
     RECT  60.365 6.144 60.373 9.192 ;
     RECT  60.037 44.448 60.401 49.608 ;
     RECT  60.325 62.64 60.409 63.864 ;
     RECT  60.373 5.424 60.419 9.192 ;
     RECT  59.285 36.24 60.437 39.288 ;
     RECT  60.221 26.592 60.467 27.816 ;
     RECT  60.38 61.584 60.467 61.608 ;
     RECT  60.181 20.592 60.469 21.816 ;
     RECT  60.419 6.48 60.473 9.192 ;
     RECT  60.329 14.016 60.473 18.216 ;
     RECT  60.293 24.336 60.473 24.36 ;
     RECT  60.467 26.592 60.473 27.768 ;
     RECT  59.897 41.904 60.545 41.928 ;
     RECT  60.401 44.688 60.545 49.608 ;
     RECT  60.473 14.016 60.563 15.864 ;
     RECT  60.563 14.352 60.581 15.864 ;
     RECT  60.581 14.352 60.589 15.432 ;
     RECT  60.473 6.768 60.617 9.192 ;
     RECT  60.185 40.464 60.653 40.632 ;
     RECT  59.987 3.408 60.685 3.432 ;
     RECT  60.469 20.592 60.685 22.008 ;
     RECT  60.685 3.408 60.689 3.96 ;
     RECT  60.589 14.352 60.689 15.24 ;
     RECT  60.545 46.8 60.757 49.608 ;
     RECT  59.753 50.688 60.757 51.48 ;
     RECT  60.685 20.592 60.829 22.728 ;
     RECT  60.473 17.088 60.901 18.216 ;
     RECT  60.409 63.216 60.947 63.864 ;
     RECT  60.947 63.216 60.977 63.24 ;
     RECT  60.901 17.088 61.004 18.792 ;
     RECT  61.004 17.088 61.045 18.888 ;
     RECT  60.829 20.496 61.045 22.728 ;
     RECT  60.077 28.896 61.225 30.12 ;
     RECT  60.793 31.392 61.225 31.416 ;
     RECT  61.045 17.088 61.621 22.728 ;
     RECT  61.585 10.704 61.729 10.728 ;
     RECT  60.689 3.936 61.808 3.96 ;
     RECT  60.419 5.424 61.808 5.448 ;
     RECT  60.617 6.768 61.808 6.84 ;
     RECT  60.617 8.496 61.808 9.192 ;
     RECT  61.729 10.704 61.808 10.92 ;
     RECT  61.549 12.336 61.808 12.36 ;
     RECT  60.689 14.352 61.808 14.376 ;
     RECT  61.621 16.08 61.808 22.728 ;
     RECT  60.473 26.592 61.808 27.624 ;
     RECT  61.225 28.896 61.808 31.416 ;
     RECT  60.001 33.072 61.808 35.256 ;
     RECT  60.437 36.864 61.808 39.288 ;
     RECT  60.653 40.464 61.808 40.488 ;
     RECT  60.545 44.688 61.808 45.72 ;
     RECT  60.757 46.8 61.808 51.48 ;
     RECT  61.808 2.148 61.912 62.652 ;
     RECT  61.912 2.418 62.104 62.382 ;
     RECT  62.104 16.368 62.165 19.56 ;
     RECT  62.104 29.568 62.309 29.592 ;
     RECT  62.104 34.416 62.309 38.136 ;
     RECT  62.104 14.208 62.345 15.096 ;
     RECT  62.104 25.68 62.353 26.664 ;
     RECT  62.104 21.12 62.381 21.144 ;
     RECT  62.104 22.224 62.417 22.248 ;
     RECT  62.345 14.208 62.705 14.232 ;
     RECT  62.104 6.96 63.097 11.208 ;
     RECT  62.104 12.24 63.097 12.552 ;
     RECT  63.097 6.96 63.241 12.552 ;
     RECT  62.309 35.376 63.241 38.136 ;
     RECT  62.165 16.368 63.277 18.888 ;
     RECT  63.241 6.96 63.745 12.744 ;
     RECT  63.745 6.96 63.817 12.936 ;
     RECT  63.277 16.176 63.817 18.888 ;
     RECT  62.104 42.192 63.817 51.24 ;
     RECT  63.241 35.376 63.853 38.28 ;
     RECT  62.353 26.064 64.645 26.664 ;
     RECT  64.645 26.064 64.757 26.76 ;
     RECT  63.817 6.864 64.764 12.936 ;
     RECT  63.817 16.08 64.764 19.08 ;
     RECT  64.757 26.064 64.764 26.664 ;
     RECT  63.853 35.28 64.764 38.28 ;
     RECT  63.817 42.192 64.764 51.336 ;
    LAYER M5 ;
     RECT  3.792 0.016 11.592 0.131 ;
     RECT  32.208 0.016 57.48 0.611 ;
     RECT  13.008 0.016 16.008 1.043 ;
     RECT  32.208 0.611 38.088 1.139 ;
     RECT  32.208 1.139 37.896 1.187 ;
     RECT  13.008 1.043 15.912 1.763 ;
     RECT  19.92 0.016 29.064 1.763 ;
     RECT  32.4 1.187 37.608 1.763 ;
     RECT  3.888 0.131 11.592 1.811 ;
     RECT  13.104 1.763 15.816 1.811 ;
     RECT  27.024 1.763 29.064 1.811 ;
     RECT  3.888 1.811 10.92 1.859 ;
     RECT  37.488 1.763 37.608 1.859 ;
     RECT  3.888 1.859 10.632 1.907 ;
     RECT  37.584 1.859 37.608 1.907 ;
     RECT  39.216 0.611 57.48 1.907 ;
     RECT  44.4 1.907 55.08 1.955 ;
     RECT  56.112 1.907 57.48 2.051 ;
     RECT  2.4 2.137 2.52 2.151 ;
     RECT  18.6 2.137 18.72 2.151 ;
     RECT  29.4 2.137 29.52 2.151 ;
     RECT  61.8 2.137 61.92 2.151 ;
     RECT  20.4 1.763 20.424 2.195 ;
     RECT  32.4 1.763 35.208 2.243 ;
     RECT  18.6 2.151 18.912 2.245 ;
     RECT  3.888 1.907 10.536 2.291 ;
     RECT  27.216 1.811 27.912 2.291 ;
     RECT  32.4 2.243 33.768 2.291 ;
     RECT  44.784 1.955 48.456 2.291 ;
     RECT  56.112 2.051 57 2.291 ;
     RECT  39.216 1.907 43.272 2.339 ;
     RECT  44.784 2.291 46.248 2.339 ;
     RECT  56.4 2.291 57 2.339 ;
     RECT  39.312 2.339 43.272 2.387 ;
     RECT  45.168 2.339 46.248 2.387 ;
     RECT  45.264 2.387 46.248 2.531 ;
     RECT  49.776 1.955 55.08 2.531 ;
     RECT  47.28 2.291 47.976 2.723 ;
     RECT  50.112 2.531 55.08 2.771 ;
     RECT  13.104 1.811 15.336 2.821 ;
     RECT  34.8 2.243 35.208 2.821 ;
     RECT  36.432 1.763 36.456 2.821 ;
     RECT  47.952 2.723 47.976 2.867 ;
     RECT  54.864 2.771 55.08 2.867 ;
     RECT  4.992 2.291 9.48 2.915 ;
     RECT  23.664 1.763 25.512 2.915 ;
     RECT  34.8 2.821 36.744 2.915 ;
     RECT  39.6 2.387 43.272 2.915 ;
     RECT  45.6 2.531 46.248 2.915 ;
     RECT  50.112 2.771 53.544 2.915 ;
     RECT  55.056 2.867 55.08 2.917 ;
     RECT  43.248 2.915 43.272 2.963 ;
     RECT  55.056 2.917 55.176 2.963 ;
     RECT  13.104 2.821 15.72 3.061 ;
     RECT  21.504 1.763 22.536 3.205 ;
     RECT  23.664 2.915 25.224 3.205 ;
     RECT  50.112 2.915 51.624 3.395 ;
     RECT  4.992 2.915 8.664 3.443 ;
     RECT  21.504 3.205 25.224 3.443 ;
     RECT  39.6 2.915 40.512 3.443 ;
     RECT  22.992 3.443 25.224 3.925 ;
     RECT  40.2 3.443 40.512 3.925 ;
     RECT  41.568 2.915 42.264 3.925 ;
     RECT  61.8 2.151 62.112 3.925 ;
     RECT  58.128 3.397 58.152 4.115 ;
     RECT  52.752 2.915 52.776 4.165 ;
     RECT  52.752 4.165 52.968 4.451 ;
     RECT  45.6 2.915 45.912 4.501 ;
     RECT  26.832 3.685 26.856 4.547 ;
     RECT  16.992 2.773 17.016 4.645 ;
     RECT  16.992 4.645 17.208 4.691 ;
     RECT  18.48 2.245 18.912 4.691 ;
     RECT  50.112 3.395 51.312 4.693 ;
     RECT  54.144 4.357 54.168 4.741 ;
     RECT  55.152 2.963 55.176 4.741 ;
     RECT  5.088 3.443 8.664 5.029 ;
     RECT  11.376 3.301 11.4 5.029 ;
     RECT  12.528 3.061 15.72 5.029 ;
     RECT  36.72 2.915 36.744 5.029 ;
     RECT  50.112 4.693 52.296 5.075 ;
     RECT  18.6 4.691 18.912 5.077 ;
     RECT  21.504 3.443 21.528 5.077 ;
     RECT  22.992 3.925 25.512 5.077 ;
     RECT  34.8 2.915 35.496 5.077 ;
     RECT  29.4 2.151 29.712 5.125 ;
     RECT  11.376 5.029 15.72 5.171 ;
     RECT  43.824 4.501 43.848 5.219 ;
     RECT  59.952 3.301 59.976 5.413 ;
     RECT  60.96 3.925 62.112 5.413 ;
     RECT  59.952 5.413 62.112 5.459 ;
     RECT  50.736 5.075 52.296 5.557 ;
     RECT  40.2 3.925 42.264 5.701 ;
     RECT  54.144 4.741 55.176 5.747 ;
     RECT  12.96 5.171 15.72 5.891 ;
     RECT  38.88 5.365 38.904 5.939 ;
     RECT  4.464 5.029 8.664 5.987 ;
     RECT  4.464 5.987 5.112 5.989 ;
     RECT  4.032 5.989 5.112 6.035 ;
     RECT  36.72 5.029 37.08 6.035 ;
     RECT  32.976 3.973 33 6.181 ;
     RECT  50.736 5.557 52.488 6.275 ;
     RECT  56.4 2.339 56.712 6.277 ;
     RECT  5.088 6.035 5.112 6.323 ;
     RECT  11.376 5.171 11.832 6.323 ;
     RECT  34.704 5.077 35.688 6.421 ;
     RECT  36.72 6.035 36.744 6.421 ;
     RECT  11.376 6.323 11.4 6.467 ;
     RECT  54.72 5.747 55.176 6.467 ;
     RECT  21.504 5.077 25.512 6.563 ;
     RECT  32.832 6.181 33 6.563 ;
     RECT  48.96 6.229 48.984 6.709 ;
     RECT  61.8 5.459 62.112 6.757 ;
     RECT  59.952 5.459 60.408 6.805 ;
     RECT  61.44 6.757 62.112 6.805 ;
     RECT  45.6 4.501 46.584 6.851 ;
     RECT  40.08 5.701 42.264 6.899 ;
     RECT  26.832 6.229 26.856 6.947 ;
     RECT  32.832 6.563 32.856 6.997 ;
     RECT  32.496 6.997 32.856 7.043 ;
     RECT  21.504 6.563 21.528 7.045 ;
     RECT  59.952 6.805 62.112 7.045 ;
     RECT  40.08 6.899 42.216 7.091 ;
     RECT  59.856 7.045 62.112 7.091 ;
     RECT  56.304 6.277 56.712 7.139 ;
     RECT  4.032 6.035 4.056 7.237 ;
     RECT  13.2 5.891 15.72 7.379 ;
     RECT  4.032 7.237 4.776 7.381 ;
     RECT  6.48 5.987 8.664 7.381 ;
     RECT  10.944 7.189 10.968 7.381 ;
     RECT  22.992 6.563 25.512 7.381 ;
     RECT  17.184 4.691 17.208 7.475 ;
     RECT  48.96 6.709 49.08 7.475 ;
     RECT  29.4 5.125 30.456 7.571 ;
     RECT  13.2 7.379 14.232 7.621 ;
     RECT  29.4 7.571 29.832 7.765 ;
     RECT  13.104 7.621 14.232 7.907 ;
     RECT  2.4 2.151 2.712 7.909 ;
     RECT  15.312 7.379 15.72 7.957 ;
     RECT  34.704 6.421 36.744 7.957 ;
     RECT  50.88 6.275 52.488 7.957 ;
     RECT  18.6 5.077 19.032 8.003 ;
     RECT  21.456 7.045 21.528 8.003 ;
     RECT  34.704 7.957 37.608 8.003 ;
     RECT  48.96 7.475 48.984 8.003 ;
     RECT  40.08 7.091 41.592 8.051 ;
     RECT  36.576 8.003 37.608 8.197 ;
     RECT  38.88 8.005 38.904 8.243 ;
     RECT  43.968 6.805 43.992 8.243 ;
     RECT  10.608 7.381 10.968 8.245 ;
     RECT  40.08 8.051 40.512 8.245 ;
     RECT  59.856 7.091 59.976 8.245 ;
     RECT  2.4 7.909 3 8.293 ;
     RECT  4.032 7.381 8.664 8.293 ;
     RECT  28.512 7.765 29.832 8.339 ;
     RECT  45.6 6.851 45.912 8.437 ;
     RECT  10.608 8.245 11.544 8.485 ;
     RECT  42.672 8.245 42.696 8.485 ;
     RECT  50.112 7.957 52.488 8.533 ;
     RECT  32.496 7.043 32.52 8.675 ;
     RECT  0.144 8.629 0.168 8.819 ;
     RECT  13.2 7.907 14.232 8.821 ;
     RECT  22.992 7.381 26.472 8.821 ;
     RECT  28.512 8.339 29.712 8.867 ;
     RECT  13.2 8.821 14.328 8.869 ;
     RECT  2.4 8.293 8.664 9.011 ;
     RECT  54.864 6.467 55.176 9.107 ;
     RECT  36.576 8.197 37.752 9.155 ;
     RECT  34.704 8.003 35.544 9.203 ;
     RECT  42.576 8.485 42.696 9.251 ;
     RECT  59.664 8.245 59.976 9.251 ;
     RECT  56.4 7.139 56.712 9.301 ;
     RECT  44.16 8.437 45.912 9.349 ;
     RECT  42.912 9.445 42.936 9.493 ;
     RECT  44.16 9.349 46.728 9.493 ;
     RECT  2.4 9.011 4.056 9.539 ;
     RECT  42.912 9.493 46.728 9.539 ;
     RECT  34.8 9.203 35.544 9.589 ;
     RECT  36.576 9.155 36.744 9.589 ;
     RECT  42.912 9.539 45.912 9.635 ;
     RECT  10.032 8.485 11.544 9.637 ;
     RECT  13.104 8.869 14.328 9.637 ;
     RECT  21.504 8.003 21.528 9.637 ;
     RECT  22.992 8.821 26.808 9.731 ;
     RECT  31.344 8.821 31.368 9.731 ;
     RECT  50.112 8.533 52.536 9.731 ;
     RECT  54.864 9.107 55.08 9.973 ;
     RECT  15.312 7.957 16.536 10.067 ;
     RECT  21.504 9.637 21.624 10.165 ;
     RECT  22.992 9.731 24.6 10.165 ;
     RECT  29.4 8.867 29.712 10.165 ;
     RECT  33.36 9.061 33.384 10.213 ;
     RECT  61.344 7.091 62.112 10.213 ;
     RECT  34.8 9.589 36.744 10.261 ;
     RECT  37.728 9.155 37.752 10.261 ;
     RECT  21.504 10.165 24.6 10.309 ;
     RECT  51 9.731 52.536 10.357 ;
     RECT  33.36 10.213 33.624 10.403 ;
     RECT  54.528 9.973 55.08 10.501 ;
     RECT  26.448 9.731 26.808 10.595 ;
     RECT  56.4 9.301 57.336 10.645 ;
     RECT  61.344 10.213 62.28 10.693 ;
     RECT  20.064 6.181 20.088 10.789 ;
     RECT  21.36 10.309 24.6 10.789 ;
     RECT  59.664 9.251 59.88 10.789 ;
     RECT  20.064 10.789 25.224 10.835 ;
     RECT  5.088 9.011 8.664 10.883 ;
     RECT  10.032 9.637 14.328 10.883 ;
     RECT  20.064 10.835 21.624 10.883 ;
     RECT  43.296 9.635 44.184 10.883 ;
     RECT  10.032 10.883 14.28 10.979 ;
     RECT  39.552 8.245 40.512 11.125 ;
     RECT  41.568 8.051 41.592 11.125 ;
     RECT  49.296 10.069 49.32 11.171 ;
     RECT  51 10.357 52.776 11.171 ;
     RECT  2.4 9.539 3.864 11.173 ;
     RECT  34.8 10.261 37.752 11.173 ;
     RECT  54.528 10.501 55.224 11.221 ;
     RECT  1.68 11.173 3.864 11.315 ;
     RECT  10.032 10.979 14.232 11.365 ;
     RECT  22.992 10.835 25.224 11.413 ;
     RECT  26.448 10.595 26.472 11.413 ;
     RECT  22.992 11.413 26.472 11.459 ;
     RECT  33.6 10.403 33.624 11.459 ;
     RECT  54.144 11.221 55.224 11.459 ;
     RECT  56.4 10.645 57.624 11.459 ;
     RECT  44.16 10.883 44.184 11.461 ;
     RECT  45.6 9.635 45.912 11.461 ;
     RECT  5.616 10.883 8.664 11.509 ;
     RECT  9.792 11.365 14.232 11.509 ;
     RECT  5.616 11.509 14.232 11.651 ;
     RECT  44.16 11.461 45.912 11.653 ;
     RECT  54.144 11.459 55.08 11.653 ;
     RECT  53.808 11.653 55.08 11.795 ;
     RECT  44.16 11.653 46.776 11.797 ;
     RECT  29.4 10.165 29.976 11.843 ;
     RECT  22.992 11.459 24.696 11.939 ;
     RECT  31.2 10.213 31.224 11.987 ;
     RECT  44.16 11.797 47.352 12.035 ;
     RECT  20.064 10.883 21.576 12.275 ;
     RECT  51 11.171 52.488 12.373 ;
     RECT  20.064 12.275 20.856 12.467 ;
     RECT  50.64 12.373 52.488 12.469 ;
     RECT  39.552 11.125 41.592 12.517 ;
     RECT  17.04 11.509 17.064 12.563 ;
     RECT  22.992 11.939 24.6 12.611 ;
     RECT  20.064 12.467 20.088 12.899 ;
     RECT  50.592 12.469 52.488 13.043 ;
     RECT  54.144 11.795 55.08 13.139 ;
     RECT  59.568 10.789 59.88 13.187 ;
     RECT  55.056 13.139 55.08 13.285 ;
     RECT  56.4 11.459 57.336 13.285 ;
     RECT  15.312 10.067 15.72 13.381 ;
     RECT  39.552 12.517 41.688 13.621 ;
     RECT  23.088 12.611 24.6 13.715 ;
     RECT  25.824 11.459 26.472 13.811 ;
     RECT  59.664 13.187 59.88 14.005 ;
     RECT  61.344 10.693 62.376 14.005 ;
     RECT  5.616 11.651 11.784 14.053 ;
     RECT  12.768 11.651 14.232 14.053 ;
     RECT  2.4 11.315 3.864 14.197 ;
     RECT  5.616 14.053 14.232 14.197 ;
     RECT  48.48 13.573 48.504 14.291 ;
     RECT  45.6 12.035 47.352 14.387 ;
     RECT  34.704 11.173 37.752 14.773 ;
     RECT  38.736 13.621 41.688 14.773 ;
     RECT  26.448 13.811 26.472 14.821 ;
     RECT  34.704 14.773 41.688 14.821 ;
     RECT  44.16 12.035 44.184 14.831 ;
     RECT  2.4 14.197 14.232 14.867 ;
     RECT  45.6 14.387 46.968 14.867 ;
     RECT  55.056 13.285 57.336 14.867 ;
     RECT  59.664 14.005 62.376 14.867 ;
     RECT  56.304 14.867 57.336 14.915 ;
     RECT  23.904 13.715 24.456 14.963 ;
     RECT  44.112 14.831 44.184 15.011 ;
     RECT  34.704 14.821 42.168 15.251 ;
     RECT  59.856 14.867 62.376 15.443 ;
     RECT  15.312 13.381 16.584 15.491 ;
     RECT  18.6 8.003 18.912 15.541 ;
     RECT  26.448 14.821 26.664 15.683 ;
     RECT  29.4 11.843 29.712 15.829 ;
     RECT  41.568 15.251 42.168 16.019 ;
     RECT  53.904 15.349 53.928 16.019 ;
     RECT  44.16 15.011 44.184 16.261 ;
     RECT  49.584 15.637 49.608 16.403 ;
     RECT  18.48 15.541 18.912 16.405 ;
     RECT  26.592 15.683 26.664 16.787 ;
     RECT  2.4 14.867 3.864 16.933 ;
     RECT  43.872 16.261 44.184 17.077 ;
     RECT  56.304 14.915 56.712 17.077 ;
     RECT  59.856 15.443 59.88 17.077 ;
     RECT  61.344 15.443 62.376 17.077 ;
     RECT  29.4 15.829 29.832 17.123 ;
     RECT  18.48 16.405 19.416 17.125 ;
     RECT  26.592 16.787 26.616 17.219 ;
     RECT  56.304 17.077 57 17.219 ;
     RECT  18.48 17.125 20.328 17.315 ;
     RECT  41.568 16.019 41.592 17.365 ;
     RECT  43.008 17.077 44.184 17.365 ;
     RECT  45.6 14.867 45.912 17.365 ;
     RECT  34.704 15.251 40.512 17.411 ;
     RECT  41.568 17.365 45.912 17.411 ;
     RECT  59.856 17.077 62.376 17.411 ;
     RECT  15.312 15.491 15.72 17.605 ;
     RECT  59.856 17.411 59.88 17.605 ;
     RECT  48.24 16.309 48.264 17.653 ;
     RECT  48.24 17.653 48.744 17.891 ;
     RECT  32.208 17.605 32.232 17.989 ;
     RECT  36.576 17.411 40.512 17.989 ;
     RECT  41.568 17.411 43.032 17.989 ;
     RECT  56.4 17.219 57 17.989 ;
     RECT  36.576 17.989 43.032 18.131 ;
     RECT  24 14.963 24.456 18.133 ;
     RECT  16.992 16.645 17.016 18.227 ;
     RECT  59.28 17.605 59.88 18.227 ;
     RECT  48.72 17.891 48.744 18.275 ;
     RECT  44.16 17.411 45.912 18.419 ;
     RECT  18.6 17.315 20.328 18.565 ;
     RECT  5.616 14.867 14.232 18.613 ;
     RECT  15.312 17.605 15.96 18.613 ;
     RECT  5.616 18.613 15.96 18.709 ;
     RECT  46.944 14.867 46.968 18.709 ;
     RECT  55.056 14.867 55.08 18.709 ;
     RECT  5.472 18.709 15.96 18.755 ;
     RECT  39.552 18.131 43.032 18.755 ;
     RECT  2.4 16.933 4.104 18.757 ;
     RECT  18.192 18.565 20.328 18.803 ;
     RECT  36.576 18.131 38.472 18.805 ;
     RECT  23.568 18.133 24.456 18.851 ;
     RECT  61.344 17.411 62.376 18.853 ;
     RECT  36.336 18.805 38.472 18.947 ;
     RECT  29.4 17.123 29.712 19.045 ;
     RECT  51 13.043 52.488 19.093 ;
     RECT  26.256 17.653 26.28 19.235 ;
     RECT  42.72 18.755 43.032 19.283 ;
     RECT  15.312 18.755 15.96 19.333 ;
     RECT  46.944 18.709 47.16 19.333 ;
     RECT  19.92 18.803 20.328 19.427 ;
     RECT  54.144 18.709 55.08 19.427 ;
     RECT  31.056 19.333 31.08 19.477 ;
     RECT  36.576 18.947 38.472 19.477 ;
     RECT  39.552 18.755 41.592 19.477 ;
     RECT  32.208 17.989 33.096 19.523 ;
     RECT  61.056 18.853 62.376 19.763 ;
     RECT  18.192 18.803 18.912 19.909 ;
     RECT  36.576 19.477 41.592 20.003 ;
     RECT  50.544 19.093 52.488 20.003 ;
     RECT  45.6 18.419 45.912 20.149 ;
     RECT  46.944 19.333 47.928 20.149 ;
     RECT  5.472 18.755 14.28 20.243 ;
     RECT  45.6 20.149 47.928 20.389 ;
     RECT  2.4 18.757 4.2 20.485 ;
     RECT  5.472 20.243 14.232 20.485 ;
     RECT  44.16 18.419 44.184 20.485 ;
     RECT  22.32 15.925 22.344 20.533 ;
     RECT  33.072 19.523 33.096 20.579 ;
     RECT  31.056 19.477 31.176 20.675 ;
     RECT  36.576 20.003 38.472 20.723 ;
     RECT  45.6 20.389 48.696 20.819 ;
     RECT  28.08 19.237 28.104 20.867 ;
     RECT  24 18.851 24.456 20.917 ;
     RECT  59.856 18.227 59.88 20.917 ;
     RECT  61.344 19.763 62.376 20.917 ;
     RECT  48.672 20.819 48.696 21.059 ;
     RECT  39.552 20.003 41.592 21.107 ;
     RECT  45.6 20.819 47.256 21.107 ;
     RECT  21.744 20.533 22.344 21.155 ;
     RECT  56.4 17.989 57.624 21.251 ;
     RECT  24 20.917 24.504 21.397 ;
     RECT  17.904 19.909 18.912 21.445 ;
     RECT  20.304 19.427 20.328 21.445 ;
     RECT  36.576 20.723 36.744 21.493 ;
     RECT  36.48 21.493 36.744 21.683 ;
     RECT  39.552 21.107 40.512 21.683 ;
     RECT  23.376 21.397 24.504 21.779 ;
     RECT  2.4 20.485 14.232 21.973 ;
     RECT  15.312 19.333 16.584 21.973 ;
     RECT  17.904 21.445 20.328 22.021 ;
     RECT  2.4 21.973 16.584 22.067 ;
     RECT  45.6 21.107 46.968 22.117 ;
     RECT  22.32 21.155 22.344 22.165 ;
     RECT  54.72 19.427 55.08 22.165 ;
     RECT  56.4 21.251 56.712 22.165 ;
     RECT  59.856 20.917 62.376 22.259 ;
     RECT  2.4 22.067 15.72 22.499 ;
     RECT  43.776 20.485 44.184 22.645 ;
     RECT  45.168 22.117 46.968 22.645 ;
     RECT  58.848 21.637 58.872 22.739 ;
     RECT  59.856 22.259 62.328 22.739 ;
     RECT  17.712 22.021 20.328 22.787 ;
     RECT  43.776 22.645 46.968 22.787 ;
     RECT  56.304 22.165 56.712 22.787 ;
     RECT  5.088 22.499 15.72 22.835 ;
     RECT  43.776 22.787 44.184 23.315 ;
     RECT  17.712 22.787 18.912 23.317 ;
     RECT  5.52 22.835 15.72 23.411 ;
     RECT  22.032 22.165 22.344 23.555 ;
     RECT  48.48 22.645 48.504 23.555 ;
     RECT  34.704 17.411 35.112 23.701 ;
     RECT  23.376 21.779 24.456 23.797 ;
     RECT  5.52 23.411 15.384 23.891 ;
     RECT  29.088 19.045 29.712 23.893 ;
     RECT  38.448 20.723 38.472 23.893 ;
     RECT  54.72 22.165 55.272 23.939 ;
     RECT  41.568 21.107 41.592 23.941 ;
     RECT  42.72 19.283 42.744 23.941 ;
     RECT  17.232 23.317 18.912 23.987 ;
     RECT  54.816 23.939 55.272 24.131 ;
     RECT  5.52 23.891 11.784 24.371 ;
     RECT  27.696 22.789 27.72 24.371 ;
     RECT  34.368 23.701 35.112 24.469 ;
     RECT  34.368 24.469 35.304 24.515 ;
     RECT  36.672 21.683 36.744 24.517 ;
     RECT  29.088 23.893 30.168 24.659 ;
     RECT  13.008 23.891 15.384 24.707 ;
     RECT  34.704 24.515 35.304 24.707 ;
     RECT  38.16 23.893 38.472 24.805 ;
     RECT  38.16 24.805 38.664 24.947 ;
     RECT  36.336 24.517 36.744 25.045 ;
     RECT  25.632 23.317 25.656 25.139 ;
     RECT  41.568 23.941 42.744 25.139 ;
     RECT  7.2 24.371 11.784 25.187 ;
     RECT  56.4 22.787 56.712 25.333 ;
     RECT  23.328 23.797 24.456 25.475 ;
     RECT  45.6 22.787 46.968 25.475 ;
     RECT  17.712 23.987 18.912 25.573 ;
     RECT  20.304 22.787 20.328 25.573 ;
     RECT  36.192 25.045 36.744 25.621 ;
     RECT  54.816 24.131 55.08 25.621 ;
     RECT  56.4 25.333 56.808 25.621 ;
     RECT  61.344 22.739 62.328 25.715 ;
     RECT  5.52 24.371 6.216 25.861 ;
     RECT  7.8 25.187 11.784 25.861 ;
     RECT  13.008 24.707 15.336 25.861 ;
     RECT  38.16 24.947 38.472 26.003 ;
     RECT  51 20.003 52.488 26.101 ;
     RECT  17.712 25.573 20.664 26.243 ;
     RECT  16.608 25.621 16.632 26.245 ;
     RECT  17.712 26.243 18.912 26.245 ;
     RECT  31.152 20.675 31.176 26.245 ;
     RECT  34.704 24.707 35.112 26.293 ;
     RECT  44.16 23.315 44.184 26.293 ;
     RECT  16.608 26.245 18.912 26.387 ;
     RECT  31.152 26.245 31.512 26.387 ;
     RECT  36.192 25.621 36.84 26.389 ;
     RECT  41.568 25.139 41.592 26.485 ;
     RECT  42.72 25.139 42.744 26.485 ;
     RECT  41.568 26.485 42.744 26.531 ;
     RECT  20.304 26.243 20.664 26.629 ;
     RECT  22.32 23.555 22.344 26.629 ;
     RECT  27.888 26.485 27.912 26.675 ;
     RECT  43.92 26.293 44.232 26.675 ;
     RECT  20.304 26.629 22.344 26.677 ;
     RECT  23.328 25.475 24.408 26.677 ;
     RECT  34.08 26.293 35.112 26.677 ;
     RECT  36.096 26.389 36.84 26.677 ;
     RECT  50.832 26.101 52.488 26.725 ;
     RECT  7.8 25.861 15.336 26.771 ;
     RECT  20.304 26.677 24.408 26.771 ;
     RECT  43.92 26.675 44.184 26.821 ;
     RECT  43.44 26.821 44.184 26.963 ;
     RECT  49.44 26.917 49.464 26.965 ;
     RECT  50.832 26.725 52.728 27.011 ;
     RECT  13.008 26.771 15.336 27.013 ;
     RECT  16.608 26.387 16.632 27.013 ;
     RECT  13.008 27.013 16.632 27.059 ;
     RECT  49.104 26.965 49.464 27.059 ;
     RECT  38.448 26.003 38.472 27.061 ;
     RECT  39.984 21.683 40.512 27.061 ;
     RECT  41.568 26.531 42.456 27.061 ;
     RECT  49.104 27.059 49.32 27.107 ;
     RECT  13.008 27.059 16.008 27.203 ;
     RECT  29.088 24.659 29.712 27.203 ;
     RECT  59.856 22.739 59.88 27.301 ;
     RECT  61.344 25.715 62.112 27.301 ;
     RECT  20.304 26.771 24.312 27.395 ;
     RECT  22.32 27.395 24.312 27.587 ;
     RECT  34.08 26.677 36.84 27.781 ;
     RECT  33.84 27.781 36.84 27.875 ;
     RECT  5.088 25.861 6.216 27.877 ;
     RECT  29.28 27.203 29.712 27.877 ;
     RECT  31.152 26.387 31.176 27.877 ;
     RECT  36.672 27.875 36.84 27.877 ;
     RECT  58.752 26.773 58.776 28.115 ;
     RECT  38.448 27.061 42.456 28.163 ;
     RECT  50.832 27.011 52.152 28.211 ;
     RECT  29.28 27.877 31.176 28.357 ;
     RECT  32.448 27.253 32.472 28.357 ;
     RECT  56.4 25.621 57.384 28.453 ;
     RECT  29.28 28.357 32.472 28.499 ;
     RECT  14.64 27.203 16.008 28.547 ;
     RECT  20.304 27.395 20.664 28.547 ;
     RECT  5.088 27.877 6.312 28.691 ;
     RECT  33.84 27.875 35.112 28.691 ;
     RECT  26.016 26.725 26.04 28.885 ;
     RECT  26.016 28.885 26.424 28.931 ;
     RECT  27.6 27.877 27.624 28.931 ;
     RECT  59.856 27.301 62.112 28.931 ;
     RECT  7.8 26.771 11.784 29.027 ;
     RECT  31.152 28.499 32.472 29.027 ;
     RECT  36.672 27.877 37.08 29.029 ;
     RECT  39.984 28.163 42.456 29.029 ;
     RECT  43.92 26.963 44.184 29.029 ;
     RECT  13.008 27.203 13.656 29.123 ;
     RECT  51 28.211 52.152 29.123 ;
     RECT  2.4 22.499 4.104 29.171 ;
     RECT  39.984 29.029 44.184 29.171 ;
     RECT  23.04 27.587 24.312 29.173 ;
     RECT  7.8 29.027 11.544 29.219 ;
     RECT  17.712 26.387 18.912 29.219 ;
     RECT  13.008 29.123 13.512 29.221 ;
     RECT  54.72 25.621 55.08 29.267 ;
     RECT  39.984 29.171 41.592 29.363 ;
     RECT  36.576 29.029 37.08 29.461 ;
     RECT  36.576 29.461 37.272 29.603 ;
     RECT  51 29.123 51.312 29.605 ;
     RECT  36.576 29.603 37.08 29.651 ;
     RECT  12.528 29.221 13.512 29.699 ;
     RECT  29.28 28.499 29.712 29.699 ;
     RECT  43.2 29.171 44.184 29.699 ;
     RECT  31.152 29.027 31.944 29.795 ;
     RECT  56.304 28.453 57.384 29.795 ;
     RECT  49.296 27.107 49.32 29.939 ;
     RECT  26.4 28.931 26.424 30.035 ;
     RECT  59.856 28.931 59.88 30.181 ;
     RECT  20.64 28.547 20.664 30.275 ;
     RECT  36.576 29.651 36.84 30.275 ;
     RECT  22.368 29.173 24.312 30.419 ;
     RECT  54.816 29.267 55.08 30.611 ;
     RECT  38.448 28.163 38.472 30.757 ;
     RECT  17.808 29.219 18.912 30.851 ;
     RECT  59.712 30.181 59.88 30.851 ;
     RECT  39.984 29.363 40.512 30.853 ;
     RECT  41.568 29.363 41.592 30.853 ;
     RECT  50.832 29.605 51.312 30.995 ;
     RECT  4.08 29.171 4.104 31.093 ;
     RECT  5.088 28.691 6.216 31.093 ;
     RECT  29.4 29.699 29.712 31.141 ;
     RECT  31.152 29.795 31.176 31.285 ;
     RECT  34.704 28.691 35.112 31.285 ;
     RECT  56.4 29.795 57.384 31.285 ;
     RECT  38.448 30.757 38.76 31.331 ;
     RECT  17.904 30.851 18.912 31.333 ;
     RECT  2.4 29.171 2.904 31.379 ;
     RECT  17.904 31.333 19.032 31.475 ;
     RECT  29.088 31.141 29.712 31.811 ;
     RECT  34.224 31.285 35.112 31.955 ;
     RECT  39.984 30.853 41.592 31.955 ;
     RECT  45.6 25.475 46.68 31.955 ;
     RECT  53.04 30.949 53.064 31.955 ;
     RECT  56.4 31.285 57.672 31.955 ;
     RECT  2.4 31.379 2.712 32.437 ;
     RECT  59.856 30.851 59.88 32.437 ;
     RECT  4.08 31.093 6.216 32.483 ;
     RECT  55.056 30.611 55.08 32.485 ;
     RECT  15.312 28.547 15.336 32.531 ;
     RECT  0.144 32.245 0.168 32.627 ;
     RECT  5.52 32.483 6.216 33.013 ;
     RECT  21.408 31.621 21.432 33.013 ;
     RECT  39.984 31.955 40.512 33.013 ;
     RECT  41.568 31.955 41.592 33.013 ;
     RECT  54.72 32.485 55.08 33.013 ;
     RECT  23.328 30.419 24.312 33.061 ;
     RECT  59.856 32.437 59.928 33.061 ;
     RECT  61.344 28.931 62.112 33.061 ;
     RECT  31.152 31.285 31.32 33.443 ;
     RECT  48.24 32.437 48.264 33.589 ;
     RECT  48.24 33.589 48.6 33.635 ;
     RECT  26.064 33.013 26.088 33.637 ;
     RECT  26.064 33.637 26.856 33.683 ;
     RECT  5.52 33.013 6.264 33.731 ;
     RECT  5.52 33.731 6.216 33.827 ;
     RECT  31.152 33.443 31.224 33.827 ;
     RECT  17.904 31.475 18.912 33.925 ;
     RECT  12.576 29.699 13.512 34.021 ;
     RECT  54.72 33.013 55.272 34.115 ;
     RECT  34.704 31.955 35.112 34.117 ;
     RECT  56.4 31.955 57.384 34.117 ;
     RECT  12.24 34.021 13.512 34.165 ;
     RECT  38.448 31.331 38.472 34.165 ;
     RECT  51 30.995 51.312 34.165 ;
     RECT  7.8 29.219 10.968 34.259 ;
     RECT  15.936 32.581 15.96 34.259 ;
     RECT  21.408 33.013 21.672 34.259 ;
     RECT  59.856 33.061 62.112 34.355 ;
     RECT  34.704 34.117 35.352 34.403 ;
     RECT  2.304 32.437 2.712 34.499 ;
     RECT  21.648 34.259 21.672 34.499 ;
     RECT  23.328 33.061 24.744 34.595 ;
     RECT  17.616 33.925 18.912 34.741 ;
     RECT  29.28 31.811 29.712 34.789 ;
     RECT  31.2 33.827 31.224 34.789 ;
     RECT  36.576 30.275 36.6 34.789 ;
     RECT  12.24 34.165 14.232 34.835 ;
     RECT  36.576 34.789 36.696 34.835 ;
     RECT  56.4 34.117 58.056 34.835 ;
     RECT  26.832 33.683 26.856 34.931 ;
     RECT  48.576 33.635 48.6 35.075 ;
     RECT  38.448 34.165 38.76 35.123 ;
     RECT  2.4 34.499 2.712 35.269 ;
     RECT  7.8 34.259 10.824 35.317 ;
     RECT  36.672 34.835 36.696 35.317 ;
     RECT  7.248 35.317 10.824 35.507 ;
     RECT  23.328 34.595 24.312 35.653 ;
     RECT  45.6 31.955 46.536 35.653 ;
     RECT  32.496 33.301 32.52 35.699 ;
     RECT  42.816 34.501 42.84 35.701 ;
     RECT  39.984 33.013 41.592 35.845 ;
     RECT  42.768 35.701 42.84 35.845 ;
     RECT  30.816 34.789 31.224 35.939 ;
     RECT  39.984 35.845 42.84 36.323 ;
     RECT  39.984 36.323 42.456 36.371 ;
     RECT  22.464 35.653 24.312 36.421 ;
     RECT  26.208 35.701 26.232 36.469 ;
     RECT  4.08 32.483 4.104 36.515 ;
     RECT  14.832 35.797 14.856 36.515 ;
     RECT  22.464 36.421 25.128 36.515 ;
     RECT  29.136 34.789 29.712 36.515 ;
     RECT  2.4 35.269 3 36.563 ;
     RECT  7.68 35.507 10.824 36.563 ;
     RECT  51 34.165 52.008 36.803 ;
     RECT  12.24 34.835 13.512 36.899 ;
     RECT  41.568 36.371 42.456 36.899 ;
     RECT  23.328 36.515 25.128 36.949 ;
     RECT  26.208 36.469 26.52 36.949 ;
     RECT  23.328 36.949 26.52 36.995 ;
     RECT  51 36.803 51.312 36.997 ;
     RECT  25.632 36.995 26.52 37.091 ;
     RECT  41.568 36.899 42.024 37.091 ;
     RECT  17.616 34.741 19.176 37.139 ;
     RECT  53.184 33.781 53.208 37.477 ;
     RECT  12.576 36.899 13.512 37.525 ;
     RECT  5.52 33.827 5.544 37.573 ;
     RECT  34.704 34.403 35.112 37.573 ;
     RECT  36.672 35.317 37.08 37.573 ;
     RECT  44.16 29.699 44.184 37.573 ;
     RECT  25.632 37.091 26.232 37.619 ;
     RECT  34.704 37.573 37.08 37.619 ;
     RECT  12.576 37.525 14.328 37.957 ;
     RECT  39.984 36.371 40.512 38.005 ;
     RECT  42 37.091 42.024 38.051 ;
     RECT  47.712 36.133 47.736 38.099 ;
     RECT  4.224 37.573 6.312 38.147 ;
     RECT  23.328 36.995 24.312 38.149 ;
     RECT  29.28 36.515 29.712 38.197 ;
     RECT  50.832 36.997 51.312 38.197 ;
     RECT  28.752 38.197 29.712 38.339 ;
     RECT  50.736 38.197 51.312 38.339 ;
     RECT  58.656 36.517 58.68 38.389 ;
     RECT  16.512 36.997 16.536 38.435 ;
     RECT  29.04 38.339 29.712 38.483 ;
     RECT  49.68 37.477 49.704 38.483 ;
     RECT  50.832 38.339 51.312 38.483 ;
     RECT  59.856 34.355 59.88 38.531 ;
     RECT  58.656 38.389 58.728 38.579 ;
     RECT  34.704 37.619 36.696 38.581 ;
     RECT  27.36 38.149 27.384 38.675 ;
     RECT  54.72 34.115 55.08 38.675 ;
     RECT  4.224 38.147 4.92 38.723 ;
     RECT  22.8 38.149 24.312 38.723 ;
     RECT  25.632 37.619 25.944 38.819 ;
     RECT  12.576 37.957 15.192 38.915 ;
     RECT  7.8 36.563 10.824 39.011 ;
     RECT  6.288 38.147 6.312 39.301 ;
     RECT  7.8 39.011 10.776 39.301 ;
     RECT  38.448 35.123 38.472 39.301 ;
     RECT  39.984 38.005 40.728 39.301 ;
     RECT  6.288 39.301 10.776 39.395 ;
     RECT  6.288 39.395 10.68 39.443 ;
     RECT  43.92 37.573 44.184 39.539 ;
     RECT  20.496 35.845 20.52 39.589 ;
     RECT  34.512 38.581 36.696 39.589 ;
     RECT  55.056 38.675 55.08 39.637 ;
     RECT  56.4 34.835 57.384 39.637 ;
     RECT  58.608 38.677 58.632 39.731 ;
     RECT  12.576 38.915 13.608 39.877 ;
     RECT  23.328 38.723 24.312 39.877 ;
     RECT  29.28 38.483 29.712 39.877 ;
     RECT  31.2 35.939 31.224 39.877 ;
     RECT  51 38.483 51.312 39.877 ;
     RECT  52.704 37.477 53.208 39.877 ;
     RECT  55.056 39.637 57.384 39.877 ;
     RECT  22.896 39.877 24.312 39.923 ;
     RECT  14.736 38.915 15.192 40.117 ;
     RECT  20.496 39.589 21.432 40.163 ;
     RECT  38.448 39.301 41.016 40.163 ;
     RECT  54.72 39.877 57.384 40.307 ;
     RECT  4.896 38.723 4.92 40.405 ;
     RECT  29.232 39.877 31.224 40.405 ;
     RECT  55.872 40.307 57.384 40.499 ;
     RECT  7.056 39.443 10.68 40.595 ;
     RECT  12.192 39.877 13.608 40.645 ;
     RECT  14.736 40.117 15.384 40.645 ;
     RECT  7.8 40.595 10.68 40.691 ;
     RECT  50.496 39.877 51.312 40.739 ;
     RECT  22.896 39.923 22.92 40.835 ;
     RECT  54.72 40.307 54.744 40.981 ;
     RECT  20.496 40.163 21.336 41.075 ;
     RECT  28.272 40.405 31.224 41.075 ;
     RECT  4.32 40.405 4.92 41.363 ;
     RECT  54.384 40.981 54.744 41.365 ;
     RECT  32.976 37.573 33 41.413 ;
     RECT  29.136 41.075 31.224 41.459 ;
     RECT  24 39.923 24.312 41.557 ;
     RECT  32.544 41.413 33 41.795 ;
     RECT  17.616 37.139 18.912 41.893 ;
     RECT  25.92 38.819 25.944 41.893 ;
     RECT  0.144 41.893 0.168 42.083 ;
     RECT  39.6 40.163 41.016 42.133 ;
     RECT  25.92 41.893 26.76 42.179 ;
     RECT  54.384 41.365 54.888 42.179 ;
     RECT  11.712 40.645 15.384 42.181 ;
     RECT  20.496 41.075 20.52 42.229 ;
     RECT  7.8 40.691 10.392 42.275 ;
     RECT  5.76 42.133 5.784 42.419 ;
     RECT  38.448 40.163 38.472 42.709 ;
     RECT  39.6 42.133 41.448 42.709 ;
     RECT  45.6 35.653 46.632 42.709 ;
     RECT  38.448 42.709 41.448 42.755 ;
     RECT  11.712 42.181 15.816 42.757 ;
     RECT  59.28 40.981 59.304 42.803 ;
     RECT  45.504 42.709 46.632 42.851 ;
     RECT  23.904 41.557 24.312 42.949 ;
     RECT  25.344 42.709 25.368 42.949 ;
     RECT  26.736 42.179 26.76 42.995 ;
     RECT  32.544 41.795 32.712 42.995 ;
     RECT  4.032 41.605 4.056 43.043 ;
     RECT  32.592 42.995 32.712 43.045 ;
     RECT  32.592 43.045 32.952 43.091 ;
     RECT  7.8 42.275 8.28 43.141 ;
     RECT  17.616 41.893 19.128 43.141 ;
     RECT  9.408 42.275 10.392 43.283 ;
     RECT  38.448 42.755 41.016 43.283 ;
     RECT  23.904 42.949 25.368 43.285 ;
     RECT  52.704 39.877 53.4 43.285 ;
     RECT  20.448 42.229 20.52 43.333 ;
     RECT  29.28 41.459 31.224 43.379 ;
     RECT  17.568 43.141 19.128 43.523 ;
     RECT  23.376 43.285 25.368 43.523 ;
     RECT  52.704 43.285 53.544 43.571 ;
     RECT  54.864 42.179 54.888 43.571 ;
     RECT  28.128 43.093 28.152 43.573 ;
     RECT  32.688 43.091 32.952 43.621 ;
     RECT  34.416 39.589 36.696 43.621 ;
     RECT  11.424 42.757 15.816 43.813 ;
     RECT  56.4 40.499 57.384 43.813 ;
     RECT  6.912 43.141 8.28 43.859 ;
     RECT  45.504 42.851 45.912 43.859 ;
     RECT  11.424 43.813 16.488 43.955 ;
     RECT  32.688 43.621 36.696 43.955 ;
     RECT  39.504 43.283 41.016 43.955 ;
     RECT  48.48 42.133 48.504 44.149 ;
     RECT  44.16 39.539 44.184 44.195 ;
     RECT  32.928 43.955 36.696 44.341 ;
     RECT  0.144 44.101 0.168 44.387 ;
     RECT  32.928 44.341 37.08 44.387 ;
     RECT  51 40.739 51.312 44.389 ;
     RECT  7.392 43.859 8.28 44.483 ;
     RECT  11.712 43.955 16.488 44.483 ;
     RECT  27.6 43.573 28.152 44.483 ;
     RECT  48.48 44.149 48.552 44.483 ;
     RECT  9.408 43.283 10.056 44.531 ;
     RECT  7.392 44.483 8.112 44.627 ;
     RECT  23.376 43.523 24.312 44.627 ;
     RECT  28.128 44.483 28.152 44.629 ;
     RECT  29.4 43.379 31.224 44.629 ;
     RECT  64.608 44.533 64.632 44.723 ;
     RECT  45.6 43.859 45.912 44.725 ;
     RECT  50.736 44.389 51.312 44.725 ;
     RECT  28.128 44.629 31.224 44.771 ;
     RECT  16.464 44.483 16.488 44.915 ;
     RECT  34.416 44.387 37.08 44.915 ;
     RECT  32.928 44.387 33.288 44.965 ;
     RECT  48.48 44.483 48.504 44.965 ;
     RECT  36.576 44.915 37.08 45.011 ;
     RECT  47.76 44.965 48.504 45.011 ;
     RECT  29.4 44.771 31.224 45.155 ;
     RECT  38.448 43.283 38.472 45.395 ;
     RECT  59.616 44.437 59.64 45.395 ;
     RECT  28.128 44.771 28.152 45.541 ;
     RECT  17.568 43.523 18.912 45.635 ;
     RECT  25.344 43.523 25.368 45.635 ;
     RECT  45.6 44.725 46.248 45.635 ;
     RECT  55.44 43.813 57.384 45.635 ;
     RECT  11.712 44.483 15.384 45.731 ;
     RECT  39.504 43.955 40.512 45.733 ;
     RECT  34.8 44.915 35.208 45.971 ;
     RECT  16.416 45.445 16.44 46.211 ;
     RECT  32.496 44.965 33.288 46.211 ;
     RECT  47.76 45.011 47.784 46.211 ;
     RECT  36.576 45.011 36.888 46.357 ;
     RECT  38.544 45.733 40.512 46.357 ;
     RECT  36.576 46.357 40.512 46.499 ;
     RECT  44.256 44.965 44.28 46.499 ;
     RECT  22.176 45.541 22.2 46.547 ;
     RECT  4.8 44.725 4.824 46.787 ;
     RECT  6.576 45.541 6.6 46.787 ;
     RECT  47.28 46.261 47.304 46.787 ;
     RECT  49.92 44.725 51.312 46.787 ;
     RECT  56.208 45.635 57.384 46.787 ;
     RECT  11.712 45.731 12.216 47.077 ;
     RECT  13.2 45.731 15.384 47.077 ;
     RECT  34.8 45.971 35.112 47.077 ;
     RECT  36.864 46.499 40.512 47.123 ;
     RECT  7.8 44.627 8.112 47.125 ;
     RECT  10.032 44.531 10.056 47.125 ;
     RECT  32.928 46.211 33.288 47.221 ;
     RECT  2.4 36.563 2.712 47.269 ;
     RECT  27.792 45.541 28.152 47.269 ;
     RECT  9.12 47.125 10.056 47.315 ;
     RECT  30.96 45.155 31.224 47.317 ;
     RECT  20.304 43.333 20.52 47.363 ;
     RECT  30.816 47.317 31.224 47.411 ;
     RECT  27.456 47.269 28.152 47.747 ;
     RECT  32.928 47.221 33.336 47.797 ;
     RECT  50.832 46.787 51.312 47.845 ;
     RECT  25.824 47.221 25.848 47.987 ;
     RECT  29.4 45.155 29.712 48.421 ;
     RECT  36.864 47.123 36.888 48.421 ;
     RECT  38.544 47.123 40.512 48.421 ;
     RECT  38.544 48.421 40.776 48.517 ;
     RECT  7.392 47.125 8.112 48.659 ;
     RECT  22.224 47.845 22.248 48.659 ;
     RECT  10.032 47.315 10.056 48.805 ;
     RECT  30.816 47.411 30.984 48.805 ;
     RECT  17.184 47.845 17.208 48.949 ;
     RECT  53.52 43.571 53.544 48.949 ;
     RECT  56.4 46.787 57.384 48.949 ;
     RECT  17.088 48.949 17.208 48.995 ;
     RECT  11.712 47.077 15.384 48.997 ;
     RECT  36.672 48.421 36.888 48.997 ;
     RECT  50.784 47.845 51.312 49.045 ;
     RECT  17.088 48.995 17.112 49.091 ;
     RECT  11.664 48.997 15.384 49.093 ;
     RECT  36.672 48.997 37.032 49.139 ;
     RECT  50.784 49.045 51.432 49.429 ;
     RECT  52.512 46.261 52.536 49.429 ;
     RECT  11.664 49.093 15.72 49.475 ;
     RECT  29.28 48.421 29.712 49.477 ;
     RECT  30.816 48.805 31.56 49.477 ;
     RECT  50.784 49.429 52.536 49.525 ;
     RECT  11.664 49.475 15.384 49.571 ;
     RECT  47.232 47.845 47.256 49.571 ;
     RECT  2.4 47.269 3.528 49.619 ;
     RECT  36.672 49.139 36.888 49.619 ;
     RECT  55.68 48.949 57.384 49.619 ;
     RECT  29.28 49.477 31.56 49.813 ;
     RECT  32.928 47.797 33.672 49.813 ;
     RECT  38.544 48.517 41.64 49.859 ;
     RECT  18.192 45.635 18.912 50.005 ;
     RECT  20.304 47.363 20.328 50.005 ;
     RECT  9.648 48.805 10.056 50.147 ;
     RECT  29.28 49.813 33.672 50.195 ;
     RECT  36.864 49.619 36.888 50.197 ;
     RECT  18.192 50.005 20.328 50.291 ;
     RECT  28.128 47.747 28.152 50.339 ;
     RECT  38.736 49.859 41.64 50.339 ;
     RECT  50.736 49.525 52.536 50.339 ;
     RECT  31.968 50.195 33.672 50.483 ;
     RECT  53.52 48.949 53.592 50.485 ;
     RECT  11.712 49.571 15.384 50.677 ;
     RECT  36.864 50.197 37.032 50.771 ;
     RECT  44.448 50.677 44.472 50.821 ;
     RECT  45.6 45.635 45.912 50.821 ;
     RECT  44.448 50.821 45.912 50.867 ;
     RECT  39.36 50.339 41.64 50.917 ;
     RECT  10.032 50.147 10.056 51.059 ;
     RECT  32.928 50.483 33.672 51.059 ;
     RECT  24 44.627 24.312 51.061 ;
     RECT  7.68 48.659 8.112 51.109 ;
     RECT  11.376 50.677 15.384 51.251 ;
     RECT  56.4 49.619 57.384 51.253 ;
     RECT  53.52 50.485 53.736 51.299 ;
     RECT  44.976 50.867 45.912 51.395 ;
     RECT  34.656 47.077 35.112 51.541 ;
     RECT  39.36 50.917 41.784 51.541 ;
     RECT  38.448 51.541 41.784 51.635 ;
     RECT  32.928 51.059 33.576 51.683 ;
     RECT  34.656 51.541 35.208 51.683 ;
     RECT  43.392 49.381 43.416 51.829 ;
     RECT  36.864 50.771 36.888 51.877 ;
     RECT  7.68 51.109 8.52 51.923 ;
     RECT  23.184 51.061 24.312 51.923 ;
     RECT  41.76 51.635 41.784 51.923 ;
     RECT  11.376 51.251 12.216 52.165 ;
     RECT  7.68 51.923 8.112 52.211 ;
     RECT  29.28 50.195 30.984 52.211 ;
     RECT  10.512 52.165 12.216 52.357 ;
     RECT  13.2 51.251 15.384 52.357 ;
     RECT  36.864 51.877 37.032 52.357 ;
     RECT  36.816 52.357 37.032 52.451 ;
     RECT  56.304 51.253 57.384 52.451 ;
     RECT  51 50.339 52.536 52.453 ;
     RECT  10.512 52.357 15.384 52.499 ;
     RECT  33.168 51.683 33.576 52.645 ;
     RECT  47.088 52.405 47.112 52.693 ;
     RECT  47.088 52.693 47.784 52.739 ;
     RECT  33.12 52.645 33.576 52.931 ;
     RECT  36.816 52.451 36.84 52.981 ;
     RECT  38.448 51.635 40.776 52.981 ;
     RECT  45.6 51.395 45.912 52.981 ;
     RECT  10.512 52.499 15.096 53.027 ;
     RECT  33.264 52.931 33.576 53.075 ;
     RECT  37.872 52.981 40.776 53.075 ;
     RECT  47.76 52.739 47.784 53.075 ;
     RECT  36.768 52.981 36.84 53.123 ;
     RECT  2.4 49.619 2.712 53.221 ;
     RECT  43.344 51.829 43.416 53.267 ;
     RECT  2.4 53.221 2.856 53.363 ;
     RECT  20.304 50.291 20.328 53.557 ;
     RECT  23.376 51.923 24.312 53.557 ;
     RECT  11.712 53.027 15.096 53.603 ;
     RECT  50.256 52.453 52.536 53.603 ;
     RECT  55.104 53.269 55.128 53.603 ;
     RECT  23.376 53.557 24.408 53.845 ;
     RECT  25.632 53.797 25.656 53.845 ;
     RECT  18.192 50.291 18.912 53.939 ;
     RECT  23.376 53.845 25.656 53.987 ;
     RECT  24 53.987 25.656 54.083 ;
     RECT  10.512 53.027 10.536 54.085 ;
     RECT  39.504 53.075 40.776 54.085 ;
     RECT  36.768 53.123 36.792 54.131 ;
     RECT  43.392 53.267 43.416 54.133 ;
     RECT  43.392 54.133 43.848 54.179 ;
     RECT  53.52 51.299 53.544 54.179 ;
     RECT  45.504 52.981 45.912 54.227 ;
     RECT  27.072 53.797 27.096 54.323 ;
     RECT  5.664 51.781 5.688 54.371 ;
     RECT  45.6 54.227 45.912 54.469 ;
     RECT  56.4 52.451 57.384 54.469 ;
     RECT  19.92 53.557 20.328 54.515 ;
     RECT  29.28 52.211 29.712 54.661 ;
     RECT  43.824 54.179 43.848 54.661 ;
     RECT  24 54.083 24.408 54.707 ;
     RECT  50.256 53.603 51.576 54.707 ;
     RECT  25.584 54.083 25.656 54.755 ;
     RECT  33.264 53.075 33.336 54.805 ;
     RECT  10.224 54.085 10.536 54.899 ;
     RECT  11.712 53.603 12.024 54.899 ;
     RECT  39.456 54.085 41.64 54.947 ;
     RECT  13.2 53.603 15.096 55.091 ;
     RECT  22.752 53.989 22.776 55.139 ;
     RECT  30.96 52.211 30.984 55.283 ;
     RECT  37.872 53.075 38.472 55.283 ;
     RECT  56.4 54.469 57.432 55.283 ;
     RECT  4.704 54.949 4.728 55.427 ;
     RECT  43.824 54.661 44.472 55.525 ;
     RECT  43.776 55.525 44.472 55.571 ;
     RECT  33.216 54.805 33.336 55.667 ;
     RECT  7.8 52.211 8.112 55.813 ;
     RECT  38.448 55.283 38.472 55.813 ;
     RECT  39.456 54.947 40.776 55.813 ;
     RECT  45.6 54.469 46.392 55.907 ;
     RECT  43.776 55.571 43.848 56.099 ;
     RECT  13.2 55.091 13.608 56.149 ;
     RECT  24 54.707 24.312 56.341 ;
     RECT  25.584 54.755 25.608 56.341 ;
     RECT  16.32 55.237 16.344 56.483 ;
     RECT  43.776 56.099 43.8 56.483 ;
     RECT  58.704 52.309 58.728 56.483 ;
     RECT  13.2 56.149 13.704 56.485 ;
     RECT  10.512 54.899 10.536 56.531 ;
     RECT  38.448 55.813 40.776 56.531 ;
     RECT  7.392 55.813 8.112 56.579 ;
     RECT  9.408 55.525 9.432 56.579 ;
     RECT  38.448 56.531 40.632 56.627 ;
     RECT  28.464 54.661 29.712 56.771 ;
     RECT  14.976 55.091 15.096 56.869 ;
     RECT  39.312 56.627 40.632 57.011 ;
     RECT  18.6 53.939 18.912 57.157 ;
     RECT  20.304 54.515 20.328 57.157 ;
     RECT  11.712 54.899 11.736 57.347 ;
     RECT  51 54.707 51.576 57.541 ;
     RECT  24 56.341 25.608 57.587 ;
     RECT  39.312 57.011 40.512 57.587 ;
     RECT  25.584 57.587 25.608 57.635 ;
     RECT  42.048 55.957 42.072 57.635 ;
     RECT  14.976 56.869 15.72 58.115 ;
     RECT  40.2 57.587 40.512 58.117 ;
     RECT  18.6 57.157 20.328 58.163 ;
     RECT  54.72 55.813 54.744 58.163 ;
     RECT  13.2 56.485 13.896 58.739 ;
     RECT  20.304 58.163 20.328 58.739 ;
     RECT  40.2 58.117 40.632 58.739 ;
     RECT  22.464 58.117 22.488 58.931 ;
     RECT  50.16 57.541 51.576 58.931 ;
     RECT  33.264 55.667 33.336 59.219 ;
     RECT  53.04 57.589 53.064 59.221 ;
     RECT  27.696 58.645 27.72 59.267 ;
     RECT  37.2 55.957 37.224 59.269 ;
     RECT  30.912 58.645 30.936 59.315 ;
     RECT  37.2 59.269 37.944 59.315 ;
     RECT  50.688 58.931 51.576 59.315 ;
     RECT  14.976 58.115 15 59.459 ;
     RECT  53.04 59.221 54.024 59.507 ;
     RECT  56.4 55.283 57.384 59.749 ;
     RECT  11.952 57.541 11.976 59.845 ;
     RECT  13.2 58.739 13.512 59.845 ;
     RECT  26.112 58.693 26.136 59.987 ;
     RECT  54 59.507 54.024 60.037 ;
     RECT  13.104 59.845 13.512 60.227 ;
     RECT  11.184 59.845 11.976 60.275 ;
     RECT  37.92 59.315 37.944 60.275 ;
     RECT  50.688 59.315 51.312 60.275 ;
     RECT  60.336 58.549 60.36 60.373 ;
     RECT  54 60.037 54.84 60.419 ;
     RECT  54.816 60.419 54.84 60.467 ;
     RECT  11.184 60.275 11.208 60.563 ;
     RECT  15.216 59.749 15.24 60.851 ;
     RECT  37.872 60.373 37.896 61.043 ;
     RECT  22.416 60.037 22.44 61.381 ;
     RECT  33.312 59.219 33.336 61.573 ;
     RECT  34.656 51.683 35.112 61.573 ;
     RECT  56.4 59.749 57.576 61.573 ;
     RECT  60.192 60.373 60.36 61.573 ;
     RECT  33.312 61.573 33.48 61.619 ;
     RECT  21.024 60.085 21.048 61.621 ;
     RECT  22.32 61.381 22.44 61.621 ;
     RECT  33.456 61.619 33.48 61.717 ;
     RECT  34.656 61.573 36.072 61.717 ;
     RECT  56.4 61.573 57.672 62.005 ;
     RECT  18.6 58.163 18.912 62.149 ;
     RECT  20.016 62.101 20.04 62.149 ;
     RECT  21.024 61.621 22.44 62.149 ;
     RECT  33.456 61.717 36.072 62.149 ;
     RECT  55.536 62.005 57.672 62.149 ;
     RECT  18.192 62.149 22.44 62.293 ;
     RECT  24 57.587 24.312 62.293 ;
     RECT  18.192 62.293 22.632 62.341 ;
     RECT  54.864 62.149 57.672 62.389 ;
     RECT  58.896 62.341 58.92 62.389 ;
     RECT  15.504 62.149 16.488 62.437 ;
     RECT  18 62.341 22.632 62.437 ;
     RECT  15.504 62.437 22.632 62.581 ;
     RECT  24 62.293 25.176 62.581 ;
     RECT  13.2 60.227 13.512 62.629 ;
     RECT  14.736 62.581 22.632 62.629 ;
     RECT  33.456 62.149 38.664 62.629 ;
     RECT  2.4 53.363 2.712 62.649 ;
     RECT  7.8 56.579 8.112 62.649 ;
     RECT  24 62.581 25.272 62.649 ;
     RECT  29.4 56.771 29.712 62.649 ;
     RECT  40.2 58.739 40.512 62.649 ;
     RECT  45.6 55.907 45.912 62.649 ;
     RECT  51 60.275 51.312 62.649 ;
     RECT  61.8 34.355 62.112 62.649 ;
     RECT  2.4 62.649 2.52 62.663 ;
     RECT  7.8 62.649 7.92 62.663 ;
     RECT  13.2 62.629 22.632 62.663 ;
     RECT  24 62.649 24.12 62.663 ;
     RECT  29.4 62.649 29.52 62.663 ;
     RECT  40.2 62.649 40.32 62.663 ;
     RECT  45.6 62.649 45.72 62.663 ;
     RECT  51 62.649 51.12 62.663 ;
     RECT  61.8 62.649 61.92 62.663 ;
     RECT  13.488 62.663 22.632 62.675 ;
     RECT  32.976 62.629 38.664 62.677 ;
     RECT  54.864 62.389 58.92 62.725 ;
     RECT  60.192 61.573 60.456 62.725 ;
     RECT  32.976 62.677 38.76 62.819 ;
     RECT  25.104 62.649 25.272 63.157 ;
     RECT  32.976 62.819 38.664 63.205 ;
     RECT  54.864 62.725 60.456 63.205 ;
     RECT  32.688 63.205 38.664 63.253 ;
     RECT  54.864 63.205 60.84 63.253 ;
     RECT  54.816 63.253 60.84 63.827 ;
     RECT  13.488 62.675 22.536 63.829 ;
     RECT  25.104 63.157 25.32 63.829 ;
     RECT  54.864 63.827 60.84 63.829 ;
     RECT  25.008 63.829 25.32 64.549 ;
     RECT  25.008 64.549 25.512 64.645 ;
     RECT  13.392 63.829 22.536 64.784 ;
     RECT  25.008 64.645 25.608 64.784 ;
     RECT  32.592 63.253 38.664 64.784 ;
     RECT  54.864 63.829 60.936 64.784 ;
  END
END ot_hgi_b2_swap_disp_t
END LIBRARY
